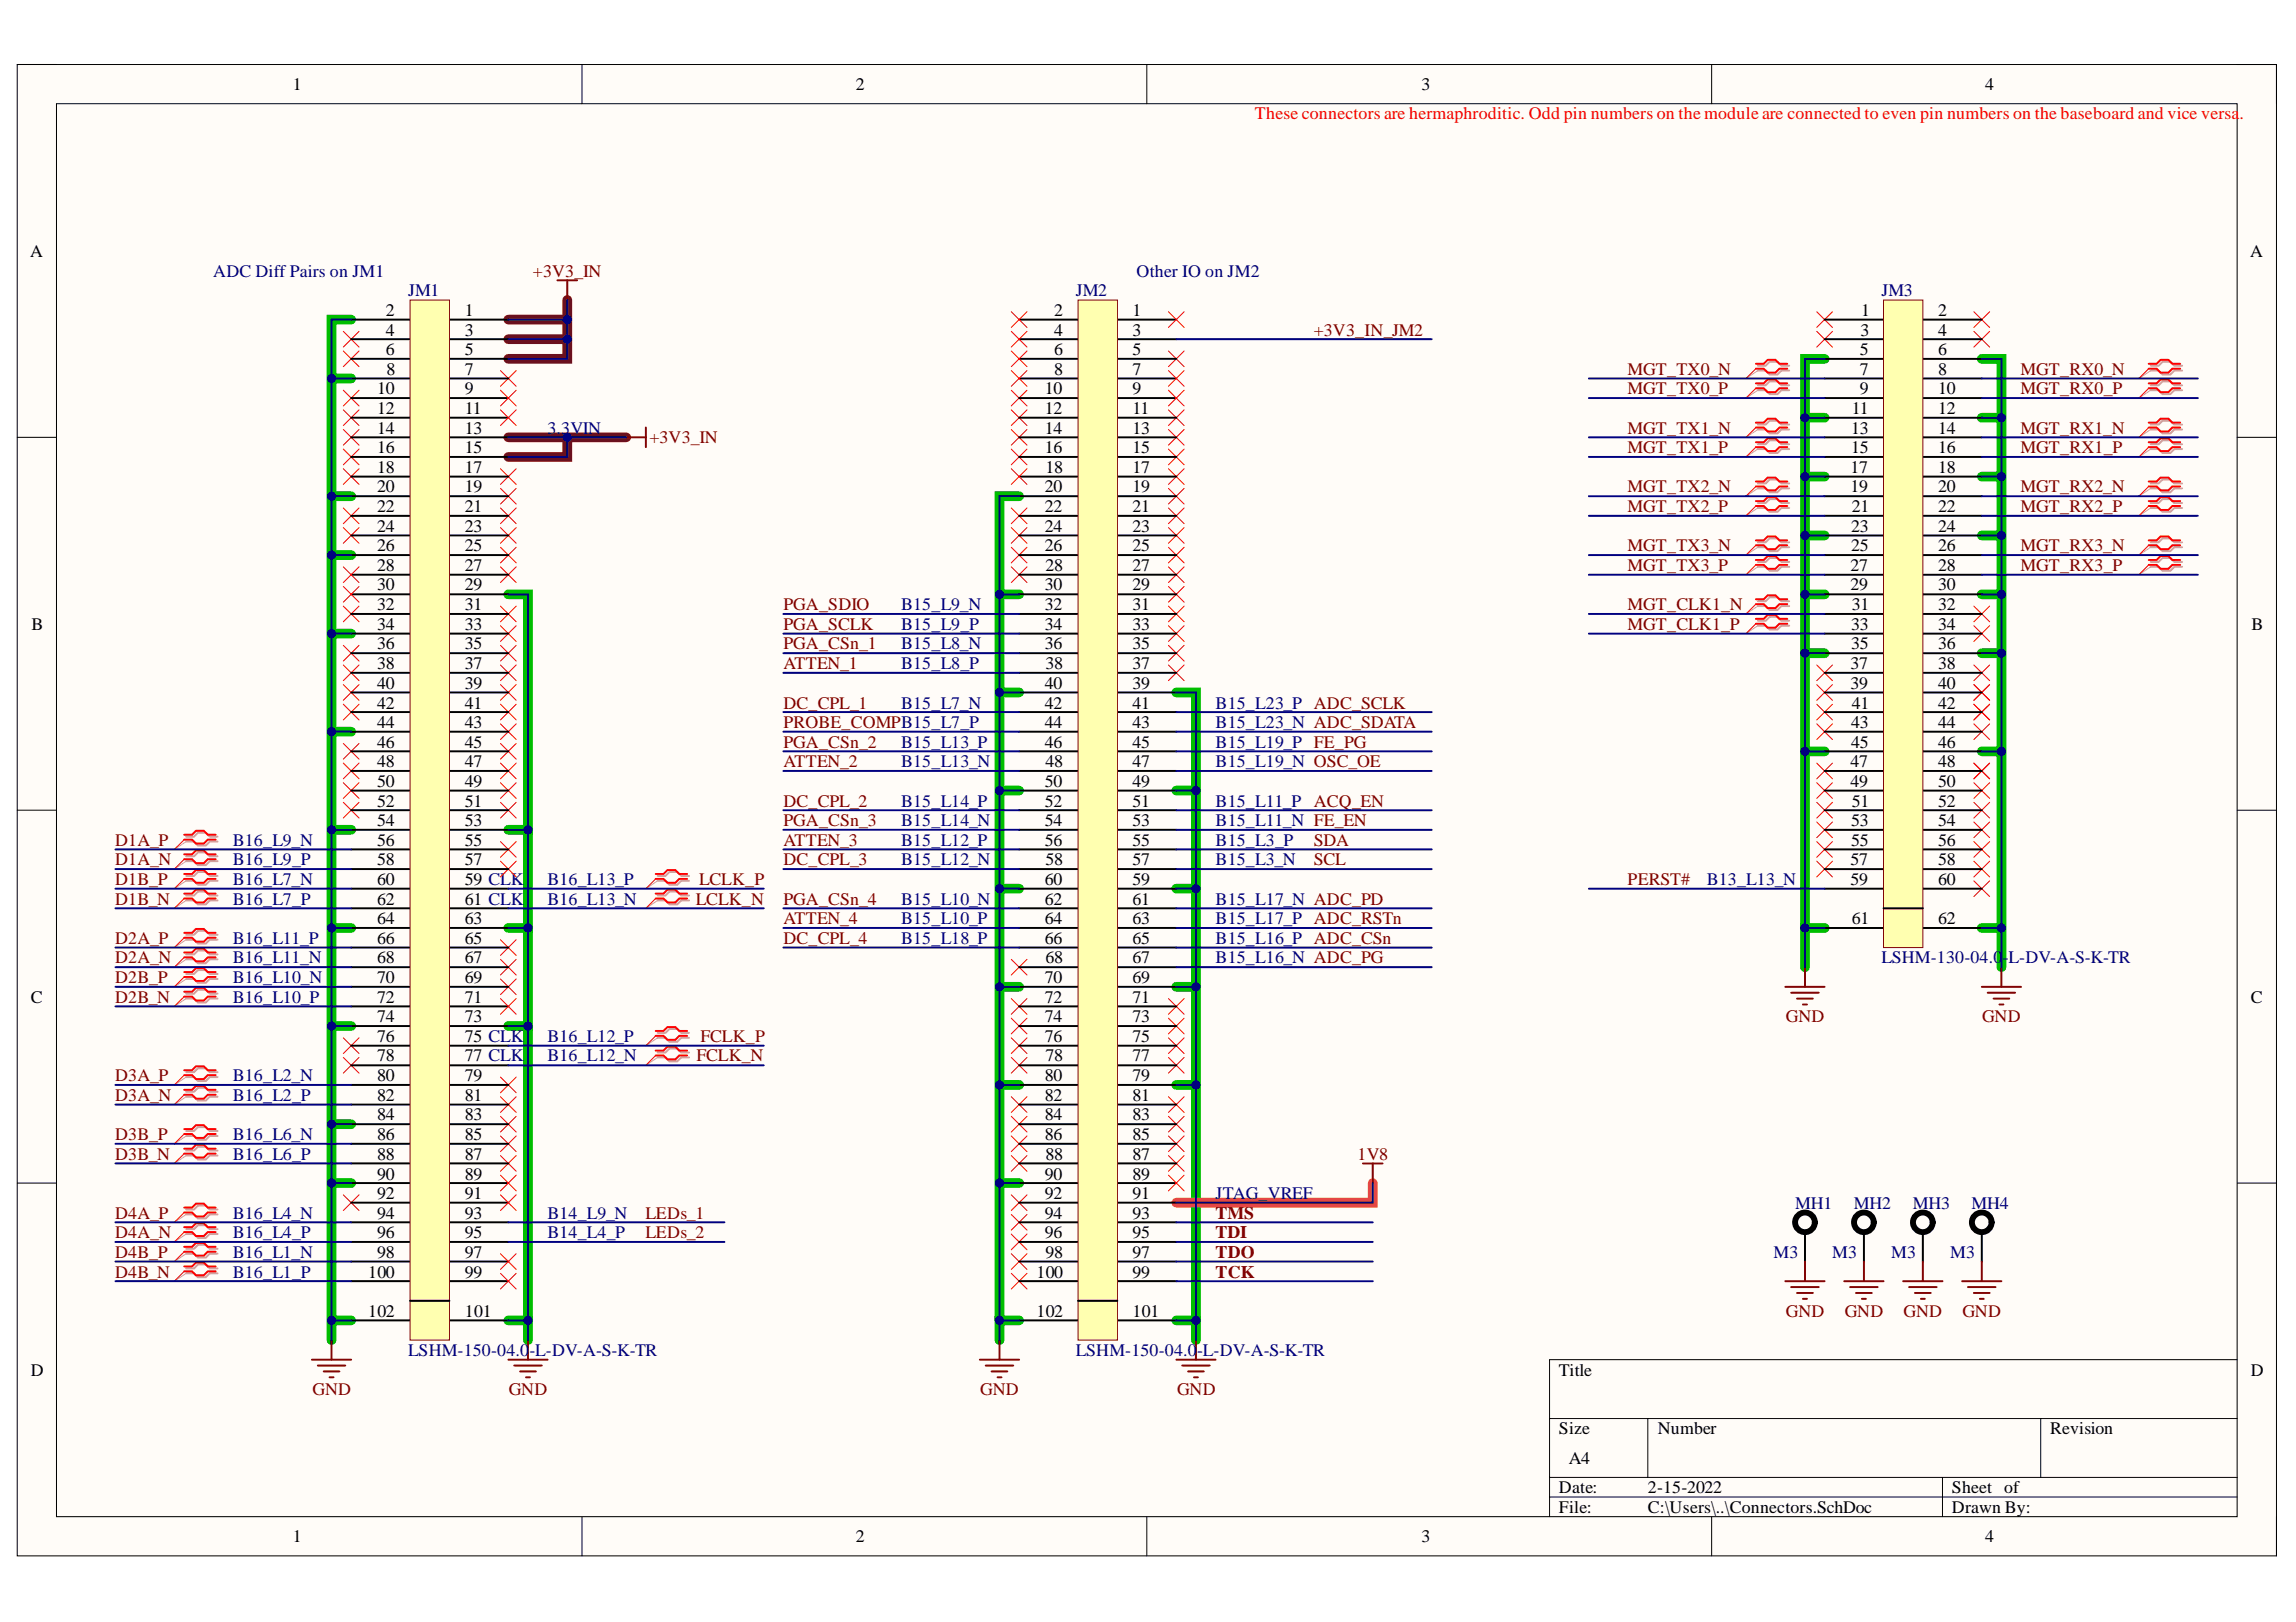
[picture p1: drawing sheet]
<svg xmlns="http://www.w3.org/2000/svg" width="297mm" height="210mm" viewBox="0 0 297 210" stroke-linecap="round" stroke-linejoin="round" font-family="sans-serif">
<defs><g id="words">
<g font-size="2.3">
<text x="37.9" y="11.7">1</text>
<text x="110.7" y="11.7">2</text>
<text x="183.9" y="11.7">3</text>
<text x="256.8" y="11.7">4</text>
<text x="3.9" y="33.3">A</text>
<text x="291.1" y="33.3">A</text>
<text x="49.9" y="40.9">2</text>
<text x="60.2" y="40.9">1</text>
<text x="136.4" y="40.9">2</text>
<text x="146.5" y="40.9">1</text>
<text x="240.8" y="40.9">1</text>
<text x="250.8" y="40.9">2</text>
<text x="49.9" y="43.4">4</text>
<text x="49.9" y="46">6</text>
<text x="60.2" y="43.4">3</text>
<text x="60.2" y="46">5</text>
<text x="136.4" y="43.4">4</text>
<text x="136.4" y="46">6</text>
<text x="146.5" y="43.4">3</text>
<text x="146.5" y="46">5</text>
<text x="240.6" y="46">5</text>
<text x="240.7" y="43.4">3</text>
<text x="250.8" y="43.4">4</text>
<text x="250.8" y="46">6</text>
<text x="48.8" y="51">10</text>
<text x="48.8" y="53.6">12</text>
<text x="50" y="48.5">8</text>
<text x="60.2" y="48.5">7</text>
<text x="60.2" y="51">9</text>
<text x="60.2" y="53.6">11</text>
<text x="135.2" y="51">10</text>
<text x="135.2" y="53.6">12</text>
<text x="136.4" y="48.5">8</text>
<text x="146.5" y="48.5">7</text>
<text x="146.5" y="51">9</text>
<text x="146.5" y="53.6">11</text>
<text x="239.6" y="53.6">11</text>
<text x="240.6" y="48.5">7</text>
<text x="240.6" y="51">9</text>
<text x="250.8" y="48.5">8</text>
<text x="250.8" y="51">10</text>
<text x="250.8" y="53.6">12</text>
<text x="48.8" y="56.1">14</text>
<text x="48.8" y="58.7">16</text>
<text x="60.2" y="56.1">13</text>
<text x="60.2" y="58.7">15</text>
<text x="135.2" y="56.1">14</text>
<text x="135.2" y="58.7">16</text>
<text x="146.5" y="56.1">13</text>
<text x="146.5" y="58.7">15</text>
<text x="239.5" y="56.1">13</text>
<text x="239.5" y="58.7">15</text>
<text x="250.8" y="56.1">14</text>
<text x="250.8" y="58.7">16</text>
<text x="48.8" y="61.2">18</text>
<text x="48.8" y="63.7">20</text>
<text x="60.2" y="61.2">17</text>
<text x="60.2" y="63.7">19</text>
<text x="135.2" y="63.7">20</text>
<text x="135.3" y="61.2">18</text>
<text x="146.5" y="61.2">17</text>
<text x="146.5" y="63.7">19</text>
<text x="239.4" y="61.2">17</text>
<text x="239.4" y="63.7">19</text>
<text x="250.8" y="61.2">18</text>
<text x="250.8" y="63.7">20</text>
<text x="48.8" y="66.3">22</text>
<text x="48.8" y="68.8">24</text>
<text x="48.8" y="71.3">26</text>
<text x="60.2" y="66.3">21</text>
<text x="60.2" y="68.8">23</text>
<text x="60.2" y="71.3">25</text>
<text x="135.2" y="66.3">22</text>
<text x="135.2" y="68.8">24</text>
<text x="135.2" y="71.3">26</text>
<text x="146.5" y="66.3">21</text>
<text x="146.5" y="68.8">23</text>
<text x="146.5" y="71.3">25</text>
<text x="239.5" y="68.8">23</text>
<text x="239.5" y="71.3">25</text>
<text x="239.6" y="66.3">21</text>
<text x="250.8" y="66.3">22</text>
<text x="250.8" y="68.8">24</text>
<text x="250.8" y="71.3">26</text>
<text x="48.8" y="73.9">28</text>
<text x="48.8" y="76.4">30</text>
<text x="60.2" y="73.9">27</text>
<text x="60.2" y="76.4">29</text>
<text x="135.2" y="76.4">30</text>
<text x="135.3" y="73.9">28</text>
<text x="146.5" y="73.9">27</text>
<text x="146.5" y="76.4">29</text>
<text x="239.4" y="73.9">27</text>
<text x="239.4" y="76.4">29</text>
<text x="250.8" y="73.9">28</text>
<text x="250.8" y="76.4">30</text>
<text x="4.1" y="81.5">B</text>
<text x="48.8" y="78.9">32</text>
<text x="48.8" y="81.5">34</text>
<text x="60.2" y="78.9">31</text>
<text x="60.2" y="81.5">33</text>
<text x="135.2" y="78.9">32</text>
<text x="135.2" y="81.5">34</text>
<text x="146.5" y="78.9">31</text>
<text x="146.5" y="81.5">33</text>
<text x="239.5" y="81.5">33</text>
<text x="239.6" y="78.9">31</text>
<text x="250.8" y="78.9">32</text>
<text x="250.8" y="81.5">34</text>
<text x="291.3" y="81.5">B</text>
<text x="48.8" y="84">36</text>
<text x="48.8" y="86.6">38</text>
<text x="48.8" y="89.2">40</text>
<text x="60.2" y="84">35</text>
<text x="60.2" y="86.6">37</text>
<text x="60.2" y="89.2">39</text>
<text x="135.2" y="84">36</text>
<text x="135.2" y="89.2">40</text>
<text x="135.3" y="86.6">38</text>
<text x="146.5" y="84">35</text>
<text x="146.5" y="86.6">37</text>
<text x="146.5" y="89.2">39</text>
<text x="239.4" y="86.6">37</text>
<text x="239.4" y="89.2">39</text>
<text x="239.5" y="84">35</text>
<text x="250.8" y="84">36</text>
<text x="250.8" y="86.6">38</text>
<text x="250.8" y="89.2">40</text>
<text x="48.8" y="91.7">42</text>
<text x="48.8" y="94.2">44</text>
<text x="60.2" y="91.7">41</text>
<text x="60.2" y="94.2">43</text>
<text x="135.2" y="91.7">42</text>
<text x="135.2" y="94.2">44</text>
<text x="146.5" y="91.7">41</text>
<text x="146.5" y="94.2">43</text>
<text x="239.5" y="94.2">43</text>
<text x="239.6" y="91.7">41</text>
<text x="250.8" y="91.7">42</text>
<text x="250.8" y="94.2">44</text>
<text x="48.8" y="96.8">46</text>
<text x="48.8" y="99.3">48</text>
<text x="48.8" y="101.9">50</text>
<text x="60.2" y="96.8">45</text>
<text x="60.2" y="99.3">47</text>
<text x="60.2" y="101.9">49</text>
<text x="135.2" y="96.8">46</text>
<text x="135.2" y="101.9">50</text>
<text x="135.3" y="99.3">48</text>
<text x="146.5" y="96.8">45</text>
<text x="146.5" y="99.3">47</text>
<text x="146.5" y="101.9">49</text>
<text x="239.4" y="99.3">47</text>
<text x="239.4" y="101.9">49</text>
<text x="239.5" y="96.8">45</text>
<text x="250.8" y="96.8">46</text>
<text x="250.8" y="99.3">48</text>
<text x="250.8" y="101.9">50</text>
<text x="48.8" y="104.4">52</text>
<text x="48.8" y="106.9">54</text>
<text x="60.2" y="104.4">51</text>
<text x="60.2" y="106.9">53</text>
<text x="135.2" y="104.4">52</text>
<text x="135.2" y="106.9">54</text>
<text x="146.5" y="104.4">51</text>
<text x="146.5" y="106.9">53</text>
<text x="239.5" y="106.9">53</text>
<text x="239.6" y="104.4">51</text>
<text x="250.8" y="104.4">52</text>
<text x="250.8" y="106.9">54</text>
<text x="48.8" y="109.5">56</text>
<text x="48.8" y="112">58</text>
<text x="60.2" y="109.5">55</text>
<text x="60.2" y="112">57</text>
<text x="135.2" y="109.5">56</text>
<text x="135.3" y="112">58</text>
<text x="146.5" y="109.5">55</text>
<text x="146.5" y="112">57</text>
<text x="239.4" y="112">57</text>
<text x="239.5" y="109.5">55</text>
<text x="250.8" y="109.5">56</text>
<text x="250.8" y="112">58</text>
<text x="48.8" y="114.5">60</text>
<text x="48.8" y="117.1">62</text>
<text x="48.8" y="119.6">64</text>
<text x="60.2" y="114.5">59 CLK</text>
<text x="60.2" y="117.1">61 CLK</text>
<text x="60.2" y="119.6">63</text>
<text x="135.2" y="114.5">60</text>
<text x="135.2" y="117.1">62</text>
<text x="135.2" y="119.6">64</text>
<text x="146.5" y="114.5">59</text>
<text x="146.5" y="117.1">61</text>
<text x="146.5" y="119.6">63</text>
<text x="239.4" y="114.5">59</text>
<text x="239.6" y="119.6">61</text>
<text x="250.8" y="114.5">60</text>
<text x="250.8" y="119.6">62</text>
<text x="48.8" y="122.1">66</text>
<text x="48.8" y="124.7">68</text>
<text x="60.2" y="122.1">65</text>
<text x="60.2" y="124.7">67</text>
<text x="135.2" y="122.1">66</text>
<text x="135.3" y="124.7">68</text>
<text x="146.5" y="122.1">65</text>
<text x="146.5" y="124.7">67</text>
<text x="4" y="129.7">C</text>
<text x="48.8" y="127.2">70</text>
<text x="48.8" y="129.7">72</text>
<text x="60.2" y="127.2">69</text>
<text x="60.2" y="129.7">71</text>
<text x="135.2" y="127.2">70</text>
<text x="135.2" y="129.7">72</text>
<text x="146.5" y="127.2">69</text>
<text x="146.5" y="129.7">71</text>
<text x="291.2" y="129.7">C</text>
<text x="48.8" y="132.3">74</text>
<text x="48.8" y="134.8">76</text>
<text x="48.8" y="137.4">78</text>
<text x="60.2" y="132.3">73</text>
<text x="60.2" y="134.8">75 CLK</text>
<text x="60.2" y="137.4">77 CLK</text>
<text x="135.2" y="132.3">74</text>
<text x="135.2" y="134.8">76</text>
<text x="135.3" y="137.4">78</text>
<text x="146.5" y="132.3">73</text>
<text x="146.5" y="134.8">75</text>
<text x="146.5" y="137.4">77</text>
<text x="48.8" y="139.9">80</text>
<text x="48.8" y="142.4">82</text>
<text x="60.2" y="139.9">79</text>
<text x="60.2" y="142.4">81</text>
<text x="135.2" y="139.9">80</text>
<text x="135.2" y="142.4">82</text>
<text x="146.5" y="139.9">79</text>
<text x="146.5" y="142.4">81</text>
<text x="48.8" y="145">84</text>
<text x="48.8" y="147.5">86</text>
<text x="60.2" y="145">83</text>
<text x="60.2" y="147.5">85</text>
<text x="135.2" y="145">84</text>
<text x="135.2" y="147.5">86</text>
<text x="146.5" y="145">83</text>
<text x="146.5" y="147.5">85</text>
<text x="48.8" y="150.1">88</text>
<text x="48.8" y="152.7">90</text>
<text x="48.8" y="155.2">92</text>
<text x="60.2" y="150.1">87</text>
<text x="60.2" y="152.7">89</text>
<text x="60.2" y="155.2">91</text>
<text x="135.2" y="152.7">90</text>
<text x="135.2" y="155.2">92</text>
<text x="135.3" y="150.1">88</text>
<text x="146.5" y="150.1">87</text>
<text x="146.5" y="152.7">89</text>
<text x="146.5" y="155.2">91</text>
<text x="48.8" y="157.7">94</text>
<text x="48.8" y="160.3">96</text>
<text x="60.2" y="157.7">93</text>
<text x="60.2" y="160.3">95</text>
<text x="135.2" y="157.7">94</text>
<text x="135.2" y="160.3">96</text>
<text x="146.5" y="157.7">93</text>
<text x="146.5" y="160.3">95</text>
<text x="47.6" y="165.3">100</text>
<text x="48.8" y="162.8">98</text>
<text x="60.2" y="162.8">97</text>
<text x="60.2" y="165.3">99</text>
<text x="134.1" y="165.3">100</text>
<text x="135.3" y="162.8">98</text>
<text x="146.5" y="162.8">97</text>
<text x="146.5" y="165.3">99</text>
<text x="47.6" y="170.4">102</text>
<text x="60.2" y="170.4">101</text>
<text x="134.1" y="170.4">102</text>
<text x="146.5" y="170.4">101</text>
<text x="4" y="178">D</text>
<text x="201.7" y="178">Title</text>
<text x="291.2" y="178">D</text>
<text x="201.7" y="185.6">Size</text>
<text x="214.5" y="185.6">Number</text>
<text x="265.2" y="185.6">Revision</text>
<text x="203" y="189.4">A4</text>
<text x="201.7" y="193.2">Date:</text>
<text x="201.7" y="195.8">File:</text>
<text x="213.2" y="193.2">2-15-2022</text>
<text x="213.2" y="195.8">C:\Users\..\Connectors.SchDoc</text>
<text x="252.5" y="193.2">Sheet of</text>
<text x="252.5" y="195.8">Drawn By:</text>
<text x="37.9" y="199.6">1</text>
<text x="110.7" y="199.6">2</text>
<text x="183.9" y="199.6">3</text>
<text x="256.8" y="199.6">4</text>
</g>
<text font-size="2.3" fill="#f00" x="162.3" y="15.5">These connectors are hermaphroditic. Odd pin numbers on the module are connected to even pin numbers on the baseboard and vice versa.</text>
<g font-size="2.3" fill="#000080">
<text x="27.6" y="35.8">ADC Diff Pairs on JM1</text>
<text x="147" y="35.8">Other IO on JM2</text>
<text x="52.8" y="38.4">JM1</text>
<text x="139.2" y="38.4">JM2</text>
<text x="243.4" y="38.4">JM3</text>
<text x="70.8" y="56.1">3.3VIN</text>
<text x="116.6" y="78.9">B15_L9_N</text>
<text x="116.6" y="81.5">B15_L9_P</text>
<text x="116.6" y="84">B15_L8_N</text>
<text x="116.6" y="86.6">B15_L8_P</text>
<text x="116.6" y="91.7">B15_L7_N</text>
<text x="157.3" y="91.7">B15_L23_P ADC_SCLK</text>
<text x="157.3" y="94.2">B15_L23_N ADC_SDATA</text>
<text x="116.6" y="96.8">B15_L13_P</text>
<text x="116.6" y="99.3">B15_L13_N</text>
<text x="157.3" y="96.8">B15_L19_P FE_PG</text>
<text x="157.3" y="99.3">B15_L19_N OSC_OE</text>
<text x="116.6" y="104.4">B15_L14_P</text>
<text x="116.6" y="106.9">B15_L14_N</text>
<text x="157.3" y="104.4">B15_L11_P ACQ_EN</text>
<text x="157.3" y="106.9">B15_L11_N FE_EN</text>
<text x="30.1" y="109.5">B16_L9_N</text>
<text x="30.1" y="112">B16_L9_P</text>
<text x="116.6" y="109.5">B15_L12_P</text>
<text x="116.6" y="112">B15_L12_N</text>
<text x="157.3" y="109.5">B15_L3_P</text>
<text x="157.3" y="112">B15_L3_N</text>
<text x="30.1" y="114.5">B16_L7_N</text>
<text x="30.1" y="117.1">B16_L7_P</text>
<text x="70.8" y="114.5">B16_L13_P</text>
<text x="70.8" y="117.1">B16_L13_N</text>
<text x="116.6" y="117.1">B15_L10_N</text>
<text x="116.6" y="119.6">B15_L10_P</text>
<text x="157.3" y="117.1">B15_L17_N ADC_PD</text>
<text x="157.3" y="119.6">B15_L17_P ADC_RSTn</text>
<text x="220.8" y="114.5">B13_L13_N</text>
<text x="30.1" y="122.1">B16_L11_P</text>
<text x="30.1" y="124.7">B16_L11_N</text>
<text x="116.6" y="122.1">B15_L18_P</text>
<text x="157.3" y="122.1">B15_L16_P ADC_CSn</text>
<text x="157.3" y="124.7">B15_L16_N ADC_PG</text>
<text x="243.4" y="124.7">LSHM-130-04.0</text>
<text x="259.1" y="124.7">-L-DV-A-S-K-TR</text>
<text x="30.1" y="127.2">B16_L10_N</text>
<text x="30.1" y="129.7">B16_L10_P</text>
<text x="70.8" y="134.8">B16_L12_P</text>
<text x="70.8" y="137.4">B16_L12_N</text>
<text x="30.1" y="139.9">B16_L2_N</text>
<text x="30.1" y="142.4">B16_L2_P</text>
<text x="30.1" y="147.5">B16_L6_N</text>
<text x="30.1" y="150.1">B16_L6_P</text>
<text x="157.3" y="155.2">JTAG_VREF</text>
<text x="30.1" y="157.7">B16_L4_N</text>
<text x="30.1" y="160.3">B16_L4_P</text>
<text x="70.8" y="157.7">B14_L9_N</text>
<text x="70.8" y="160.3">B14_L4_P</text>
<text x="232.2" y="156.5">MH1</text>
<text x="239.8" y="156.5">MH2</text>
<text x="247.5" y="156.5">MH3</text>
<text x="255.1" y="156.5">MH4</text>
<text x="30.1" y="162.8">B16_L1_N</text>
<text x="30.1" y="165.3">B16_L1_P</text>
<text x="229.4" y="162.8">M3</text>
<text x="237" y="162.8">M3</text>
<text x="244.7" y="162.8">M3</text>
<text x="252.3" y="162.8">M3</text>
<text x="52.8" y="175.5">LSHM-150-04.0</text>
<text x="68.5" y="175.5">-L-DV-A-S-K-TR</text>
<text x="139.2" y="175.5">LSHM-150-04.0</text>
<text x="154.9" y="175.5">-L-DV-A-S-K-TR</text>
</g>
<g font-size="2.3" fill="#800000">
<text x="68.9" y="35.8">+3V3_IN</text>
<text x="170" y="43.4">+3V3_IN_JM2</text>
<text x="210.6" y="48.5">MGT_TX0_N</text>
<text x="210.6" y="51">MGT_TX0_P</text>
<text x="261.4" y="48.5">MGT_RX0_N</text>
<text x="261.4" y="51">MGT_RX0_P</text>
<text x="84" y="57.4">+3V3_IN</text>
<text x="210.6" y="56.1">MGT_TX1_N</text>
<text x="210.6" y="58.7">MGT_TX1_P</text>
<text x="261.4" y="56.1">MGT_RX1_N</text>
<text x="261.4" y="58.7">MGT_RX1_P</text>
<text x="210.6" y="63.7">MGT_TX2_N</text>
<text x="261.4" y="63.7">MGT_RX2_N</text>
<text x="210.6" y="71.3">MGT_TX3_N</text>
<text x="210.6" y="66.3">MGT_TX2_P</text>
<text x="261.4" y="66.3">MGT_RX2_P</text>
<text x="261.4" y="71.3">MGT_RX3_N</text>
<text x="210.6" y="73.9">MGT_TX3_P</text>
<text x="261.4" y="73.9">MGT_RX3_P</text>
<text x="101.4" y="78.9">PGA_SDIO</text>
<text x="101.4" y="81.5">PGA_SCLK</text>
<text x="210.6" y="78.9">MGT_CLK1_N</text>
<text x="210.6" y="81.5">MGT_CLK1_P</text>
<text x="101.4" y="84">PGA_CSn_1</text>
<text x="101.4" y="86.6">ATTEN_1</text>
<text x="101.4" y="91.7">DC_CPL_1</text>
<text x="101.4" y="94.2">PROBE_COMPB15_L7_P</text>
<text x="101.4" y="96.8">PGA_CSn_2</text>
<text x="101.4" y="99.3">ATTEN_2</text>
<text x="101.4" y="104.4">DC_CPL_2</text>
<text x="101.4" y="106.9">PGA_CSn_3</text>
<text x="14.9" y="109.5">D1A_P</text>
<text x="14.9" y="112">D1A_N</text>
<text x="101.4" y="109.5">ATTEN_3</text>
<text x="101.4" y="112">DC_CPL_3</text>
<text x="170" y="109.5">SDA</text>
<text x="170" y="112">SCL</text>
<text x="14.9" y="114.5">D1B_P</text>
<text x="14.9" y="117.1">D1B_N</text>
<text x="90" y="117.1">LCLK_N</text>
<text x="90.4" y="114.5">LCLK_P</text>
<text x="101.4" y="117.1">PGA_CSn_4</text>
<text x="101.4" y="119.6">ATTEN_4</text>
<text x="210.6" y="114.5">PERST#</text>
<text x="14.9" y="122.1">D2A_P</text>
<text x="14.9" y="124.7">D2A_N</text>
<text x="101.4" y="122.1">DC_CPL_4</text>
<text x="14.9" y="127.2">D2B_P</text>
<text x="14.9" y="129.7">D2B_N</text>
<text x="90.1" y="137.4">FCLK_N</text>
<text x="90.6" y="134.8">FCLK_P</text>
<text x="231" y="132.3">GND</text>
<text x="256.4" y="132.3">GND</text>
<text x="14.9" y="139.9">D3A_P</text>
<text x="14.9" y="142.4">D3A_N</text>
<text x="14.9" y="147.5">D3B_P</text>
<text x="14.9" y="150.1">D3B_N</text>
<text x="175.6" y="150.1">1V8</text>
<text x="14.9" y="157.7">D4A_P</text>
<text x="14.9" y="160.3">D4A_N</text>
<text x="83.5" y="157.7">LEDs_1</text>
<text x="83.5" y="160.3">LEDs_2</text>
<text x="157.3" y="160.3">TDI</text>
<text x="157.3" y="157.7">TMS</text>
<text x="14.9" y="162.8">D4B_P</text>
<text x="14.9" y="165.3">D4B_N</text>
<text x="157.3" y="165.3">TCK</text>
<text x="157.3" y="162.8">TDO</text>
<text x="231" y="170.4">GND</text>
<text x="238.7" y="170.4">GND</text>
<text x="246.3" y="170.4">GND</text>
<text x="253.9" y="170.4">GND</text>
<text x="40.4" y="180.6">GND</text>
<text x="65.8" y="180.6">GND</text>
<text x="126.8" y="180.6">GND</text>
<text x="152.3" y="180.6">GND</text>
</g>
</g></defs>
<path d="M2.2 8.3h292.3v193h-292.3z" fill-rule="evenodd" fill="#fffcf8"/>
<path d="M2.2 8.3h292.3v193h-292.3z" fill="none" stroke="#000" stroke-width=".13"/>
<path d="M7.3 13.4h282.1v182.9h-282.1z" fill-rule="evenodd" fill="#fffcf8"/>
<g fill="none" stroke="#000" stroke-width=".13">
<path d="M2.2 8.3h5.1M7.3 13.4h282.1v182.9h-282.1zM75.3 8.3v5.1M148.4 8.3v5.1M221.4 8.3v5.1M289.4 8.3h5.1v5.1M2.2 56.6h5.1M289.4 56.6h5.1M2.2 104.8h5.1M289.4 104.9h5.1M2.2 153.1h5.1M289.4 153.1h5.1"/>
<path d="M289.4 176h-88.9v20.3M75.3 196.3v5M148.4 196.3v5M200.5 183.6h88.9M200.5 191.2h88.9M200.5 193.7h88.9M213.2 183.6v7.6M221.4 196.3v5M251.3 191.2v5.1M264 183.6v7.6M294.5 196.3v5"/>
</g>
<g fill="none" stroke="#00be00" stroke-width="1.3">
<path d="M42.9 49h2.5M45.4 41.4h-2.5v129.5M233.5 54.1h2.6M236.1 46.4h-2.6v73.7M256.4 46.4h2.5v73.7M256.4 54.1h2.5M42.9 64.2h2.5M42.9 71.8h2.5M65.8 76.9h2.5v30.5h-2.5M129.3 76.9h2.5M131.8 64.2h-2.5v106.7M233.5 76.9h2.6"/>
<path d="M233.5 61.7h2.6M233.5 69.3h2.6M256.4 76.9h2.5M256.4 61.7h2.5M256.4 69.3h2.5M42.9 82h2.5M42.9 94.7h2.5M129.3 89.6h2.5M152.2 89.6h2.5v81.3M233.5 84.5h2.6M233.5 97.2h2.6M256.4 84.5h2.5"/>
<path d="M256.4 97.2h2.5M42.9 107.4h2.5M68.3 107.4v12.7h-2.5M129.3 102.3h2.5M129.3 115h2.5M152.2 102.3h2.5M152.2 115h2.5M42.9 120.1h2.5M42.9 132.8h2.5M68.3 120.1v12.7h-2.5M68.3 132.8v38.1M129.3 127.7h2.5"/>
<path d="M152.2 127.7h2.5M236.1 120.1h-2.6v5.1M256.4 120.1h2.5v5.1M42.9 145.5h2.5M42.9 153.1h2.5M129.3 153.1h2.5M129.3 140.4h2.5M152.2 140.4h2.5M45.4 170.9h-2.5v2.5M65.8 170.9h2.5v2.5M131.8 170.9h-2.5v2.5M152.2 170.9h2.5v2.5"/>
</g>
<path d="M73.4 38.8v7.6h-7.6M65.8 56.6h15.2M65.8 43.9h7.6M65.8 41.4h7.6M73.4 56.6v2.5h-7.6" fill="none" stroke="#781915" stroke-width="1.3"/>
<path d="M177.6 153.1v2.5h-25.4" fill="none" stroke="#fd8300" stroke-width="1.3"/>
<g fill="none" stroke="#800000" stroke-width=".25">
<path d="M72.1 36.3h2.6M73.4 36.3v2.5M231 127.7h5.1M231.7 128.5h3.6M232.5 129.2h2M233.3 130h.5M233.5 125.2v2.5M256.4 127.7h5.1M257.2 128.5h3.5M257.9 129.2h2M258.7 130h.5M258.9 125.2v2.5"/>
<path d="M40.4 176h5M41.1 176.7h3.6M41.9 177.5h2M42.6 178.2h.5M42.9 173.4v2.6M65.8 176h5.1M66.5 176.7h3.6M67.3 177.5h2M68 178.2h.6M68.3 173.4v2.6M126.8 176h5M127.5 176.7h3.6"/>
<path d="M128.3 177.5h2M129.1 178.2h.5M129.3 173.4v2.6M152.2 176h5.1M152.9 176.7h3.6M153.7 177.5h2M154.5 178.2h.5M154.7 173.4v2.6"/>
</g>
<g fill="none" stroke="#f00" stroke-width=".13">
<path d="M44.4 42.9l2.1 2M44.4 45.4l2.1 2.1M44.4 50.5l2.1 2M44.4 53l2.1 2.1M44.4 58.1l2.1 2.1M44.4 55.6l2.1 2M46.5 42.9l-2.1 2M46.5 45.4l-2.1 2.1M46.5 50.5l-2.1 2M46.5 53l-2.1 2.1M46.5 58.1l-2.1 2.1M46.5 55.6l-2.1 2"/>
<path d="M64.7 48l2.1 2M66.8 48l-2.1 2M130.8 50.5l2.1 2M130.8 55.6l2.1 2M130.8 58.1l2.1 2.1M130.8 53l2.1 2.1M132.9 50.5l-2.1 2M132.9 55.6l-2.1 2M132.9 58.1l-2.1 2.1M132.9 53l-2.1 2.1M151.2 45.4l2 2.1M151.2 53l2 2.1"/>
<path d="M151.2 55.6l2 2M151.2 58.1l2 2.1M153.2 45.4l-2 2.1M153.2 53l-2 2.1M153.2 55.6l-2 2M153.2 58.1l-2 2.1M227.2 47.7l-1.3 1.3M235 40.3l2.1 2.1M235 42.9l2.1 2M237.1 40.3l-2.1 2.1M237.1 42.9l-2.1 2M255.4 40.3l2 2.1"/>
<path d="M255.4 42.9l2 2M257.4 40.3l-2 2.1M257.4 42.9l-2 2M44.4 60.7l2.1 2M44.4 65.7l2.1 2.1M44.4 68.3l2.1 2M44.4 78.4l2.1 2.1M46.5 60.7l-2.1 2M46.5 65.7l-2.1 2.1M46.5 68.3l-2.1 2M46.5 78.4l-2.1 2.1M64.7 73.4l2.1 2"/>
<path d="M64.7 60.7l2.1 2M64.7 63.2l2.1 2M64.7 65.7l2.1 2.1M64.7 68.3l2.1 2M64.7 70.8l2.1 2M64.7 78.4l2.1 2.1M66.8 60.7l-2.1 2M66.8 63.2l-2.1 2M66.8 65.7l-2.1 2.1M66.8 68.3l-2.1 2M66.8 70.8l-2.1 2M66.8 73.4l-2.1 2"/>
<path d="M66.8 78.4l-2.1 2.1M130.8 65.7l2.1 2.1M130.8 68.3l2.1 2M130.8 70.8l2.1 2M130.8 73.4l2.1 2M132.9 65.7l-2.1 2.1M132.9 68.3l-2.1 2M132.9 70.8l-2.1 2M132.9 73.4l-2.1 2M151.2 63.2l2 2M151.2 75.9l2 2M151.2 60.7l2 2"/>
<path d="M151.2 65.7l2 2.1M151.2 68.3l2 2M151.2 70.8l2 2M151.2 73.4l2 2M151.2 78.4l2 2.1M153.2 63.2l-2 2M153.2 75.9l-2 2M153.2 60.7l-2 2M153.2 65.7l-2 2.1M153.2 68.3l-2 2M153.2 70.8l-2 2M153.2 73.4l-2 2"/>
<path d="M153.2 78.4l-2 2.1M255.4 78.4l2 2.1M257.4 78.4l-2 2.1M44.4 83.5l2.1 2M44.4 86.1l2.1 2M44.4 88.6l2.1 2M44.4 91.1l2.1 2.1M44.4 96.2l2.1 2M44.4 98.8l2.1 2M46.5 86.1l-2.1 2M46.5 91.1l-2.1 2.1M46.5 83.5l-2.1 2"/>
<path d="M46.5 88.6l-2.1 2M46.5 96.2l-2.1 2M46.5 98.8l-2.1 2M64.7 88.6l2.1 2M64.7 81l2.1 2M64.7 83.5l2.1 2M64.7 86.1l2.1 2M64.7 91.1l2.1 2.1M64.7 93.7l2.1 2M64.7 96.2l2.1 2M64.7 98.8l2.1 2M66.8 88.6l-2.1 2"/>
<path d="M66.8 81l-2.1 2M66.8 83.5l-2.1 2M66.8 86.1l-2.1 2M66.8 91.1l-2.1 2.1M66.8 93.7l-2.1 2M66.8 96.2l-2.1 2M66.8 98.8l-2.1 2M151.2 81l2 2M151.2 83.5l2 2M151.2 86.1l2 2M153.2 81l-2 2M153.2 83.5l-2 2"/>
<path d="M153.2 86.1l-2 2M235 86.1l2.1 2M235 88.6l2.1 2M235 91.1l2.1 2.1M235 93.7l2.1 2M235 98.8l2.1 2M237.1 86.1l-2.1 2M237.1 88.6l-2.1 2M237.1 91.1l-2.1 2.1M237.1 93.7l-2.1 2M237.1 98.8l-2.1 2M255.4 86.1l2 2"/>
<path d="M255.4 88.6l2 2M255.4 91.1l2 2.1M255.4 93.7l2 2M255.4 98.8l2 2M255.4 81l2 2M257.4 88.6l-2 2M257.4 86.1l-2 2M257.4 91.1l-2 2.1M257.4 93.7l-2 2M257.4 98.8l-2 2M257.4 81l-2 2M44.4 101.3l2.1 2"/>
<path d="M44.4 103.8l2.1 2.1M46.5 101.3l-2.1 2M46.5 103.8l-2.1 2.1M64.7 111.4l2.1 2.1M64.7 101.3l2.1 2M64.7 103.8l2.1 2.1M64.7 108.9l2.1 2M66.8 101.3l-2.1 2M66.8 103.8l-2.1 2.1M66.8 108.9l-2.1 2M66.8 111.4l-2.1 2.1M235 108.9l2.1 2"/>
<path d="M235 101.3l2.1 2M235 103.8l2.1 2.1M235 106.4l2.1 2M237.1 108.9l-2.1 2M237.1 101.3l-2.1 2M237.1 103.8l-2.1 2.1M237.1 106.4l-2.1 2M255.4 108.9l2 2M255.4 111.4l2 2.1M255.4 114l2 2M255.4 101.3l2 2M255.4 106.4l2 2"/>
<path d="M255.4 103.8l2 2.1M257.4 108.9l-2 2M257.4 111.4l-2 2.1M257.4 114l-2 2M257.4 101.3l-2 2M257.4 106.4l-2 2M257.4 103.8l-2 2.1M44.4 134.3l2.1 2M44.4 136.8l2.1 2.1M46.5 134.3l-2.1 2M46.5 136.8l-2.1 2.1M64.7 139.4l2.1 2"/>
<path d="M64.7 124.1l2.1 2.1M64.7 121.6l2.1 2M64.7 126.7l2.1 2M66.8 139.4l-2.1 2M66.8 121.6l-2.1 2M66.8 124.1l-2.1 2.1M66.8 126.7l-2.1 2M130.8 124.1l2.1 2.1M130.8 129.2l2.1 2.1M130.8 131.8l2.1 2M130.8 134.3l2.1 2M130.8 136.8l2.1 2.1"/>
<path d="M132.9 124.1l-2.1 2.1M132.9 129.2l-2.1 2.1M132.9 131.8l-2.1 2M132.9 134.3l-2.1 2M132.9 136.8l-2.1 2.1M151.2 129.2l2 2.1M151.2 131.8l2 2M151.2 134.3l2 2M151.2 136.8l2 2.1M153.2 136.8l-2 2.1M153.2 129.2l-2 2.1M153.2 131.8l-2 2"/>
<path d="M153.2 134.3l-2 2M44.4 154.6l2.1 2.1M46.5 154.6l-2.1 2.1M64.7 141.9l2.1 2.1M64.7 144.5l2.1 2M64.7 147l2.1 2M64.7 149.5l2.1 2.1M66.8 141.9l-2.1 2.1M66.8 144.5l-2.1 2M66.8 147l-2.1 2M66.8 149.5l-2.1 2.1M130.8 141.9l2.1 2.1"/>
<path d="M130.8 144.5l2.1 2M130.8 147l2.1 2M130.8 149.5l2.1 2.1M130.8 154.6l2.1 2.1M130.8 157.2l2.1 2M130.8 159.7l2.1 2M132.9 141.9l-2.1 2.1M132.9 144.5l-2.1 2M132.9 147l-2.1 2M132.9 149.5l-2.1 2.1M132.9 154.6l-2.1 2.1M132.9 157.2l-2.1 2"/>
<path d="M132.9 159.7l-2.1 2M151.2 141.9l2 2.1M151.2 144.5l2 2M151.2 147l2 2M151.2 149.5l2 2.1M153.2 141.9l-2 2.1M153.2 144.5l-2 2M153.2 147l-2 2M153.2 149.5l-2 2.1M130.8 162.2l2.1 2.1M130.8 164.8l2.1 2M132.9 162.2l-2.1 2.1"/>
<path d="M132.9 164.8l-2.1 2"/>
</g>
<path d="M227.4 47.3h1l.5-.5h1.1l.5 .5h1M227.4 48h1l.5 .5h1.1l.5-.5h1" fill="none" stroke="#d0a19e" stroke-width=".25"/>
<path d="M227.4 48l-1.5 1" fill="none" stroke="#d0a19e" stroke-width=".13"/>
<path d="M227.2 47.1h1l.5-.5h1l.5 .5h1M227.2 47.7h1l.5 .5h1l.5-.5h1" fill="none" stroke="#f00" stroke-width=".25"/>
<g fill="none" stroke="#000" stroke-width=".25">
<path d="M45.4 41.4h7.7M45.4 43.9h7.7M45.4 46.4h7.7M45.4 49h7.7M45.4 51.5h7.7M45.4 54.1h7.7M45.4 56.6h7.7M45.4 59.1h7.7M58.1 41.4h7.7M58.1 43.9h7.7M58.1 46.4h7.7M58.1 49h7.7"/>
<path d="M58.1 51.5h7.7M58.1 54.1h7.7M58.1 56.6h7.7M58.1 59.1h7.7M45.4 61.7h7.7M45.4 64.2h7.7M45.4 66.8h7.7M45.4 69.3h7.7M45.4 71.8h7.7M45.4 74.4h7.7M45.4 76.9h7.7M45.4 79.5h7.7"/>
<path d="M58.1 61.7h7.7M58.1 64.2h7.7M58.1 66.8h7.7M58.1 69.3h7.7M58.1 71.8h7.7M58.1 74.4h7.7M58.1 76.9h7.7M58.1 79.5h7.7M45.4 82h7.7M45.4 84.5h7.7M45.4 87.1h7.7M45.4 89.6h7.7"/>
<path d="M45.4 92.1h7.7M45.4 94.7h7.7M45.4 97.2h7.7M45.4 99.8h7.7M58.1 82h7.7M58.1 84.5h7.7M58.1 87.1h7.7M58.1 89.6h7.7M58.1 92.1h7.7M58.1 94.7h7.7M58.1 97.2h7.7M58.1 99.8h7.7"/>
<path d="M45.4 102.3h7.7M45.4 104.8h7.7M45.4 107.4h7.7M45.4 109.9h7.7M45.4 112.5h7.7M45.4 115h7.7M45.4 117.5h7.7M58.1 102.3h7.7M58.1 104.8h7.7M58.1 107.4h7.7M58.1 109.9h7.7M58.1 112.5h7.7"/>
<path d="M58.1 115h7.7M58.1 117.5h7.7M45.4 120.1h7.7M45.4 122.6h7.7M45.4 125.2h7.7M45.4 127.7h7.7M45.4 130.2h7.7M45.4 132.8h7.7M45.4 135.3h7.7M45.4 137.9h7.7M58.1 120.1h7.7M58.1 122.6h7.7"/>
<path d="M58.1 125.2h7.7M58.1 127.7h7.7M58.1 130.2h7.7M58.1 132.8h7.7M58.1 135.3h7.7M58.1 137.9h7.7M45.4 140.4h7.7M45.4 142.9h7.7M45.4 145.5h7.7M45.4 148h7.7M45.4 150.6h7.7M45.4 153.1h7.7"/>
<path d="M45.4 155.6h7.7M45.4 158.2h7.7M58.1 140.4h7.7M58.1 142.9h7.7M58.1 145.5h7.7M58.1 148h7.7M58.1 150.6h7.7M58.1 153.1h7.7M58.1 155.6h7.7M58.1 158.2h7.7M45.4 160.7h7.7M45.4 163.3h7.7"/>
<path d="M45.4 165.8h7.7M45.4 170.9h7.7M58.1 160.7h7.7M58.1 163.3h7.7M58.1 165.8h7.7M58.1 170.9h7.7"/>
</g>
<path d="M53.1 38.8h5v134.6h-5z" fill-rule="evenodd" fill="#ffffb0"/>
<path d="M53.1 38.8h5v134.6h-5z" fill="none" stroke="#800000" stroke-width=".13"/>
<g fill="none" stroke="#000" stroke-width=".25">
<path d="M131.8 41.4h7.7M131.8 43.9h7.7M131.8 46.4h7.7M131.8 49h7.7M131.8 51.5h7.7M131.8 54.1h7.7M131.8 56.6h7.7M131.8 59.1h7.7M144.6 41.4h7.6M144.6 43.9h7.6M144.6 46.4h7.6M144.6 49h7.6"/>
<path d="M144.6 51.5h7.6M144.6 54.1h7.6M144.6 56.6h7.6M144.6 59.1h7.6M131.8 61.7h7.7M131.8 64.2h7.7M131.8 66.8h7.7M131.8 69.3h7.7M131.8 71.8h7.7M131.8 74.4h7.7M131.8 76.9h7.7M131.8 79.5h7.7"/>
<path d="M144.6 61.7h7.6M144.6 64.2h7.6M144.6 66.8h7.6M144.6 69.3h7.6M144.6 71.8h7.6M144.6 74.4h7.6M144.6 76.9h7.6M144.6 79.5h7.6M131.8 82h7.7M131.8 84.5h7.7M131.8 87.1h7.7M131.8 89.6h7.7"/>
<path d="M131.8 92.1h7.7M131.8 94.7h7.7M131.8 97.2h7.7M131.8 99.8h7.7M144.6 82h7.6M144.6 84.5h7.6M144.6 87.1h7.6M144.6 89.6h7.6M144.6 92.1h7.6M144.6 94.7h7.6M144.6 97.2h7.6M144.6 99.8h7.6"/>
<path d="M131.8 102.3h7.7M131.8 104.8h7.7M131.8 107.4h7.7M131.8 109.9h7.7M131.8 112.5h7.7M131.8 115h7.7M131.8 117.5h7.7M144.6 102.3h7.6M144.6 104.8h7.6M144.6 107.4h7.6M144.6 109.9h7.6M144.6 112.5h7.6"/>
<path d="M144.6 115h7.6M144.6 117.5h7.6M131.8 120.1h7.7M131.8 122.6h7.7M131.8 125.2h7.7M131.8 127.7h7.7M131.8 130.2h7.7M131.8 132.8h7.7M131.8 135.3h7.7M131.8 137.9h7.7M144.6 120.1h7.6M144.6 122.6h7.6"/>
<path d="M144.6 125.2h7.6M144.6 127.7h7.6M144.6 130.2h7.6M144.6 132.8h7.6M144.6 135.3h7.6M144.6 137.9h7.6M131.8 140.4h7.7M131.8 142.9h7.7M131.8 145.5h7.7M131.8 148h7.7M131.8 150.6h7.7M131.8 153.1h7.7"/>
<path d="M131.8 155.6h7.7M131.8 158.2h7.7M144.6 140.4h7.6M144.6 142.9h7.6M144.6 145.5h7.6M144.6 148h7.6M144.6 150.6h7.6M144.6 153.1h7.6M144.6 155.6h7.6M144.6 158.2h7.6M53.1 168.3h5M131.8 160.7h7.7"/>
<path d="M131.8 163.3h7.7M131.8 165.8h7.7M131.8 170.9h7.7M144.6 160.7h7.6M144.6 163.3h7.6M144.6 165.8h7.6M144.6 170.9h7.6"/>
</g>
<path d="M139.5 38.8h5.1v134.6h-5.1z" fill-rule="evenodd" fill="#ffffb0"/>
<path d="M139.5 38.8h5.1v134.6h-5.1z" fill="none" stroke="#800000" stroke-width=".13"/>
<g fill="none" stroke="#000" stroke-width=".25">
<path d="M236.1 41.4h7.6M236.1 43.9h7.6M236.1 46.4h7.6M236.1 49h7.6M236.1 51.5h7.6M236.1 54.1h7.6M236.1 56.6h7.6M236.1 59.1h7.6M248.8 41.4h7.6M248.8 43.9h7.6M248.8 46.4h7.6M248.8 49h7.6"/>
<path d="M248.8 51.5h7.6M248.8 54.1h7.6M248.8 56.6h7.6M248.8 59.1h7.6M236.1 61.7h7.6M236.1 64.2h7.6M236.1 66.8h7.6M236.1 69.3h7.6M236.1 71.8h7.6M236.1 74.4h7.6M236.1 76.9h7.6M236.1 79.5h7.6"/>
<path d="M248.8 61.7h7.6M248.8 64.2h7.6M248.8 66.8h7.6M248.8 69.3h7.6M248.8 71.8h7.6M248.8 74.4h7.6M248.8 76.9h7.6M248.8 79.5h7.6M236.1 82h7.6M236.1 84.5h7.6M236.1 87.1h7.6M236.1 89.6h7.6"/>
<path d="M236.1 92.2h7.6M236.1 94.7h7.6M236.1 97.2h7.6M236.1 99.8h7.6M248.8 82h7.6M248.8 84.5h7.6M248.8 87.1h7.6M248.8 89.6h7.6M248.8 92.2h7.6M248.8 94.7h7.6M248.8 97.2h7.6M248.8 99.8h7.6"/>
<path d="M236.1 102.3h7.6M236.1 104.9h7.6M236.1 107.4h7.6M236.1 109.9h7.6M236.1 112.5h7.6M236.1 115h7.6M248.8 102.3h7.6M248.8 104.9h7.6M248.8 107.4h7.6M248.8 109.9h7.6M248.8 112.5h7.6M248.8 115h7.6"/>
<path d="M236.1 120.1h7.6M248.8 120.1h7.6M233.5 159.5v3.8M241.1 159.5v3.8M248.8 159.5v3.8M256.4 159.5v3.8M139.5 168.3h5.1"/>
</g>
<g fill="none" stroke="#f00" stroke-width=".13">
<path d="M64.7 50.5l2.1 2M64.7 53l2.1 2.1M66.8 50.5l-2.1 2M66.8 53l-2.1 2.1M255.4 88.6l2 2M255.4 91.1l2 2.1M255.4 98.8l2 2M257.4 88.6l-2 2M257.4 91.1l-2 2.1M257.4 98.8l-2 2M235 111.4l2.1 2.1M237.1 111.4l-2.1 2.1"/>
<path d="M64.7 129.2l2.1 2.1M66.8 129.2l-2.1 2.1M64.7 154.6l2.1 2.1M66.8 154.6l-2.1 2.1M151.2 152.1l2 2M153.2 152.1l-2 2"/>
</g>
<g fill="none" stroke="#000" stroke-width=".76">
<circle cx="233.5" cy="158.2" r="1.27"/>
<circle cx="241.1" cy="158.2" r="1.27"/>
<circle cx="248.8" cy="158.2" r="1.27"/>
<circle cx="256.4" cy="158.2" r="1.27"/>
</g>
<g fill="none" stroke="#800000" stroke-width=".25">
<path d="M231 165.8h5.1M231.7 166.6h3.6M232.5 167.3h2M233.3 168.1h.5M233.5 163.3v2.5M238.6 165.8h5.1M239.4 166.6h3.5M240.1 167.3h2.1M240.9 168.1h.5M241.1 163.3v2.5M246.2 165.8h5.1M247 166.6h3.5"/>
<path d="M247.7 167.3h2.1M248.5 168.1h.5M248.8 163.3v2.5M253.8 165.8h5.1M254.6 166.6h3.6M255.4 167.3h2M256.1 168.1h.5M256.4 163.3v2.5"/>
</g>
<path d="M243.7 38.8h5.1v83.8h-5.1z" fill-rule="evenodd" fill="#ffffb0"/>
<path d="M243.7 38.8h5.1v83.8h-5.1z" fill="none" stroke="#800000" stroke-width=".13"/>
<path d="M243.7 117.5h5.1" fill="none" stroke="#000" stroke-width=".25"/>
<g fill="none" stroke="#f00" stroke-width=".13">
<path d="M227.2 50.2l-1.3 1.3M227.2 55.3l-1.3 1.3M227.2 57.9l-1.3 1.2M278 47.7l-1.3 1.3M278 50.2l-1.3 1.3M278 55.3l-1.3 1.3M278 57.9l-1.3 1.2M44.4 73.4l2.1 2M44.4 75.9l2.1 2M46.5 73.4l-2.1 2M46.5 75.9l-2.1 2M130.8 60.7l2.1 2"/>
<path d="M132.9 60.7l-2.1 2M227.2 62.9l-1.3 1.3M227.2 65.5l-1.3 1.3M227.2 70.6l-1.3 1.2M227.2 73.1l-1.3 1.3M227.2 78.2l-1.3 1.3M278 62.9l-1.3 1.3M278 65.5l-1.3 1.3M278 70.6l-1.3 1.2M278 73.1l-1.3 1.3M227.2 80.7l-1.3 1.3M23.8 108.7l-1.2 1.2"/>
<path d="M23.8 111.2l-1.2 1.3M23.8 113.7l-1.2 1.3M23.8 116.3l-1.2 1.2M84.8 113.7l-1.2 1.3M84.8 116.3l-1.2 1.2M23.8 121.4l-1.2 1.2M23.8 123.9l-1.2 1.3M23.8 126.4l-1.2 1.3M23.8 129l-1.2 1.2M23.8 139.1l-1.2 1.3M84.8 134l-1.2 1.3M84.8 136.6l-1.2 1.3"/>
<path d="M23.8 141.7l-1.2 1.2M23.8 146.7l-1.2 1.3M23.8 149.3l-1.2 1.3M23.8 156.9l-1.2 1.3M23.8 159.4l-1.2 1.3M64.7 152.1l2.1 2M66.8 152.1l-2.1 2M23.8 162l-1.2 1.3M23.8 164.5l-1.2 1.3M64.7 162.2l2.1 2.1M64.7 164.8l2.1 2M66.8 162.2l-2.1 2.1"/>
<path d="M66.8 164.8l-2.1 2"/>
</g>
<path d="M81 56.6h2.6M83.6 55.3v2.6M176.3 150.6h2.6M177.6 150.6v2.5" fill="none" stroke="#800000" stroke-width=".25"/>
<g fill="none" stroke="#d0a19e" stroke-width=".25">
<path d="M227.4 49.9h1l.5-.5h1.1l.5 .5h1M227.4 50.5h1l.5 .5h1.1l.5-.5h1M227.4 54.9h1l.5-.5h1.1l.5 .5h1M227.4 55.6h1l.5 .5h1.1l.5-.5h1M227.4 57.5h1l.5-.5h1.1l.5 .5h1M227.4 58.1h1l.5 .5h1.1l.5-.5h1M278.2 47.3h1.1l.5-.5h1l.5 .5h1M278.2 48h1.1l.5 .5h1l.5-.5h1M278.2 49.9h1.1l.5-.5h1l.5 .5h1M278.2 50.5h1.1l.5 .5h1l.5-.5h1M278.2 54.9h1.1l.5-.5h1l.5 .5h1M278.2 55.6h1.1l.5 .5h1l.5-.5h1"/>
<path d="M278.2 57.5h1.1l.5-.5h1l.5 .5h1M278.2 58.1h1.1l.5 .5h1l.5-.5h1M227.4 62.6h1l.5-.5h1.1l.5 .5h1M227.4 63.2h1l.5 .5h1.1l.5-.5h1M227.4 65.1h1l.5-.5h1.1l.5 .5h1M227.4 65.7h1l.5 .5h1.1l.5-.5h1M227.4 70.2h1l.5-.5h1.1l.5 .5h1M227.4 70.8h1l.5 .5h1.1l.5-.5h1M227.4 72.7h1l.5-.5h1.1l.5 .5h1M227.4 73.4h1l.5 .5h1.1l.5-.5h1M227.4 77.8h1l.5-.5h1.1l.5 .5h1M227.4 78.4h1l.5 .5h1.1l.5-.5h1"/>
<path d="M278.2 62.6h1.1l.5-.5h1l.5 .5h1M278.2 63.2h1.1l.5 .5h1l.5-.5h1M278.2 65.1h1.1l.5-.5h1l.5 .5h1M278.2 65.7h1.1l.5 .5h1l.5-.5h1M278.2 70.2h1.1l.5-.5h1l.5 .5h1M278.2 70.8h1.1l.5 .5h1l.5-.5h1M278.2 72.7h1.1l.5-.5h1l.5 .5h1M278.2 73.4h1.1l.5 .5h1l.5-.5h1M227.4 80.3h1l.5-.5h1.1l.5 .5h1M227.4 81h1l.5 .5h1.1l.5-.5h1M24.1 108.3h1l.5-.5h1l.5 .5h1.1M24.1 108.9h1l.5 .5h1l.5-.5h1.1"/>
<path d="M24.1 110.8h1l.5-.5h1l.5 .5h1.1M24.1 111.4h1l.5 .6h1l.5-.6h1.1M24.1 113.4h1l.5-.6h1l.5 .6h1.1M24.1 114h1l.5 .5h1l.5-.5h1.1M24.1 115.9h1l.5-.5h1l.5 .5h1.1M24.1 116.5h1l.5 .5h1l.5-.5h1.1M85.1 113.4h1l.5-.6h1l.5 .6h1M85.1 114h1l.5 .5h1l.5-.5h1M85.1 115.9h1l.5-.5h1l.5 .5h1M85.1 116.5h1l.5 .5h1l.5-.5h1M24.1 121h1l.5-.5h1l.5 .5h1.1M24.1 121.6h1l.5 .5h1l.5-.5h1.1"/>
<path d="M24.1 123.5h1l.5-.5h1l.5 .5h1.1M24.1 124.1h1l.5 .6h1l.5-.6h1.1M24.1 126h1l.5-.5h1l.5 .5h1.1M24.1 126.7h1l.5 .5h1l.5-.5h1.1M24.1 128.6h1l.5-.5h1l.5 .5h1.1M24.1 129.2h1l.5 .5h1l.5-.5h1.1M24.1 138.8h1l.5-.6h1l.5 .6h1.1M24.1 139.4h1l.5 .5h1l.5-.5h1.1M85.1 133.7h1l.5-.5h1l.5 .5h1M85.1 134.3h1l.5 .5h1l.5-.5h1M85.1 136.2h1l.5-.5h1l.5 .5h1M85.1 136.8h1l.5 .6h1l.5-.6h1"/>
<path d="M24.1 141.3h1l.5-.5h1l.5 .5h1.1M24.1 141.9h1l.5 .5h1l.5-.5h1.1M24.1 146.4h1l.5-.5h1l.5 .5h1.1M24.1 147h1l.5 .5h1l.5-.5h1.1M24.1 148.9h1l.5-.5h1l.5 .5h1.1M24.1 149.5h1l.5 .6h1l.5-.6h1.1M24.1 156.5h1l.5-.5h1l.5 .5h1.1M24.1 157.2h1l.5 .5h1l.5-.5h1.1M24.1 159.1h1l.5-.5h1l.5 .5h1.1M24.1 159.7h1l.5 .5h1l.5-.5h1.1M24.1 161.6h1l.5-.5h1l.5 .5h1.1M24.1 162.2h1l.5 .5h1l.5-.5h1.1"/>
<path d="M24.1 164.1h1l.5-.5h1l.5 .5h1.1M24.1 164.8h1l.5 .5h1l.5-.5h1.1"/>
</g>
<g fill="none" stroke="#d0a19e" stroke-width=".13">
<path d="M227.4 50.5l-1.5 1M227.4 55.6l-1.5 1M227.4 58.1l-1.5 1M278.2 48l-1.5 1M278.2 50.5l-1.5 1M278.2 55.6l-1.5 1M278.2 58.1l-1.5 1M227.4 63.2l-1.5 1M227.4 65.7l-1.5 1.1M227.4 70.8l-1.5 1M227.4 73.4l-1.5 1M227.4 78.4l-1.5 1.1"/>
<path d="M278.2 63.2l-1.5 1M278.2 65.7l-1.5 1.1M278.2 70.8l-1.5 1M278.2 73.4l-1.5 1M227.4 81l-1.5 1M24.1 108.9l-1.5 1M24.1 111.4l-1.5 1.1M24.1 114l-1.5 1M24.1 116.5l-1.5 1M85.1 114l-1.5 1M85.1 116.5l-1.5 1M24.1 121.6l-1.5 1"/>
<path d="M24.1 124.1l-1.5 1.1M24.1 126.7l-1.5 1M24.1 129.2l-1.5 1M24.1 139.4l-1.5 1M85.1 134.3l-1.5 1M85.1 136.8l-1.5 1.1M24.1 141.9l-1.5 1M24.1 147l-1.5 1M24.1 149.5l-1.5 1.1M24.1 157.2l-1.5 1M24.1 159.7l-1.5 1M24.1 162.2l-1.5 1.1"/>
<path d="M24.1 164.8l-1.5 1"/>
</g>
<g fill="none" stroke="#f00" stroke-width=".25">
<path d="M227.2 49.6h1l.5-.5h1l.5 .5h1M227.2 50.2h1l.5 .6h1l.5-.6h1M227.2 54.7h1l.5-.5h1l.5 .5h1M227.2 55.3h1l.5 .5h1l.5-.5h1M227.2 57.2h1l.5-.5h1l.5 .5h1M227.2 57.9h1l.5 .5h1l.5-.5h1M278 47.1h1l.5-.5h1l.5 .5h1.1M278 47.7h1l.5 .5h1l.5-.5h1.1M278 49.6h1l.5-.5h1l.5 .5h1.1M278 50.2h1l.5 .6h1l.5-.6h1.1M278 54.7h1l.5-.5h1l.5 .5h1.1M278 55.3h1l.5 .5h1l.5-.5h1.1"/>
<path d="M278 57.2h1l.5-.5h1l.5 .5h1.1M278 57.9h1l.5 .5h1l.5-.5h1.1M227.2 62.3h1l.5-.5h1l.5 .5h1M227.2 62.9h1l.5 .6h1l.5-.6h1M227.2 64.8h1l.5-.5h1l.5 .5h1M227.2 65.5h1l.5 .5h1l.5-.5h1M227.2 69.9h1l.5-.5h1l.5 .5h1M227.2 70.6h1l.5 .5h1l.5-.5h1M227.2 72.5h1l.5-.5h1l.5 .5h1M227.2 73.1h1l.5 .5h1l.5-.5h1M227.2 77.5h1l.5-.5h1l.5 .5h1M227.2 78.2h1l.5 .5h1l.5-.5h1"/>
<path d="M278 62.3h1l.5-.5h1l.5 .5h1.1M278 62.9h1l.5 .6h1l.5-.6h1.1M278 64.8h1l.5-.5h1l.5 .5h1.1M278 65.5h1l.5 .5h1l.5-.5h1.1M278 69.9h1l.5-.5h1l.5 .5h1.1M278 70.6h1l.5 .5h1l.5-.5h1.1M278 72.5h1l.5-.5h1l.5 .5h1.1M278 73.1h1l.5 .5h1l.5-.5h1.1M227.2 80.1h1l.5-.5h1l.5 .5h1M227.2 80.7h1l.5 .5h1l.5-.5h1M23.8 108h1l.6-.5h1l.5 .5h1M23.8 108.7h1l.6 .5h1l.5-.5h1"/>
<path d="M23.8 110.6h1l.6-.5h1l.5 .5h1M23.8 111.2h1l.6 .5h1l.5-.5h1M23.8 113.1h1l.6-.5h1l.5 .5h1M23.8 113.7h1l.6 .5h1l.5-.5h1M23.8 115.6h1l.6-.5h1l.5 .5h1M23.8 116.3h1l.6 .5h1l.5-.5h1M84.8 113.1h1l.5-.5h1.1l.5 .5h1M84.8 113.7h1l.5 .5h1.1l.5-.5h1M84.8 115.6h1l.5-.5h1.1l.5 .5h1M84.8 116.3h1l.5 .5h1.1l.5-.5h1M23.8 120.7h1l.6-.5h1l.5 .5h1M23.8 121.4h1l.6 .5h1l.5-.5h1"/>
<path d="M23.8 123.3h1l.6-.6h1l.5 .6h1M23.8 123.9h1l.6 .5h1l.5-.5h1M23.8 125.8h1l.6-.5h1l.5 .5h1M23.8 126.4h1l.6 .5h1l.5-.5h1M23.8 128.3h1l.6-.5h1l.5 .5h1M23.8 129h1l.6 .5h1l.5-.5h1M23.8 138.5h1l.6-.5h1l.5 .5h1M23.8 139.1h1l.6 .5h1l.5-.5h1M84.8 133.4h1l.5-.5h1.1l.5 .5h1M84.8 134h1l.5 .6h1.1l.5-.6h1M84.8 136h1l.5-.6h1.1l.5 .6h1M84.8 136.6h1l.5 .5h1.1l.5-.5h1"/>
<path d="M23.8 141h1l.6-.5h1l.5 .5h1M23.8 141.7h1l.6 .5h1l.5-.5h1M23.8 146.1h1l.6-.5h1l.5 .5h1M23.8 146.7h1l.6 .6h1l.5-.6h1M23.8 148.7h1l.6-.6h1l.5 .6h1M23.8 149.3h1l.6 .5h1l.5-.5h1M23.8 156.3h1l.6-.5h1l.5 .5h1M23.8 156.9h1l.6 .5h1l.5-.5h1M23.8 158.8h1l.6-.5h1l.5 .5h1M23.8 159.4h1l.6 .6h1l.5-.6h1M23.8 161.4h1l.6-.6h1l.5 .6h1M23.8 162h1l.6 .5h1l.5-.5h1"/>
<path d="M23.8 163.9h1l.6-.5h1l.5 .5h1M23.8 164.5h1l.6 .5h1l.5-.5h1"/>
</g>
<path d="M45.4 170.9h-2.5v2.5" fill="none" stroke="#000080" stroke-width=".25"/>
<circle cx="42.9" cy="170.9" r=".51" fill="#000080"/>
<circle cx="42.9" cy="170.9" r=".51" fill="none" stroke="#000080" stroke-width=".13"/>
<path d="M65.8 170.9h2.5v2.5" fill="none" stroke="#000080" stroke-width=".25"/>
<circle cx="68.3" cy="170.9" r=".51" fill="#000080"/>
<circle cx="68.3" cy="170.9" r=".51" fill="none" stroke="#000080" stroke-width=".13"/>
<path d="M131.8 170.9h-2.5v2.5" fill="none" stroke="#000080" stroke-width=".25"/>
<circle cx="129.3" cy="170.9" r=".51" fill="#000080"/>
<circle cx="129.3" cy="170.9" r=".51" fill="none" stroke="#000080" stroke-width=".13"/>
<path d="M152.2 170.9h2.5v2.5" fill="none" stroke="#000080" stroke-width=".25"/>
<circle cx="154.7" cy="170.9" r=".51" fill="#000080"/>
<circle cx="154.7" cy="170.9" r=".51" fill="none" stroke="#000080" stroke-width=".13"/>
<path d="M256.4 120.1h2.5v5.1" fill="none" stroke="#000080" stroke-width=".25"/>
<circle cx="258.9" cy="120.1" r=".51" fill="#000080"/>
<circle cx="258.9" cy="120.1" r=".51" fill="none" stroke="#000080" stroke-width=".13"/>
<path d="M236.1 120.1h-2.6v5.1" fill="none" stroke="#000080" stroke-width=".25"/>
<circle cx="233.5" cy="120.1" r=".51" fill="#000080"/>
<circle cx="233.5" cy="120.1" r=".51" fill="none" stroke="#000080" stroke-width=".13"/>
<path d="M42.9 49h2.5" fill="none" stroke="#000080" stroke-width=".25"/>
<circle cx="42.9" cy="49" r=".51" fill="#000080"/>
<circle cx="42.9" cy="49" r=".51" fill="none" stroke="#000080" stroke-width=".13"/>
<path d="M42.9 64.2h2.5" fill="none" stroke="#000080" stroke-width=".25"/>
<circle cx="42.9" cy="64.2" r=".51" fill="#000080"/>
<circle cx="42.9" cy="64.2" r=".51" fill="none" stroke="#000080" stroke-width=".13"/>
<path d="M42.9 71.8h2.5" fill="none" stroke="#000080" stroke-width=".25"/>
<circle cx="42.9" cy="71.8" r=".51" fill="#000080"/>
<circle cx="42.9" cy="71.8" r=".51" fill="none" stroke="#000080" stroke-width=".13"/>
<path d="M42.9 82h2.5" fill="none" stroke="#000080" stroke-width=".25"/>
<circle cx="42.9" cy="82" r=".51" fill="#000080"/>
<circle cx="42.9" cy="82" r=".51" fill="none" stroke="#000080" stroke-width=".13"/>
<path d="M42.9 94.7h2.5" fill="none" stroke="#000080" stroke-width=".25"/>
<circle cx="42.9" cy="94.7" r=".51" fill="#000080"/>
<circle cx="42.9" cy="94.7" r=".51" fill="none" stroke="#000080" stroke-width=".13"/>
<path d="M42.9 107.4h2.5" fill="none" stroke="#000080" stroke-width=".25"/>
<circle cx="42.9" cy="107.4" r=".51" fill="#000080"/>
<circle cx="42.9" cy="107.4" r=".51" fill="none" stroke="#000080" stroke-width=".13"/>
<path d="M42.9 120.1h2.5" fill="none" stroke="#000080" stroke-width=".25"/>
<circle cx="42.9" cy="120.1" r=".51" fill="#000080"/>
<circle cx="42.9" cy="120.1" r=".51" fill="none" stroke="#000080" stroke-width=".13"/>
<path d="M42.9 132.8h2.5" fill="none" stroke="#000080" stroke-width=".25"/>
<circle cx="42.9" cy="132.8" r=".51" fill="#000080"/>
<circle cx="42.9" cy="132.8" r=".51" fill="none" stroke="#000080" stroke-width=".13"/>
<path d="M42.9 145.5h2.5" fill="none" stroke="#000080" stroke-width=".25"/>
<circle cx="42.9" cy="145.5" r=".51" fill="#000080"/>
<circle cx="42.9" cy="145.5" r=".51" fill="none" stroke="#000080" stroke-width=".13"/>
<path d="M42.9 153.1h2.5" fill="none" stroke="#000080" stroke-width=".25"/>
<circle cx="42.9" cy="153.1" r=".51" fill="#000080"/>
<circle cx="42.9" cy="153.1" r=".51" fill="none" stroke="#000080" stroke-width=".13"/>
<path d="M65.8 76.9h2.5v30.5h-2.5" fill="none" stroke="#000080" stroke-width=".25"/>
<circle cx="68.3" cy="107.4" r=".51" fill="#000080"/>
<circle cx="68.3" cy="107.4" r=".51" fill="none" stroke="#000080" stroke-width=".13"/>
<path d="M68.3 107.4v12.7h-2.5" fill="none" stroke="#000080" stroke-width=".25"/>
<circle cx="68.3" cy="107.4" r=".51" fill="#000080"/>
<circle cx="68.3" cy="107.4" r=".51" fill="none" stroke="#000080" stroke-width=".13"/>
<circle cx="68.3" cy="120.1" r=".51" fill="#000080"/>
<circle cx="68.3" cy="120.1" r=".51" fill="none" stroke="#000080" stroke-width=".13"/>
<path d="M68.3 120.1v12.7h-2.5" fill="none" stroke="#000080" stroke-width=".25"/>
<circle cx="68.3" cy="120.1" r=".51" fill="#000080"/>
<circle cx="68.3" cy="120.1" r=".51" fill="none" stroke="#000080" stroke-width=".13"/>
<circle cx="68.3" cy="132.8" r=".51" fill="#000080"/>
<circle cx="68.3" cy="132.8" r=".51" fill="none" stroke="#000080" stroke-width=".13"/>
<path d="M68.3 132.8v38.1" fill="none" stroke="#000080" stroke-width=".25"/>
<circle cx="68.3" cy="132.8" r=".51" fill="#000080"/>
<circle cx="68.3" cy="132.8" r=".51" fill="none" stroke="#000080" stroke-width=".13"/>
<circle cx="68.3" cy="170.9" r=".51" fill="#000080"/>
<circle cx="68.3" cy="170.9" r=".51" fill="none" stroke="#000080" stroke-width=".13"/>
<path d="M65.8 43.9h7.6" fill="none" stroke="#000080" stroke-width=".25"/>
<circle cx="73.4" cy="43.9" r=".51" fill="#000080"/>
<circle cx="73.4" cy="43.9" r=".51" fill="none" stroke="#000080" stroke-width=".13"/>
<path d="M65.8 41.4h7.6" fill="none" stroke="#000080" stroke-width=".25"/>
<circle cx="73.4" cy="41.4" r=".51" fill="#000080"/>
<circle cx="73.4" cy="41.4" r=".51" fill="none" stroke="#000080" stroke-width=".13"/>
<path d="M73.4 56.6v2.5h-7.6" fill="none" stroke="#000080" stroke-width=".25"/>
<circle cx="73.4" cy="56.6" r=".51" fill="#000080"/>
<circle cx="73.4" cy="56.6" r=".51" fill="none" stroke="#000080" stroke-width=".13"/>
<g fill="none" stroke="#000080" stroke-width=".25">
<path d="M129.3 76.9h2.5M14.9 117.5h30.5M14.9 115h30.5M14.9 112.5h30.5M14.9 109.9h30.5M65.8 117.5h33M65.8 115h33M14.9 125.2h30.5M14.9 122.6h30.5M14.9 130.2h30.5M14.9 127.7h30.5M65.8 137.9h33"/>
<path d="M65.8 135.3h33M14.9 142.9h30.5M14.9 140.4h30.5M14.9 150.6h30.5M14.9 148h30.5M14.9 158.2h30.5M65.8 158.2h27.9M152.2 158.2h25.4M14.9 160.7h30.5M14.9 165.8h30.5M14.9 163.3h30.5M65.8 160.7h27.9"/>
<path d="M152.2 160.7h25.4M152.2 165.8h25.4M152.2 163.3h25.4"/>
</g>
<circle cx="129.3" cy="76.9" r=".51" fill="#000080"/>
<circle cx="129.3" cy="76.9" r=".51" fill="none" stroke="#000080" stroke-width=".13"/>
<path d="M129.3 89.6h2.5" fill="none" stroke="#000080" stroke-width=".25"/>
<circle cx="129.3" cy="89.6" r=".51" fill="#000080"/>
<circle cx="129.3" cy="89.6" r=".51" fill="none" stroke="#000080" stroke-width=".13"/>
<path d="M129.3 102.3h2.5" fill="none" stroke="#000080" stroke-width=".25"/>
<circle cx="129.3" cy="102.3" r=".51" fill="#000080"/>
<circle cx="129.3" cy="102.3" r=".51" fill="none" stroke="#000080" stroke-width=".13"/>
<path d="M129.3 115h2.5" fill="none" stroke="#000080" stroke-width=".25"/>
<circle cx="129.3" cy="115" r=".51" fill="#000080"/>
<circle cx="129.3" cy="115" r=".51" fill="none" stroke="#000080" stroke-width=".13"/>
<path d="M129.3 127.7h2.5" fill="none" stroke="#000080" stroke-width=".25"/>
<circle cx="129.3" cy="127.7" r=".51" fill="#000080"/>
<circle cx="129.3" cy="127.7" r=".51" fill="none" stroke="#000080" stroke-width=".13"/>
<path d="M129.3 140.4h2.5" fill="none" stroke="#000080" stroke-width=".25"/>
<circle cx="129.3" cy="140.4" r=".51" fill="#000080"/>
<circle cx="129.3" cy="140.4" r=".51" fill="none" stroke="#000080" stroke-width=".13"/>
<path d="M129.3 153.1h2.5" fill="none" stroke="#000080" stroke-width=".25"/>
<circle cx="129.3" cy="153.1" r=".51" fill="#000080"/>
<circle cx="129.3" cy="153.1" r=".51" fill="none" stroke="#000080" stroke-width=".13"/>
<path d="M152.2 102.3h2.5" fill="none" stroke="#000080" stroke-width=".25"/>
<circle cx="154.7" cy="102.3" r=".51" fill="#000080"/>
<circle cx="154.7" cy="102.3" r=".51" fill="none" stroke="#000080" stroke-width=".13"/>
<path d="M152.2 115h2.5" fill="none" stroke="#000080" stroke-width=".25"/>
<circle cx="154.7" cy="115" r=".51" fill="#000080"/>
<circle cx="154.7" cy="115" r=".51" fill="none" stroke="#000080" stroke-width=".13"/>
<path d="M152.2 127.7h2.5" fill="none" stroke="#000080" stroke-width=".25"/>
<circle cx="154.7" cy="127.7" r=".51" fill="#000080"/>
<circle cx="154.7" cy="127.7" r=".51" fill="none" stroke="#000080" stroke-width=".13"/>
<path d="M152.2 140.4h2.5" fill="none" stroke="#000080" stroke-width=".25"/>
<circle cx="154.7" cy="140.4" r=".51" fill="#000080"/>
<circle cx="154.7" cy="140.4" r=".51" fill="none" stroke="#000080" stroke-width=".13"/>
<path d="M233.5 54.1h2.6" fill="none" stroke="#000080" stroke-width=".25"/>
<circle cx="233.5" cy="54.1" r=".51" fill="#000080"/>
<circle cx="233.5" cy="54.1" r=".51" fill="none" stroke="#000080" stroke-width=".13"/>
<path d="M233.5 61.7h2.6" fill="none" stroke="#000080" stroke-width=".25"/>
<circle cx="233.5" cy="61.7" r=".51" fill="#000080"/>
<circle cx="233.5" cy="61.7" r=".51" fill="none" stroke="#000080" stroke-width=".13"/>
<path d="M233.5 69.3h2.6" fill="none" stroke="#000080" stroke-width=".25"/>
<circle cx="233.5" cy="69.3" r=".51" fill="#000080"/>
<circle cx="233.5" cy="69.3" r=".51" fill="none" stroke="#000080" stroke-width=".13"/>
<path d="M233.5 76.9h2.6" fill="none" stroke="#000080" stroke-width=".25"/>
<circle cx="233.5" cy="76.9" r=".51" fill="#000080"/>
<circle cx="233.5" cy="76.9" r=".51" fill="none" stroke="#000080" stroke-width=".13"/>
<path d="M233.5 84.5h2.6" fill="none" stroke="#000080" stroke-width=".25"/>
<circle cx="233.5" cy="84.5" r=".51" fill="#000080"/>
<circle cx="233.5" cy="84.5" r=".51" fill="none" stroke="#000080" stroke-width=".13"/>
<path d="M233.5 97.2h2.6" fill="none" stroke="#000080" stroke-width=".25"/>
<circle cx="233.5" cy="97.2" r=".51" fill="#000080"/>
<circle cx="233.5" cy="97.2" r=".51" fill="none" stroke="#000080" stroke-width=".13"/>
<path d="M256.4 54.1h2.5" fill="none" stroke="#000080" stroke-width=".25"/>
<circle cx="258.9" cy="54.1" r=".51" fill="#000080"/>
<circle cx="258.9" cy="54.1" r=".51" fill="none" stroke="#000080" stroke-width=".13"/>
<path d="M256.4 61.7h2.5" fill="none" stroke="#000080" stroke-width=".25"/>
<circle cx="258.9" cy="61.7" r=".51" fill="#000080"/>
<circle cx="258.9" cy="61.7" r=".51" fill="none" stroke="#000080" stroke-width=".13"/>
<path d="M256.4 69.3h2.5" fill="none" stroke="#000080" stroke-width=".25"/>
<circle cx="258.9" cy="69.3" r=".51" fill="#000080"/>
<circle cx="258.9" cy="69.3" r=".51" fill="none" stroke="#000080" stroke-width=".13"/>
<path d="M256.4 76.9h2.5" fill="none" stroke="#000080" stroke-width=".25"/>
<circle cx="258.9" cy="76.9" r=".51" fill="#000080"/>
<circle cx="258.9" cy="76.9" r=".51" fill="none" stroke="#000080" stroke-width=".13"/>
<path d="M256.4 84.5h2.5" fill="none" stroke="#000080" stroke-width=".25"/>
<circle cx="258.9" cy="84.5" r=".51" fill="#000080"/>
<circle cx="258.9" cy="84.5" r=".51" fill="none" stroke="#000080" stroke-width=".13"/>
<path d="M256.4 97.2h2.5" fill="none" stroke="#000080" stroke-width=".25"/>
<circle cx="258.9" cy="97.2" r=".51" fill="#000080"/>
<circle cx="258.9" cy="97.2" r=".51" fill="none" stroke="#000080" stroke-width=".13"/>
<g fill="none" stroke="#000080" stroke-width=".25">
<path d="M45.4 41.4h-2.5v129.5M101.3 79.5h30.5M101.3 82h30.5M152.2 92.2h33M152.2 94.7h33M152.2 97.2h33M152.2 99.8h33M152.2 104.9h33M152.2 107.4h33M152.2 109.9h33M152.2 112.5h33M152.2 117.5h33"/>
<path d="M152.2 120.1h33M152.2 125.2h33M152.2 122.6h33"/>
</g>
<circle cx="42.9" cy="49" r=".51" fill="#000080"/>
<circle cx="42.9" cy="49" r=".51" fill="none" stroke="#000080" stroke-width=".13"/>
<circle cx="42.9" cy="64.2" r=".51" fill="#000080"/>
<circle cx="42.9" cy="64.2" r=".51" fill="none" stroke="#000080" stroke-width=".13"/>
<circle cx="42.9" cy="71.8" r=".51" fill="#000080"/>
<circle cx="42.9" cy="71.8" r=".51" fill="none" stroke="#000080" stroke-width=".13"/>
<circle cx="42.9" cy="82" r=".51" fill="#000080"/>
<circle cx="42.9" cy="82" r=".51" fill="none" stroke="#000080" stroke-width=".13"/>
<circle cx="42.9" cy="94.7" r=".51" fill="#000080"/>
<circle cx="42.9" cy="94.7" r=".51" fill="none" stroke="#000080" stroke-width=".13"/>
<circle cx="42.9" cy="107.4" r=".51" fill="#000080"/>
<circle cx="42.9" cy="107.4" r=".51" fill="none" stroke="#000080" stroke-width=".13"/>
<circle cx="42.9" cy="120.1" r=".51" fill="#000080"/>
<circle cx="42.9" cy="120.1" r=".51" fill="none" stroke="#000080" stroke-width=".13"/>
<circle cx="42.9" cy="132.8" r=".51" fill="#000080"/>
<circle cx="42.9" cy="132.8" r=".51" fill="none" stroke="#000080" stroke-width=".13"/>
<circle cx="42.9" cy="145.5" r=".51" fill="#000080"/>
<circle cx="42.9" cy="145.5" r=".51" fill="none" stroke="#000080" stroke-width=".13"/>
<circle cx="42.9" cy="153.1" r=".51" fill="#000080"/>
<circle cx="42.9" cy="153.1" r=".51" fill="none" stroke="#000080" stroke-width=".13"/>
<circle cx="42.9" cy="170.9" r=".51" fill="#000080"/>
<circle cx="42.9" cy="170.9" r=".51" fill="none" stroke="#000080" stroke-width=".13"/>
<path d="M65.8 56.6h15.2" fill="none" stroke="#000080" stroke-width=".25"/>
<circle cx="73.4" cy="56.6" r=".51" fill="#000080"/>
<circle cx="73.4" cy="56.6" r=".51" fill="none" stroke="#000080" stroke-width=".13"/>
<path d="M131.8 64.2h-2.5v106.7" fill="none" stroke="#000080" stroke-width=".25"/>
<circle cx="129.3" cy="76.9" r=".51" fill="#000080"/>
<circle cx="129.3" cy="76.9" r=".51" fill="none" stroke="#000080" stroke-width=".13"/>
<circle cx="129.3" cy="89.6" r=".51" fill="#000080"/>
<circle cx="129.3" cy="89.6" r=".51" fill="none" stroke="#000080" stroke-width=".13"/>
<circle cx="129.3" cy="102.3" r=".51" fill="#000080"/>
<circle cx="129.3" cy="102.3" r=".51" fill="none" stroke="#000080" stroke-width=".13"/>
<circle cx="129.3" cy="115" r=".51" fill="#000080"/>
<circle cx="129.3" cy="115" r=".51" fill="none" stroke="#000080" stroke-width=".13"/>
<circle cx="129.3" cy="127.7" r=".51" fill="#000080"/>
<circle cx="129.3" cy="127.7" r=".51" fill="none" stroke="#000080" stroke-width=".13"/>
<circle cx="129.3" cy="140.4" r=".51" fill="#000080"/>
<circle cx="129.3" cy="140.4" r=".51" fill="none" stroke="#000080" stroke-width=".13"/>
<circle cx="129.3" cy="153.1" r=".51" fill="#000080"/>
<circle cx="129.3" cy="153.1" r=".51" fill="none" stroke="#000080" stroke-width=".13"/>
<circle cx="129.3" cy="170.9" r=".51" fill="#000080"/>
<circle cx="129.3" cy="170.9" r=".51" fill="none" stroke="#000080" stroke-width=".13"/>
<path d="M152.2 89.6h2.5v81.3" fill="none" stroke="#000080" stroke-width=".25"/>
<circle cx="154.7" cy="102.3" r=".51" fill="#000080"/>
<circle cx="154.7" cy="102.3" r=".51" fill="none" stroke="#000080" stroke-width=".13"/>
<circle cx="154.7" cy="115" r=".51" fill="#000080"/>
<circle cx="154.7" cy="115" r=".51" fill="none" stroke="#000080" stroke-width=".13"/>
<circle cx="154.7" cy="127.7" r=".51" fill="#000080"/>
<circle cx="154.7" cy="127.7" r=".51" fill="none" stroke="#000080" stroke-width=".13"/>
<circle cx="154.7" cy="140.4" r=".51" fill="#000080"/>
<circle cx="154.7" cy="140.4" r=".51" fill="none" stroke="#000080" stroke-width=".13"/>
<circle cx="154.7" cy="170.9" r=".51" fill="#000080"/>
<circle cx="154.7" cy="170.9" r=".51" fill="none" stroke="#000080" stroke-width=".13"/>
<path d="M73.4 38.8v7.6h-7.6M152.2 43.9h33" fill="none" stroke="#000080" stroke-width=".25"/>
<circle cx="73.4" cy="43.9" r=".51" fill="#000080"/>
<circle cx="73.4" cy="43.9" r=".51" fill="none" stroke="#000080" stroke-width=".13"/>
<circle cx="73.4" cy="41.4" r=".51" fill="#000080"/>
<circle cx="73.4" cy="41.4" r=".51" fill="none" stroke="#000080" stroke-width=".13"/>
<path d="M236.1 46.4h-2.6v73.7" fill="none" stroke="#000080" stroke-width=".25"/>
<circle cx="233.5" cy="54.1" r=".51" fill="#000080"/>
<circle cx="233.5" cy="54.1" r=".51" fill="none" stroke="#000080" stroke-width=".13"/>
<circle cx="233.5" cy="61.7" r=".51" fill="#000080"/>
<circle cx="233.5" cy="61.7" r=".51" fill="none" stroke="#000080" stroke-width=".13"/>
<circle cx="233.5" cy="69.3" r=".51" fill="#000080"/>
<circle cx="233.5" cy="69.3" r=".51" fill="none" stroke="#000080" stroke-width=".13"/>
<circle cx="233.5" cy="76.9" r=".51" fill="#000080"/>
<circle cx="233.5" cy="76.9" r=".51" fill="none" stroke="#000080" stroke-width=".13"/>
<circle cx="233.5" cy="84.5" r=".51" fill="#000080"/>
<circle cx="233.5" cy="84.5" r=".51" fill="none" stroke="#000080" stroke-width=".13"/>
<circle cx="233.5" cy="97.2" r=".51" fill="#000080"/>
<circle cx="233.5" cy="97.2" r=".51" fill="none" stroke="#000080" stroke-width=".13"/>
<circle cx="233.5" cy="120.1" r=".51" fill="#000080"/>
<circle cx="233.5" cy="120.1" r=".51" fill="none" stroke="#000080" stroke-width=".13"/>
<path d="M256.4 46.4h2.5v73.7" fill="none" stroke="#000080" stroke-width=".25"/>
<circle cx="258.9" cy="54.1" r=".51" fill="#000080"/>
<circle cx="258.9" cy="54.1" r=".51" fill="none" stroke="#000080" stroke-width=".13"/>
<circle cx="258.9" cy="61.7" r=".51" fill="#000080"/>
<circle cx="258.9" cy="61.7" r=".51" fill="none" stroke="#000080" stroke-width=".13"/>
<circle cx="258.9" cy="69.3" r=".51" fill="#000080"/>
<circle cx="258.9" cy="69.3" r=".51" fill="none" stroke="#000080" stroke-width=".13"/>
<circle cx="258.9" cy="76.9" r=".51" fill="#000080"/>
<circle cx="258.9" cy="76.9" r=".51" fill="none" stroke="#000080" stroke-width=".13"/>
<circle cx="258.9" cy="84.5" r=".51" fill="#000080"/>
<circle cx="258.9" cy="84.5" r=".51" fill="none" stroke="#000080" stroke-width=".13"/>
<circle cx="258.9" cy="97.2" r=".51" fill="#000080"/>
<circle cx="258.9" cy="97.2" r=".51" fill="none" stroke="#000080" stroke-width=".13"/>
<circle cx="258.9" cy="120.1" r=".51" fill="#000080"/>
<circle cx="258.9" cy="120.1" r=".51" fill="none" stroke="#000080" stroke-width=".13"/>
<g fill="none" stroke="#000080" stroke-width=".25">
<path d="M205.6 49h30.5M205.6 51.5h30.5M205.6 56.6h30.5M205.6 59.1h30.5M256.4 49h27.9M256.4 51.5h27.9M256.4 56.6h27.9M256.4 59.1h27.9M205.6 64.2h30.5M205.6 66.8h30.5M205.6 71.8h30.5M205.6 74.4h30.5"/>
<path d="M205.6 79.5h30.5M256.4 64.2h27.9M256.4 66.8h27.9M256.4 71.8h27.9M256.4 74.4h27.9M101.3 84.5h30.5M101.3 87.1h30.5M101.3 92.1h30.5M101.3 94.7h30.5M101.3 97.2h30.5M101.3 99.8h30.5M205.6 82h30.5"/>
<path d="M101.3 104.8h30.5M101.3 107.4h30.5M101.3 109.9h30.5M101.3 112.5h30.5M101.3 117.5h30.5M205.6 115h30.5M101.3 120.1h30.5M101.3 122.6h30.5M177.6 153.1v2.5h-25.4"/>
</g>
<g fill="none" stroke="#f00" stroke-width=".13">
<path d="M130.8 48l2.1 2M130.8 45.4l2.1 2.1M130.8 42.9l2.1 2M130.8 40.3l2.1 2.1M132.9 48l-2.1 2M132.9 45.4l-2.1 2.1M132.9 42.9l-2.1 2M132.9 40.3l-2.1 2.1M151.2 48l2 2M151.2 50.5l2 2M151.2 40.3l2 2.1M153.2 48l-2 2"/>
<path d="M153.2 50.5l-2 2M153.2 40.3l-2 2.1"/>
</g>
<use href="#words"/>
</svg>
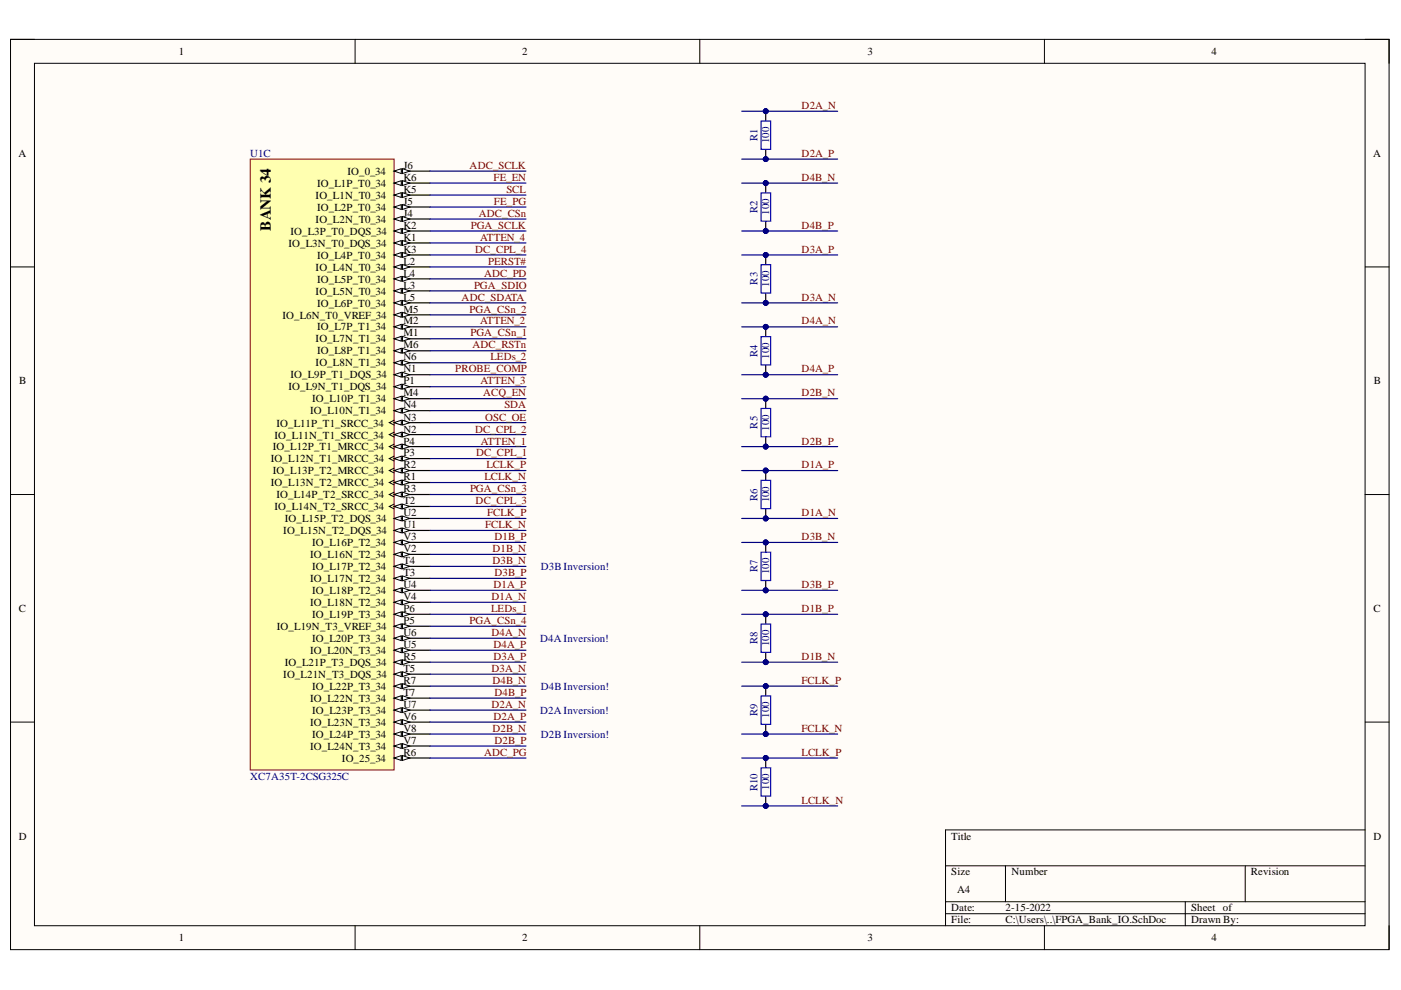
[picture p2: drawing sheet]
<svg xmlns="http://www.w3.org/2000/svg" width="297mm" height="210mm" viewBox="0 0 297 210" stroke-linecap="round" stroke-linejoin="round" font-family="sans-serif">
<defs><g id="words">
<text font-size="3.2" x="57.4" y="48.9" transform="rotate(-90 57.4 48.9)">BANK 34</text>
<g font-size="2.3">
<text x="37.9" y="11.7">1</text>
<text x="110.7" y="11.7">2</text>
<text x="183.9" y="11.7">3</text>
<text x="256.8" y="11.7">4</text>
<text x="3.9" y="33.3">A</text>
<text x="85.5" y="35.8">J6</text>
<text x="291.1" y="33.3">A</text>
<text x="67.3" y="39.6">IO_L1P_T0_34</text>
<text x="73.7" y="37.1">IO_0_34</text>
<text x="85.5" y="38.4">K6</text>
<text x="85.5" y="40.9">K5</text>
<text x="66.9" y="42.2">IO_L1N_T0_34</text>
<text x="66.9" y="47.2">IO_L2N_T0_34</text>
<text x="67.3" y="44.7">IO_L2P_T0_34</text>
<text x="85.5" y="43.4">J5</text>
<text x="85.5" y="46">J4</text>
<text x="61.2" y="52.3">IO_L3N_T0_DQS_34</text>
<text x="61.6" y="49.8">IO_L3P_T0_DQS_34</text>
<text x="85.5" y="48.5">K2</text>
<text x="85.5" y="51">K1</text>
<text x="85.5" y="53.6">K3</text>
<text x="66.9" y="57.4">IO_L4N_T0_34</text>
<text x="67.3" y="54.9">IO_L4P_T0_34</text>
<text x="67.3" y="59.9">IO_L5P_T0_34</text>
<text x="85.5" y="56.1">L2</text>
<text x="85.5" y="58.7">L4</text>
<text x="66.9" y="62.5">IO_L5N_T0_34</text>
<text x="67.3" y="65">IO_L6P_T0_34</text>
<text x="85.5" y="61.2">L3</text>
<text x="85.5" y="63.7">L5</text>
<text x="59.9" y="67.5">IO_L6N_T0_VREF_34</text>
<text x="67.3" y="70.1">IO_L7P_T1_34</text>
<text x="85.5" y="66.3">M5</text>
<text x="85.5" y="68.8">M2</text>
<text x="85.5" y="71.3">M1</text>
<text x="66.9" y="72.6">IO_L7N_T1_34</text>
<text x="66.9" y="77.7">IO_L8N_T1_34</text>
<text x="67.3" y="75.1">IO_L8P_T1_34</text>
<text x="85.5" y="73.9">M6</text>
<text x="85.5" y="76.4">N6</text>
<text x="4.1" y="81.5">B</text>
<text x="61.2" y="82.7">IO_L9N_T1_DQS_34</text>
<text x="61.6" y="80.2">IO_L9P_T1_DQS_34</text>
<text x="85.5" y="78.9">N1</text>
<text x="85.5" y="81.5">P1</text>
<text x="291.3" y="81.5">B</text>
<text x="65.7" y="87.8">IO_L10N_T1_34</text>
<text x="66.2" y="85.3">IO_L10P_T1_34</text>
<text x="85.5" y="84">M4</text>
<text x="85.5" y="86.6">N4</text>
<text x="85.5" y="89.2">N3</text>
<text x="57.9" y="95.5">IO_L12P_T1_MRCC_34</text>
<text x="58.2" y="93">IO_L11N_T1_SRCC_34</text>
<text x="58.6" y="90.4">IO_L11P_T1_SRCC_34</text>
<text x="85.5" y="91.7">N2</text>
<text x="85.5" y="94.2">P4</text>
<text x="57.4" y="98">IO_L12N_T1_MRCC_34</text>
<text x="57.9" y="100.6">IO_L13P_T2_MRCC_34</text>
<text x="85.5" y="96.8">P3</text>
<text x="85.5" y="99.3">R2</text>
<text x="85.5" y="101.9">R1</text>
<text x="57.4" y="103.1">IO_L13N_T2_MRCC_34</text>
<text x="58.6" y="105.7">IO_L14P_T2_SRCC_34</text>
<text x="85.5" y="104.4">R3</text>
<text x="85.5" y="106.9">T2</text>
<text x="58.2" y="108.2">IO_L14N_T2_SRCC_34</text>
<text x="60.1" y="113.3">IO_L15N_T2_DQS_34</text>
<text x="60.4" y="110.7">IO_L15P_T2_DQS_34</text>
<text x="85.5" y="109.5">U2</text>
<text x="85.5" y="112">U1</text>
<text x="65.7" y="118.3">IO_L16N_T2_34</text>
<text x="66.2" y="115.8">IO_L16P_T2_34</text>
<text x="85.5" y="114.5">V3</text>
<text x="85.5" y="117.1">V2</text>
<text x="85.5" y="119.6">T4</text>
<text x="65.7" y="123.4">IO_L17N_T2_34</text>
<text x="66.2" y="120.9">IO_L17P_T2_34</text>
<text x="66.2" y="125.9">IO_L18P_T2_34</text>
<text x="85.5" y="122.1">T3</text>
<text x="85.5" y="124.7">U4</text>
<text x="4" y="129.7">C</text>
<text x="65.7" y="128.5">IO_L18N_T2_34</text>
<text x="66.2" y="131">IO_L19P_T3_34</text>
<text x="85.5" y="127.2">V4</text>
<text x="85.5" y="129.7">P6</text>
<text x="291.2" y="129.7">C</text>
<text x="58.7" y="133.6">IO_L19N_T3_VREF_34</text>
<text x="66.2" y="136.1">IO_L20P_T3_34</text>
<text x="85.5" y="132.3">P5</text>
<text x="85.5" y="134.8">U6</text>
<text x="85.5" y="137.4">U5</text>
<text x="60.1" y="143.7">IO_L21N_T3_DQS_34</text>
<text x="60.4" y="141.2">IO_L21P_T3_DQS_34</text>
<text x="65.7" y="138.6">IO_L20N_T3_34</text>
<text x="85.5" y="139.9">R5</text>
<text x="85.5" y="142.4">T5</text>
<text x="65.7" y="148.9">IO_L22N_T3_34</text>
<text x="66.2" y="146.2">IO_L22P_T3_34</text>
<text x="85.5" y="145">R7</text>
<text x="85.5" y="147.5">T7</text>
<text x="65.7" y="153.9">IO_L23N_T3_34</text>
<text x="66.2" y="151.4">IO_L23P_T3_34</text>
<text x="85.5" y="150.1">U7</text>
<text x="85.5" y="152.7">V6</text>
<text x="85.5" y="155.2">V8</text>
<text x="65.7" y="159">IO_L24N_T3_34</text>
<text x="66.2" y="156.5">IO_L24P_T3_34</text>
<text x="72.5" y="161.5">IO_25_34</text>
<text x="85.5" y="157.7">V7</text>
<text x="85.5" y="160.3">R6</text>
<text x="4" y="178">D</text>
<text x="201.7" y="178">Title</text>
<text x="291.2" y="178">D</text>
<text x="201.7" y="185.6">Size</text>
<text x="214.5" y="185.6">Number</text>
<text x="265.2" y="185.6">Revision</text>
<text x="203" y="189.4">A4</text>
<text x="201.7" y="193.2">Date:</text>
<text x="201.7" y="195.8">File:</text>
<text x="213.2" y="193.2">2-15-2022</text>
<text x="213.2" y="195.8">C:\Users\..\FPGA_Bank_IO.SchDoc</text>
<text x="252.5" y="193.2">Sheet of</text>
<text x="252.5" y="195.8">Drawn By:</text>
<text x="37.9" y="199.6">1</text>
<text x="110.7" y="199.6">2</text>
<text x="183.9" y="199.6">3</text>
<text x="256.8" y="199.6">4</text>
</g>
<g font-size="2.3" fill="#800000">
<text x="170" y="23.1">D2A_N</text>
<text x="99.6" y="35.8">ADC_SCLK</text>
<text x="170" y="33.3">D2A_P</text>
<text x="104.6" y="38.4">FE_EN</text>
<text x="107.4" y="40.9">SCL</text>
<text x="170" y="38.4">D4B_N</text>
<text x="101.5" y="46">ADC_CSn</text>
<text x="104.7" y="43.4">FE_PG</text>
<text x="99.8" y="48.5">PGA_SCLK</text>
<text x="100.8" y="53.6">DC_CPL_4</text>
<text x="101.8" y="51">ATTEN_4</text>
<text x="170" y="48.5">D4B_P</text>
<text x="170" y="53.6">D3A_P</text>
<text x="102.6" y="58.7">ADC_PD</text>
<text x="103.5" y="56.1">PERST#</text>
<text x="97.9" y="63.7">ADC_SDATA</text>
<text x="100.5" y="61.2">PGA_SDIO</text>
<text x="170" y="63.7">D3A_N</text>
<text x="99.6" y="66.3">PGA_CSn_2</text>
<text x="99.7" y="71.3">PGA_CSn_1</text>
<text x="101.8" y="68.8">ATTEN_2</text>
<text x="170" y="68.8">D4A_N</text>
<text x="100.2" y="73.9">ADC_RSTn</text>
<text x="104" y="76.4">LEDs_2</text>
<text x="96.5" y="78.9">PROBE_COMP</text>
<text x="101.9" y="81.5">ATTEN_3</text>
<text x="170" y="78.9">D4A_P</text>
<text x="102.5" y="84">ACQ_EN</text>
<text x="102.9" y="89.2">OSC_OE</text>
<text x="106.9" y="86.6">SDA</text>
<text x="170" y="84">D2B_N</text>
<text x="100.8" y="91.7">DC_CPL_2</text>
<text x="101.9" y="94.2">ATTEN_1</text>
<text x="170" y="94.2">D2B_P</text>
<text x="100.9" y="96.8">DC_CPL_1</text>
<text x="102.7" y="101.9">LCLK_N</text>
<text x="103.1" y="99.3">LCLK_P</text>
<text x="170" y="99.3">D1A_P</text>
<text x="99.7" y="104.4">PGA_CSn_3</text>
<text x="100.8" y="106.9">DC_CPL_3</text>
<text x="102.9" y="112">FCLK_N</text>
<text x="103.3" y="109.5">FCLK_P</text>
<text x="170" y="109.5">D1A_N</text>
<text x="104.4" y="119.6">D3B_N</text>
<text x="104.4" y="117.1">D1B_N</text>
<text x="104.8" y="114.5">D1B_P</text>
<text x="170" y="114.5">D3B_N</text>
<text x="104.6" y="124.7">D1A_P</text>
<text x="104.8" y="122.1">D3B_P</text>
<text x="170" y="124.7">D3B_P</text>
<text x="104.1" y="129.7">LEDs_1</text>
<text x="104.2" y="127.2">D1A_N</text>
<text x="170" y="129.7">D1B_P</text>
<text x="99.6" y="132.3">PGA_CSn_4</text>
<text x="104.2" y="134.8">D4A_N</text>
<text x="104.6" y="137.4">D4A_P</text>
<text x="104.2" y="142.4">D3A_N</text>
<text x="104.6" y="139.9">D3A_P</text>
<text x="170" y="139.9">D1B_N</text>
<text x="104.4" y="145">D4B_N</text>
<text x="104.8" y="147.5">D4B_P</text>
<text x="170" y="145">FCLK_P</text>
<text x="104.2" y="150.1">D2A_N</text>
<text x="104.4" y="155.2">D2B_N</text>
<text x="104.6" y="152.7">D2A_P</text>
<text x="170" y="155.2">FCLK_N</text>
<text x="102.6" y="160.3">ADC_PG</text>
<text x="104.8" y="157.7">D2B_P</text>
<text x="170" y="160.3">LCLK_P</text>
<text x="170" y="170.4">LCLK_N</text>
</g>
<g font-size="2.3" fill="#000080">
<text x="160.6" y="29.8" transform="rotate(-90 160.6 29.8)">R1</text>
<text x="53" y="33.3">U1C</text>
<text x="163.1" y="30.3" transform="rotate(-90 163.1 30.3)">100</text>
<text x="160.6" y="45.2" transform="rotate(-90 160.6 45.2)">R2</text>
<text x="163.1" y="45.6" transform="rotate(-90 163.1 45.6)">100</text>
<text x="160.6" y="60.3" transform="rotate(-90 160.6 60.3)">R3</text>
<text x="163.1" y="60.8" transform="rotate(-90 163.1 60.8)">100</text>
<text x="160.6" y="75.6" transform="rotate(-90 160.6 75.6)">R4</text>
<text x="163.1" y="76.1" transform="rotate(-90 163.1 76.1)">100</text>
<text x="160.6" y="90.9" transform="rotate(-90 160.6 90.9)">R5</text>
<text x="163.1" y="91.3" transform="rotate(-90 163.1 91.3)">100</text>
<text x="160.6" y="106.2" transform="rotate(-90 160.6 106.2)">R6</text>
<text x="163.1" y="106.5" transform="rotate(-90 163.1 106.5)">100</text>
<text x="114.6" y="120.9">D3B Inversion!</text>
<text x="160.6" y="121.4" transform="rotate(-90 160.6 121.4)">R7</text>
<text x="163.1" y="121.8" transform="rotate(-90 163.1 121.8)">100</text>
<text x="114.5" y="136.1">D4AInversion!</text>
<text x="160.6" y="136.6" transform="rotate(-90 160.6 136.6)">R8</text>
<text x="163.1" y="137" transform="rotate(-90 163.1 137)">100</text>
<text x="114.6" y="146.2">D4B Inversion!</text>
<text x="114.5" y="151.4">D2AInversion!</text>
<text x="160.6" y="151.8" transform="rotate(-90 160.6 151.8)">R9</text>
<text x="163.1" y="152.2" transform="rotate(-90 163.1 152.2)">100</text>
<text x="114.6" y="156.5">D2B Inversion!</text>
<text x="53" y="165.3">XC7A35T-2CSG325C</text>
<text x="160.6" y="167.7" transform="rotate(-90 160.6 167.7)">R10</text>
<text x="163.1" y="167.4" transform="rotate(-90 163.1 167.4)">100</text>
</g>
</g></defs>
<path d="M2.2 8.3h292.3v193h-292.3z" fill-rule="evenodd" fill="#fffcf8"/>
<path d="M2.2 8.3h292.3v193h-292.3z" fill="none" stroke="#000" stroke-width=".21"/>
<path d="M7.3 13.4h282.1v182.9h-282.1z" fill-rule="evenodd" fill="#fffcf8"/>
<g fill="none" stroke="#000" stroke-width=".21">
<path d="M2.2 8.3h5.1M7.3 13.4h282.1v182.9h-282.1zM75.3 8.3v5.1M148.4 8.3v5.1M221.4 8.3v5.1M289.4 8.3h5.1v5.1M2.2 56.6h5.1M289.4 56.6h5.1M2.2 104.8h5.1M289.4 104.9h5.1M2.2 153.1h5.1M289.4 153.1h5.1"/>
<path d="M289.4 176h-88.9v20.3M75.3 196.3v5M148.4 196.3v5M200.5 183.6h88.9M200.5 191.2h88.9M200.5 193.7h88.9M213.2 183.6v7.6M221.4 196.3v5M251.3 191.2v5.1M264 183.6v7.6M294.5 196.3v5"/>
</g>
<path d="M53.1 33.7h30.5v129.6h-30.5z" fill-rule="evenodd" fill="#ffffb0"/>
<path d="M53.1 33.7h30.5v129.6h-30.5z" fill="none" stroke="#800000" stroke-width=".21"/>
<path d="M83.6 36.3h7.6" fill="none" stroke="#000" stroke-width=".25"/>
<path d="M83.6 36.3l1.5-.5v1z" fill="#f8fcff"/>
<path d="M83.6 36.3l1.5-.5v1z" fill="none" stroke="#000" stroke-width=".21"/>
<path d="M85.3 35.8l1.6 .5-1.6 .5z" fill="#f8fcff"/>
<path d="M85.3 35.8l1.6 .5-1.6 .5z" fill="none" stroke="#000" stroke-width=".21"/>
<path d="M83.6 38.8h7.6" fill="none" stroke="#000" stroke-width=".25"/>
<path d="M83.6 38.8l1.5-.5v1z" fill="#f8fcff"/>
<path d="M83.6 38.8l1.5-.5v1z" fill="none" stroke="#000" stroke-width=".21"/>
<path d="M85.3 38.3l1.6 .5-1.6 .5z" fill="#f8fcff"/>
<path d="M85.3 38.3l1.6 .5-1.6 .5z" fill="none" stroke="#000" stroke-width=".21"/>
<path d="M83.6 41.4h7.6" fill="none" stroke="#000" stroke-width=".25"/>
<path d="M83.6 41.4l1.5-.5v1z" fill="#f8fcff"/>
<path d="M83.6 41.4l1.5-.5v1z" fill="none" stroke="#000" stroke-width=".21"/>
<path d="M85.3 40.9l1.6 .5-1.6 .5z" fill="#f8fcff"/>
<path d="M85.3 40.9l1.6 .5-1.6 .5z" fill="none" stroke="#000" stroke-width=".21"/>
<path d="M83.6 43.9h7.6" fill="none" stroke="#000" stroke-width=".25"/>
<path d="M83.6 43.9l1.5-.5v1z" fill="#f8fcff"/>
<path d="M83.6 43.9l1.5-.5v1z" fill="none" stroke="#000" stroke-width=".21"/>
<path d="M85.3 43.4l1.6 .5-1.6 .5z" fill="#f8fcff"/>
<path d="M85.3 43.4l1.6 .5-1.6 .5z" fill="none" stroke="#000" stroke-width=".21"/>
<path d="M83.6 46.4h7.6" fill="none" stroke="#000" stroke-width=".25"/>
<path d="M83.6 46.4l1.5-.5v1z" fill="#f8fcff"/>
<path d="M83.6 46.4l1.5-.5v1z" fill="none" stroke="#000" stroke-width=".21"/>
<path d="M85.3 45.9l1.6 .5-1.6 .5z" fill="#f8fcff"/>
<path d="M85.3 45.9l1.6 .5-1.6 .5z" fill="none" stroke="#000" stroke-width=".21"/>
<path d="M83.6 49h7.6" fill="none" stroke="#000" stroke-width=".25"/>
<path d="M83.6 49l1.5-.5v1z" fill="#f8fcff"/>
<path d="M83.6 49l1.5-.5v1z" fill="none" stroke="#000" stroke-width=".21"/>
<path d="M85.3 48.5l1.6 .5-1.6 .5z" fill="#f8fcff"/>
<path d="M85.3 48.5l1.6 .5-1.6 .5z" fill="none" stroke="#000" stroke-width=".21"/>
<path d="M83.6 51.5h7.6" fill="none" stroke="#000" stroke-width=".25"/>
<path d="M83.6 51.5l1.5-.5v1z" fill="#f8fcff"/>
<path d="M83.6 51.5l1.5-.5v1z" fill="none" stroke="#000" stroke-width=".21"/>
<path d="M85.3 51l1.6 .5-1.6 .5z" fill="#f8fcff"/>
<path d="M85.3 51l1.6 .5-1.6 .5z" fill="none" stroke="#000" stroke-width=".21"/>
<path d="M83.6 54.1h7.6" fill="none" stroke="#000" stroke-width=".25"/>
<path d="M83.6 54.1l1.5-.6v1.1z" fill="#f8fcff"/>
<path d="M83.6 54.1l1.5-.6v1.1z" fill="none" stroke="#000" stroke-width=".21"/>
<path d="M85.3 53.5l1.6 .6-1.6 .5z" fill="#f8fcff"/>
<path d="M85.3 53.5l1.6 .6-1.6 .5z" fill="none" stroke="#000" stroke-width=".21"/>
<path d="M83.6 56.6h7.6" fill="none" stroke="#000" stroke-width=".25"/>
<path d="M83.6 56.6l1.5-.5v1z" fill="#f8fcff"/>
<path d="M83.6 56.6l1.5-.5v1z" fill="none" stroke="#000" stroke-width=".21"/>
<path d="M85.3 56.1l1.6 .5-1.6 .5z" fill="#f8fcff"/>
<path d="M85.3 56.1l1.6 .5-1.6 .5z" fill="none" stroke="#000" stroke-width=".21"/>
<path d="M83.6 59.1h7.6" fill="none" stroke="#000" stroke-width=".25"/>
<path d="M83.6 59.1l1.5-.5v1z" fill="#f8fcff"/>
<path d="M83.6 59.1l1.5-.5v1z" fill="none" stroke="#000" stroke-width=".21"/>
<path d="M85.3 58.6l1.6 .5-1.6 .5z" fill="#f8fcff"/>
<path d="M85.3 58.6l1.6 .5-1.6 .5z" fill="none" stroke="#000" stroke-width=".21"/>
<path d="M83.6 61.7h7.6" fill="none" stroke="#000" stroke-width=".25"/>
<path d="M83.6 61.7l1.5-.5v1z" fill="#f8fcff"/>
<path d="M83.6 61.7l1.5-.5v1z" fill="none" stroke="#000" stroke-width=".21"/>
<path d="M85.3 61.2l1.6 .5-1.6 .5z" fill="#f8fcff"/>
<path d="M85.3 61.2l1.6 .5-1.6 .5z" fill="none" stroke="#000" stroke-width=".21"/>
<path d="M83.6 64.2h7.6" fill="none" stroke="#000" stroke-width=".25"/>
<path d="M83.6 64.2l1.5-.5v1z" fill="#f8fcff"/>
<path d="M83.6 64.2l1.5-.5v1z" fill="none" stroke="#000" stroke-width=".21"/>
<path d="M85.3 63.7l1.6 .5-1.6 .5z" fill="#f8fcff"/>
<path d="M85.3 63.7l1.6 .5-1.6 .5z" fill="none" stroke="#000" stroke-width=".21"/>
<path d="M83.6 66.8h7.6" fill="none" stroke="#000" stroke-width=".25"/>
<path d="M83.6 66.8l1.5-.6v1.1z" fill="#f8fcff"/>
<path d="M83.6 66.8l1.5-.6v1.1z" fill="none" stroke="#000" stroke-width=".21"/>
<path d="M85.3 66.2l1.6 .6-1.6 .5z" fill="#f8fcff"/>
<path d="M85.3 66.2l1.6 .6-1.6 .5z" fill="none" stroke="#000" stroke-width=".21"/>
<path d="M83.6 69.3h7.6" fill="none" stroke="#000" stroke-width=".25"/>
<path d="M83.6 69.3l1.5-.5v1z" fill="#f8fcff"/>
<path d="M83.6 69.3l1.5-.5v1z" fill="none" stroke="#000" stroke-width=".21"/>
<path d="M85.3 68.8l1.6 .5-1.6 .5z" fill="#f8fcff"/>
<path d="M85.3 68.8l1.6 .5-1.6 .5z" fill="none" stroke="#000" stroke-width=".21"/>
<path d="M83.6 71.8h7.6" fill="none" stroke="#000" stroke-width=".25"/>
<path d="M83.6 71.8l1.5-.5v1z" fill="#f8fcff"/>
<path d="M83.6 71.8l1.5-.5v1z" fill="none" stroke="#000" stroke-width=".21"/>
<path d="M85.3 71.3l1.6 .5-1.6 .5z" fill="#f8fcff"/>
<path d="M85.3 71.3l1.6 .5-1.6 .5z" fill="none" stroke="#000" stroke-width=".21"/>
<path d="M83.6 74.4h7.6" fill="none" stroke="#000" stroke-width=".25"/>
<path d="M83.6 74.4l1.5-.5v1z" fill="#f8fcff"/>
<path d="M83.6 74.4l1.5-.5v1z" fill="none" stroke="#000" stroke-width=".21"/>
<path d="M85.3 73.9l1.6 .5-1.6 .5z" fill="#f8fcff"/>
<path d="M85.3 73.9l1.6 .5-1.6 .5z" fill="none" stroke="#000" stroke-width=".21"/>
<path d="M83.6 76.9h7.6" fill="none" stroke="#000" stroke-width=".25"/>
<path d="M83.6 76.9l1.5-.5v1z" fill="#f8fcff"/>
<path d="M83.6 76.9l1.5-.5v1z" fill="none" stroke="#000" stroke-width=".21"/>
<path d="M85.3 76.4l1.6 .5-1.6 .5z" fill="#f8fcff"/>
<path d="M85.3 76.4l1.6 .5-1.6 .5z" fill="none" stroke="#000" stroke-width=".21"/>
<path d="M83.6 79.5h7.6" fill="none" stroke="#000" stroke-width=".25"/>
<path d="M83.6 79.5l1.5-.6v1.1z" fill="#f8fcff"/>
<path d="M83.6 79.5l1.5-.6v1.1z" fill="none" stroke="#000" stroke-width=".21"/>
<path d="M85.3 78.9l1.6 .6-1.6 .5z" fill="#f8fcff"/>
<path d="M85.3 78.9l1.6 .6-1.6 .5z" fill="none" stroke="#000" stroke-width=".21"/>
<path d="M83.6 82h7.6" fill="none" stroke="#000" stroke-width=".25"/>
<path d="M83.6 82l1.5-.5v1z" fill="#f8fcff"/>
<path d="M83.6 82l1.5-.5v1z" fill="none" stroke="#000" stroke-width=".21"/>
<path d="M85.3 81.5l1.6 .5-1.6 .5z" fill="#f8fcff"/>
<path d="M85.3 81.5l1.6 .5-1.6 .5z" fill="none" stroke="#000" stroke-width=".21"/>
<path d="M83.6 84.5h7.6" fill="none" stroke="#000" stroke-width=".25"/>
<path d="M83.6 84.5l1.5-.5v1z" fill="#f8fcff"/>
<path d="M83.6 84.5l1.5-.5v1z" fill="none" stroke="#000" stroke-width=".21"/>
<path d="M85.3 84l1.6 .5-1.6 .5z" fill="#f8fcff"/>
<path d="M85.3 84l1.6 .5-1.6 .5z" fill="none" stroke="#000" stroke-width=".21"/>
<path d="M83.6 87.1h7.6" fill="none" stroke="#000" stroke-width=".25"/>
<path d="M83.6 87.1l1.5-.5v1z" fill="#f8fcff"/>
<path d="M83.6 87.1l1.5-.5v1z" fill="none" stroke="#000" stroke-width=".21"/>
<path d="M85.3 86.6l1.6 .5-1.6 .5z" fill="#f8fcff"/>
<path d="M85.3 86.6l1.6 .5-1.6 .5z" fill="none" stroke="#000" stroke-width=".21"/>
<path d="M83.6 89.6h7.6" fill="none" stroke="#000" stroke-width=".25"/>
<path d="M83.6 89.6l1.5-.5v1z" fill="#f8fcff"/>
<path d="M83.6 89.6l1.5-.5v1z" fill="none" stroke="#000" stroke-width=".21"/>
<path d="M85.3 89.1l1.6 .5-1.6 .5z" fill="#f8fcff"/>
<path d="M83.6 89.1l-1.1 .5 1.1 .5M85.3 89.1l1.6 .5-1.6 .5z" fill="none" stroke="#000" stroke-width=".21"/>
<path d="M83.6 92.1h7.6" fill="none" stroke="#000" stroke-width=".25"/>
<path d="M83.6 92.1l1.5-.5v1.1z" fill="#f8fcff"/>
<path d="M83.6 92.1l1.5-.5v1.1z" fill="none" stroke="#000" stroke-width=".21"/>
<path d="M85.3 91.6l1.6 .5-1.6 .6z" fill="#f8fcff"/>
<path d="M83.6 91.6l-1.1 .5 1.1 .6M85.3 91.6l1.6 .5-1.6 .6z" fill="none" stroke="#000" stroke-width=".21"/>
<path d="M83.6 94.7h7.6" fill="none" stroke="#000" stroke-width=".25"/>
<path d="M83.6 94.7l1.5-.5v1z" fill="#f8fcff"/>
<path d="M83.6 94.7l1.5-.5v1z" fill="none" stroke="#000" stroke-width=".21"/>
<path d="M85.3 94.2l1.6 .5-1.6 .5z" fill="#f8fcff"/>
<path d="M83.6 94.2l-1.1 .5 1.1 .5M85.3 94.2l1.6 .5-1.6 .5z" fill="none" stroke="#000" stroke-width=".21"/>
<path d="M83.6 97.2h7.6" fill="none" stroke="#000" stroke-width=".25"/>
<path d="M83.6 97.2l1.5-.5v1z" fill="#f8fcff"/>
<path d="M83.6 97.2l1.5-.5v1z" fill="none" stroke="#000" stroke-width=".21"/>
<path d="M85.3 96.7l1.6 .5-1.6 .5z" fill="#f8fcff"/>
<path d="M83.6 96.7l-1.1 .5 1.1 .5M85.3 96.7l1.6 .5-1.6 .5z" fill="none" stroke="#000" stroke-width=".21"/>
<path d="M83.6 99.8h7.6" fill="none" stroke="#000" stroke-width=".25"/>
<path d="M83.6 99.8l1.5-.5v1z" fill="#f8fcff"/>
<path d="M83.6 99.8l1.5-.5v1z" fill="none" stroke="#000" stroke-width=".21"/>
<path d="M85.3 99.3l1.6 .5-1.6 .5z" fill="#f8fcff"/>
<path d="M83.6 99.3l-1.1 .5 1.1 .5M85.3 99.3l1.6 .5-1.6 .5z" fill="none" stroke="#000" stroke-width=".21"/>
<path d="M83.6 102.3h7.6" fill="none" stroke="#000" stroke-width=".25"/>
<path d="M83.6 102.3l1.5-.5v1z" fill="#f8fcff"/>
<path d="M83.6 102.3l1.5-.5v1z" fill="none" stroke="#000" stroke-width=".21"/>
<path d="M85.3 101.8l1.6 .5-1.6 .5z" fill="#f8fcff"/>
<path d="M83.6 101.8l-1.1 .5 1.1 .5M85.3 101.8l1.6 .5-1.6 .5z" fill="none" stroke="#000" stroke-width=".21"/>
<path d="M83.6 104.8h7.6" fill="none" stroke="#000" stroke-width=".25"/>
<path d="M83.6 104.8l1.5-.5v1.1z" fill="#f8fcff"/>
<path d="M83.6 104.8l1.5-.5v1.1z" fill="none" stroke="#000" stroke-width=".21"/>
<path d="M85.3 104.3l1.6 .5-1.6 .6z" fill="#f8fcff"/>
<path d="M83.6 104.3l-1.1 .5 1.1 .6M85.3 104.3l1.6 .5-1.6 .6z" fill="none" stroke="#000" stroke-width=".21"/>
<path d="M83.6 107.4h7.6" fill="none" stroke="#000" stroke-width=".25"/>
<path d="M83.6 107.4l1.5-.5v1z" fill="#f8fcff"/>
<path d="M83.6 107.4l1.5-.5v1z" fill="none" stroke="#000" stroke-width=".21"/>
<path d="M85.3 106.9l1.6 .5-1.6 .5z" fill="#f8fcff"/>
<path d="M83.6 106.9l-1.1 .5 1.1 .5M85.3 106.9l1.6 .5-1.6 .5z" fill="none" stroke="#000" stroke-width=".21"/>
<path d="M83.6 109.9h7.6" fill="none" stroke="#000" stroke-width=".25"/>
<path d="M83.6 109.9l1.5-.5v1z" fill="#f8fcff"/>
<path d="M83.6 109.9l1.5-.5v1z" fill="none" stroke="#000" stroke-width=".21"/>
<path d="M85.3 109.4l1.6 .5-1.6 .5z" fill="#f8fcff"/>
<path d="M85.3 109.4l1.6 .5-1.6 .5z" fill="none" stroke="#000" stroke-width=".21"/>
<path d="M83.6 112.5h7.6" fill="none" stroke="#000" stroke-width=".25"/>
<path d="M83.6 112.5l1.5-.5v1z" fill="#f8fcff"/>
<path d="M83.6 112.5l1.5-.5v1z" fill="none" stroke="#000" stroke-width=".21"/>
<path d="M85.3 112l1.6 .5-1.6 .5z" fill="#f8fcff"/>
<path d="M85.3 112l1.6 .5-1.6 .5z" fill="none" stroke="#000" stroke-width=".21"/>
<path d="M83.6 115h7.6" fill="none" stroke="#000" stroke-width=".25"/>
<path d="M83.6 115l1.5-.5v1z" fill="#f8fcff"/>
<path d="M83.6 115l1.5-.5v1z" fill="none" stroke="#000" stroke-width=".21"/>
<path d="M85.3 114.5l1.6 .5-1.6 .5z" fill="#f8fcff"/>
<path d="M85.3 114.5l1.6 .5-1.6 .5z" fill="none" stroke="#000" stroke-width=".21"/>
<path d="M83.6 117.5h7.6" fill="none" stroke="#000" stroke-width=".25"/>
<path d="M83.6 117.5l1.5-.5v1.1z" fill="#f8fcff"/>
<path d="M83.6 117.5l1.5-.5v1.1z" fill="none" stroke="#000" stroke-width=".21"/>
<path d="M85.3 117l1.6 .5-1.6 .6z" fill="#f8fcff"/>
<path d="M85.3 117l1.6 .5-1.6 .6z" fill="none" stroke="#000" stroke-width=".21"/>
<path d="M83.6 120.1h7.6" fill="none" stroke="#000" stroke-width=".25"/>
<path d="M83.6 120.1l1.5-.5v1z" fill="#f8fcff"/>
<path d="M83.6 120.1l1.5-.5v1z" fill="none" stroke="#000" stroke-width=".21"/>
<path d="M85.3 119.6l1.6 .5-1.6 .5z" fill="#f8fcff"/>
<path d="M85.3 119.6l1.6 .5-1.6 .5z" fill="none" stroke="#000" stroke-width=".21"/>
<path d="M83.6 122.6h7.6" fill="none" stroke="#000" stroke-width=".25"/>
<path d="M83.6 122.6l1.5-.5v1z" fill="#f8fcff"/>
<path d="M83.6 122.6l1.5-.5v1z" fill="none" stroke="#000" stroke-width=".21"/>
<path d="M85.3 122.1l1.6 .5-1.6 .5z" fill="#f8fcff"/>
<path d="M85.3 122.1l1.6 .5-1.6 .5z" fill="none" stroke="#000" stroke-width=".21"/>
<path d="M83.6 125.2h7.6" fill="none" stroke="#000" stroke-width=".25"/>
<path d="M83.6 125.2l1.5-.5v1z" fill="#f8fcff"/>
<path d="M83.6 125.2l1.5-.5v1z" fill="none" stroke="#000" stroke-width=".21"/>
<path d="M85.3 124.7l1.6 .5-1.6 .5z" fill="#f8fcff"/>
<path d="M85.3 124.7l1.6 .5-1.6 .5z" fill="none" stroke="#000" stroke-width=".21"/>
<path d="M83.6 127.7h7.6" fill="none" stroke="#000" stroke-width=".25"/>
<path d="M83.6 127.7l1.5-.5v1z" fill="#f8fcff"/>
<path d="M83.6 127.7l1.5-.5v1z" fill="none" stroke="#000" stroke-width=".21"/>
<path d="M85.3 127.2l1.6 .5-1.6 .5z" fill="#f8fcff"/>
<path d="M85.3 127.2l1.6 .5-1.6 .5z" fill="none" stroke="#000" stroke-width=".21"/>
<path d="M83.6 130.2h7.6" fill="none" stroke="#000" stroke-width=".25"/>
<path d="M83.6 130.2l1.5-.5v1.1z" fill="#f8fcff"/>
<path d="M83.6 130.2l1.5-.5v1.1z" fill="none" stroke="#000" stroke-width=".21"/>
<path d="M85.3 129.7l1.6 .5-1.6 .6z" fill="#f8fcff"/>
<path d="M85.3 129.7l1.6 .5-1.6 .6z" fill="none" stroke="#000" stroke-width=".21"/>
<path d="M83.6 132.8h7.6" fill="none" stroke="#000" stroke-width=".25"/>
<path d="M83.6 132.8l1.5-.5v1z" fill="#f8fcff"/>
<path d="M83.6 132.8l1.5-.5v1z" fill="none" stroke="#000" stroke-width=".21"/>
<path d="M85.3 132.3l1.6 .5-1.6 .5z" fill="#f8fcff"/>
<path d="M85.3 132.3l1.6 .5-1.6 .5z" fill="none" stroke="#000" stroke-width=".21"/>
<path d="M83.6 135.3h7.6" fill="none" stroke="#000" stroke-width=".25"/>
<path d="M83.6 135.3l1.5-.5v1z" fill="#f8fcff"/>
<path d="M83.6 135.3l1.5-.5v1z" fill="none" stroke="#000" stroke-width=".21"/>
<path d="M85.3 134.8l1.6 .5-1.6 .5z" fill="#f8fcff"/>
<path d="M85.3 134.8l1.6 .5-1.6 .5z" fill="none" stroke="#000" stroke-width=".21"/>
<path d="M83.6 137.9h7.6" fill="none" stroke="#000" stroke-width=".25"/>
<path d="M83.6 137.9l1.5-.5v1z" fill="#f8fcff"/>
<path d="M83.6 137.9l1.5-.5v1z" fill="none" stroke="#000" stroke-width=".21"/>
<path d="M85.3 137.4l1.6 .5-1.6 .5z" fill="#f8fcff"/>
<path d="M85.3 137.4l1.6 .5-1.6 .5z" fill="none" stroke="#000" stroke-width=".21"/>
<path d="M83.6 140.4h7.6" fill="none" stroke="#000" stroke-width=".25"/>
<path d="M83.6 140.4l1.5-.5v1z" fill="#f8fcff"/>
<path d="M83.6 140.4l1.5-.5v1z" fill="none" stroke="#000" stroke-width=".21"/>
<path d="M85.3 139.9l1.6 .5-1.6 .5z" fill="#f8fcff"/>
<path d="M85.3 139.9l1.6 .5-1.6 .5z" fill="none" stroke="#000" stroke-width=".21"/>
<path d="M83.6 142.9h7.6" fill="none" stroke="#000" stroke-width=".25"/>
<path d="M83.6 142.9l1.5-.5v1z" fill="#f8fcff"/>
<path d="M83.6 142.9l1.5-.5v1z" fill="none" stroke="#000" stroke-width=".21"/>
<path d="M85.3 142.4l1.6 .5-1.6 .5z" fill="#f8fcff"/>
<path d="M85.3 142.4l1.6 .5-1.6 .5z" fill="none" stroke="#000" stroke-width=".21"/>
<path d="M83.6 145.5h7.6" fill="none" stroke="#000" stroke-width=".25"/>
<path d="M83.6 145.5l1.5-.5v1z" fill="#f8fcff"/>
<path d="M83.6 145.5l1.5-.5v1z" fill="none" stroke="#000" stroke-width=".21"/>
<path d="M85.3 145l1.6 .5-1.6 .5z" fill="#f8fcff"/>
<path d="M85.3 145l1.6 .5-1.6 .5z" fill="none" stroke="#000" stroke-width=".21"/>
<path d="M83.6 148h7.6" fill="none" stroke="#000" stroke-width=".25"/>
<path d="M83.6 148l1.5-.5v1z" fill="#f8fcff"/>
<path d="M83.6 148l1.5-.5v1z" fill="none" stroke="#000" stroke-width=".21"/>
<path d="M85.3 147.5l1.6 .5-1.6 .5z" fill="#f8fcff"/>
<path d="M85.3 147.5l1.6 .5-1.6 .5z" fill="none" stroke="#000" stroke-width=".21"/>
<path d="M83.6 150.6h7.6" fill="none" stroke="#000" stroke-width=".25"/>
<path d="M83.6 150.6l1.5-.5v1z" fill="#f8fcff"/>
<path d="M83.6 150.6l1.5-.5v1z" fill="none" stroke="#000" stroke-width=".21"/>
<path d="M85.3 150.1l1.6 .5-1.6 .5z" fill="#f8fcff"/>
<path d="M85.3 150.1l1.6 .5-1.6 .5z" fill="none" stroke="#000" stroke-width=".21"/>
<path d="M83.6 153.1h7.6" fill="none" stroke="#000" stroke-width=".25"/>
<path d="M83.6 153.1l1.5-.5v1z" fill="#f8fcff"/>
<path d="M83.6 153.1l1.5-.5v1z" fill="none" stroke="#000" stroke-width=".21"/>
<path d="M85.3 152.6l1.6 .5-1.6 .5z" fill="#f8fcff"/>
<path d="M85.3 152.6l1.6 .5-1.6 .5z" fill="none" stroke="#000" stroke-width=".21"/>
<path d="M83.6 155.6h7.6" fill="none" stroke="#000" stroke-width=".25"/>
<path d="M83.6 155.6l1.5-.5v1z" fill="#f8fcff"/>
<path d="M83.6 155.6l1.5-.5v1z" fill="none" stroke="#000" stroke-width=".21"/>
<path d="M85.3 155.1l1.6 .5-1.6 .5z" fill="#f8fcff"/>
<path d="M85.3 155.1l1.6 .5-1.6 .5z" fill="none" stroke="#000" stroke-width=".21"/>
<path d="M83.6 158.2h7.6" fill="none" stroke="#000" stroke-width=".25"/>
<path d="M83.6 158.2l1.5-.5v1z" fill="#f8fcff"/>
<path d="M83.6 158.2l1.5-.5v1z" fill="none" stroke="#000" stroke-width=".21"/>
<path d="M85.3 157.7l1.6 .5-1.6 .5z" fill="#f8fcff"/>
<path d="M85.3 157.7l1.6 .5-1.6 .5z" fill="none" stroke="#000" stroke-width=".21"/>
<path d="M83.6 160.7h7.6" fill="none" stroke="#000" stroke-width=".25"/>
<path d="M83.6 160.7l1.5-.5v1z" fill="#f8fcff"/>
<path d="M83.6 160.7l1.5-.5v1z" fill="none" stroke="#000" stroke-width=".21"/>
<path d="M85.3 160.2l1.6 .5-1.6 .5z" fill="#f8fcff"/>
<path d="M85.3 160.2l1.6 .5-1.6 .5z" fill="none" stroke="#000" stroke-width=".21"/>
<circle cx="162.3" cy="23.6" r=".51" fill="#000080"/>
<circle cx="162.3" cy="23.6" r=".51" fill="none" stroke="#000080" stroke-width=".21"/>
<circle cx="162.3" cy="33.7" r=".51" fill="#000080"/>
<circle cx="162.3" cy="33.7" r=".51" fill="none" stroke="#000080" stroke-width=".21"/>
<path d="M162.3 23.6v2" fill="none" stroke="#000" stroke-width=".25"/>
<circle cx="162.3" cy="23.6" r=".51" fill="#000080"/>
<circle cx="162.3" cy="23.6" r=".51" fill="none" stroke="#000080" stroke-width=".21"/>
<path d="M162.3 31.7v2" fill="none" stroke="#000" stroke-width=".25"/>
<circle cx="162.3" cy="33.7" r=".51" fill="#000080"/>
<circle cx="162.3" cy="33.7" r=".51" fill="none" stroke="#000080" stroke-width=".21"/>
<path d="M161.4 25.7h2v6h-2z" fill="none" stroke="#00f" stroke-width=".25"/>
<circle cx="162.3" cy="38.8" r=".51" fill="#000080"/>
<circle cx="162.3" cy="38.8" r=".51" fill="none" stroke="#000080" stroke-width=".21"/>
<circle cx="162.3" cy="49" r=".51" fill="#000080"/>
<circle cx="162.3" cy="49" r=".51" fill="none" stroke="#000080" stroke-width=".21"/>
<path d="M162.3 38.8v2" fill="none" stroke="#000" stroke-width=".25"/>
<circle cx="162.3" cy="38.8" r=".51" fill="#000080"/>
<circle cx="162.3" cy="38.8" r=".51" fill="none" stroke="#000080" stroke-width=".21"/>
<path d="M162.3 47v2" fill="none" stroke="#000" stroke-width=".25"/>
<circle cx="162.3" cy="49" r=".51" fill="#000080"/>
<circle cx="162.3" cy="49" r=".51" fill="none" stroke="#000080" stroke-width=".21"/>
<path d="M161.4 40.9h2v6h-2z" fill="none" stroke="#00f" stroke-width=".25"/>
<circle cx="162.3" cy="54.1" r=".51" fill="#000080"/>
<circle cx="162.3" cy="54.1" r=".51" fill="none" stroke="#000080" stroke-width=".21"/>
<circle cx="162.3" cy="64.2" r=".51" fill="#000080"/>
<circle cx="162.3" cy="64.2" r=".51" fill="none" stroke="#000080" stroke-width=".21"/>
<path d="M162.3 54.1v2" fill="none" stroke="#000" stroke-width=".25"/>
<circle cx="162.3" cy="54.1" r=".51" fill="#000080"/>
<circle cx="162.3" cy="54.1" r=".51" fill="none" stroke="#000080" stroke-width=".21"/>
<path d="M162.3 62.2v2" fill="none" stroke="#000" stroke-width=".25"/>
<circle cx="162.3" cy="64.2" r=".51" fill="#000080"/>
<circle cx="162.3" cy="64.2" r=".51" fill="none" stroke="#000080" stroke-width=".21"/>
<path d="M161.4 56.1h2v6h-2z" fill="none" stroke="#00f" stroke-width=".25"/>
<circle cx="162.3" cy="69.3" r=".51" fill="#000080"/>
<circle cx="162.3" cy="69.3" r=".51" fill="none" stroke="#000080" stroke-width=".21"/>
<circle cx="162.3" cy="79.5" r=".51" fill="#000080"/>
<circle cx="162.3" cy="79.5" r=".51" fill="none" stroke="#000080" stroke-width=".21"/>
<path d="M162.3 69.3v2" fill="none" stroke="#000" stroke-width=".25"/>
<circle cx="162.3" cy="69.3" r=".51" fill="#000080"/>
<circle cx="162.3" cy="69.3" r=".51" fill="none" stroke="#000080" stroke-width=".21"/>
<path d="M162.3 77.4v2.1" fill="none" stroke="#000" stroke-width=".25"/>
<circle cx="162.3" cy="79.5" r=".51" fill="#000080"/>
<circle cx="162.3" cy="79.5" r=".51" fill="none" stroke="#000080" stroke-width=".21"/>
<path d="M161.4 71.4h2v6h-2z" fill="none" stroke="#00f" stroke-width=".25"/>
<circle cx="162.3" cy="84.5" r=".51" fill="#000080"/>
<circle cx="162.3" cy="84.5" r=".51" fill="none" stroke="#000080" stroke-width=".21"/>
<circle cx="162.3" cy="94.7" r=".51" fill="#000080"/>
<circle cx="162.3" cy="94.7" r=".51" fill="none" stroke="#000080" stroke-width=".21"/>
<path d="M162.3 84.5v2" fill="none" stroke="#000" stroke-width=".25"/>
<circle cx="162.3" cy="84.5" r=".51" fill="#000080"/>
<circle cx="162.3" cy="84.5" r=".51" fill="none" stroke="#000080" stroke-width=".21"/>
<path d="M162.3 92.7v2" fill="none" stroke="#000" stroke-width=".25"/>
<circle cx="162.3" cy="94.7" r=".51" fill="#000080"/>
<circle cx="162.3" cy="94.7" r=".51" fill="none" stroke="#000080" stroke-width=".21"/>
<path d="M161.4 86.6h2v6h-2z" fill="none" stroke="#00f" stroke-width=".25"/>
<circle cx="162.3" cy="99.8" r=".51" fill="#000080"/>
<circle cx="162.3" cy="99.8" r=".51" fill="none" stroke="#000080" stroke-width=".21"/>
<circle cx="162.3" cy="109.9" r=".51" fill="#000080"/>
<circle cx="162.3" cy="109.9" r=".51" fill="none" stroke="#000080" stroke-width=".21"/>
<path d="M162.3 99.8v2" fill="none" stroke="#000" stroke-width=".25"/>
<circle cx="162.3" cy="99.8" r=".51" fill="#000080"/>
<circle cx="162.3" cy="99.8" r=".51" fill="none" stroke="#000080" stroke-width=".21"/>
<path d="M162.3 107.9v2" fill="none" stroke="#000" stroke-width=".25"/>
<circle cx="162.3" cy="109.9" r=".51" fill="#000080"/>
<circle cx="162.3" cy="109.9" r=".51" fill="none" stroke="#000080" stroke-width=".21"/>
<path d="M161.4 101.8h2v6h-2z" fill="none" stroke="#00f" stroke-width=".25"/>
<circle cx="162.3" cy="115" r=".51" fill="#000080"/>
<circle cx="162.3" cy="115" r=".51" fill="none" stroke="#000080" stroke-width=".21"/>
<circle cx="162.3" cy="125.2" r=".51" fill="#000080"/>
<circle cx="162.3" cy="125.2" r=".51" fill="none" stroke="#000080" stroke-width=".21"/>
<path d="M162.3 115v2" fill="none" stroke="#000" stroke-width=".25"/>
<circle cx="162.3" cy="115" r=".51" fill="#000080"/>
<circle cx="162.3" cy="115" r=".51" fill="none" stroke="#000080" stroke-width=".21"/>
<path d="M162.3 123.2v2" fill="none" stroke="#000" stroke-width=".25"/>
<circle cx="162.3" cy="125.2" r=".51" fill="#000080"/>
<circle cx="162.3" cy="125.2" r=".51" fill="none" stroke="#000080" stroke-width=".21"/>
<path d="M161.4 117.1h2v6h-2z" fill="none" stroke="#00f" stroke-width=".25"/>
<circle cx="162.3" cy="130.2" r=".51" fill="#000080"/>
<circle cx="162.3" cy="130.2" r=".51" fill="none" stroke="#000080" stroke-width=".21"/>
<circle cx="162.3" cy="140.4" r=".51" fill="#000080"/>
<circle cx="162.3" cy="140.4" r=".51" fill="none" stroke="#000080" stroke-width=".21"/>
<path d="M162.3 130.2v2" fill="none" stroke="#000" stroke-width=".25"/>
<circle cx="162.3" cy="130.2" r=".51" fill="#000080"/>
<circle cx="162.3" cy="130.2" r=".51" fill="none" stroke="#000080" stroke-width=".21"/>
<path d="M162.3 138.4v2" fill="none" stroke="#000" stroke-width=".25"/>
<circle cx="162.3" cy="140.4" r=".51" fill="#000080"/>
<circle cx="162.3" cy="140.4" r=".51" fill="none" stroke="#000080" stroke-width=".21"/>
<path d="M161.4 132.3h2v6h-2z" fill="none" stroke="#00f" stroke-width=".25"/>
<circle cx="162.3" cy="145.5" r=".51" fill="#000080"/>
<circle cx="162.3" cy="145.5" r=".51" fill="none" stroke="#000080" stroke-width=".21"/>
<circle cx="162.3" cy="155.6" r=".51" fill="#000080"/>
<circle cx="162.3" cy="155.6" r=".51" fill="none" stroke="#000080" stroke-width=".21"/>
<path d="M162.3 145.5v2" fill="none" stroke="#000" stroke-width=".25"/>
<circle cx="162.3" cy="145.5" r=".51" fill="#000080"/>
<circle cx="162.3" cy="145.5" r=".51" fill="none" stroke="#000080" stroke-width=".21"/>
<path d="M162.3 153.6v2" fill="none" stroke="#000" stroke-width=".25"/>
<circle cx="162.3" cy="155.6" r=".51" fill="#000080"/>
<circle cx="162.3" cy="155.6" r=".51" fill="none" stroke="#000080" stroke-width=".21"/>
<path d="M161.4 147.6h2v6h-2z" fill="none" stroke="#00f" stroke-width=".25"/>
<circle cx="162.3" cy="160.7" r=".51" fill="#000080"/>
<circle cx="162.3" cy="160.7" r=".51" fill="none" stroke="#000080" stroke-width=".21"/>
<circle cx="162.3" cy="170.9" r=".51" fill="#000080"/>
<circle cx="162.3" cy="170.9" r=".51" fill="none" stroke="#000080" stroke-width=".21"/>
<path d="M162.3 160.7v2" fill="none" stroke="#000" stroke-width=".25"/>
<circle cx="162.3" cy="160.7" r=".51" fill="#000080"/>
<circle cx="162.3" cy="160.7" r=".51" fill="none" stroke="#000080" stroke-width=".21"/>
<path d="M162.3 168.9v2" fill="none" stroke="#000" stroke-width=".25"/>
<circle cx="162.3" cy="170.9" r=".51" fill="#000080"/>
<circle cx="162.3" cy="170.9" r=".51" fill="none" stroke="#000080" stroke-width=".21"/>
<path d="M161.4 162.8h2v6h-2z" fill="none" stroke="#00f" stroke-width=".25"/>
<path d="M157.3 23.6h20.3" fill="none" stroke="#000080" stroke-width=".25"/>
<circle cx="162.3" cy="23.6" r=".51" fill="#000080"/>
<circle cx="162.3" cy="23.6" r=".51" fill="none" stroke="#000080" stroke-width=".21"/>
<path d="M157.3 33.7h20.3" fill="none" stroke="#000080" stroke-width=".25"/>
<circle cx="162.3" cy="33.7" r=".51" fill="#000080"/>
<circle cx="162.3" cy="33.7" r=".51" fill="none" stroke="#000080" stroke-width=".21"/>
<path d="M157.3 38.8h20.3" fill="none" stroke="#000080" stroke-width=".25"/>
<circle cx="162.3" cy="38.8" r=".51" fill="#000080"/>
<circle cx="162.3" cy="38.8" r=".51" fill="none" stroke="#000080" stroke-width=".21"/>
<path d="M157.3 49h20.3" fill="none" stroke="#000080" stroke-width=".25"/>
<circle cx="162.3" cy="49" r=".51" fill="#000080"/>
<circle cx="162.3" cy="49" r=".51" fill="none" stroke="#000080" stroke-width=".21"/>
<path d="M157.3 54.1h20.3" fill="none" stroke="#000080" stroke-width=".25"/>
<circle cx="162.3" cy="54.1" r=".51" fill="#000080"/>
<circle cx="162.3" cy="54.1" r=".51" fill="none" stroke="#000080" stroke-width=".21"/>
<path d="M157.3 64.2h20.3" fill="none" stroke="#000080" stroke-width=".25"/>
<circle cx="162.3" cy="64.2" r=".51" fill="#000080"/>
<circle cx="162.3" cy="64.2" r=".51" fill="none" stroke="#000080" stroke-width=".21"/>
<path d="M157.3 69.3h20.3" fill="none" stroke="#000080" stroke-width=".25"/>
<circle cx="162.3" cy="69.3" r=".51" fill="#000080"/>
<circle cx="162.3" cy="69.3" r=".51" fill="none" stroke="#000080" stroke-width=".21"/>
<path d="M157.3 79.5h20.3" fill="none" stroke="#000080" stroke-width=".25"/>
<circle cx="162.3" cy="79.5" r=".51" fill="#000080"/>
<circle cx="162.3" cy="79.5" r=".51" fill="none" stroke="#000080" stroke-width=".21"/>
<path d="M157.3 84.5h20.3" fill="none" stroke="#000080" stroke-width=".25"/>
<circle cx="162.3" cy="84.5" r=".51" fill="#000080"/>
<circle cx="162.3" cy="84.5" r=".51" fill="none" stroke="#000080" stroke-width=".21"/>
<path d="M157.3 94.7h20.3" fill="none" stroke="#000080" stroke-width=".25"/>
<circle cx="162.3" cy="94.7" r=".51" fill="#000080"/>
<circle cx="162.3" cy="94.7" r=".51" fill="none" stroke="#000080" stroke-width=".21"/>
<path d="M157.3 99.8h20.3" fill="none" stroke="#000080" stroke-width=".25"/>
<circle cx="162.3" cy="99.8" r=".51" fill="#000080"/>
<circle cx="162.3" cy="99.8" r=".51" fill="none" stroke="#000080" stroke-width=".21"/>
<path d="M157.3 109.9h20.3" fill="none" stroke="#000080" stroke-width=".25"/>
<circle cx="162.3" cy="109.9" r=".51" fill="#000080"/>
<circle cx="162.3" cy="109.9" r=".51" fill="none" stroke="#000080" stroke-width=".21"/>
<path d="M157.3 115h20.3" fill="none" stroke="#000080" stroke-width=".25"/>
<circle cx="162.3" cy="115" r=".51" fill="#000080"/>
<circle cx="162.3" cy="115" r=".51" fill="none" stroke="#000080" stroke-width=".21"/>
<path d="M157.3 125.2h20.3" fill="none" stroke="#000080" stroke-width=".25"/>
<circle cx="162.3" cy="125.2" r=".51" fill="#000080"/>
<circle cx="162.3" cy="125.2" r=".51" fill="none" stroke="#000080" stroke-width=".21"/>
<path d="M157.3 130.2h20.3" fill="none" stroke="#000080" stroke-width=".25"/>
<circle cx="162.3" cy="130.2" r=".51" fill="#000080"/>
<circle cx="162.3" cy="130.2" r=".51" fill="none" stroke="#000080" stroke-width=".21"/>
<path d="M157.3 140.4h20.3" fill="none" stroke="#000080" stroke-width=".25"/>
<circle cx="162.3" cy="140.4" r=".51" fill="#000080"/>
<circle cx="162.3" cy="140.4" r=".51" fill="none" stroke="#000080" stroke-width=".21"/>
<path d="M157.3 145.5h20.3" fill="none" stroke="#000080" stroke-width=".25"/>
<circle cx="162.3" cy="145.5" r=".51" fill="#000080"/>
<circle cx="162.3" cy="145.5" r=".51" fill="none" stroke="#000080" stroke-width=".21"/>
<path d="M157.3 155.6h20.3" fill="none" stroke="#000080" stroke-width=".25"/>
<circle cx="162.3" cy="155.6" r=".51" fill="#000080"/>
<circle cx="162.3" cy="155.6" r=".51" fill="none" stroke="#000080" stroke-width=".21"/>
<path d="M157.3 160.7h20.3" fill="none" stroke="#000080" stroke-width=".25"/>
<circle cx="162.3" cy="160.7" r=".51" fill="#000080"/>
<circle cx="162.3" cy="160.7" r=".51" fill="none" stroke="#000080" stroke-width=".21"/>
<path d="M157.3 170.9h20.3" fill="none" stroke="#000080" stroke-width=".25"/>
<circle cx="162.3" cy="170.9" r=".51" fill="#000080"/>
<circle cx="162.3" cy="170.9" r=".51" fill="none" stroke="#000080" stroke-width=".21"/>
<g fill="none" stroke="#000080" stroke-width=".25">
<path d="M91.2 36.3h20.3M91.2 38.8h20.3M91.2 41.4h20.3M91.2 43.9h20.3M91.2 46.4h20.3M91.2 49h20.3M91.2 51.5h20.3M91.2 54.1h20.3M91.2 56.6h20.3M91.2 59.1h20.3M91.2 61.7h20.3M91.2 64.2h20.3"/>
<path d="M91.2 66.8h20.3M91.2 69.3h20.3M91.2 71.8h20.3M91.2 74.4h20.3M91.2 76.9h20.3M91.2 79.5h20.3M91.2 82h20.3M91.2 84.5h20.3M91.2 87.1h20.3M91.2 89.6h20.3M91.2 92.1h20.3M91.2 94.7h20.3"/>
<path d="M91.2 97.2h20.3M91.2 99.8h20.3M91.2 109.9h20.3M91.2 112.5h20.3M91.2 104.8h20.3M91.2 107.4h20.3M91.2 102.3h20.3M91.2 115h20.3M91.2 117.5h20.3M91.2 135.3h20.3M91.2 137.9h20.3M91.2 130.2h20.3"/>
<path d="M91.2 132.8h20.3M91.2 125.2h20.3M91.2 127.7h20.3M91.2 120.1h20.3M91.2 122.6h20.3M91.2 155.6h20.3M91.2 158.2h20.3M91.2 150.6h20.3M91.2 153.1h20.3M91.2 145.5h20.3M91.2 148h20.3M91.2 140.4h20.3"/>
<path d="M91.2 142.9h20.3M91.2 160.7h20.3"/>
</g>
<use href="#words"/>
</svg>
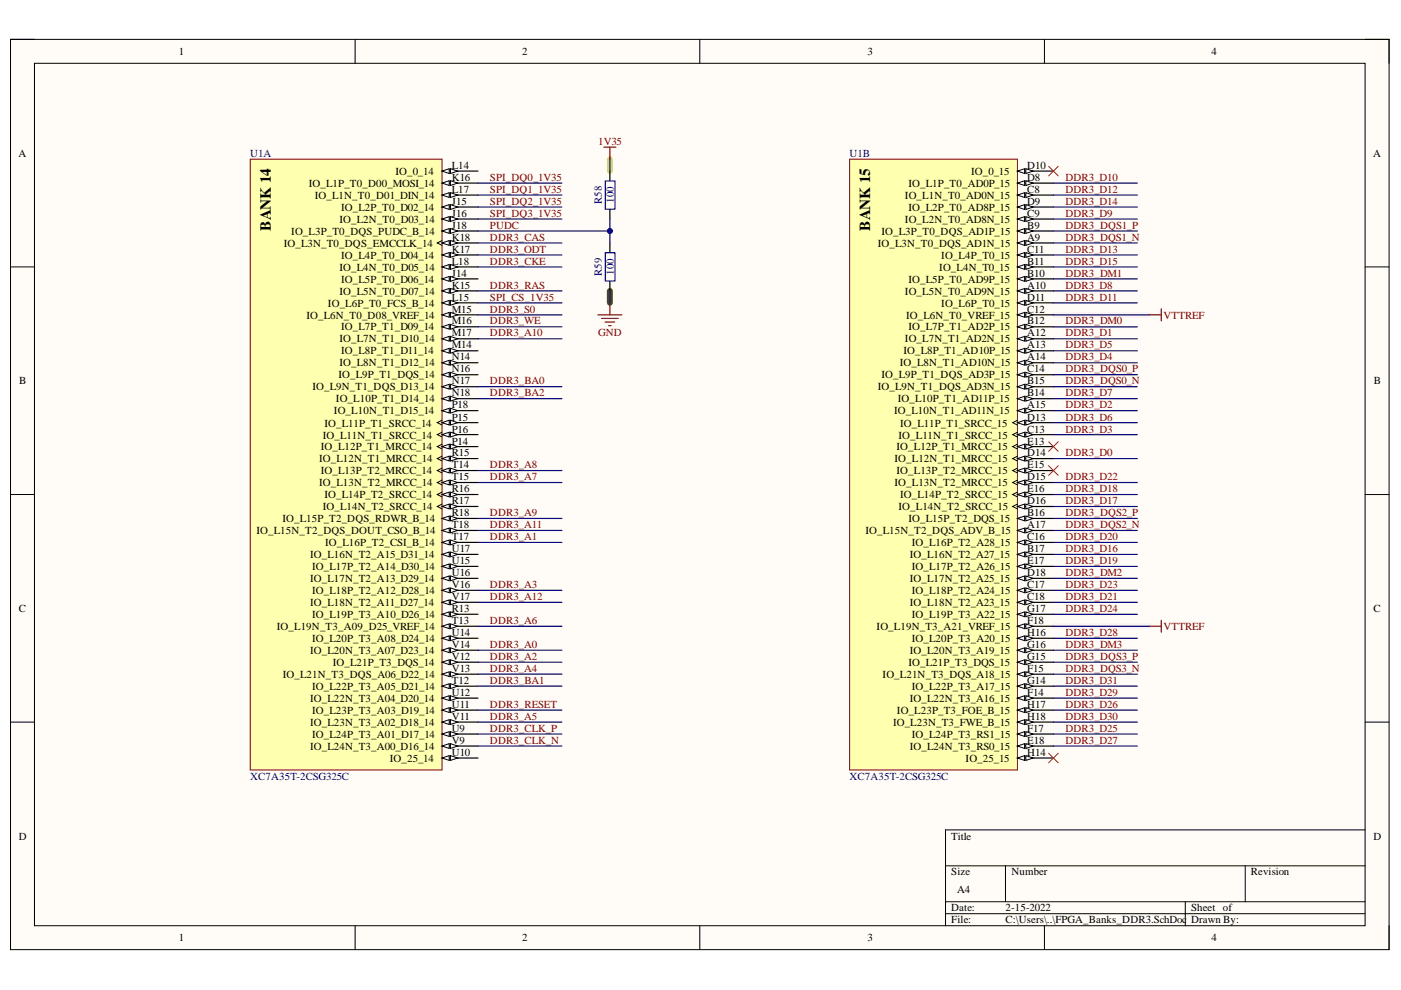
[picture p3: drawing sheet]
<svg xmlns="http://www.w3.org/2000/svg" width="297mm" height="210mm" viewBox="0 0 297 210" stroke-linecap="round" stroke-linejoin="round" font-family="sans-serif">
<defs><g id="words">
<g font-size="3.2">
<text x="57.4" y="48.9" transform="rotate(-90 57.4 48.9)">BANK 14</text>
<text x="184.5" y="48.9" transform="rotate(-90 184.5 48.9)">BANK 15</text>
</g>
<g font-size="2.3">
<text x="37.9" y="11.7">1</text>
<text x="110.7" y="11.7">2</text>
<text x="183.9" y="11.7">3</text>
<text x="256.8" y="11.7">4</text>
<text x="3.9" y="33.3">A</text>
<text x="95.8" y="35.8">L14</text>
<text x="217.8" y="35.8">D10</text>
<text x="291.1" y="33.3">A</text>
<text x="65.5" y="39.6">IO_L1P_T0_D00_MOSI_14</text>
<text x="83.8" y="37.1">IO_0_14</text>
<text x="95.8" y="38.4">K16</text>
<text x="95.8" y="40.9">L17</text>
<text x="192.6" y="39.6">IO_L1P_T0_AD0P_15</text>
<text x="205.9" y="37.1">IO_0_15</text>
<text x="217.8" y="38.4">D8</text>
<text x="217.8" y="40.9">C8</text>
<text x="66.7" y="42.2">IO_L1N_T0_D01_DIN_14</text>
<text x="72" y="47.2">IO_L2N_T0_D03_14</text>
<text x="72.3" y="44.7">IO_L2P_T0_D02_14</text>
<text x="95.8" y="43.4">J15</text>
<text x="95.8" y="46">J16</text>
<text x="191.9" y="42.2">IO_L1N_T0_AD0N_15</text>
<text x="191.9" y="47.2">IO_L2N_T0_AD8N_15</text>
<text x="192.6" y="44.7">IO_L2P_T0_AD8P_15</text>
<text x="217.8" y="43.4">D9</text>
<text x="217.8" y="46">C9</text>
<text x="60.2" y="52.3">IO_L3N_T0_DQS_EMCCLK_14</text>
<text x="61.8" y="49.8">IO_L3P_T0_DQS_PUDC_B_14</text>
<text x="95.8" y="48.5">J18</text>
<text x="95.8" y="51">K18</text>
<text x="95.8" y="53.6">K17</text>
<text x="186.1" y="52.3">IO_L3N_T0_DQS_AD1N_15</text>
<text x="186.9" y="49.8">IO_L3P_T0_DQS_AD1P_15</text>
<text x="217.8" y="48.5">B9</text>
<text x="217.8" y="51">A9</text>
<text x="217.8" y="53.6">C11</text>
<text x="72" y="57.4">IO_L4N_T0_D05_14</text>
<text x="72.3" y="54.9">IO_L4P_T0_D04_14</text>
<text x="72.3" y="59.9">IO_L5P_T0_D06_14</text>
<text x="95.8" y="56.1">L18</text>
<text x="95.8" y="58.7">J14</text>
<text x="192.6" y="59.9">IO_L5P_T0_AD9P_15</text>
<text x="199.1" y="57.4">IO_L4N_T0_15</text>
<text x="199.6" y="54.9">IO_L4P_T0_15</text>
<text x="217.8" y="56.1">B11</text>
<text x="217.8" y="58.7">B10</text>
<text x="69.5" y="65">IO_L6P_T0_FCS_B_14</text>
<text x="72" y="62.5">IO_L5N_T0_D07_14</text>
<text x="95.8" y="61.2">K15</text>
<text x="95.8" y="63.7">L15</text>
<text x="191.9" y="62.5">IO_L5N_T0_AD9N_15</text>
<text x="199.6" y="65">IO_L6P_T0_15</text>
<text x="217.8" y="61.2">A10</text>
<text x="217.8" y="63.7">D11</text>
<text x="65" y="67.5">IO_L6N_T0_D08_VREF_14</text>
<text x="72.3" y="70.1">IO_L7P_T1_D09_14</text>
<text x="95.8" y="66.3">M15</text>
<text x="95.8" y="68.8">M16</text>
<text x="95.8" y="71.3">M17</text>
<text x="192.1" y="67.5">IO_L6N_T0_VREF_15</text>
<text x="192.6" y="70.1">IO_L7P_T1_AD2P_15</text>
<text x="217.8" y="66.3">C12</text>
<text x="217.8" y="68.8">B12</text>
<text x="217.8" y="71.3">A12</text>
<text x="72" y="72.6">IO_L7N_T1_D10_14</text>
<text x="72" y="77.7">IO_L8N_T1_D12_14</text>
<text x="72.3" y="75.1">IO_L8P_T1_D11_14</text>
<text x="95.8" y="73.9">M14</text>
<text x="95.8" y="76.4">N14</text>
<text x="190.8" y="77.7">IO_L8N_T1_AD10N_15</text>
<text x="191.5" y="75.1">IO_L8P_T1_AD10P_15</text>
<text x="191.9" y="72.6">IO_L7N_T1_AD2N_15</text>
<text x="217.8" y="73.9">A13</text>
<text x="217.8" y="76.4">A14</text>
<text x="4.1" y="81.5">B</text>
<text x="66.2" y="82.7">IO_L9N_T1_DQS_D13_14</text>
<text x="71.7" y="80.2">IO_L9P_T1_DQS_14</text>
<text x="95.8" y="78.9">N16</text>
<text x="95.8" y="81.5">N17</text>
<text x="186.1" y="82.7">IO_L9N_T1_DQS_AD3N_15</text>
<text x="186.9" y="80.2">IO_L9P_T1_DQS_AD3P_15</text>
<text x="217.8" y="78.9">C14</text>
<text x="217.8" y="81.5">B15</text>
<text x="291.3" y="81.5">B</text>
<text x="70.8" y="87.8">IO_L10N_T1_D15_14</text>
<text x="71.2" y="85.3">IO_L10P_T1_D14_14</text>
<text x="95.8" y="84">N18</text>
<text x="95.8" y="86.6">P18</text>
<text x="95.8" y="89.2">P15</text>
<text x="189.6" y="87.8">IO_L10N_T1_AD11N_15</text>
<text x="190.3" y="85.3">IO_L10P_T1_AD11P_15</text>
<text x="217.8" y="84">B14</text>
<text x="217.8" y="86.6">A15</text>
<text x="217.8" y="89.2">D13</text>
<text x="68" y="95.5">IO_L12P_T1_MRCC_14</text>
<text x="68.4" y="93">IO_L11N_T1_SRCC_14</text>
<text x="68.8" y="90.4">IO_L11P_T1_SRCC_14</text>
<text x="95.8" y="91.7">P16</text>
<text x="95.8" y="94.2">P14</text>
<text x="190.1" y="95.5">IO_L12P_T1_MRCC_15</text>
<text x="190.5" y="93">IO_L11N_T1_SRCC_15</text>
<text x="190.9" y="90.4">IO_L11P_T1_SRCC_15</text>
<text x="217.8" y="91.7">C13</text>
<text x="217.8" y="94.2">E13</text>
<text x="67.7" y="98">IO_L12N_T1_MRCC_14</text>
<text x="68" y="100.6">IO_L13P_T2_MRCC_14</text>
<text x="95.8" y="96.8">R15</text>
<text x="95.8" y="99.3">T14</text>
<text x="95.8" y="101.9">T15</text>
<text x="189.7" y="98">IO_L12N_T1_MRCC_15</text>
<text x="190.1" y="100.6">IO_L13P_T2_MRCC_15</text>
<text x="217.8" y="96.8">D14</text>
<text x="217.8" y="99.3">E15</text>
<text x="217.8" y="101.9">D15</text>
<text x="67.7" y="103.1">IO_L13N_T2_MRCC_14</text>
<text x="68.8" y="105.7">IO_L14P_T2_SRCC_14</text>
<text x="95.8" y="104.4">R16</text>
<text x="95.8" y="106.9">R17</text>
<text x="189.7" y="103.1">IO_L13N_T2_MRCC_15</text>
<text x="190.9" y="105.7">IO_L14P_T2_SRCC_15</text>
<text x="217.8" y="104.4">E16</text>
<text x="217.8" y="106.9">D16</text>
<text x="54.4" y="113.3">IO_L15N_T2_DQS_DOUT_CSO_B_14</text>
<text x="59.9" y="110.7">IO_L15P_T2_DQS_RDWR_B_14</text>
<text x="68.4" y="108.2">IO_L14N_T2_SRCC_14</text>
<text x="95.8" y="109.5">R18</text>
<text x="95.8" y="112">T18</text>
<text x="183.5" y="113.3">IO_L15N_T2_DQS_ADV_B_15</text>
<text x="190.5" y="108.2">IO_L14N_T2_SRCC_15</text>
<text x="192.6" y="110.7">IO_L15P_T2_DQS_15</text>
<text x="217.8" y="109.5">B16</text>
<text x="217.8" y="112">A17</text>
<text x="65.7" y="118.3">IO_L16N_T2_A15_D31_14</text>
<text x="68.9" y="115.8">IO_L16P_T2_CSI_B_14</text>
<text x="95.8" y="114.5">T17</text>
<text x="95.8" y="117.1">U17</text>
<text x="95.8" y="119.6">U15</text>
<text x="192.9" y="118.3">IO_L16N_T2_A27_15</text>
<text x="193.3" y="115.8">IO_L16P_T2_A28_15</text>
<text x="217.8" y="114.5">C16</text>
<text x="217.8" y="117.1">B17</text>
<text x="217.8" y="119.6">E17</text>
<text x="65.7" y="123.4">IO_L17N_T2_A13_D29_14</text>
<text x="66.2" y="120.9">IO_L17P_T2_A14_D30_14</text>
<text x="66.2" y="125.9">IO_L18P_T2_A12_D28_14</text>
<text x="95.8" y="122.1">U16</text>
<text x="95.8" y="124.7">V16</text>
<text x="192.9" y="123.4">IO_L17N_T2_A25_15</text>
<text x="193.3" y="120.9">IO_L17P_T2_A26_15</text>
<text x="193.3" y="125.9">IO_L18P_T2_A24_15</text>
<text x="217.8" y="122.1">D18</text>
<text x="217.8" y="124.7">C17</text>
<text x="4" y="129.7">C</text>
<text x="65.7" y="128.5">IO_L18N_T2_A11_D27_14</text>
<text x="66.2" y="131">IO_L19P_T3_A10_D26_14</text>
<text x="95.8" y="127.2">V17</text>
<text x="95.8" y="129.7">R13</text>
<text x="192.9" y="128.5">IO_L18N_T2_A23_15</text>
<text x="193.3" y="131">IO_L19P_T3_A22_15</text>
<text x="217.8" y="127.2">C18</text>
<text x="217.8" y="129.7">G17</text>
<text x="291.2" y="129.7">C</text>
<text x="58.7" y="133.6">IO_L19N_T3_A09_D25_VREF_14</text>
<text x="66.2" y="136.1">IO_L20P_T3_A08_D24_14</text>
<text x="95.8" y="132.3">T13</text>
<text x="95.8" y="134.8">U14</text>
<text x="95.8" y="137.4">V14</text>
<text x="185.9" y="133.6">IO_L19N_T3_A21_VREF_15</text>
<text x="193.3" y="136.1">IO_L20P_T3_A20_15</text>
<text x="217.8" y="132.3">F18</text>
<text x="217.8" y="134.8">H16</text>
<text x="217.8" y="137.4">G16</text>
<text x="60" y="143.7">IO_L21N_T3_DQS_A06_D22_14</text>
<text x="65.7" y="138.6">IO_L20N_T3_A07_D23_14</text>
<text x="70.6" y="141.2">IO_L21P_T3_DQS_14</text>
<text x="95.8" y="139.9">V12</text>
<text x="95.8" y="142.4">V13</text>
<text x="187.1" y="143.7">IO_L21N_T3_DQS_A18_15</text>
<text x="192.6" y="141.2">IO_L21P_T3_DQS_15</text>
<text x="192.9" y="138.6">IO_L20N_T3_A19_15</text>
<text x="217.8" y="139.9">G15</text>
<text x="217.8" y="142.4">F15</text>
<text x="65.7" y="148.9">IO_L22N_T3_A04_D20_14</text>
<text x="66.2" y="146.2">IO_L22P_T3_A05_D21_14</text>
<text x="95.8" y="145">T12</text>
<text x="95.8" y="147.5">U12</text>
<text x="192.9" y="148.9">IO_L22N_T3_A16_15</text>
<text x="193.3" y="146.2">IO_L22P_T3_A17_15</text>
<text x="217.8" y="145">G14</text>
<text x="217.8" y="147.5">F14</text>
<text x="65.7" y="153.9">IO_L23N_T3_A02_D18_14</text>
<text x="66.2" y="151.4">IO_L23P_T3_A03_D19_14</text>
<text x="95.8" y="150.1">U11</text>
<text x="95.8" y="152.7">V11</text>
<text x="95.8" y="155.2">U9</text>
<text x="189.3" y="153.9">IO_L23N_T3_FWE_B_15</text>
<text x="190.2" y="151.4">IO_L23P_T3_FOE_B_15</text>
<text x="217.8" y="150.1">H17</text>
<text x="217.8" y="152.7">H18</text>
<text x="217.8" y="155.2">F17</text>
<text x="65.7" y="159">IO_L24N_T3_A00_D16_14</text>
<text x="66.2" y="156.5">IO_L24P_T3_A01_D17_14</text>
<text x="82.7" y="161.5">IO_25_14</text>
<text x="95.8" y="157.7">V9</text>
<text x="95.8" y="160.3">U10</text>
<text x="192.9" y="159">IO_L24N_T3_RS0_15</text>
<text x="193.3" y="156.5">IO_L24P_T3_RS1_15</text>
<text x="204.7" y="161.5">IO_25_15</text>
<text x="217.8" y="157.7">E18</text>
<text x="217.8" y="160.3">H14</text>
<text x="4" y="178">D</text>
<text x="201.7" y="178">Title</text>
<text x="291.2" y="178">D</text>
<text x="201.7" y="185.6">Size</text>
<text x="214.5" y="185.6">Number</text>
<text x="265.2" y="185.6">Revision</text>
<text x="203" y="189.4">A4</text>
<text x="201.7" y="193.2">Date:</text>
<text x="201.7" y="195.8">File:</text>
<text x="213.2" y="193.2">2-15-2022</text>
<text x="213.2" y="195.8">C:\Users\..\FPGA_Banks_DDR3.SchDoc</text>
<text x="252.5" y="193.2">Sheet of</text>
<text x="252.5" y="195.8">Drawn By:</text>
<text x="37.9" y="199.6">1</text>
<text x="110.7" y="199.6">2</text>
<text x="183.9" y="199.6">3</text>
<text x="256.8" y="199.6">4</text>
</g>
<g font-size="2.3" fill="#000080">
<text x="53" y="33.3">U1A</text>
<text x="180.1" y="33.3">U1B</text>
<text x="127.6" y="43.2" transform="rotate(-90 127.6 43.2)">R58</text>
<text x="130.1" y="43" transform="rotate(-90 130.1 43)">100</text>
<text x="127.6" y="58.5" transform="rotate(-90 127.6 58.5)">R59</text>
<text x="130.1" y="58.2" transform="rotate(-90 130.1 58.2)">100</text>
<text x="53" y="165.3">XC7A35T-2CSG325C</text>
<text x="180.1" y="165.3">XC7A35T-2CSG325C</text>
</g>
<g font-size="2.3" fill="#800000">
<text x="126.8" y="30.8">1V35</text>
<text x="103.9" y="38.4">SPI_DQ0_1V35</text>
<text x="103.9" y="40.9">SPI_DQ1_1V35</text>
<text x="225.9" y="38.4">DDR3_D10</text>
<text x="225.9" y="40.9">DDR3_D12</text>
<text x="103.9" y="43.4">SPI_DQ2_1V35</text>
<text x="103.9" y="46">SPI_DQ3_1V35</text>
<text x="225.9" y="43.4">DDR3_D14</text>
<text x="225.9" y="46">DDR3_D9</text>
<text x="103.9" y="53.6">DDR3_ODT</text>
<text x="103.9" y="51">DDR3_CAS</text>
<text x="103.9" y="48.5">PUDC</text>
<text x="225.9" y="48.5">DDR3_DQS1_P</text>
<text x="225.9" y="51">DDR3_DQS1_N</text>
<text x="225.9" y="53.6">DDR3_D13</text>
<text x="103.9" y="56.1">DDR3_CKE</text>
<text x="225.9" y="58.7">DDR3_DM1</text>
<text x="225.9" y="56.1">DDR3_D15</text>
<text x="103.9" y="63.7">SPI_CS_1V35</text>
<text x="103.9" y="61.2">DDR3_RAS</text>
<text x="225.9" y="61.2">DDR3_D8</text>
<text x="225.9" y="63.7">DDR3_D11</text>
<text x="103.9" y="66.3">DDR3_S0</text>
<text x="103.9" y="68.8">DDR3_WE</text>
<text x="103.9" y="71.3">DDR3_A10</text>
<text x="126.8" y="71.3">GND</text>
<text x="225.9" y="71.3">DDR3_D1</text>
<text x="225.9" y="68.8">DDR3_DM0</text>
<text x="246.7" y="67.5">VTTREF</text>
<text x="225.9" y="76.4">DDR3_D4</text>
<text x="225.9" y="73.9">DDR3_D5</text>
<text x="103.9" y="81.5">DDR3_BA0</text>
<text x="225.9" y="78.9">DDR3_DQS0_P</text>
<text x="225.9" y="81.5">DDR3_DQS0_N</text>
<text x="103.9" y="84">DDR3_BA2</text>
<text x="225.9" y="89.2">DDR3_D6</text>
<text x="225.9" y="84">DDR3_D7</text>
<text x="225.9" y="86.6">DDR3_D2</text>
<text x="225.9" y="91.7">DDR3_D3</text>
<text x="103.9" y="99.3">DDR3_A8</text>
<text x="103.9" y="101.9">DDR3_A7</text>
<text x="225.9" y="96.8">DDR3_D0</text>
<text x="225.9" y="101.9">DDR3_D22</text>
<text x="225.9" y="106.9">DDR3_D17</text>
<text x="225.9" y="104.4">DDR3_D18</text>
<text x="103.9" y="112">DDR3_A11</text>
<text x="103.9" y="109.5">DDR3_A9</text>
<text x="225.9" y="109.5">DDR3_DQS2_P</text>
<text x="225.9" y="112">DDR3_DQS2_N</text>
<text x="103.9" y="114.5">DDR3_A1</text>
<text x="225.9" y="114.5">DDR3_D20</text>
<text x="225.9" y="119.6">DDR3_D19</text>
<text x="225.9" y="117.1">DDR3_D16</text>
<text x="103.9" y="124.7">DDR3_A3</text>
<text x="225.9" y="124.7">DDR3_D23</text>
<text x="225.9" y="122.1">DDR3_DM2</text>
<text x="103.9" y="127.2">DDR3_A12</text>
<text x="225.9" y="129.7">DDR3_D24</text>
<text x="225.9" y="127.2">DDR3_D21</text>
<text x="103.9" y="132.3">DDR3_A6</text>
<text x="103.9" y="137.4">DDR3_A0</text>
<text x="225.9" y="134.8">DDR3_D28</text>
<text x="225.9" y="137.4">DDR3_DM3</text>
<text x="246.7" y="133.6">VTTREF</text>
<text x="103.9" y="139.9">DDR3_A2</text>
<text x="103.9" y="142.4">DDR3_A4</text>
<text x="225.9" y="139.9">DDR3_DQS3_P</text>
<text x="225.9" y="142.4">DDR3_DQS3_N</text>
<text x="103.9" y="145">DDR3_BA1</text>
<text x="225.9" y="145">DDR3_D31</text>
<text x="225.9" y="147.5">DDR3_D29</text>
<text x="103.9" y="150.1">DDR3_RESET</text>
<text x="103.9" y="155.2">DDR3_CLK_P</text>
<text x="103.9" y="152.7">DDR3_A5</text>
<text x="225.9" y="152.7">DDR3_D30</text>
<text x="225.9" y="150.1">DDR3_D26</text>
<text x="225.9" y="155.2">DDR3_D25</text>
<text x="103.9" y="157.7">DDR3_CLK_N</text>
<text x="225.9" y="157.7">DDR3_D27</text>
</g>
</g></defs>
<path d="M2.2 8.3h292.3v193h-292.3z" fill-rule="evenodd" fill="#fffcf8"/>
<path d="M2.2 8.3h292.3v193h-292.3z" fill="none" stroke="#000" stroke-width=".21"/>
<path d="M7.3 13.4h282.1v182.9h-282.1z" fill-rule="evenodd" fill="#fffcf8"/>
<g fill="none" stroke="#000" stroke-width=".21">
<path d="M2.2 8.3h5.1M7.3 13.4h282.1v182.9h-282.1zM75.3 8.3v5.1M148.4 8.3v5.1M221.4 8.3v5.1M289.4 8.3h5.1v5.1M2.2 56.6h5.1M289.4 56.6h5.1M2.2 104.8h5.1M289.4 104.9h5.1M2.2 153.1h5.1M289.4 153.1h5.1"/>
<path d="M289.4 176h-88.9v20.3M75.3 196.3v5M148.4 196.3v5M200.5 183.6h88.9M200.5 191.2h88.9M200.5 193.7h88.9M213.2 183.6v7.6M221.4 196.3v5M251.3 191.2v5.1M264 183.6v7.6M294.5 196.3v5"/>
</g>
<path d="M223.3 66.8h20.4M223.3 132.8h20.4" fill="none" stroke="#fff0ff" stroke-width="1.3"/>
<path d="M129.3 61.7v2.5" fill="none" stroke="#00be00" stroke-width="1.3"/>
<path d="M129.3 33.7v2.6" fill="none" stroke="#ff0" stroke-width="1.3"/>
<path d="M53.1 33.7h40.6v129.6h-40.6z" fill-rule="evenodd" fill="#ffffb0"/>
<path d="M53.1 33.7h40.6v129.6h-40.6z" fill="none" stroke="#800000" stroke-width=".21"/>
<path d="M93.7 36.3h7.6" fill="none" stroke="#000" stroke-width=".25"/>
<path d="M93.7 36.3l1.5-.5v1z" fill="#f8fcff"/>
<path d="M93.7 36.3l1.5-.5v1z" fill="none" stroke="#000" stroke-width=".21"/>
<path d="M95.5 35.8l1.5 .5-1.5 .5z" fill="#f8fcff"/>
<path d="M95.5 35.8l1.5 .5-1.5 .5z" fill="none" stroke="#000" stroke-width=".21"/>
<path d="M93.7 38.8h7.6" fill="none" stroke="#000" stroke-width=".25"/>
<path d="M93.7 38.8l1.5-.5v1z" fill="#f8fcff"/>
<path d="M93.7 38.8l1.5-.5v1z" fill="none" stroke="#000" stroke-width=".21"/>
<path d="M95.5 38.3l1.5 .5-1.5 .5z" fill="#f8fcff"/>
<path d="M95.5 38.3l1.5 .5-1.5 .5z" fill="none" stroke="#000" stroke-width=".21"/>
<path d="M93.7 41.4h7.6" fill="none" stroke="#000" stroke-width=".25"/>
<path d="M93.7 41.4l1.5-.5v1z" fill="#f8fcff"/>
<path d="M93.7 41.4l1.5-.5v1z" fill="none" stroke="#000" stroke-width=".21"/>
<path d="M95.5 40.9l1.5 .5-1.5 .5z" fill="#f8fcff"/>
<path d="M95.5 40.9l1.5 .5-1.5 .5z" fill="none" stroke="#000" stroke-width=".21"/>
<path d="M93.7 43.9h7.6" fill="none" stroke="#000" stroke-width=".25"/>
<path d="M93.7 43.9l1.5-.5v1z" fill="#f8fcff"/>
<path d="M93.7 43.9l1.5-.5v1z" fill="none" stroke="#000" stroke-width=".21"/>
<path d="M95.5 43.4l1.5 .5-1.5 .5z" fill="#f8fcff"/>
<path d="M95.5 43.4l1.5 .5-1.5 .5z" fill="none" stroke="#000" stroke-width=".21"/>
<path d="M93.7 46.4h7.6" fill="none" stroke="#000" stroke-width=".25"/>
<path d="M93.7 46.4l1.5-.5v1z" fill="#f8fcff"/>
<path d="M93.7 46.4l1.5-.5v1z" fill="none" stroke="#000" stroke-width=".21"/>
<path d="M95.5 45.9l1.5 .5-1.5 .5z" fill="#f8fcff"/>
<path d="M95.5 45.9l1.5 .5-1.5 .5z" fill="none" stroke="#000" stroke-width=".21"/>
<path d="M93.7 49h7.6" fill="none" stroke="#000" stroke-width=".25"/>
<path d="M93.7 49l1.5-.5v1z" fill="#f8fcff"/>
<path d="M93.7 49l1.5-.5v1z" fill="none" stroke="#000" stroke-width=".21"/>
<path d="M95.5 48.5l1.5 .5-1.5 .5z" fill="#f8fcff"/>
<path d="M95.5 48.5l1.5 .5-1.5 .5z" fill="none" stroke="#000" stroke-width=".21"/>
<path d="M93.7 51.5h7.6" fill="none" stroke="#000" stroke-width=".25"/>
<path d="M93.7 51.5l1.5-.5v1z" fill="#f8fcff"/>
<path d="M93.7 51.5l1.5-.5v1z" fill="none" stroke="#000" stroke-width=".21"/>
<path d="M95.5 51l1.5 .5-1.5 .5z" fill="#f8fcff"/>
<path d="M93.7 51l-1 .5 1 .5M95.5 51l1.5 .5-1.5 .5z" fill="none" stroke="#000" stroke-width=".21"/>
<path d="M93.7 54.1h7.6" fill="none" stroke="#000" stroke-width=".25"/>
<path d="M93.7 54.1l1.5-.6v1.1z" fill="#f8fcff"/>
<path d="M93.7 54.1l1.5-.6v1.1z" fill="none" stroke="#000" stroke-width=".21"/>
<path d="M95.5 53.5l1.5 .6-1.5 .5z" fill="#f8fcff"/>
<path d="M95.5 53.5l1.5 .6-1.5 .5z" fill="none" stroke="#000" stroke-width=".21"/>
<path d="M93.7 56.6h7.6" fill="none" stroke="#000" stroke-width=".25"/>
<path d="M93.7 56.6l1.5-.5v1z" fill="#f8fcff"/>
<path d="M93.7 56.6l1.5-.5v1z" fill="none" stroke="#000" stroke-width=".21"/>
<path d="M95.5 56.1l1.5 .5-1.5 .5z" fill="#f8fcff"/>
<path d="M95.5 56.1l1.5 .5-1.5 .5z" fill="none" stroke="#000" stroke-width=".21"/>
<path d="M93.7 59.1h7.6" fill="none" stroke="#000" stroke-width=".25"/>
<path d="M93.7 59.1l1.5-.5v1z" fill="#f8fcff"/>
<path d="M93.7 59.1l1.5-.5v1z" fill="none" stroke="#000" stroke-width=".21"/>
<path d="M95.5 58.6l1.5 .5-1.5 .5z" fill="#f8fcff"/>
<path d="M95.5 58.6l1.5 .5-1.5 .5z" fill="none" stroke="#000" stroke-width=".21"/>
<path d="M93.7 61.7h7.6" fill="none" stroke="#000" stroke-width=".25"/>
<path d="M93.7 61.7l1.5-.5v1z" fill="#f8fcff"/>
<path d="M93.7 61.7l1.5-.5v1z" fill="none" stroke="#000" stroke-width=".21"/>
<path d="M95.5 61.2l1.5 .5-1.5 .5z" fill="#f8fcff"/>
<path d="M95.5 61.2l1.5 .5-1.5 .5z" fill="none" stroke="#000" stroke-width=".21"/>
<path d="M93.7 64.2h7.6" fill="none" stroke="#000" stroke-width=".25"/>
<path d="M93.7 64.2l1.5-.5v1z" fill="#f8fcff"/>
<path d="M93.7 64.2l1.5-.5v1z" fill="none" stroke="#000" stroke-width=".21"/>
<path d="M95.5 63.7l1.5 .5-1.5 .5z" fill="#f8fcff"/>
<path d="M95.5 63.7l1.5 .5-1.5 .5z" fill="none" stroke="#000" stroke-width=".21"/>
<path d="M93.7 66.8h7.6" fill="none" stroke="#000" stroke-width=".25"/>
<path d="M93.7 66.8l1.5-.6v1.1z" fill="#f8fcff"/>
<path d="M93.7 66.8l1.5-.6v1.1z" fill="none" stroke="#000" stroke-width=".21"/>
<path d="M95.5 66.2l1.5 .6-1.5 .5z" fill="#f8fcff"/>
<path d="M95.5 66.2l1.5 .6-1.5 .5z" fill="none" stroke="#000" stroke-width=".21"/>
<path d="M93.7 69.3h7.6" fill="none" stroke="#000" stroke-width=".25"/>
<path d="M93.7 69.3l1.5-.5v1z" fill="#f8fcff"/>
<path d="M93.7 69.3l1.5-.5v1z" fill="none" stroke="#000" stroke-width=".21"/>
<path d="M95.5 68.8l1.5 .5-1.5 .5z" fill="#f8fcff"/>
<path d="M95.5 68.8l1.5 .5-1.5 .5z" fill="none" stroke="#000" stroke-width=".21"/>
<path d="M93.7 71.8h7.6" fill="none" stroke="#000" stroke-width=".25"/>
<path d="M93.7 71.8l1.5-.5v1z" fill="#f8fcff"/>
<path d="M93.7 71.8l1.5-.5v1z" fill="none" stroke="#000" stroke-width=".21"/>
<path d="M95.5 71.3l1.5 .5-1.5 .5z" fill="#f8fcff"/>
<path d="M95.5 71.3l1.5 .5-1.5 .5z" fill="none" stroke="#000" stroke-width=".21"/>
<path d="M93.7 74.4h7.6" fill="none" stroke="#000" stroke-width=".25"/>
<path d="M93.7 74.4l1.5-.5v1z" fill="#f8fcff"/>
<path d="M93.7 74.4l1.5-.5v1z" fill="none" stroke="#000" stroke-width=".21"/>
<path d="M95.5 73.9l1.5 .5-1.5 .5z" fill="#f8fcff"/>
<path d="M95.5 73.9l1.5 .5-1.5 .5z" fill="none" stroke="#000" stroke-width=".21"/>
<path d="M93.7 76.9h7.6" fill="none" stroke="#000" stroke-width=".25"/>
<path d="M93.7 76.9l1.5-.5v1z" fill="#f8fcff"/>
<path d="M93.7 76.9l1.5-.5v1z" fill="none" stroke="#000" stroke-width=".21"/>
<path d="M95.5 76.4l1.5 .5-1.5 .5z" fill="#f8fcff"/>
<path d="M95.5 76.4l1.5 .5-1.5 .5z" fill="none" stroke="#000" stroke-width=".21"/>
<path d="M93.7 79.5h7.6" fill="none" stroke="#000" stroke-width=".25"/>
<path d="M93.7 79.5l1.5-.6v1.1z" fill="#f8fcff"/>
<path d="M93.7 79.5l1.5-.6v1.1z" fill="none" stroke="#000" stroke-width=".21"/>
<path d="M95.5 78.9l1.5 .6-1.5 .5z" fill="#f8fcff"/>
<path d="M95.5 78.9l1.5 .6-1.5 .5z" fill="none" stroke="#000" stroke-width=".21"/>
<path d="M93.7 82h7.6" fill="none" stroke="#000" stroke-width=".25"/>
<path d="M93.7 82l1.5-.5v1z" fill="#f8fcff"/>
<path d="M93.7 82l1.5-.5v1z" fill="none" stroke="#000" stroke-width=".21"/>
<path d="M95.5 81.5l1.5 .5-1.5 .5z" fill="#f8fcff"/>
<path d="M95.5 81.5l1.5 .5-1.5 .5z" fill="none" stroke="#000" stroke-width=".21"/>
<path d="M93.7 84.5h7.6" fill="none" stroke="#000" stroke-width=".25"/>
<path d="M93.7 84.5l1.5-.5v1z" fill="#f8fcff"/>
<path d="M93.7 84.5l1.5-.5v1z" fill="none" stroke="#000" stroke-width=".21"/>
<path d="M95.5 84l1.5 .5-1.5 .5z" fill="#f8fcff"/>
<path d="M95.5 84l1.5 .5-1.5 .5z" fill="none" stroke="#000" stroke-width=".21"/>
<path d="M93.7 87.1h7.6" fill="none" stroke="#000" stroke-width=".25"/>
<path d="M93.7 87.1l1.5-.5v1z" fill="#f8fcff"/>
<path d="M93.7 87.1l1.5-.5v1z" fill="none" stroke="#000" stroke-width=".21"/>
<path d="M95.5 86.6l1.5 .5-1.5 .5z" fill="#f8fcff"/>
<path d="M95.5 86.6l1.5 .5-1.5 .5z" fill="none" stroke="#000" stroke-width=".21"/>
<path d="M93.7 89.6h7.6" fill="none" stroke="#000" stroke-width=".25"/>
<path d="M93.7 89.6l1.5-.5v1z" fill="#f8fcff"/>
<path d="M93.7 89.6l1.5-.5v1z" fill="none" stroke="#000" stroke-width=".21"/>
<path d="M95.5 89.1l1.5 .5-1.5 .5z" fill="#f8fcff"/>
<path d="M93.7 89.1l-1 .5 1 .5M95.5 89.1l1.5 .5-1.5 .5z" fill="none" stroke="#000" stroke-width=".21"/>
<path d="M93.7 92.1h7.6" fill="none" stroke="#000" stroke-width=".25"/>
<path d="M93.7 92.1l1.5-.5v1.1z" fill="#f8fcff"/>
<path d="M93.7 92.1l1.5-.5v1.1z" fill="none" stroke="#000" stroke-width=".21"/>
<path d="M95.5 91.6l1.5 .5-1.5 .6z" fill="#f8fcff"/>
<path d="M93.7 91.6l-1 .5 1 .6M95.5 91.6l1.5 .5-1.5 .6z" fill="none" stroke="#000" stroke-width=".21"/>
<path d="M93.7 94.7h7.6" fill="none" stroke="#000" stroke-width=".25"/>
<path d="M93.7 94.7l1.5-.5v1z" fill="#f8fcff"/>
<path d="M93.7 94.7l1.5-.5v1z" fill="none" stroke="#000" stroke-width=".21"/>
<path d="M95.5 94.2l1.5 .5-1.5 .5z" fill="#f8fcff"/>
<path d="M93.7 94.2l-1 .5 1 .5M95.5 94.2l1.5 .5-1.5 .5z" fill="none" stroke="#000" stroke-width=".21"/>
<path d="M93.7 97.2h7.6" fill="none" stroke="#000" stroke-width=".25"/>
<path d="M93.7 97.2l1.5-.5v1z" fill="#f8fcff"/>
<path d="M93.7 97.2l1.5-.5v1z" fill="none" stroke="#000" stroke-width=".21"/>
<path d="M95.5 96.7l1.5 .5-1.5 .5z" fill="#f8fcff"/>
<path d="M93.7 96.7l-1 .5 1 .5M95.5 96.7l1.5 .5-1.5 .5z" fill="none" stroke="#000" stroke-width=".21"/>
<path d="M93.7 99.8h7.6" fill="none" stroke="#000" stroke-width=".25"/>
<path d="M93.7 99.8l1.5-.5v1z" fill="#f8fcff"/>
<path d="M93.7 99.8l1.5-.5v1z" fill="none" stroke="#000" stroke-width=".21"/>
<path d="M95.5 99.3l1.5 .5-1.5 .5z" fill="#f8fcff"/>
<path d="M93.7 99.3l-1 .5 1 .5M95.5 99.3l1.5 .5-1.5 .5z" fill="none" stroke="#000" stroke-width=".21"/>
<path d="M93.7 102.3h7.6" fill="none" stroke="#000" stroke-width=".25"/>
<path d="M93.7 102.3l1.5-.5v1z" fill="#f8fcff"/>
<path d="M93.7 102.3l1.5-.5v1z" fill="none" stroke="#000" stroke-width=".21"/>
<path d="M95.5 101.8l1.5 .5-1.5 .5z" fill="#f8fcff"/>
<path d="M93.7 101.8l-1 .5 1 .5M95.5 101.8l1.5 .5-1.5 .5z" fill="none" stroke="#000" stroke-width=".21"/>
<path d="M93.7 104.8h7.6" fill="none" stroke="#000" stroke-width=".25"/>
<path d="M93.7 104.8l1.5-.5v1.1z" fill="#f8fcff"/>
<path d="M93.7 104.8l1.5-.5v1.1z" fill="none" stroke="#000" stroke-width=".21"/>
<path d="M95.5 104.3l1.5 .5-1.5 .6z" fill="#f8fcff"/>
<path d="M93.7 104.3l-1 .5 1 .6M95.5 104.3l1.5 .5-1.5 .6z" fill="none" stroke="#000" stroke-width=".21"/>
<path d="M93.7 107.4h7.6" fill="none" stroke="#000" stroke-width=".25"/>
<path d="M93.7 107.4l1.5-.5v1z" fill="#f8fcff"/>
<path d="M93.7 107.4l1.5-.5v1z" fill="none" stroke="#000" stroke-width=".21"/>
<path d="M95.5 106.9l1.5 .5-1.5 .5z" fill="#f8fcff"/>
<path d="M93.7 106.9l-1 .5 1 .5M95.5 106.9l1.5 .5-1.5 .5z" fill="none" stroke="#000" stroke-width=".21"/>
<path d="M93.7 109.9h7.6" fill="none" stroke="#000" stroke-width=".25"/>
<path d="M93.7 109.9l1.5-.5v1z" fill="#f8fcff"/>
<path d="M93.7 109.9l1.5-.5v1z" fill="none" stroke="#000" stroke-width=".21"/>
<path d="M95.5 109.4l1.5 .5-1.5 .5z" fill="#f8fcff"/>
<path d="M95.5 109.4l1.5 .5-1.5 .5z" fill="none" stroke="#000" stroke-width=".21"/>
<path d="M93.7 112.5h7.6" fill="none" stroke="#000" stroke-width=".25"/>
<path d="M93.7 112.5l1.5-.5v1z" fill="#f8fcff"/>
<path d="M93.7 112.5l1.5-.5v1z" fill="none" stroke="#000" stroke-width=".21"/>
<path d="M95.5 112l1.5 .5-1.5 .5z" fill="#f8fcff"/>
<path d="M95.5 112l1.5 .5-1.5 .5z" fill="none" stroke="#000" stroke-width=".21"/>
<path d="M93.7 115h7.6" fill="none" stroke="#000" stroke-width=".25"/>
<path d="M93.7 115l1.5-.5v1z" fill="#f8fcff"/>
<path d="M93.7 115l1.5-.5v1z" fill="none" stroke="#000" stroke-width=".21"/>
<path d="M95.5 114.5l1.5 .5-1.5 .5z" fill="#f8fcff"/>
<path d="M95.5 114.5l1.5 .5-1.5 .5z" fill="none" stroke="#000" stroke-width=".21"/>
<path d="M93.7 117.5h7.6" fill="none" stroke="#000" stroke-width=".25"/>
<path d="M93.7 117.5l1.5-.5v1.1z" fill="#f8fcff"/>
<path d="M93.7 117.5l1.5-.5v1.1z" fill="none" stroke="#000" stroke-width=".21"/>
<path d="M95.5 117l1.5 .5-1.5 .6z" fill="#f8fcff"/>
<path d="M95.5 117l1.5 .5-1.5 .6z" fill="none" stroke="#000" stroke-width=".21"/>
<path d="M93.7 120.1h7.6" fill="none" stroke="#000" stroke-width=".25"/>
<path d="M93.7 120.1l1.5-.5v1z" fill="#f8fcff"/>
<path d="M93.7 120.1l1.5-.5v1z" fill="none" stroke="#000" stroke-width=".21"/>
<path d="M95.5 119.6l1.5 .5-1.5 .5z" fill="#f8fcff"/>
<path d="M95.5 119.6l1.5 .5-1.5 .5z" fill="none" stroke="#000" stroke-width=".21"/>
<path d="M93.7 122.6h7.6" fill="none" stroke="#000" stroke-width=".25"/>
<path d="M93.7 122.6l1.5-.5v1z" fill="#f8fcff"/>
<path d="M93.7 122.6l1.5-.5v1z" fill="none" stroke="#000" stroke-width=".21"/>
<path d="M95.5 122.1l1.5 .5-1.5 .5z" fill="#f8fcff"/>
<path d="M95.5 122.1l1.5 .5-1.5 .5z" fill="none" stroke="#000" stroke-width=".21"/>
<path d="M93.7 125.2h7.6" fill="none" stroke="#000" stroke-width=".25"/>
<path d="M93.7 125.2l1.5-.5v1z" fill="#f8fcff"/>
<path d="M93.7 125.2l1.5-.5v1z" fill="none" stroke="#000" stroke-width=".21"/>
<path d="M95.5 124.7l1.5 .5-1.5 .5z" fill="#f8fcff"/>
<path d="M95.5 124.7l1.5 .5-1.5 .5z" fill="none" stroke="#000" stroke-width=".21"/>
<path d="M93.7 127.7h7.6" fill="none" stroke="#000" stroke-width=".25"/>
<path d="M93.7 127.7l1.5-.5v1z" fill="#f8fcff"/>
<path d="M93.7 127.7l1.5-.5v1z" fill="none" stroke="#000" stroke-width=".21"/>
<path d="M95.5 127.2l1.5 .5-1.5 .5z" fill="#f8fcff"/>
<path d="M95.5 127.2l1.5 .5-1.5 .5z" fill="none" stroke="#000" stroke-width=".21"/>
<path d="M93.7 130.2h7.6" fill="none" stroke="#000" stroke-width=".25"/>
<path d="M93.7 130.2l1.5-.5v1.1z" fill="#f8fcff"/>
<path d="M93.7 130.2l1.5-.5v1.1z" fill="none" stroke="#000" stroke-width=".21"/>
<path d="M95.5 129.7l1.5 .5-1.5 .6z" fill="#f8fcff"/>
<path d="M95.5 129.7l1.5 .5-1.5 .6z" fill="none" stroke="#000" stroke-width=".21"/>
<path d="M93.7 132.8h7.6" fill="none" stroke="#000" stroke-width=".25"/>
<path d="M93.7 132.8l1.5-.5v1z" fill="#f8fcff"/>
<path d="M93.7 132.8l1.5-.5v1z" fill="none" stroke="#000" stroke-width=".21"/>
<path d="M95.5 132.3l1.5 .5-1.5 .5z" fill="#f8fcff"/>
<path d="M95.5 132.3l1.5 .5-1.5 .5z" fill="none" stroke="#000" stroke-width=".21"/>
<path d="M93.7 135.3h7.6" fill="none" stroke="#000" stroke-width=".25"/>
<path d="M93.7 135.3l1.5-.5v1z" fill="#f8fcff"/>
<path d="M93.7 135.3l1.5-.5v1z" fill="none" stroke="#000" stroke-width=".21"/>
<path d="M95.5 134.8l1.5 .5-1.5 .5z" fill="#f8fcff"/>
<path d="M95.5 134.8l1.5 .5-1.5 .5z" fill="none" stroke="#000" stroke-width=".21"/>
<path d="M93.7 137.9h7.6" fill="none" stroke="#000" stroke-width=".25"/>
<path d="M93.7 137.9l1.5-.5v1z" fill="#f8fcff"/>
<path d="M93.7 137.9l1.5-.5v1z" fill="none" stroke="#000" stroke-width=".21"/>
<path d="M95.5 137.4l1.5 .5-1.5 .5z" fill="#f8fcff"/>
<path d="M95.5 137.4l1.5 .5-1.5 .5z" fill="none" stroke="#000" stroke-width=".21"/>
<path d="M93.7 140.4h7.6" fill="none" stroke="#000" stroke-width=".25"/>
<path d="M93.7 140.4l1.5-.5v1z" fill="#f8fcff"/>
<path d="M93.7 140.4l1.5-.5v1z" fill="none" stroke="#000" stroke-width=".21"/>
<path d="M95.5 139.9l1.5 .5-1.5 .5z" fill="#f8fcff"/>
<path d="M95.5 139.9l1.5 .5-1.5 .5z" fill="none" stroke="#000" stroke-width=".21"/>
<path d="M93.7 142.9h7.6" fill="none" stroke="#000" stroke-width=".25"/>
<path d="M93.7 142.9l1.5-.5v1z" fill="#f8fcff"/>
<path d="M93.7 142.9l1.5-.5v1z" fill="none" stroke="#000" stroke-width=".21"/>
<path d="M95.5 142.4l1.5 .5-1.5 .5z" fill="#f8fcff"/>
<path d="M95.5 142.4l1.5 .5-1.5 .5z" fill="none" stroke="#000" stroke-width=".21"/>
<path d="M93.7 145.5h7.6" fill="none" stroke="#000" stroke-width=".25"/>
<path d="M93.7 145.5l1.5-.5v1z" fill="#f8fcff"/>
<path d="M93.7 145.5l1.5-.5v1z" fill="none" stroke="#000" stroke-width=".21"/>
<path d="M95.5 145l1.5 .5-1.5 .5z" fill="#f8fcff"/>
<path d="M95.5 145l1.5 .5-1.5 .5z" fill="none" stroke="#000" stroke-width=".21"/>
<path d="M93.7 148h7.6" fill="none" stroke="#000" stroke-width=".25"/>
<path d="M93.7 148l1.5-.5v1z" fill="#f8fcff"/>
<path d="M93.7 148l1.5-.5v1z" fill="none" stroke="#000" stroke-width=".21"/>
<path d="M95.5 147.5l1.5 .5-1.5 .5z" fill="#f8fcff"/>
<path d="M95.5 147.5l1.5 .5-1.5 .5z" fill="none" stroke="#000" stroke-width=".21"/>
<path d="M93.7 150.6h7.6" fill="none" stroke="#000" stroke-width=".25"/>
<path d="M93.7 150.6l1.5-.5v1z" fill="#f8fcff"/>
<path d="M93.7 150.6l1.5-.5v1z" fill="none" stroke="#000" stroke-width=".21"/>
<path d="M95.5 150.1l1.5 .5-1.5 .5z" fill="#f8fcff"/>
<path d="M95.5 150.1l1.5 .5-1.5 .5z" fill="none" stroke="#000" stroke-width=".21"/>
<path d="M93.7 153.1h7.6" fill="none" stroke="#000" stroke-width=".25"/>
<path d="M93.7 153.1l1.5-.5v1z" fill="#f8fcff"/>
<path d="M93.7 153.1l1.5-.5v1z" fill="none" stroke="#000" stroke-width=".21"/>
<path d="M95.5 152.6l1.5 .5-1.5 .5z" fill="#f8fcff"/>
<path d="M95.5 152.6l1.5 .5-1.5 .5z" fill="none" stroke="#000" stroke-width=".21"/>
<path d="M93.7 155.6h7.6" fill="none" stroke="#000" stroke-width=".25"/>
<path d="M93.7 155.6l1.5-.5v1z" fill="#f8fcff"/>
<path d="M93.7 155.6l1.5-.5v1z" fill="none" stroke="#000" stroke-width=".21"/>
<path d="M95.5 155.1l1.5 .5-1.5 .5z" fill="#f8fcff"/>
<path d="M95.5 155.1l1.5 .5-1.5 .5z" fill="none" stroke="#000" stroke-width=".21"/>
<path d="M93.7 158.2h7.6" fill="none" stroke="#000" stroke-width=".25"/>
<path d="M93.7 158.2l1.5-.5v1z" fill="#f8fcff"/>
<path d="M93.7 158.2l1.5-.5v1z" fill="none" stroke="#000" stroke-width=".21"/>
<path d="M95.5 157.7l1.5 .5-1.5 .5z" fill="#f8fcff"/>
<path d="M95.5 157.7l1.5 .5-1.5 .5z" fill="none" stroke="#000" stroke-width=".21"/>
<path d="M93.7 160.7h7.6" fill="none" stroke="#000" stroke-width=".25"/>
<path d="M93.7 160.7l1.5-.5v1z" fill="#f8fcff"/>
<path d="M93.7 160.7l1.5-.5v1z" fill="none" stroke="#000" stroke-width=".21"/>
<path d="M95.5 160.2l1.5 .5-1.5 .5z" fill="#f8fcff"/>
<path d="M95.5 160.2l1.5 .5-1.5 .5z" fill="none" stroke="#000" stroke-width=".21"/>
<path d="M180.1 33.7h35.6v129.6h-35.6z" fill-rule="evenodd" fill="#ffffb0"/>
<path d="M180.1 33.7h35.6v129.6h-35.6z" fill="none" stroke="#800000" stroke-width=".21"/>
<path d="M215.7 36.3h7.6" fill="none" stroke="#000" stroke-width=".25"/>
<path d="M215.7 36.3l1.5-.5v1z" fill="#f8fcff"/>
<path d="M215.7 36.3l1.5-.5v1z" fill="none" stroke="#000" stroke-width=".21"/>
<path d="M217.5 35.8l1.5 .5-1.5 .5z" fill="#f8fcff"/>
<path d="M217.5 35.8l1.5 .5-1.5 .5z" fill="none" stroke="#000" stroke-width=".21"/>
<path d="M215.7 38.8h7.6" fill="none" stroke="#000" stroke-width=".25"/>
<path d="M215.7 38.8l1.5-.5v1z" fill="#f8fcff"/>
<path d="M215.7 38.8l1.5-.5v1z" fill="none" stroke="#000" stroke-width=".21"/>
<path d="M217.5 38.3l1.5 .5-1.5 .5z" fill="#f8fcff"/>
<path d="M217.5 38.3l1.5 .5-1.5 .5z" fill="none" stroke="#000" stroke-width=".21"/>
<path d="M215.7 41.4h7.6" fill="none" stroke="#000" stroke-width=".25"/>
<path d="M215.7 41.4l1.5-.5v1z" fill="#f8fcff"/>
<path d="M215.7 41.4l1.5-.5v1z" fill="none" stroke="#000" stroke-width=".21"/>
<path d="M217.5 40.9l1.5 .5-1.5 .5z" fill="#f8fcff"/>
<path d="M217.5 40.9l1.5 .5-1.5 .5z" fill="none" stroke="#000" stroke-width=".21"/>
<path d="M215.7 43.9h7.6" fill="none" stroke="#000" stroke-width=".25"/>
<path d="M215.7 43.9l1.5-.5v1z" fill="#f8fcff"/>
<path d="M215.7 43.9l1.5-.5v1z" fill="none" stroke="#000" stroke-width=".21"/>
<path d="M217.5 43.4l1.5 .5-1.5 .5z" fill="#f8fcff"/>
<path d="M217.5 43.4l1.5 .5-1.5 .5z" fill="none" stroke="#000" stroke-width=".21"/>
<path d="M215.7 46.4h7.6" fill="none" stroke="#000" stroke-width=".25"/>
<path d="M215.7 46.4l1.5-.5v1z" fill="#f8fcff"/>
<path d="M215.7 46.4l1.5-.5v1z" fill="none" stroke="#000" stroke-width=".21"/>
<path d="M217.5 45.9l1.5 .5-1.5 .5z" fill="#f8fcff"/>
<path d="M217.5 45.9l1.5 .5-1.5 .5z" fill="none" stroke="#000" stroke-width=".21"/>
<path d="M215.7 49h7.6" fill="none" stroke="#000" stroke-width=".25"/>
<path d="M215.7 49l1.5-.5v1z" fill="#f8fcff"/>
<path d="M215.7 49l1.5-.5v1z" fill="none" stroke="#000" stroke-width=".21"/>
<path d="M217.5 48.5l1.5 .5-1.5 .5z" fill="#f8fcff"/>
<path d="M217.5 48.5l1.5 .5-1.5 .5z" fill="none" stroke="#000" stroke-width=".21"/>
<path d="M215.7 51.5h7.6" fill="none" stroke="#000" stroke-width=".25"/>
<path d="M215.7 51.5l1.5-.5v1z" fill="#f8fcff"/>
<path d="M215.7 51.5l1.5-.5v1z" fill="none" stroke="#000" stroke-width=".21"/>
<path d="M217.5 51l1.5 .5-1.5 .5z" fill="#f8fcff"/>
<path d="M217.5 51l1.5 .5-1.5 .5z" fill="none" stroke="#000" stroke-width=".21"/>
<path d="M215.7 54.1h7.6" fill="none" stroke="#000" stroke-width=".25"/>
<path d="M215.7 54.1l1.5-.5v1z" fill="#f8fcff"/>
<path d="M215.7 54.1l1.5-.5v1z" fill="none" stroke="#000" stroke-width=".21"/>
<path d="M217.5 53.6l1.5 .5-1.5 .5z" fill="#f8fcff"/>
<path d="M217.5 53.6l1.5 .5-1.5 .5z" fill="none" stroke="#000" stroke-width=".21"/>
<path d="M215.7 56.6h7.6" fill="none" stroke="#000" stroke-width=".25"/>
<path d="M215.7 56.6l1.5-.5v1z" fill="#f8fcff"/>
<path d="M215.7 56.6l1.5-.5v1z" fill="none" stroke="#000" stroke-width=".21"/>
<path d="M217.5 56.1l1.5 .5-1.5 .5z" fill="#f8fcff"/>
<path d="M217.5 56.1l1.5 .5-1.5 .5z" fill="none" stroke="#000" stroke-width=".21"/>
<path d="M215.7 59.1h7.6" fill="none" stroke="#000" stroke-width=".25"/>
<path d="M215.7 59.1l1.5-.5v1z" fill="#f8fcff"/>
<path d="M215.7 59.1l1.5-.5v1z" fill="none" stroke="#000" stroke-width=".21"/>
<path d="M217.5 58.6l1.5 .5-1.5 .5z" fill="#f8fcff"/>
<path d="M217.5 58.6l1.5 .5-1.5 .5z" fill="none" stroke="#000" stroke-width=".21"/>
<path d="M215.7 61.7h7.6" fill="none" stroke="#000" stroke-width=".25"/>
<path d="M215.7 61.7l1.5-.5v1z" fill="#f8fcff"/>
<path d="M215.7 61.7l1.5-.5v1z" fill="none" stroke="#000" stroke-width=".21"/>
<path d="M217.5 61.2l1.5 .5-1.5 .5z" fill="#f8fcff"/>
<path d="M217.5 61.2l1.5 .5-1.5 .5z" fill="none" stroke="#000" stroke-width=".21"/>
<path d="M215.7 64.2h7.6" fill="none" stroke="#000" stroke-width=".25"/>
<path d="M215.7 64.2l1.5-.5v1z" fill="#f8fcff"/>
<path d="M215.7 64.2l1.5-.5v1z" fill="none" stroke="#000" stroke-width=".21"/>
<path d="M217.5 63.7l1.5 .5-1.5 .5z" fill="#f8fcff"/>
<path d="M217.5 63.7l1.5 .5-1.5 .5z" fill="none" stroke="#000" stroke-width=".21"/>
<path d="M215.7 66.8h7.6" fill="none" stroke="#000" stroke-width=".25"/>
<path d="M215.7 66.8l1.5-.6v1.1z" fill="#f8fcff"/>
<path d="M215.7 66.8l1.5-.6v1.1z" fill="none" stroke="#000" stroke-width=".21"/>
<path d="M217.5 66.2l1.5 .6-1.5 .5z" fill="#f8fcff"/>
<path d="M217.5 66.2l1.5 .6-1.5 .5z" fill="none" stroke="#000" stroke-width=".21"/>
<path d="M215.7 69.3h7.6" fill="none" stroke="#000" stroke-width=".25"/>
<path d="M215.7 69.3l1.5-.5v1z" fill="#f8fcff"/>
<path d="M215.7 69.3l1.5-.5v1z" fill="none" stroke="#000" stroke-width=".21"/>
<path d="M217.5 68.8l1.5 .5-1.5 .5z" fill="#f8fcff"/>
<path d="M217.5 68.8l1.5 .5-1.5 .5z" fill="none" stroke="#000" stroke-width=".21"/>
<path d="M215.7 71.8h7.6" fill="none" stroke="#000" stroke-width=".25"/>
<path d="M215.7 71.8l1.5-.5v1z" fill="#f8fcff"/>
<path d="M215.7 71.8l1.5-.5v1z" fill="none" stroke="#000" stroke-width=".21"/>
<path d="M217.5 71.3l1.5 .5-1.5 .5z" fill="#f8fcff"/>
<path d="M217.5 71.3l1.5 .5-1.5 .5z" fill="none" stroke="#000" stroke-width=".21"/>
<path d="M215.7 74.4h7.6" fill="none" stroke="#000" stroke-width=".25"/>
<path d="M215.7 74.4l1.5-.5v1z" fill="#f8fcff"/>
<path d="M215.7 74.4l1.5-.5v1z" fill="none" stroke="#000" stroke-width=".21"/>
<path d="M217.5 73.9l1.5 .5-1.5 .5z" fill="#f8fcff"/>
<path d="M217.5 73.9l1.5 .5-1.5 .5z" fill="none" stroke="#000" stroke-width=".21"/>
<path d="M215.7 76.9h7.6" fill="none" stroke="#000" stroke-width=".25"/>
<path d="M215.7 76.9l1.5-.5v1z" fill="#f8fcff"/>
<path d="M215.7 76.9l1.5-.5v1z" fill="none" stroke="#000" stroke-width=".21"/>
<path d="M217.5 76.4l1.5 .5-1.5 .5z" fill="#f8fcff"/>
<path d="M217.5 76.4l1.5 .5-1.5 .5z" fill="none" stroke="#000" stroke-width=".21"/>
<path d="M215.7 79.5h7.6" fill="none" stroke="#000" stroke-width=".25"/>
<path d="M215.7 79.5l1.5-.6v1.1z" fill="#f8fcff"/>
<path d="M215.7 79.5l1.5-.6v1.1z" fill="none" stroke="#000" stroke-width=".21"/>
<path d="M217.5 78.9l1.5 .6-1.5 .5z" fill="#f8fcff"/>
<path d="M217.5 78.9l1.5 .6-1.5 .5z" fill="none" stroke="#000" stroke-width=".21"/>
<path d="M215.7 82h7.6" fill="none" stroke="#000" stroke-width=".25"/>
<path d="M215.7 82l1.5-.5v1z" fill="#f8fcff"/>
<path d="M215.7 82l1.5-.5v1z" fill="none" stroke="#000" stroke-width=".21"/>
<path d="M217.5 81.5l1.5 .5-1.5 .5z" fill="#f8fcff"/>
<path d="M217.5 81.5l1.5 .5-1.5 .5z" fill="none" stroke="#000" stroke-width=".21"/>
<path d="M215.7 84.5h7.6" fill="none" stroke="#000" stroke-width=".25"/>
<path d="M215.7 84.5l1.5-.5v1z" fill="#f8fcff"/>
<path d="M215.7 84.5l1.5-.5v1z" fill="none" stroke="#000" stroke-width=".21"/>
<path d="M217.5 84l1.5 .5-1.5 .5z" fill="#f8fcff"/>
<path d="M217.5 84l1.5 .5-1.5 .5z" fill="none" stroke="#000" stroke-width=".21"/>
<path d="M215.7 87.1h7.6" fill="none" stroke="#000" stroke-width=".25"/>
<path d="M215.7 87.1l1.5-.5v1z" fill="#f8fcff"/>
<path d="M215.7 87.1l1.5-.5v1z" fill="none" stroke="#000" stroke-width=".21"/>
<path d="M217.5 86.6l1.5 .5-1.5 .5z" fill="#f8fcff"/>
<path d="M217.5 86.6l1.5 .5-1.5 .5z" fill="none" stroke="#000" stroke-width=".21"/>
<path d="M215.7 89.6h7.6" fill="none" stroke="#000" stroke-width=".25"/>
<path d="M215.7 89.6l1.5-.5v1z" fill="#f8fcff"/>
<path d="M215.7 89.6l1.5-.5v1z" fill="none" stroke="#000" stroke-width=".21"/>
<path d="M217.5 89.1l1.5 .5-1.5 .5z" fill="#f8fcff"/>
<path d="M215.7 89.1l-1 .5 1 .5M217.5 89.1l1.5 .5-1.5 .5z" fill="none" stroke="#000" stroke-width=".21"/>
<path d="M215.7 92.2h7.6" fill="none" stroke="#000" stroke-width=".25"/>
<path d="M215.7 92.2l1.5-.6v1.1z" fill="#f8fcff"/>
<path d="M215.7 92.2l1.5-.6v1.1z" fill="none" stroke="#000" stroke-width=".21"/>
<path d="M217.5 91.6l1.5 .6-1.5 .5z" fill="#f8fcff"/>
<path d="M215.7 91.6l-1 .6 1 .5M217.5 91.6l1.5 .6-1.5 .5z" fill="none" stroke="#000" stroke-width=".21"/>
<path d="M215.7 94.7h7.6" fill="none" stroke="#000" stroke-width=".25"/>
<path d="M215.7 94.7l1.5-.5v1z" fill="#f8fcff"/>
<path d="M215.7 94.7l1.5-.5v1z" fill="none" stroke="#000" stroke-width=".21"/>
<path d="M217.5 94.2l1.5 .5-1.5 .5z" fill="#f8fcff"/>
<path d="M215.7 94.2l-1 .5 1 .5M217.5 94.2l1.5 .5-1.5 .5z" fill="none" stroke="#000" stroke-width=".21"/>
<path d="M215.7 97.2h7.6" fill="none" stroke="#000" stroke-width=".25"/>
<path d="M215.7 97.2l1.5-.5v1z" fill="#f8fcff"/>
<path d="M215.7 97.2l1.5-.5v1z" fill="none" stroke="#000" stroke-width=".21"/>
<path d="M217.5 96.7l1.5 .5-1.5 .5z" fill="#f8fcff"/>
<path d="M215.7 96.7l-1 .5 1 .5M217.5 96.7l1.5 .5-1.5 .5z" fill="none" stroke="#000" stroke-width=".21"/>
<path d="M215.7 99.8h7.6" fill="none" stroke="#000" stroke-width=".25"/>
<path d="M215.7 99.8l1.5-.5v1z" fill="#f8fcff"/>
<path d="M215.7 99.8l1.5-.5v1z" fill="none" stroke="#000" stroke-width=".21"/>
<path d="M217.5 99.3l1.5 .5-1.5 .5z" fill="#f8fcff"/>
<path d="M215.7 99.3l-1 .5 1 .5M217.5 99.3l1.5 .5-1.5 .5z" fill="none" stroke="#000" stroke-width=".21"/>
<path d="M215.7 102.3h7.6" fill="none" stroke="#000" stroke-width=".25"/>
<path d="M215.7 102.3l1.5-.5v1z" fill="#f8fcff"/>
<path d="M215.7 102.3l1.5-.5v1z" fill="none" stroke="#000" stroke-width=".21"/>
<path d="M217.5 101.8l1.5 .5-1.5 .5z" fill="#f8fcff"/>
<path d="M215.7 101.8l-1 .5 1 .5M217.5 101.8l1.5 .5-1.5 .5z" fill="none" stroke="#000" stroke-width=".21"/>
<path d="M215.7 104.9h7.6" fill="none" stroke="#000" stroke-width=".25"/>
<path d="M215.7 104.9l1.5-.6v1.1z" fill="#f8fcff"/>
<path d="M215.7 104.9l1.5-.6v1.1z" fill="none" stroke="#000" stroke-width=".21"/>
<path d="M217.5 104.3l1.5 .6-1.5 .5z" fill="#f8fcff"/>
<path d="M215.7 104.3l-1 .6 1 .5M217.5 104.3l1.5 .6-1.5 .5z" fill="none" stroke="#000" stroke-width=".21"/>
<path d="M215.7 107.4h7.6" fill="none" stroke="#000" stroke-width=".25"/>
<path d="M215.7 107.4l1.5-.5v1z" fill="#f8fcff"/>
<path d="M215.7 107.4l1.5-.5v1z" fill="none" stroke="#000" stroke-width=".21"/>
<path d="M217.5 106.9l1.5 .5-1.5 .5z" fill="#f8fcff"/>
<path d="M215.7 106.9l-1 .5 1 .5M217.5 106.9l1.5 .5-1.5 .5z" fill="none" stroke="#000" stroke-width=".21"/>
<path d="M215.7 109.9h7.6" fill="none" stroke="#000" stroke-width=".25"/>
<path d="M215.7 109.9l1.5-.5v1z" fill="#f8fcff"/>
<path d="M215.7 109.9l1.5-.5v1z" fill="none" stroke="#000" stroke-width=".21"/>
<path d="M217.5 109.4l1.5 .5-1.5 .5z" fill="#f8fcff"/>
<path d="M217.5 109.4l1.5 .5-1.5 .5z" fill="none" stroke="#000" stroke-width=".21"/>
<path d="M215.7 112.5h7.6" fill="none" stroke="#000" stroke-width=".25"/>
<path d="M215.7 112.5l1.5-.5v1z" fill="#f8fcff"/>
<path d="M215.7 112.5l1.5-.5v1z" fill="none" stroke="#000" stroke-width=".21"/>
<path d="M217.5 112l1.5 .5-1.5 .5z" fill="#f8fcff"/>
<path d="M217.5 112l1.5 .5-1.5 .5z" fill="none" stroke="#000" stroke-width=".21"/>
<path d="M215.7 115h7.6" fill="none" stroke="#000" stroke-width=".25"/>
<path d="M215.7 115l1.5-.5v1z" fill="#f8fcff"/>
<path d="M215.7 115l1.5-.5v1z" fill="none" stroke="#000" stroke-width=".21"/>
<path d="M217.5 114.5l1.5 .5-1.5 .5z" fill="#f8fcff"/>
<path d="M217.5 114.5l1.5 .5-1.5 .5z" fill="none" stroke="#000" stroke-width=".21"/>
<path d="M215.7 117.5h7.6" fill="none" stroke="#000" stroke-width=".25"/>
<path d="M215.7 117.5l1.5-.5v1.1z" fill="#f8fcff"/>
<path d="M215.7 117.5l1.5-.5v1.1z" fill="none" stroke="#000" stroke-width=".21"/>
<path d="M217.5 117l1.5 .5-1.5 .6z" fill="#f8fcff"/>
<path d="M217.5 117l1.5 .5-1.5 .6z" fill="none" stroke="#000" stroke-width=".21"/>
<path d="M215.7 120.1h7.6" fill="none" stroke="#000" stroke-width=".25"/>
<path d="M215.7 120.1l1.5-.5v1z" fill="#f8fcff"/>
<path d="M215.7 120.1l1.5-.5v1z" fill="none" stroke="#000" stroke-width=".21"/>
<path d="M217.5 119.6l1.5 .5-1.5 .5z" fill="#f8fcff"/>
<path d="M217.5 119.6l1.5 .5-1.5 .5z" fill="none" stroke="#000" stroke-width=".21"/>
<path d="M215.7 122.6h7.6" fill="none" stroke="#000" stroke-width=".25"/>
<path d="M215.7 122.6l1.5-.5v1z" fill="#f8fcff"/>
<path d="M215.7 122.6l1.5-.5v1z" fill="none" stroke="#000" stroke-width=".21"/>
<path d="M217.5 122.1l1.5 .5-1.5 .5z" fill="#f8fcff"/>
<path d="M217.5 122.1l1.5 .5-1.5 .5z" fill="none" stroke="#000" stroke-width=".21"/>
<path d="M215.7 125.2h7.6" fill="none" stroke="#000" stroke-width=".25"/>
<path d="M215.7 125.2l1.5-.5v1z" fill="#f8fcff"/>
<path d="M215.7 125.2l1.5-.5v1z" fill="none" stroke="#000" stroke-width=".21"/>
<path d="M217.5 124.7l1.5 .5-1.5 .5z" fill="#f8fcff"/>
<path d="M217.5 124.7l1.5 .5-1.5 .5z" fill="none" stroke="#000" stroke-width=".21"/>
<path d="M215.7 127.7h7.6" fill="none" stroke="#000" stroke-width=".25"/>
<path d="M215.7 127.7l1.5-.5v1z" fill="#f8fcff"/>
<path d="M215.7 127.7l1.5-.5v1z" fill="none" stroke="#000" stroke-width=".21"/>
<path d="M217.5 127.2l1.5 .5-1.5 .5z" fill="#f8fcff"/>
<path d="M217.5 127.2l1.5 .5-1.5 .5z" fill="none" stroke="#000" stroke-width=".21"/>
<path d="M215.7 130.2h7.6" fill="none" stroke="#000" stroke-width=".25"/>
<path d="M215.7 130.2l1.5-.5v1.1z" fill="#f8fcff"/>
<path d="M215.7 130.2l1.5-.5v1.1z" fill="none" stroke="#000" stroke-width=".21"/>
<path d="M217.5 129.7l1.5 .5-1.5 .6z" fill="#f8fcff"/>
<path d="M217.5 129.7l1.5 .5-1.5 .6z" fill="none" stroke="#000" stroke-width=".21"/>
<path d="M215.7 132.8h7.6" fill="none" stroke="#000" stroke-width=".25"/>
<path d="M215.7 132.8l1.5-.5v1z" fill="#f8fcff"/>
<path d="M215.7 132.8l1.5-.5v1z" fill="none" stroke="#000" stroke-width=".21"/>
<path d="M217.5 132.3l1.5 .5-1.5 .5z" fill="#f8fcff"/>
<path d="M217.5 132.3l1.5 .5-1.5 .5z" fill="none" stroke="#000" stroke-width=".21"/>
<path d="M215.7 135.3h7.6" fill="none" stroke="#000" stroke-width=".25"/>
<path d="M215.7 135.3l1.5-.5v1z" fill="#f8fcff"/>
<path d="M215.7 135.3l1.5-.5v1z" fill="none" stroke="#000" stroke-width=".21"/>
<path d="M217.5 134.8l1.5 .5-1.5 .5z" fill="#f8fcff"/>
<path d="M217.5 134.8l1.5 .5-1.5 .5z" fill="none" stroke="#000" stroke-width=".21"/>
<path d="M215.7 137.9h7.6" fill="none" stroke="#000" stroke-width=".25"/>
<path d="M215.7 137.9l1.5-.5v1z" fill="#f8fcff"/>
<path d="M215.7 137.9l1.5-.5v1z" fill="none" stroke="#000" stroke-width=".21"/>
<path d="M217.5 137.4l1.5 .5-1.5 .5z" fill="#f8fcff"/>
<path d="M217.5 137.4l1.5 .5-1.5 .5z" fill="none" stroke="#000" stroke-width=".21"/>
<path d="M215.7 140.4h7.6" fill="none" stroke="#000" stroke-width=".25"/>
<path d="M215.7 140.4l1.5-.5v1z" fill="#f8fcff"/>
<path d="M215.7 140.4l1.5-.5v1z" fill="none" stroke="#000" stroke-width=".21"/>
<path d="M217.5 139.9l1.5 .5-1.5 .5z" fill="#f8fcff"/>
<path d="M217.5 139.9l1.5 .5-1.5 .5z" fill="none" stroke="#000" stroke-width=".21"/>
<path d="M215.7 142.9h7.6" fill="none" stroke="#000" stroke-width=".25"/>
<path d="M215.7 142.9l1.5-.5v1.1z" fill="#f8fcff"/>
<path d="M215.7 142.9l1.5-.5v1.1z" fill="none" stroke="#000" stroke-width=".21"/>
<path d="M217.5 142.4l1.5 .5-1.5 .6z" fill="#f8fcff"/>
<path d="M217.5 142.4l1.5 .5-1.5 .6z" fill="none" stroke="#000" stroke-width=".21"/>
<path d="M215.7 145.5h7.6" fill="none" stroke="#000" stroke-width=".25"/>
<path d="M215.7 145.5l1.5-.5v1z" fill="#f8fcff"/>
<path d="M215.7 145.5l1.5-.5v1z" fill="none" stroke="#000" stroke-width=".21"/>
<path d="M217.5 145l1.5 .5-1.5 .5z" fill="#f8fcff"/>
<path d="M217.5 145l1.5 .5-1.5 .5z" fill="none" stroke="#000" stroke-width=".21"/>
<path d="M215.7 148h7.6" fill="none" stroke="#000" stroke-width=".25"/>
<path d="M215.7 148l1.5-.5v1z" fill="#f8fcff"/>
<path d="M215.7 148l1.5-.5v1z" fill="none" stroke="#000" stroke-width=".21"/>
<path d="M217.5 147.5l1.5 .5-1.5 .5z" fill="#f8fcff"/>
<path d="M217.5 147.5l1.5 .5-1.5 .5z" fill="none" stroke="#000" stroke-width=".21"/>
<path d="M215.7 150.6h7.6" fill="none" stroke="#000" stroke-width=".25"/>
<path d="M215.7 150.6l1.5-.5v1z" fill="#f8fcff"/>
<path d="M215.7 150.6l1.5-.5v1z" fill="none" stroke="#000" stroke-width=".21"/>
<path d="M217.5 150.1l1.5 .5-1.5 .5z" fill="#f8fcff"/>
<path d="M217.5 150.1l1.5 .5-1.5 .5z" fill="none" stroke="#000" stroke-width=".21"/>
<path d="M215.7 153.1h7.6" fill="none" stroke="#000" stroke-width=".25"/>
<path d="M215.7 153.1l1.5-.5v1z" fill="#f8fcff"/>
<path d="M215.7 153.1l1.5-.5v1z" fill="none" stroke="#000" stroke-width=".21"/>
<path d="M217.5 152.6l1.5 .5-1.5 .5z" fill="#f8fcff"/>
<path d="M217.5 152.6l1.5 .5-1.5 .5z" fill="none" stroke="#000" stroke-width=".21"/>
<path d="M215.7 155.6h7.6" fill="none" stroke="#000" stroke-width=".25"/>
<path d="M215.7 155.6l1.5-.5v1z" fill="#f8fcff"/>
<path d="M215.7 155.6l1.5-.5v1z" fill="none" stroke="#000" stroke-width=".21"/>
<path d="M217.5 155.1l1.5 .5-1.5 .5z" fill="#f8fcff"/>
<path d="M217.5 155.1l1.5 .5-1.5 .5z" fill="none" stroke="#000" stroke-width=".21"/>
<path d="M215.7 158.2h7.6" fill="none" stroke="#000" stroke-width=".25"/>
<path d="M215.7 158.2l1.5-.5v1z" fill="#f8fcff"/>
<path d="M215.7 158.2l1.5-.5v1z" fill="none" stroke="#000" stroke-width=".21"/>
<path d="M217.5 157.7l1.5 .5-1.5 .5z" fill="#f8fcff"/>
<path d="M217.5 157.7l1.5 .5-1.5 .5z" fill="none" stroke="#000" stroke-width=".21"/>
<path d="M215.7 160.7h7.6" fill="none" stroke="#000" stroke-width=".25"/>
<path d="M215.7 160.7l1.5-.5v1z" fill="#f8fcff"/>
<path d="M215.7 160.7l1.5-.5v1z" fill="none" stroke="#000" stroke-width=".21"/>
<path d="M217.5 160.2l1.5 .5-1.5 .5z" fill="#f8fcff"/>
<path d="M217.5 160.2l1.5 .5-1.5 .5z" fill="none" stroke="#000" stroke-width=".21"/>
<path d="M222.3 35.3l2.1 2M224.4 35.3l-2.1 2M222.3 93.7l2.1 2M222.3 98.8l2.1 2M224.4 93.7l-2.1 2M224.4 98.8l-2.1 2M222.3 159.7l2.1 2M224.4 159.7l-2.1 2" fill="none" stroke="#f00" stroke-width=".21"/>
<path d="M128 31.2h2.6M129.3 31.2v2.5M126.8 66.8h5M127.5 67.5h3.6M128.3 68.3h2M129.1 69h.5M129.3 64.2v2.6M243.7 66.8h2.5M246.2 65.5v2.5M243.7 132.8h2.5M246.2 131.5v2.5" fill="none" stroke="#800000" stroke-width=".25"/>
<g fill="none" stroke="#000080" stroke-width=".25">
<path d="M101.3 38.8h17.8M129.3 33.7v2.6M223.3 38.8h17.8M101.3 41.4h17.8M101.3 43.9h17.8M101.3 46.4h17.8M101.3 54.1h17.8M101.3 51.5h17.8M101.3 56.6h17.8M129.3 46.4v5.1M223.3 41.4h17.8M223.3 43.9h17.8"/>
<path d="M223.3 46.4h17.8M223.3 54.1h17.8M223.3 51.5h17.8M223.3 56.6h17.8M223.3 59.1h17.8M223.3 49h17.8M101.3 64.2h17.8M101.3 66.8h17.8M101.3 61.7h17.8M101.3 69.3h17.8M101.3 71.8h17.8M129.3 61.7v2.5"/>
<path d="M223.3 64.2h17.8M223.3 66.8h20.4M223.3 61.7h17.8M223.3 69.3h17.8M223.3 71.8h17.8M223.3 74.4h17.8M223.3 76.9h17.8M223.3 79.5h17.8M101.3 99.8h17.8M101.3 82h17.8M101.3 84.5h17.8M223.3 82h17.8"/>
<path d="M223.3 84.5h17.8M223.3 87.1h17.8M223.3 89.6h17.8M223.3 92.2h17.8M223.3 97.2h17.8M101.3 102.3h17.8M101.3 115h17.8M101.3 109.9h17.8M101.3 112.5h17.8M223.3 102.3h17.8M223.3 104.9h17.8M223.3 107.4h17.8"/>
<path d="M223.3 115h17.8M223.3 117.5h17.8M223.3 109.9h17.8M223.3 112.5h17.8M101.3 137.9h17.8M101.3 125.2h17.8M101.3 132.8h17.8M101.3 127.7h17.8M223.3 120.1h17.8M223.3 122.6h17.8M223.3 130.2h17.8M223.3 135.3h17.8"/>
<path d="M223.3 137.9h17.8M223.3 125.2h17.8M223.3 132.8h20.4M223.3 127.7h17.8M101.3 145.5h17.8M101.3 153.1h17.8M101.3 155.6h17.8M101.3 140.4h17.8M101.3 142.9h17.8M101.3 158.2h17.8M101.3 150.6h17.8M223.3 145.5h17.8"/>
<path d="M223.3 148h17.8M223.3 150.6h17.8M223.3 153.1h17.8M223.3 155.6h17.8M223.3 140.4h17.8M223.3 142.9h17.8M223.3 158.2h17.8"/>
</g>
<path d="M129.3 36.3v2M129.3 44.4v2M129.3 51.5v2M129.3 59.7v2" fill="none" stroke="#000" stroke-width=".25"/>
<path d="M128.3 38.4h2.1v6h-2.1zM128.3 53.6h2.1v6h-2.1z" fill="none" stroke="#00f" stroke-width=".25"/>
<circle cx="129.3" cy="49" r=".51" fill="#000080"/>
<circle cx="129.3" cy="49" r=".51" fill="none" stroke="#000080" stroke-width=".21"/>
<path d="M101.3 49h28" fill="none" stroke="#000080" stroke-width=".25"/>
<circle cx="129.3" cy="49" r=".51" fill="#000080"/>
<circle cx="129.3" cy="49" r=".51" fill="none" stroke="#000080" stroke-width=".21"/>
<use href="#words"/>
</svg>
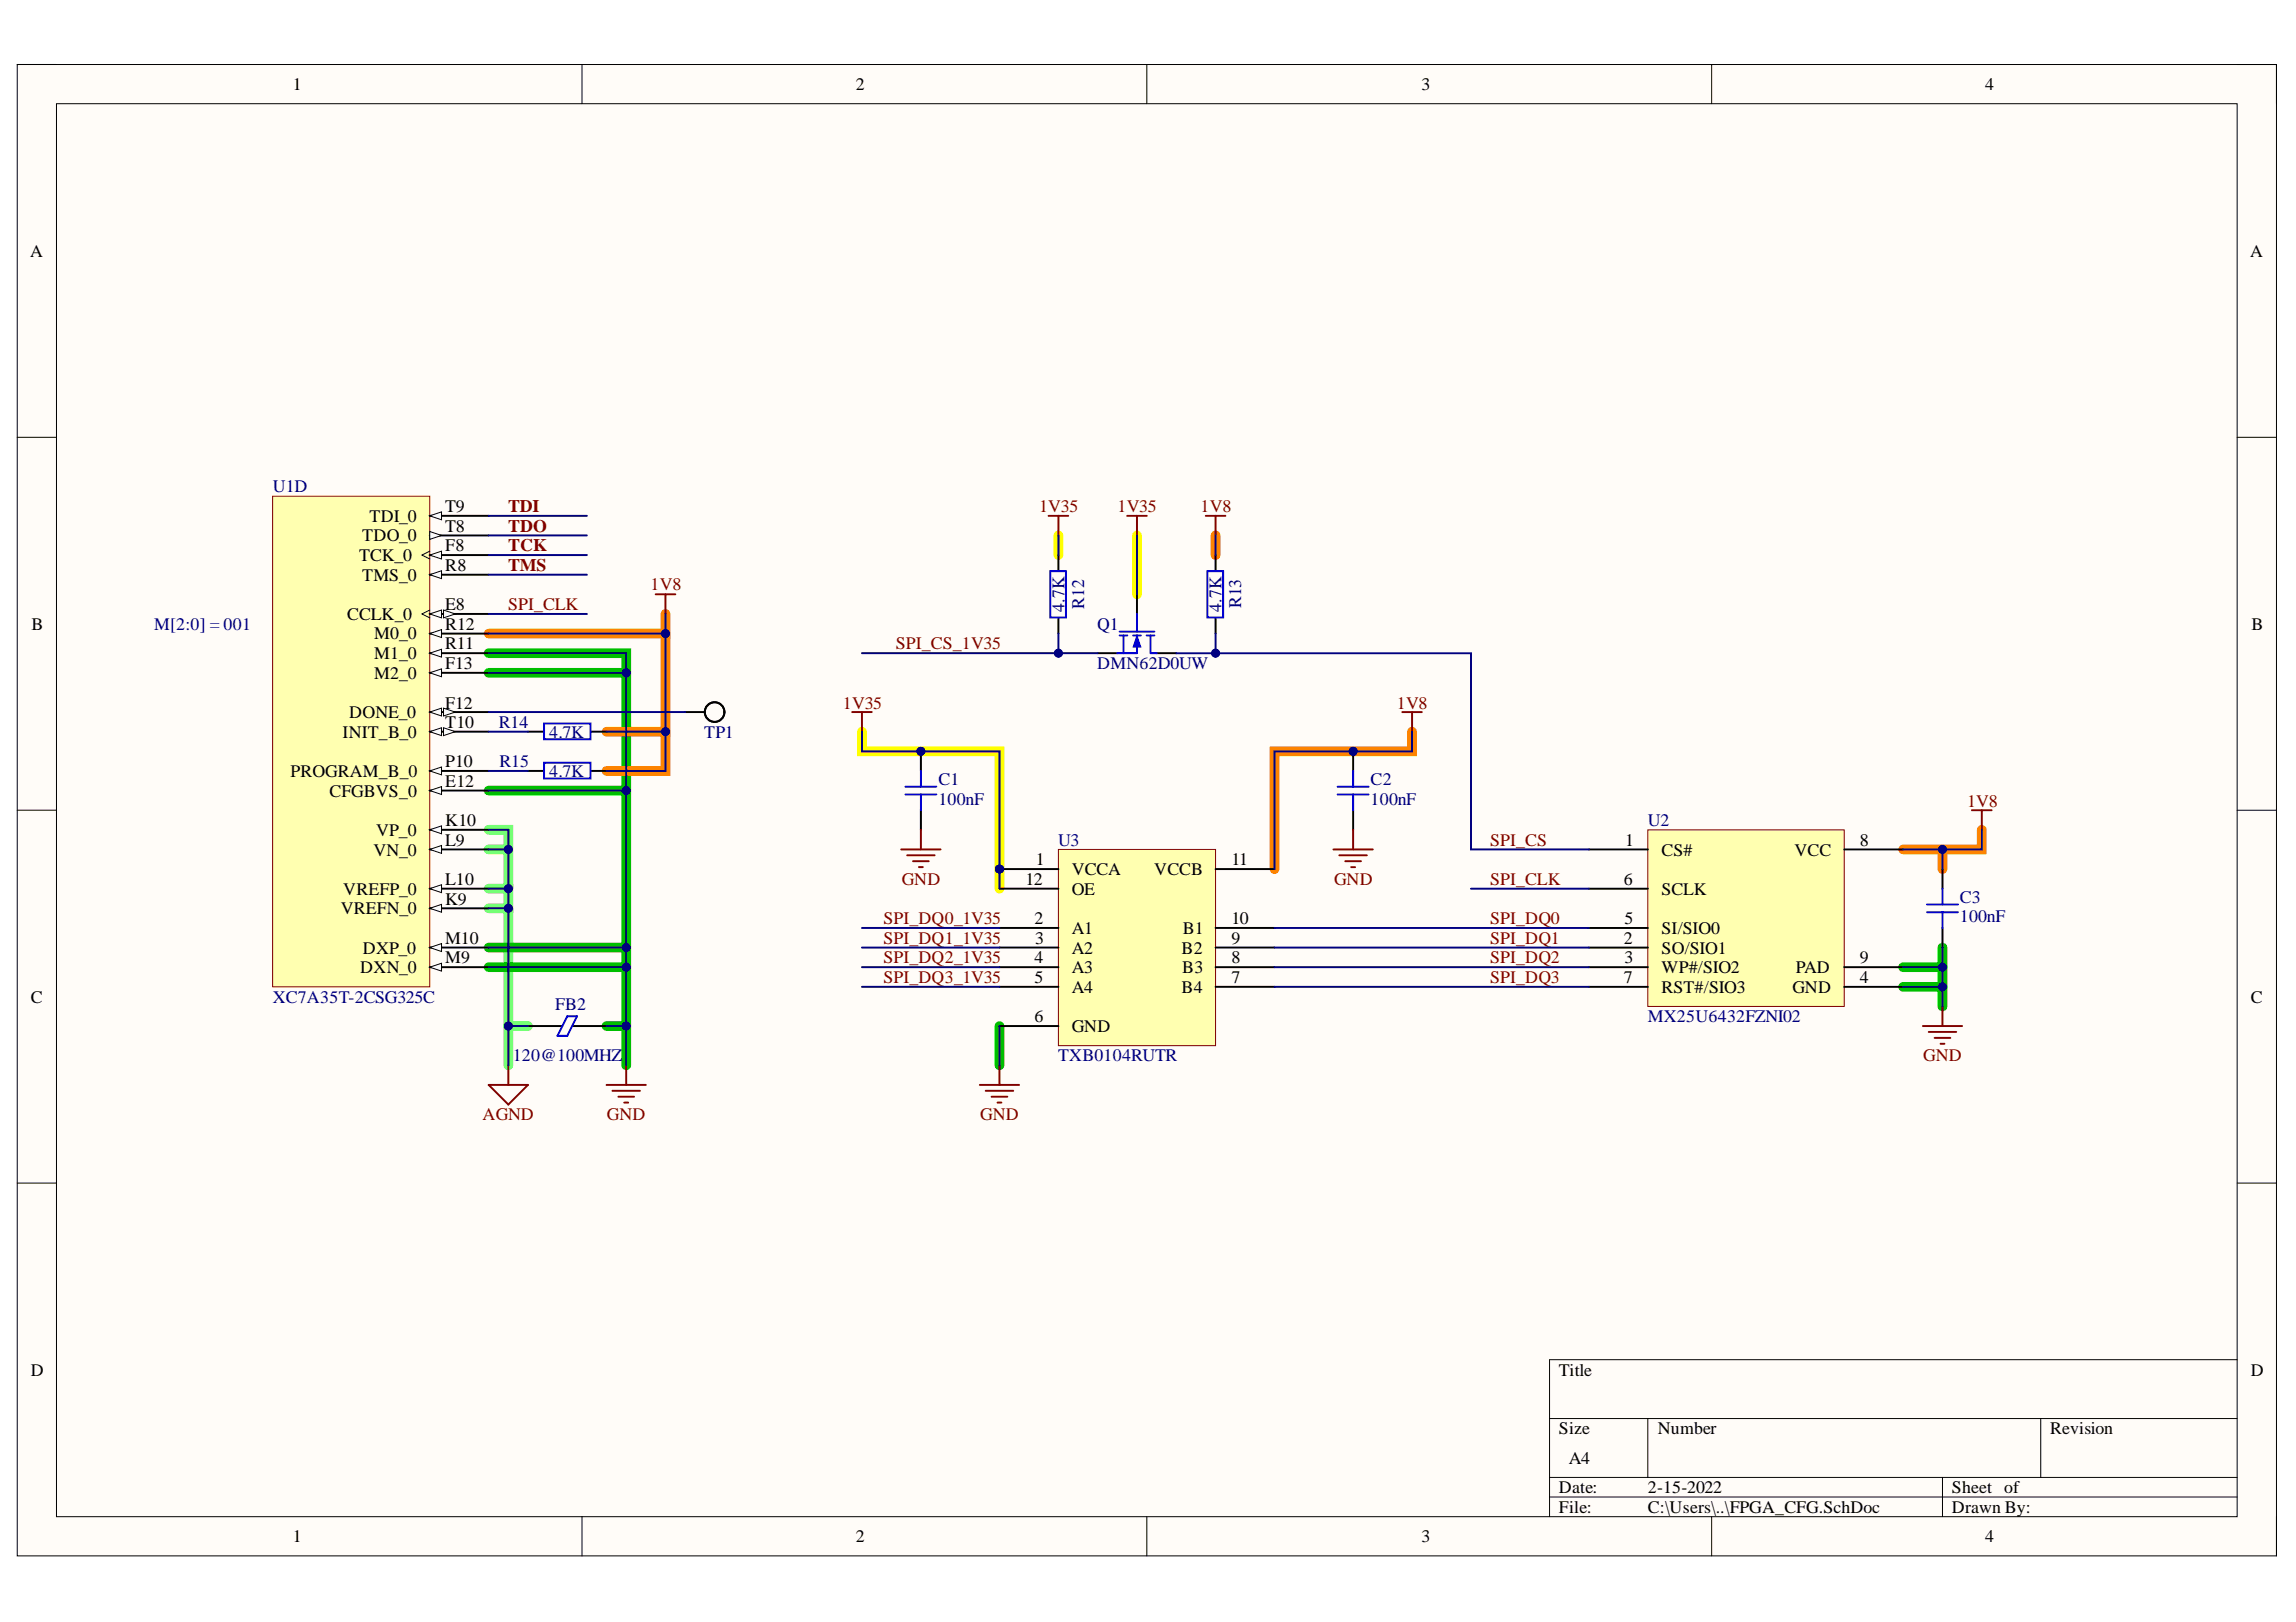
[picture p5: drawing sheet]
<svg xmlns="http://www.w3.org/2000/svg" width="297mm" height="210mm" viewBox="0 0 297 210" stroke-linecap="round" stroke-linejoin="round" font-family="sans-serif">
<defs><g id="words">
<g font-size="2.3">
<text x="37.9" y="11.7">1</text>
<text x="110.7" y="11.7">2</text>
<text x="183.9" y="11.7">3</text>
<text x="256.8" y="11.7">4</text>
<text x="3.9" y="33.3">A</text>
<text x="291.1" y="33.3">A</text>
<text x="46.9" y="70.1">TDO_0</text>
<text x="47.8" y="67.5">TDI_0</text>
<text x="57.6" y="71.3">F8</text>
<text x="57.6" y="66.3">T9</text>
<text x="57.6" y="68.8">T8</text>
<text x="46.4" y="72.6">TCK_0</text>
<text x="46.9" y="75.1">TMS_0</text>
<text x="57.6" y="73.9">R8</text>
<text x="4.1" y="81.5">B</text>
<text x="44.9" y="80.2">CCLK_0</text>
<text x="48.4" y="82.7">M0_0</text>
<text x="57.6" y="78.9">E8</text>
<text x="57.6" y="81.5">R12</text>
<text x="291.3" y="81.5">B</text>
<text x="48.4" y="85.3">M1_0</text>
<text x="48.4" y="87.8">M2_0</text>
<text x="57.6" y="84">R11</text>
<text x="57.6" y="86.6">F13</text>
<text x="44.3" y="95.5">INIT_B_0</text>
<text x="45.2" y="93">DONE_0</text>
<text x="57.6" y="91.7">F12</text>
<text x="57.6" y="94.2">T10</text>
<text x="37.6" y="100.6">PROGRAM_B_0</text>
<text x="57.6" y="101.9">E12</text>
<text x="57.6" y="99.3">P10</text>
<text x="42.6" y="103.1">CFGBVS_0</text>
<text x="57.6" y="106.9">K10</text>
<text x="48.3" y="110.7">VN_0</text>
<text x="48.6" y="108.2">VP_0</text>
<text x="57.6" y="109.5">L9</text>
<text x="134" y="112">1</text>
<text x="138.7" y="113.3">VCCA</text>
<text x="149.3" y="113.3">VCCB</text>
<text x="159.3" y="112">11</text>
<text x="210.2" y="109.5">1</text>
<text x="215" y="110.7">CS#</text>
<text x="232.1" y="110.7">VCC</text>
<text x="240.6" y="109.5">8</text>
<text x="44.1" y="118.3">VREFN_0</text>
<text x="44.4" y="115.8">VREFP_0</text>
<text x="57.6" y="114.5">L10</text>
<text x="57.6" y="117.1">K9</text>
<text x="132.7" y="114.5">12</text>
<text x="133.8" y="119.6">2</text>
<text x="138.7" y="115.8">OE</text>
<text x="159.3" y="119.6">10</text>
<text x="210.1" y="114.5">6</text>
<text x="210.1" y="119.6">5</text>
<text x="215" y="115.8">SCLK</text>
<text x="46.6" y="125.9">DXN_0</text>
<text x="47" y="123.4">DXP_0</text>
<text x="57.6" y="122.1">M10</text>
<text x="57.6" y="124.7">M9</text>
<text x="133.8" y="124.7">4</text>
<text x="133.9" y="122.1">3</text>
<text x="138.7" y="120.9">A1</text>
<text x="138.7" y="123.4">A2</text>
<text x="138.7" y="125.9">A3</text>
<text x="152.9" y="123.4">B2</text>
<text x="153" y="125.9">B3</text>
<text x="153" y="120.9">B1</text>
<text x="159.3" y="124.7">8</text>
<text x="159.3" y="122.1">9</text>
<text x="210.1" y="122.1">2</text>
<text x="210.1" y="124.7">3</text>
<text x="215" y="123.4">SO/SIO1</text>
<text x="215" y="125.9">WP#/SIO2</text>
<text x="215" y="120.9">SI/SIO0</text>
<text x="232.3" y="125.9">PAD</text>
<text x="240.6" y="124.7">9</text>
<text x="4" y="129.7">C</text>
<text x="133.8" y="127.2">5</text>
<text x="138.7" y="128.5">A4</text>
<text x="152.9" y="128.5">B4</text>
<text x="159.3" y="127.2">7</text>
<text x="210.1" y="127.2">7</text>
<text x="215" y="128.5">RST#/SIO3</text>
<text x="231.9" y="128.5">GND</text>
<text x="240.6" y="127.2">4</text>
<text x="291.2" y="129.7">C</text>
<text x="133.8" y="132.3">6</text>
<text x="138.7" y="133.6">GND</text>
<text x="4" y="178">D</text>
<text x="201.7" y="178">Title</text>
<text x="291.2" y="178">D</text>
<text x="201.7" y="185.6">Size</text>
<text x="214.5" y="185.6">Number</text>
<text x="265.2" y="185.6">Revision</text>
<text x="203" y="189.4">A4</text>
<text x="201.7" y="193.2">Date:</text>
<text x="201.7" y="195.8">File:</text>
<text x="213.2" y="193.2">2-15-2022</text>
<text x="213.2" y="195.8">C:\Users\..\FPGA_CFG.SchDoc</text>
<text x="252.5" y="193.2">Sheet of</text>
<text x="252.5" y="195.8">Drawn By:</text>
<text x="37.9" y="199.6">1</text>
<text x="110.7" y="199.6">2</text>
<text x="183.9" y="199.6">3</text>
<text x="256.8" y="199.6">4</text>
</g>
<g font-size="2.3" fill="#000080">
<text x="35.3" y="63.7">U1D</text>
<text x="20" y="81.5">M[2:0] = 001</text>
<text x="137.7" y="79.2" transform="rotate(-90 137.7 79.2)">4.7K</text>
<text x="140.3" y="78.8" transform="rotate(-90 140.3 78.8)">R12</text>
<text x="142" y="81.5">Q1</text>
<text x="158" y="79.2" transform="rotate(-90 158 79.2)">4.7K</text>
<text x="160.6" y="78.7" transform="rotate(-90 160.6 78.7)">R13</text>
<text x="142" y="86.6">DMN62D0UW</text>
<text x="64.5" y="94.2">R14</text>
<text x="71.1" y="95.5">4.7K</text>
<text x="91.1" y="95.5">TP1</text>
<text x="64.6" y="99.3">R15</text>
<text x="71.1" y="100.6">4.7K</text>
<text x="121.4" y="101.6">C1</text>
<text x="177.3" y="101.6">C2</text>
<text x="121.4" y="104.1">100nF</text>
<text x="177.3" y="104.1">100nF</text>
<text x="213.2" y="106.9">U2</text>
<text x="136.9" y="109.5">U3</text>
<text x="253.5" y="116.8">C3</text>
<text x="253.5" y="119.4">100nF</text>
<text x="35.3" y="129.7">XC7A35T-2CSG325C</text>
<text x="71.8" y="130.8">FB2</text>
<text x="66.3" y="137.4">120@100MHZ</text>
<text x="136.9" y="137.4">TXB0104RUTR</text>
<text x="213.2" y="132.3">MX25U6432FZNI02</text>
</g>
<g font-size="2.3" fill="#800000">
<text x="65.7" y="71.3">TCK</text>
<text x="65.7" y="68.8">TDO</text>
<text x="65.7" y="66.3">TDI</text>
<text x="134.4" y="66.3">1V35</text>
<text x="144.6" y="66.3">1V35</text>
<text x="155.3" y="66.3">1V8</text>
<text x="65.7" y="73.9">TMS</text>
<text x="84.2" y="76.4">1V8</text>
<text x="65.7" y="78.9">SPI_CLK</text>
<text x="115.9" y="84">SPI_CS_1V35</text>
<text x="109" y="91.7">1V35</text>
<text x="180.7" y="91.7">1V8</text>
<text x="254.5" y="104.4">1V8</text>
<text x="192.8" y="109.5">SPI_CS</text>
<text x="114.3" y="119.6">SPI_DQ0_1V35</text>
<text x="116.7" y="114.5">GND</text>
<text x="172.6" y="114.5">GND</text>
<text x="192.8" y="119.6">SPI_DQ0</text>
<text x="192.8" y="114.5">SPI_CLK</text>
<text x="114.3" y="122.1">SPI_DQ1_1V35</text>
<text x="114.3" y="124.7">SPI_DQ2_1V35</text>
<text x="192.8" y="122.1">SPI_DQ1</text>
<text x="192.8" y="124.7">SPI_DQ2</text>
<text x="114.3" y="127.2">SPI_DQ3_1V35</text>
<text x="192.8" y="127.2">SPI_DQ3</text>
<text x="248.8" y="137.4">GND</text>
<text x="62.4" y="145">AGND</text>
<text x="78.5" y="145">GND</text>
<text x="126.8" y="145">GND</text>
</g>
</g></defs>
<path d="M2.2 8.3h292.3v193h-292.3z" fill-rule="evenodd" fill="#fffcf8"/>
<path d="M2.2 8.3h292.3v193h-292.3z" fill="none" stroke="#000" stroke-width=".13"/>
<path d="M7.3 13.4h282.1v182.9h-282.1z" fill-rule="evenodd" fill="#fffcf8"/>
<g fill="none" stroke="#000" stroke-width=".13">
<path d="M2.2 8.3h5.1M7.3 13.4h282.1v182.9h-282.1zM75.3 8.3v5.1M148.4 8.3v5.1M221.4 8.3v5.1M289.4 8.3h5.1v5.1M2.2 56.6h5.1M289.4 56.6h5.1M2.2 104.8h5.1M289.4 104.9h5.1M2.2 153.1h5.1M289.4 153.1h5.1"/>
<path d="M289.4 176h-88.9v20.3M75.3 196.3v5M148.4 196.3v5M200.5 183.6h88.9M200.5 191.2h88.9M200.5 193.7h88.9M213.2 183.6v7.6M221.4 196.3v5M251.3 191.2v5.1M264 183.6v7.6M294.5 196.3v5"/>
</g>
<path d="M63.2 115h2.6v2.5h-2.6M63.2 107.4h2.6v7.6M63.2 109.9h2.6M65.8 117.5v20.4M65.8 132.8h2.5" fill="none" stroke="#6eff6e" stroke-width="1.3"/>
<path d="M63.2 84.5h17.8v53.4M63.2 87.1h17.8M63.2 102.3h17.8M63.2 122.6h17.8M63.2 125.2h17.8M78.5 132.8h2.5M129.3 132.8v5.1M246.2 125.2h5.1M246.2 127.7h5.1M251.3 122.6v7.6" fill="none" stroke="#00be00" stroke-width="1.3"/>
<path d="M86.1 79.5v2.5h-22.9M157.3 69.3v2.5M86.1 94.7v5.1h-7.6M86.1 82v12.7h-7.6M182.7 94.7v2.5h-17.8v15.3M251.3 109.9v2.6M256.4 107.4v2.5h-10.2" fill="none" stroke="#fd8300" stroke-width="1.3"/>
<path d="M136.9 69.3v2.5M147.1 69.3v7.6M111.5 94.7v2.5h17.8v17.8" fill="none" stroke="#ff0" stroke-width="1.3"/>
<path d="M35.3 64.2h20.3v63.5h-20.3z" fill-rule="evenodd" fill="#ffffb0"/>
<path d="M35.3 64.2h20.3v63.5h-20.3z" fill="none" stroke="#800000" stroke-width=".13"/>
<path d="M55.6 92.1h7.6" fill="none" stroke="#000" stroke-width=".25"/>
<path d="M55.6 92.1l1.5-.5v1.1z" fill="#f8fcff"/>
<path d="M55.6 92.1l1.5-.5v1.1z" fill="none" stroke="#000" stroke-width=".13"/>
<path d="M57.4 91.6l1.5 .5-1.5 .6z" fill="#f8fcff"/>
<path d="M57.4 91.6l1.5 .5-1.5 .6z" fill="none" stroke="#000" stroke-width=".13"/>
<path d="M55.6 122.6h7.6" fill="none" stroke="#000" stroke-width=".25"/>
<path d="M55.6 122.6l1.5-.5v1z" fill="#f8fcff"/>
<path d="M55.6 122.6l1.5-.5v1z" fill="none" stroke="#000" stroke-width=".13"/>
<path d="M55.6 115h7.6" fill="none" stroke="#000" stroke-width=".25"/>
<path d="M55.6 115l1.5-.5v1z" fill="#f8fcff"/>
<path d="M55.6 115l1.5-.5v1z" fill="none" stroke="#000" stroke-width=".13"/>
<path d="M55.6 109.9h7.6" fill="none" stroke="#000" stroke-width=".25"/>
<path d="M55.6 109.9l1.5-.5v1z" fill="#f8fcff"/>
<path d="M55.6 109.9l1.5-.5v1z" fill="none" stroke="#000" stroke-width=".13"/>
<path d="M55.6 71.8h7.6" fill="none" stroke="#000" stroke-width=".25"/>
<path d="M55.6 71.8l1.5-.5v1z" fill="#f8fcff"/>
<path d="M55.6 71.8l1.5-.5v1zM55.6 71.3l-1 .5 1 .5" fill="none" stroke="#000" stroke-width=".13"/>
<path d="M55.6 125.2h7.6" fill="none" stroke="#000" stroke-width=".25"/>
<path d="M55.6 125.2l1.5-.5v1z" fill="#f8fcff"/>
<path d="M55.6 125.2l1.5-.5v1z" fill="none" stroke="#000" stroke-width=".13"/>
<path d="M55.6 117.5h7.6" fill="none" stroke="#000" stroke-width=".25"/>
<path d="M55.6 117.5l1.5-.5v1.1z" fill="#f8fcff"/>
<path d="M55.6 117.5l1.5-.5v1.1z" fill="none" stroke="#000" stroke-width=".13"/>
<path d="M55.6 107.4h7.6" fill="none" stroke="#000" stroke-width=".25"/>
<path d="M55.6 107.4l1.5-.5v1z" fill="#f8fcff"/>
<path d="M55.6 107.4l1.5-.5v1z" fill="none" stroke="#000" stroke-width=".13"/>
<path d="M55.6 79.5h7.6" fill="none" stroke="#000" stroke-width=".25"/>
<path d="M55.6 79.5l1.5-.6v1.1z" fill="#f8fcff"/>
<path d="M55.6 79.5l1.5-.6v1.1z" fill="none" stroke="#000" stroke-width=".13"/>
<path d="M57.4 78.9l1.5 .6-1.5 .5z" fill="#f8fcff"/>
<path d="M55.6 78.9l-1 .6 1 .5M57.4 78.9l1.5 .6-1.5 .5z" fill="none" stroke="#000" stroke-width=".13"/>
<path d="M55.6 82h7.6" fill="none" stroke="#000" stroke-width=".25"/>
<path d="M55.6 82l1.5-.5v1z" fill="#f8fcff"/>
<path d="M55.6 82l1.5-.5v1z" fill="none" stroke="#000" stroke-width=".13"/>
<path d="M55.6 84.5h7.6" fill="none" stroke="#000" stroke-width=".25"/>
<path d="M55.6 84.5l1.5-.5v1z" fill="#f8fcff"/>
<path d="M55.6 84.5l1.5-.5v1z" fill="none" stroke="#000" stroke-width=".13"/>
<path d="M55.6 94.7h7.6" fill="none" stroke="#000" stroke-width=".25"/>
<path d="M55.6 94.7l1.5-.5v1z" fill="#f8fcff"/>
<path d="M55.6 94.7l1.5-.5v1z" fill="none" stroke="#000" stroke-width=".13"/>
<path d="M57.4 94.2l1.5 .5-1.5 .5z" fill="#f8fcff"/>
<path d="M57.4 94.2l1.5 .5-1.5 .5z" fill="none" stroke="#000" stroke-width=".13"/>
<path d="M55.6 66.8h7.6" fill="none" stroke="#000" stroke-width=".25"/>
<path d="M55.6 66.8l1.5-.6v1.1z" fill="#f8fcff"/>
<path d="M55.6 66.8l1.5-.6v1.1z" fill="none" stroke="#000" stroke-width=".13"/>
<path d="M55.6 69.3h7.6" fill="none" stroke="#000" stroke-width=".25"/>
<path d="M55.6 68.8l1.5 .5-1.5 .5z" fill="#f8fcff"/>
<path d="M55.6 68.8l1.5 .5-1.5 .5z" fill="none" stroke="#000" stroke-width=".13"/>
<path d="M55.6 87.1h7.6" fill="none" stroke="#000" stroke-width=".25"/>
<path d="M55.6 87.1l1.5-.5v1z" fill="#f8fcff"/>
<path d="M55.6 87.1l1.5-.5v1z" fill="none" stroke="#000" stroke-width=".13"/>
<path d="M55.6 102.3h7.6" fill="none" stroke="#000" stroke-width=".25"/>
<path d="M55.6 102.3l1.5-.5v1z" fill="#f8fcff"/>
<path d="M55.6 102.3l1.5-.5v1z" fill="none" stroke="#000" stroke-width=".13"/>
<path d="M55.6 99.8h7.6" fill="none" stroke="#000" stroke-width=".25"/>
<path d="M55.6 99.8l1.5-.5v1z" fill="#f8fcff"/>
<path d="M55.6 99.8l1.5-.5v1z" fill="none" stroke="#000" stroke-width=".13"/>
<path d="M55.6 74.4h7.6" fill="none" stroke="#000" stroke-width=".25"/>
<path d="M55.6 74.4l1.5-.5v1z" fill="#f8fcff"/>
<path d="M55.6 74.4l1.5-.5v1z" fill="none" stroke="#000" stroke-width=".13"/>
<path d="M213.2 107.4h25.4v22.8h-25.4z" fill-rule="evenodd" fill="#ffffb0"/>
<path d="M213.2 107.4h25.4v22.8h-25.4z" fill="none" stroke="#800000" stroke-width=".13"/>
<path d="M205.6 109.9h7.6M205.6 115h7.6M238.6 109.9h7.6M205.6 122.6h7.6M205.6 125.2h7.6M205.6 127.7h7.6M205.6 120.1h7.6M238.6 125.2h7.6M238.6 127.7h7.6" fill="none" stroke="#000" stroke-width=".25"/>
<circle cx="129.3" cy="112.5" r=".51" fill="#000080"/>
<circle cx="129.3" cy="112.5" r=".51" fill="none" stroke="#000080" stroke-width=".13"/>
<path d="M136.9 109.9h20.4v25.4h-20.4z" fill-rule="evenodd" fill="#ffffb0"/>
<path d="M136.9 109.9h20.4v25.4h-20.4z" fill="none" stroke="#800000" stroke-width=".13"/>
<path d="M129.3 112.5h7.6" fill="none" stroke="#000" stroke-width=".25"/>
<circle cx="129.3" cy="112.5" r=".51" fill="#000080"/>
<circle cx="129.3" cy="112.5" r=".51" fill="none" stroke="#000080" stroke-width=".13"/>
<g fill="none" stroke="#000" stroke-width=".25">
<path d="M68.3 99.8h2M68.3 94.7h2M76.5 99.8h2M76.5 94.7h2M88.6 92.1h2.6M129.3 115h7.6M157.3 112.5h7.6M68.3 132.8h4.5M74 132.8h4.5M129.3 120.1h7.6M129.3 122.6h7.6M129.3 125.2h7.6"/>
<path d="M129.3 127.7h7.6M129.3 132.8h7.6M157.3 120.1h7.6M157.3 122.6h7.6M157.3 125.2h7.6M157.3 127.7h7.6"/>
<circle cx="92.5" cy="92.1" r="1.27"/>
</g>
<g fill="none" stroke="#800000" stroke-width=".25">
<path d="M84.8 76.9h2.6M86.1 76.9v2.6M65.8 137.9v2.5M81 137.9v2.5M129.3 137.9v2.5M63.2 140.4h5.1l-2.5 2.5zM78.5 140.4h5.1M79.2 141.2h3.6M80 141.9h2M80.8 142.7h.5M126.8 140.4h5M127.5 141.2h3.6"/>
<path d="M128.3 141.9h2M129.1 142.7h.5"/>
</g>
<path d="M70.4 98.7h6v2h-6zM70.4 93.6h6v2.1h-6zM73.4 131.5h1.3l-1.3 2.5h-1.3z" fill="none" stroke="#00f" stroke-width=".25"/>
<circle cx="119.1" cy="97.2" r=".51" fill="#000080"/>
<circle cx="119.1" cy="97.2" r=".51" fill="none" stroke="#000080" stroke-width=".13"/>
<path d="M119.1 97.2v2.6" fill="none" stroke="#000" stroke-width=".25"/>
<circle cx="119.1" cy="97.2" r=".51" fill="#000080"/>
<circle cx="119.1" cy="97.2" r=".51" fill="none" stroke="#000080" stroke-width=".13"/>
<path d="M119.1 104.8v2.6" fill="none" stroke="#000" stroke-width=".25"/>
<path d="M119.1 99.8v2M117.1 101.8h4M117.1 102.8h4M119.1 102.8v2" fill="none" stroke="#00f" stroke-width=".25"/>
<path d="M110.2 92.1h2.6M111.5 92.1v2.6M116.6 109.9h5.1M117.4 110.7h3.5M118.1 111.4h2.1M118.9 112.2h.5M119.1 107.4v2.5" fill="none" stroke="#800000" stroke-width=".25"/>
<circle cx="175.1" cy="97.2" r=".51" fill="#000080"/>
<circle cx="175.1" cy="97.2" r=".51" fill="none" stroke="#000080" stroke-width=".13"/>
<path d="M175.1 97.2v2.6" fill="none" stroke="#000" stroke-width=".25"/>
<circle cx="175.1" cy="97.2" r=".51" fill="#000080"/>
<circle cx="175.1" cy="97.2" r=".51" fill="none" stroke="#000080" stroke-width=".13"/>
<path d="M147.1 76.9v2.6M142 84.5h2.6M149.6 84.5h2.6M175.1 104.9v2.5M251.3 112.5v2.5M251.3 120.1v2.5" fill="none" stroke="#000" stroke-width=".25"/>
<g fill="none" stroke="#00f" stroke-width=".25">
<path d="M147.1 79.5v2.2M144.8 81.7h4.5M144.8 82.2h1M145.3 82.2v2.3M146.6 82.2h1M147.1 82.2v2.3h-2.5M148.3 82.2h1M148.8 82.2v2.3M175.1 99.8v2M173 101.8h4.1M173 102.8h4.1M175.1 102.8v2.1"/>
<path d="M249.3 117h4M249.3 118.1h4M251.3 115v2M251.3 118.1v2"/>
</g>
<g fill="none" stroke="#800000" stroke-width=".25">
<path d="M181.4 92.2h2.6M182.7 92.2v2.5M172.5 109.9h5.1M173.3 110.7h3.5M174 111.4h2.1M174.8 112.2h.5M175.1 107.4v2.5M255.1 104.9h2.6M256.4 104.9v2.5M248.8 132.8h5M249.5 133.5h3.6M250.3 134.3h2"/>
<path d="M251 135.1h.6M251.3 130.2v2.6"/>
</g>
<path d="M147.1 82.2l.5 1.5h-1z" fill="#00f"/>
<path d="M147.1 82.2l.5 1.5h-1z" fill="none" stroke="#00f" stroke-width=".13"/>
<path d="M135.9 73.9h2v6h-2zM156.2 73.9h2v6h-2zM148.9 84.5h.7" fill="none" stroke="#00f" stroke-width=".25"/>
<path d="M136.9 71.8v2M136.9 80v2M157.3 71.8v2M157.3 80v2" fill="none" stroke="#000" stroke-width=".25"/>
<path d="M135.7 66.8h2.5M136.9 66.8v2.5M145.8 66.8h2.6M147.1 66.8v2.5M156 66.8h2.5M157.3 66.8v2.5" fill="none" stroke="#800000" stroke-width=".25"/>
<path d="M63.2 74.4h12.7M63.2 66.8h12.7M63.2 69.3h12.7M63.2 71.8h12.7M63.2 79.5h12.7M63.2 94.7h5.1M63.2 99.8h5.1M63.2 109.9h2.6M190.3 115h15.3" fill="none" stroke="#000080" stroke-width=".25"/>
<circle cx="65.8" cy="109.9" r=".51" fill="#000080"/>
<circle cx="65.8" cy="109.9" r=".51" fill="none" stroke="#000080" stroke-width=".13"/>
<path d="M63.2 115h2.6v2.5h-2.6" fill="none" stroke="#000080" stroke-width=".25"/>
<circle cx="65.8" cy="117.5" r=".51" fill="#000080"/>
<circle cx="65.8" cy="117.5" r=".51" fill="none" stroke="#000080" stroke-width=".13"/>
<circle cx="65.8" cy="115" r=".51" fill="#000080"/>
<circle cx="65.8" cy="115" r=".51" fill="none" stroke="#000080" stroke-width=".13"/>
<path d="M65.8 117.5v20.4" fill="none" stroke="#000080" stroke-width=".25"/>
<circle cx="65.8" cy="117.5" r=".51" fill="#000080"/>
<circle cx="65.8" cy="117.5" r=".51" fill="none" stroke="#000080" stroke-width=".13"/>
<circle cx="65.8" cy="132.8" r=".51" fill="#000080"/>
<circle cx="65.8" cy="132.8" r=".51" fill="none" stroke="#000080" stroke-width=".13"/>
<path d="M63.2 107.4h2.6v7.6" fill="none" stroke="#000080" stroke-width=".25"/>
<circle cx="65.8" cy="109.9" r=".51" fill="#000080"/>
<circle cx="65.8" cy="109.9" r=".51" fill="none" stroke="#000080" stroke-width=".13"/>
<circle cx="65.8" cy="115" r=".51" fill="#000080"/>
<circle cx="65.8" cy="115" r=".51" fill="none" stroke="#000080" stroke-width=".13"/>
<path d="M63.2 102.3h17.8" fill="none" stroke="#000080" stroke-width=".25"/>
<circle cx="81" cy="102.3" r=".51" fill="#000080"/>
<circle cx="81" cy="102.3" r=".51" fill="none" stroke="#000080" stroke-width=".13"/>
<path d="M63.2 92.1h25.4M63.2 87.1h17.8" fill="none" stroke="#000080" stroke-width=".25"/>
<circle cx="81" cy="87.1" r=".51" fill="#000080"/>
<circle cx="81" cy="87.1" r=".51" fill="none" stroke="#000080" stroke-width=".13"/>
<path d="M63.2 84.5h17.8v53.4" fill="none" stroke="#000080" stroke-width=".25"/>
<circle cx="81" cy="132.8" r=".51" fill="#000080"/>
<circle cx="81" cy="132.8" r=".51" fill="none" stroke="#000080" stroke-width=".13"/>
<circle cx="81" cy="125.2" r=".51" fill="#000080"/>
<circle cx="81" cy="125.2" r=".51" fill="none" stroke="#000080" stroke-width=".13"/>
<circle cx="81" cy="122.6" r=".51" fill="#000080"/>
<circle cx="81" cy="122.6" r=".51" fill="none" stroke="#000080" stroke-width=".13"/>
<circle cx="81" cy="102.3" r=".51" fill="#000080"/>
<circle cx="81" cy="102.3" r=".51" fill="none" stroke="#000080" stroke-width=".13"/>
<circle cx="81" cy="87.1" r=".51" fill="#000080"/>
<circle cx="81" cy="87.1" r=".51" fill="none" stroke="#000080" stroke-width=".13"/>
<path d="M86.1 79.5v2.5h-22.9" fill="none" stroke="#000080" stroke-width=".25"/>
<circle cx="86.1" cy="82" r=".51" fill="#000080"/>
<circle cx="86.1" cy="82" r=".51" fill="none" stroke="#000080" stroke-width=".13"/>
<path d="M86.1 94.7v5.1h-7.6" fill="none" stroke="#000080" stroke-width=".25"/>
<circle cx="86.1" cy="94.7" r=".51" fill="#000080"/>
<circle cx="86.1" cy="94.7" r=".51" fill="none" stroke="#000080" stroke-width=".13"/>
<path d="M86.1 82v12.7h-7.6" fill="none" stroke="#000080" stroke-width=".25"/>
<circle cx="86.1" cy="82" r=".51" fill="#000080"/>
<circle cx="86.1" cy="82" r=".51" fill="none" stroke="#000080" stroke-width=".13"/>
<circle cx="86.1" cy="94.7" r=".51" fill="#000080"/>
<circle cx="86.1" cy="94.7" r=".51" fill="none" stroke="#000080" stroke-width=".13"/>
<path d="M63.2 122.6h17.8" fill="none" stroke="#000080" stroke-width=".25"/>
<circle cx="81" cy="122.6" r=".51" fill="#000080"/>
<circle cx="81" cy="122.6" r=".51" fill="none" stroke="#000080" stroke-width=".13"/>
<path d="M63.2 125.2h17.8" fill="none" stroke="#000080" stroke-width=".25"/>
<circle cx="81" cy="125.2" r=".51" fill="#000080"/>
<circle cx="81" cy="125.2" r=".51" fill="none" stroke="#000080" stroke-width=".13"/>
<path d="M65.8 132.8h2.5" fill="none" stroke="#000080" stroke-width=".25"/>
<circle cx="65.8" cy="132.8" r=".51" fill="#000080"/>
<circle cx="65.8" cy="132.8" r=".51" fill="none" stroke="#000080" stroke-width=".13"/>
<path d="M78.5 132.8h2.5" fill="none" stroke="#000080" stroke-width=".25"/>
<circle cx="81" cy="132.8" r=".51" fill="#000080"/>
<circle cx="81" cy="132.8" r=".51" fill="none" stroke="#000080" stroke-width=".13"/>
<path d="M129.3 112.5v2.5M111.5 120.1h17.8M111.5 122.6h17.8M111.5 125.2h17.8M111.5 127.7h17.8M129.3 132.8v5.1" fill="none" stroke="#000080" stroke-width=".25"/>
<circle cx="129.3" cy="112.5" r=".51" fill="#000080"/>
<circle cx="129.3" cy="112.5" r=".51" fill="none" stroke="#000080" stroke-width=".13"/>
<path d="M111.5 94.7v2.5h17.8v15.3" fill="none" stroke="#000080" stroke-width=".25"/>
<circle cx="129.3" cy="112.5" r=".51" fill="#000080"/>
<circle cx="129.3" cy="112.5" r=".51" fill="none" stroke="#000080" stroke-width=".13"/>
<circle cx="119.1" cy="97.2" r=".51" fill="#000080"/>
<circle cx="119.1" cy="97.2" r=".51" fill="none" stroke="#000080" stroke-width=".13"/>
<path d="M182.7 94.7v2.5h-17.8v15.3" fill="none" stroke="#000080" stroke-width=".25"/>
<circle cx="175.1" cy="97.2" r=".51" fill="#000080"/>
<circle cx="175.1" cy="97.2" r=".51" fill="none" stroke="#000080" stroke-width=".13"/>
<path d="M256.4 107.4v2.5h-10.2" fill="none" stroke="#000080" stroke-width=".25"/>
<circle cx="251.3" cy="109.9" r=".51" fill="#000080"/>
<circle cx="251.3" cy="109.9" r=".51" fill="none" stroke="#000080" stroke-width=".13"/>
<path d="M251.3 109.9v2.6" fill="none" stroke="#000080" stroke-width=".25"/>
<circle cx="251.3" cy="109.9" r=".51" fill="#000080"/>
<circle cx="251.3" cy="109.9" r=".51" fill="none" stroke="#000080" stroke-width=".13"/>
<path d="M251.3 122.6v7.6" fill="none" stroke="#000080" stroke-width=".25"/>
<circle cx="251.3" cy="125.2" r=".51" fill="#000080"/>
<circle cx="251.3" cy="125.2" r=".51" fill="none" stroke="#000080" stroke-width=".13"/>
<circle cx="251.3" cy="127.7" r=".51" fill="#000080"/>
<circle cx="251.3" cy="127.7" r=".51" fill="none" stroke="#000080" stroke-width=".13"/>
<path d="M246.2 127.7h5.1" fill="none" stroke="#000080" stroke-width=".25"/>
<circle cx="251.3" cy="127.7" r=".51" fill="#000080"/>
<circle cx="251.3" cy="127.7" r=".51" fill="none" stroke="#000080" stroke-width=".13"/>
<path d="M246.2 125.2h5.1" fill="none" stroke="#000080" stroke-width=".25"/>
<circle cx="251.3" cy="125.2" r=".51" fill="#000080"/>
<circle cx="251.3" cy="125.2" r=".51" fill="none" stroke="#000080" stroke-width=".13"/>
<path d="M136.9 69.3v2.5M157.3 69.3v2.5M136.9 82v2.5M164.9 120.1h40.7M164.9 122.6h40.7M164.9 125.2h40.7M164.9 127.7h40.7" fill="none" stroke="#000080" stroke-width=".25"/>
<circle cx="136.9" cy="84.5" r=".51" fill="#000080"/>
<circle cx="136.9" cy="84.5" r=".51" fill="none" stroke="#000080" stroke-width=".13"/>
<path d="M147.1 69.3v7.6M157.3 82v2.5" fill="none" stroke="#000080" stroke-width=".25"/>
<circle cx="157.3" cy="84.5" r=".51" fill="#000080"/>
<circle cx="157.3" cy="84.5" r=".51" fill="none" stroke="#000080" stroke-width=".13"/>
<path d="M111.5 84.5h30.5" fill="none" stroke="#000080" stroke-width=".25"/>
<circle cx="136.9" cy="84.5" r=".51" fill="#000080"/>
<circle cx="136.9" cy="84.5" r=".51" fill="none" stroke="#000080" stroke-width=".13"/>
<path d="M152.2 84.5h38.1v25.4h15.3" fill="none" stroke="#000080" stroke-width=".25"/>
<circle cx="157.3" cy="84.5" r=".51" fill="#000080"/>
<circle cx="157.3" cy="84.5" r=".51" fill="none" stroke="#000080" stroke-width=".13"/>
<use href="#words"/>
</svg>
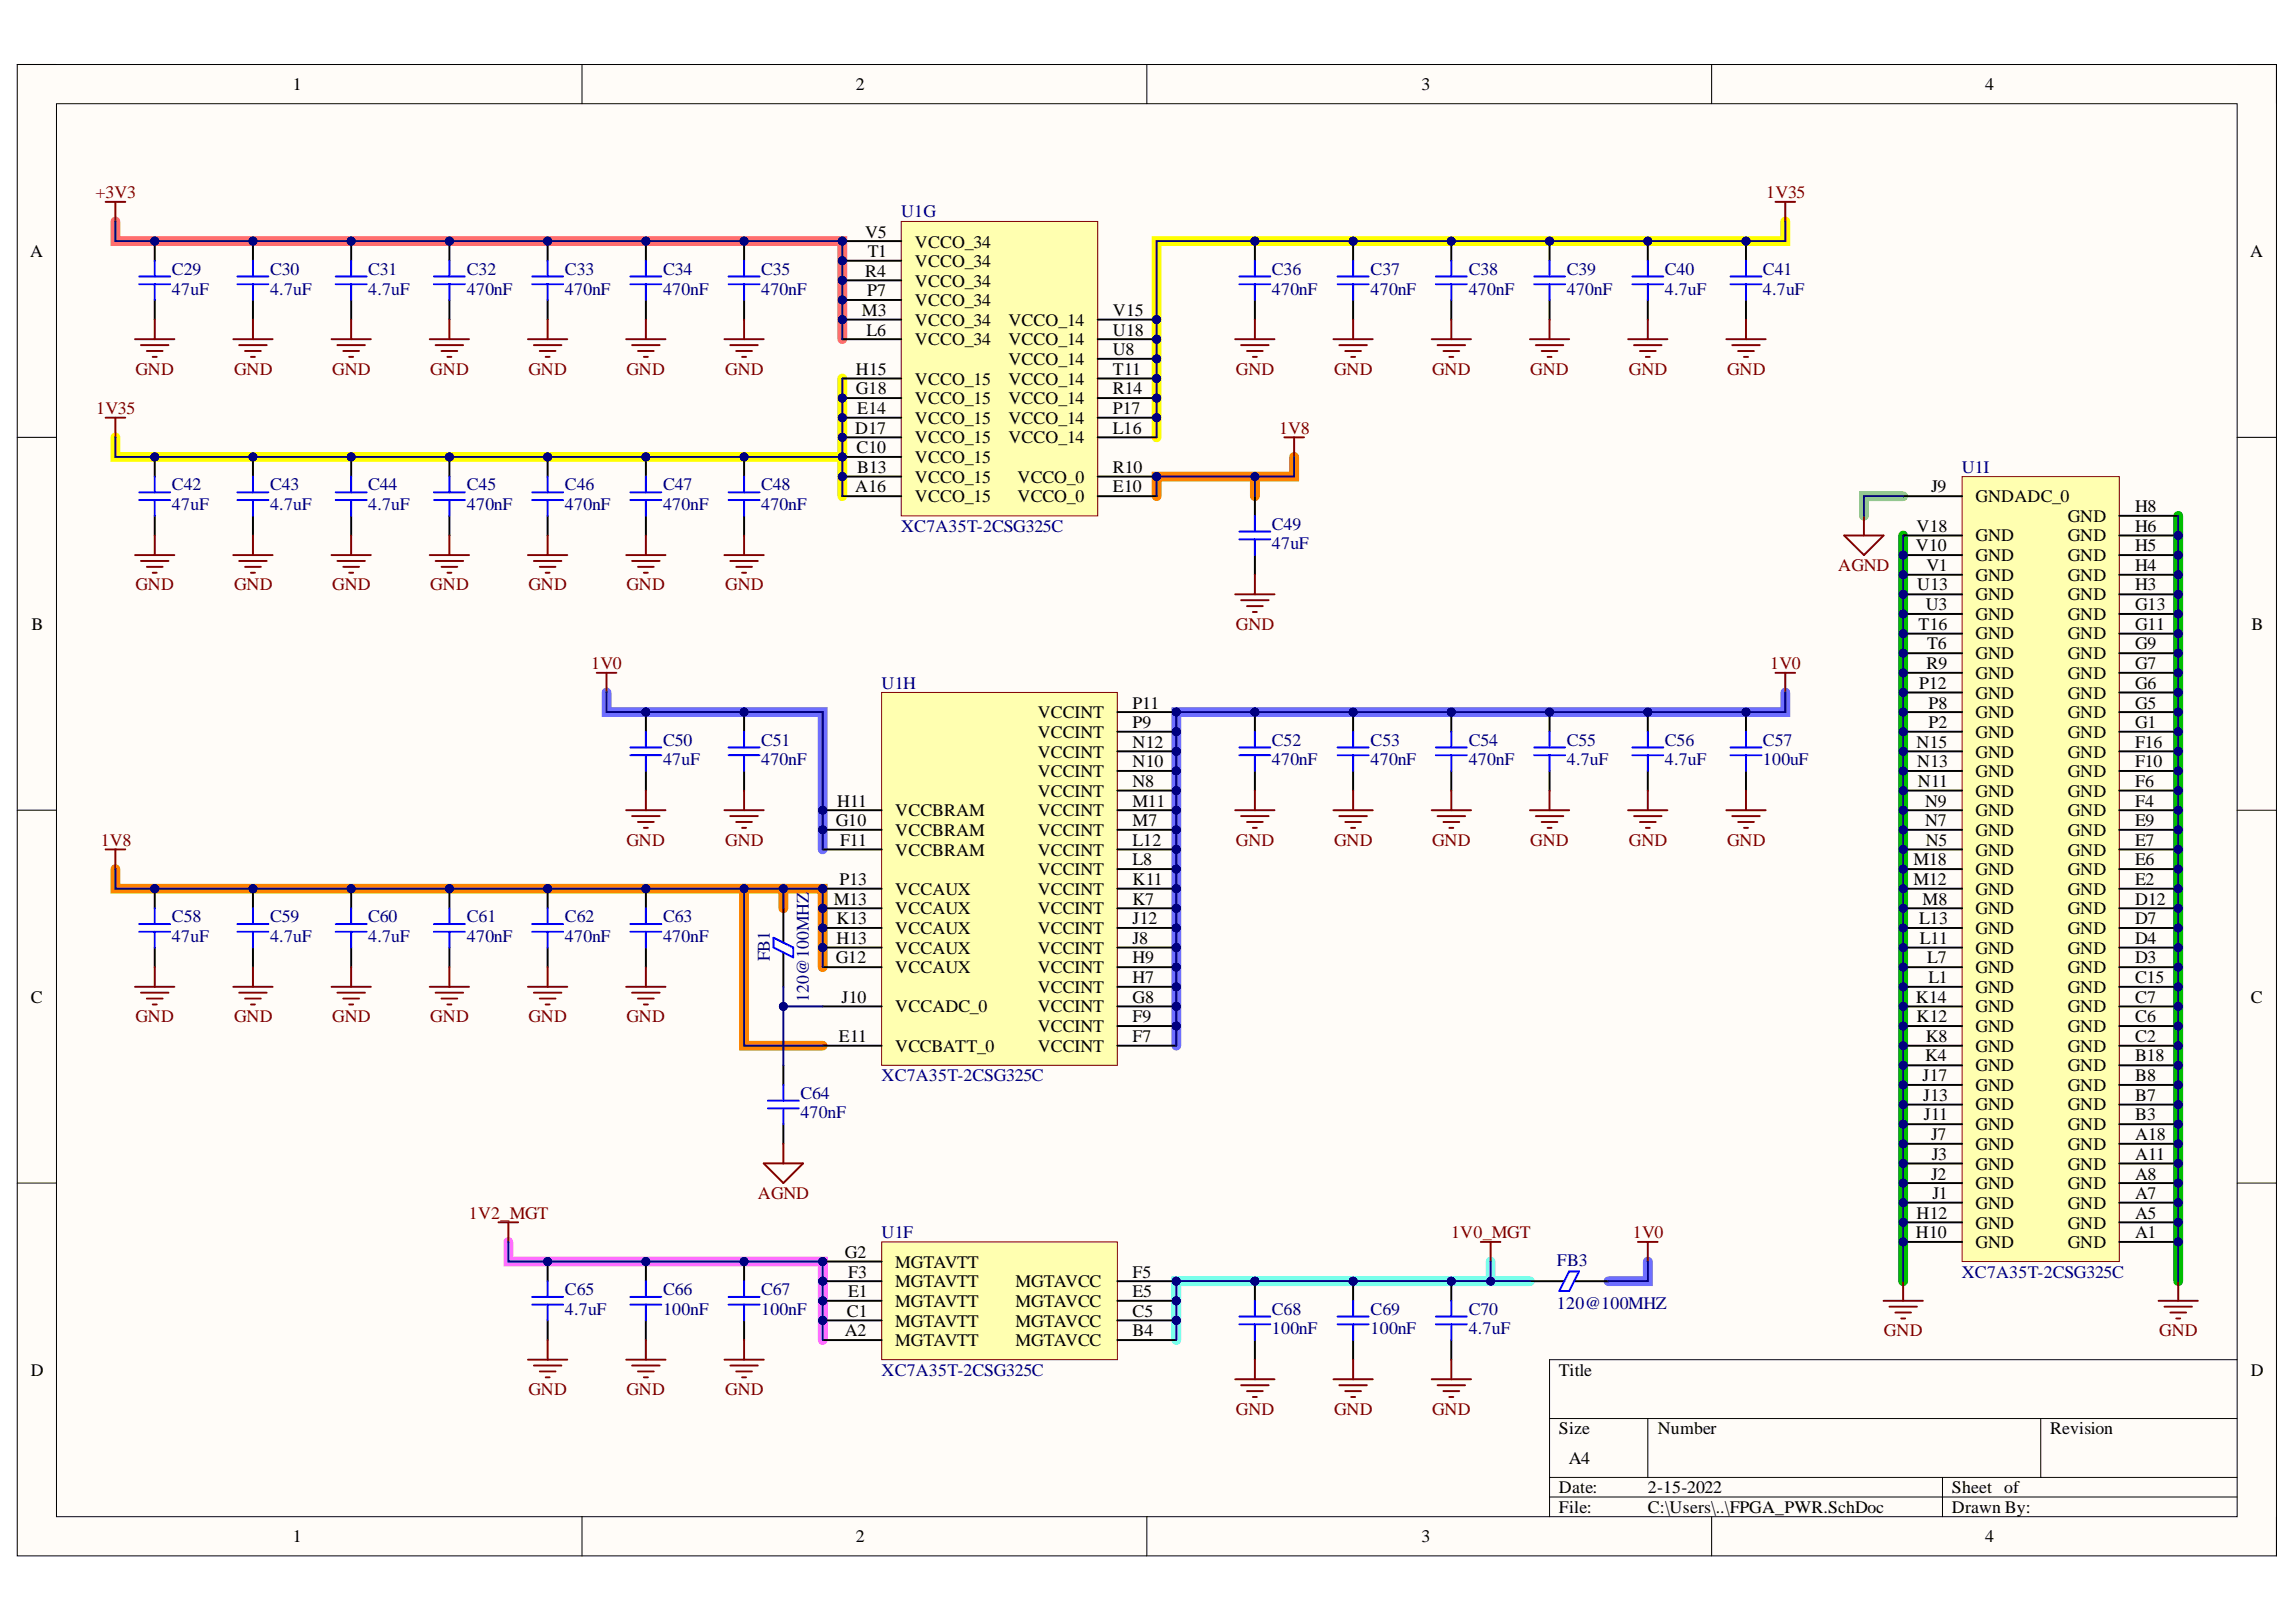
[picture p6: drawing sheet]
<svg xmlns="http://www.w3.org/2000/svg" width="297mm" height="210mm" viewBox="0 0 297 210" stroke-linecap="round" stroke-linejoin="round" font-family="sans-serif">
<defs><g id="words">
<g font-size="2.3">
<text x="37.9" y="11.7">1</text>
<text x="110.7" y="11.7">2</text>
<text x="183.9" y="11.7">3</text>
<text x="256.8" y="11.7">4</text>
<text x="3.9" y="33.3">A</text>
<text x="111.9" y="35.8">R4</text>
<text x="111.9" y="30.8">V5</text>
<text x="112.3" y="33.3">T1</text>
<text x="118.4" y="34.6">VCCO_34</text>
<text x="118.4" y="32">VCCO_34</text>
<text x="291.1" y="33.3">A</text>
<text x="111.5" y="40.9">M3</text>
<text x="112.2" y="38.4">P7</text>
<text x="118.4" y="39.6">VCCO_34</text>
<text x="118.4" y="37.1">VCCO_34</text>
<text x="144" y="40.9">V15</text>
<text x="112.1" y="43.4">L6</text>
<text x="118.4" y="44.7">VCCO_34</text>
<text x="118.4" y="42.2">VCCO_34</text>
<text x="130.5" y="47.2">VCCO_14</text>
<text x="130.5" y="44.7">VCCO_14</text>
<text x="130.5" y="42.2">VCCO_14</text>
<text x="144" y="46">U8</text>
<text x="144" y="43.4">U18</text>
<text x="110.7" y="51">G18</text>
<text x="110.7" y="48.5">H15</text>
<text x="110.9" y="53.6">E14</text>
<text x="118.4" y="52.3">VCCO_15</text>
<text x="118.4" y="49.8">VCCO_15</text>
<text x="130.5" y="52.3">VCCO_14</text>
<text x="130.5" y="49.8">VCCO_14</text>
<text x="144" y="53.6">P17</text>
<text x="144" y="51">R14</text>
<text x="144" y="48.5">T11</text>
<text x="110.7" y="56.1">D17</text>
<text x="110.8" y="58.7">C10</text>
<text x="118.4" y="59.9">VCCO_15</text>
<text x="118.4" y="57.4">VCCO_15</text>
<text x="118.4" y="54.9">VCCO_15</text>
<text x="130.5" y="57.4">VCCO_14</text>
<text x="130.5" y="54.9">VCCO_14</text>
<text x="144" y="56.1">L16</text>
<text x="110.7" y="63.7">A16</text>
<text x="110.9" y="61.2">B13</text>
<text x="118.4" y="65">VCCO_15</text>
<text x="118.4" y="62.5">VCCO_15</text>
<text x="131.6" y="65">VCCO_0</text>
<text x="131.6" y="62.5">VCCO_0</text>
<text x="144" y="63.7">E10</text>
<text x="144" y="61.2">R10</text>
<text x="249.8" y="63.7">J9</text>
<text x="255.6" y="65">GNDADC_0</text>
<text x="247.9" y="71.3">V10</text>
<text x="248" y="68.8">V18</text>
<text x="255.6" y="70.1">GND</text>
<text x="267.5" y="70.1">GND</text>
<text x="267.5" y="67.5">GND</text>
<text x="276.2" y="71.3">H5</text>
<text x="276.2" y="68.8">H6</text>
<text x="276.2" y="66.3">H8</text>
<text x="248" y="76.4">U13</text>
<text x="249.2" y="73.9">V1</text>
<text x="255.6" y="77.7">GND</text>
<text x="255.6" y="75.1">GND</text>
<text x="255.6" y="72.6">GND</text>
<text x="267.5" y="77.7">GND</text>
<text x="267.5" y="75.1">GND</text>
<text x="267.5" y="72.6">GND</text>
<text x="276.2" y="76.4">H3</text>
<text x="276.2" y="73.9">H4</text>
<text x="4.1" y="81.5">B</text>
<text x="248.2" y="81.5">T16</text>
<text x="249.1" y="78.9">U3</text>
<text x="255.6" y="82.7">GND</text>
<text x="255.6" y="80.2">GND</text>
<text x="267.5" y="82.7">GND</text>
<text x="267.5" y="80.2">GND</text>
<text x="276.2" y="81.5">G11</text>
<text x="276.2" y="78.9">G13</text>
<text x="291.3" y="81.5">B</text>
<text x="248.3" y="89.2">P12</text>
<text x="249.2" y="86.6">R9</text>
<text x="249.3" y="84">T6</text>
<text x="255.6" y="87.8">GND</text>
<text x="255.6" y="85.3">GND</text>
<text x="267.5" y="87.8">GND</text>
<text x="267.5" y="85.3">GND</text>
<text x="276.2" y="89.2">G6</text>
<text x="276.2" y="86.6">G7</text>
<text x="276.2" y="84">G9</text>
<text x="134.3" y="95.5">VCCINT</text>
<text x="134.3" y="93">VCCINT</text>
<text x="146.5" y="94.2">P9</text>
<text x="146.5" y="91.7">P11</text>
<text x="249.5" y="94.2">P2</text>
<text x="249.5" y="91.7">P8</text>
<text x="255.6" y="95.5">GND</text>
<text x="255.6" y="93">GND</text>
<text x="255.6" y="90.4">GND</text>
<text x="267.5" y="95.5">GND</text>
<text x="267.5" y="93">GND</text>
<text x="267.5" y="90.4">GND</text>
<text x="276.2" y="94.2">G1</text>
<text x="276.2" y="91.7">G5</text>
<text x="134.3" y="100.6">VCCINT</text>
<text x="134.3" y="98">VCCINT</text>
<text x="146.5" y="101.9">N8</text>
<text x="146.5" y="99.3">N10</text>
<text x="146.5" y="96.8">N12</text>
<text x="248" y="96.8">N15</text>
<text x="248" y="99.3">N13</text>
<text x="248.1" y="101.9">N11</text>
<text x="255.6" y="100.6">GND</text>
<text x="255.6" y="98">GND</text>
<text x="267.5" y="100.6">GND</text>
<text x="267.5" y="98">GND</text>
<text x="276.2" y="101.9">F6</text>
<text x="276.2" y="99.3">F10</text>
<text x="276.2" y="96.8">F16</text>
<text x="108.1" y="106.9">G10</text>
<text x="108.3" y="104.4">H11</text>
<text x="115.8" y="105.7">VCCBRAM</text>
<text x="134.3" y="105.7">VCCINT</text>
<text x="134.3" y="103.1">VCCINT</text>
<text x="146.5" y="106.9">M7</text>
<text x="146.5" y="104.4">M11</text>
<text x="249.1" y="106.9">N7</text>
<text x="249.1" y="104.4">N9</text>
<text x="255.6" y="105.7">GND</text>
<text x="255.6" y="103.1">GND</text>
<text x="267.5" y="105.7">GND</text>
<text x="267.5" y="103.1">GND</text>
<text x="276.2" y="106.9">E9</text>
<text x="276.2" y="104.4">F4</text>
<text x="108.7" y="109.5">F11</text>
<text x="115.8" y="110.7">VCCBRAM</text>
<text x="115.8" y="108.2">VCCBRAM</text>
<text x="134.3" y="113.3">VCCINT</text>
<text x="134.3" y="110.7">VCCINT</text>
<text x="134.3" y="108.2">VCCINT</text>
<text x="146.5" y="112">L8</text>
<text x="146.5" y="109.5">L12</text>
<text x="247.5" y="112">M18</text>
<text x="249.1" y="109.5">N5</text>
<text x="255.6" y="113.3">GND</text>
<text x="255.6" y="110.7">GND</text>
<text x="255.6" y="108.2">GND</text>
<text x="267.5" y="113.3">GND</text>
<text x="267.5" y="110.7">GND</text>
<text x="267.5" y="108.2">GND</text>
<text x="276.2" y="112">E6</text>
<text x="276.2" y="109.5">E7</text>
<text x="107.9" y="117.1">M13</text>
<text x="108.2" y="119.6">K13</text>
<text x="108.6" y="114.5">P13</text>
<text x="115.8" y="118.3">VCCAUX</text>
<text x="115.8" y="115.8">VCCAUX</text>
<text x="134.3" y="118.3">VCCINT</text>
<text x="134.3" y="115.8">VCCINT</text>
<text x="146.5" y="119.6">J12</text>
<text x="146.5" y="117.1">K7</text>
<text x="146.5" y="114.5">K11</text>
<text x="247.5" y="114.5">M12</text>
<text x="248.3" y="119.6">L13</text>
<text x="248.7" y="117.1">M8</text>
<text x="255.6" y="118.3">GND</text>
<text x="255.6" y="115.8">GND</text>
<text x="267.5" y="118.3">GND</text>
<text x="267.5" y="115.8">GND</text>
<text x="276.2" y="119.6">D7</text>
<text x="276.2" y="117.1">D12</text>
<text x="276.2" y="114.5">E2</text>
<text x="108.1" y="124.7">G12</text>
<text x="108.2" y="122.1">H13</text>
<text x="115.8" y="125.9">VCCAUX</text>
<text x="115.8" y="123.4">VCCAUX</text>
<text x="115.8" y="120.9">VCCAUX</text>
<text x="134.3" y="125.9">VCCINT</text>
<text x="134.3" y="123.4">VCCINT</text>
<text x="134.3" y="120.9">VCCINT</text>
<text x="146.5" y="124.7">H9</text>
<text x="146.5" y="122.1">J8</text>
<text x="248.4" y="122.1">L11</text>
<text x="249.3" y="124.7">L7</text>
<text x="255.6" y="125.9">GND</text>
<text x="255.6" y="123.4">GND</text>
<text x="255.6" y="120.9">GND</text>
<text x="267.5" y="125.9">GND</text>
<text x="267.5" y="123.4">GND</text>
<text x="267.5" y="120.9">GND</text>
<text x="276.2" y="124.7">D3</text>
<text x="276.2" y="122.1">D4</text>
<text x="4" y="129.7">C</text>
<text x="108.9" y="129.7">J10</text>
<text x="115.8" y="131">VCCADC_0</text>
<text x="134.3" y="131">VCCINT</text>
<text x="134.3" y="128.5">VCCINT</text>
<text x="146.5" y="129.7">G8</text>
<text x="146.5" y="127.2">H7</text>
<text x="247.9" y="129.7">K14</text>
<text x="249.5" y="127.2">L1</text>
<text x="255.6" y="131">GND</text>
<text x="255.6" y="128.5">GND</text>
<text x="267.5" y="131">GND</text>
<text x="267.5" y="128.5">GND</text>
<text x="276.2" y="129.7">C7</text>
<text x="276.2" y="127.2">C15</text>
<text x="291.2" y="129.7">C</text>
<text x="108.5" y="134.8">E11</text>
<text x="115.8" y="136.1">VCCBATT_0</text>
<text x="134.3" y="136.1">VCCINT</text>
<text x="134.3" y="133.6">VCCINT</text>
<text x="146.5" y="134.8">F7</text>
<text x="146.5" y="132.3">F9</text>
<text x="248" y="132.3">K12</text>
<text x="249.1" y="137.4">K4</text>
<text x="249.1" y="134.8">K8</text>
<text x="255.6" y="136.1">GND</text>
<text x="255.6" y="133.6">GND</text>
<text x="267.5" y="136.1">GND</text>
<text x="267.5" y="133.6">GND</text>
<text x="276.2" y="137.4">B18</text>
<text x="276.2" y="134.8">C2</text>
<text x="276.2" y="132.3">C6</text>
<text x="248.7" y="139.9">J17</text>
<text x="248.8" y="142.4">J13</text>
<text x="255.6" y="143.7">GND</text>
<text x="255.6" y="141.2">GND</text>
<text x="255.6" y="138.6">GND</text>
<text x="267.5" y="143.7">GND</text>
<text x="267.5" y="141.2">GND</text>
<text x="267.5" y="138.6">GND</text>
<text x="276.2" y="142.4">B7</text>
<text x="276.2" y="139.9">B8</text>
<text x="248.9" y="145">J11</text>
<text x="249.8" y="147.5">J7</text>
<text x="255.6" y="148.9">GND</text>
<text x="255.6" y="146.2">GND</text>
<text x="267.5" y="148.9">GND</text>
<text x="267.5" y="146.2">GND</text>
<text x="276.2" y="147.5">A18</text>
<text x="276.2" y="145">B3</text>
<text x="249.8" y="152.7">J2</text>
<text x="249.9" y="150.1">J3</text>
<text x="250" y="155.2">J1</text>
<text x="255.6" y="153.9">GND</text>
<text x="255.6" y="151.4">GND</text>
<text x="267.5" y="153.9">GND</text>
<text x="267.5" y="151.4">GND</text>
<text x="276.2" y="155.2">A7</text>
<text x="276.2" y="152.7">A8</text>
<text x="276.2" y="150.1">A11</text>
<text x="247.9" y="160.3">H10</text>
<text x="248" y="157.7">H12</text>
<text x="255.6" y="161.5">GND</text>
<text x="255.6" y="159">GND</text>
<text x="255.6" y="156.5">GND</text>
<text x="267.5" y="161.5">GND</text>
<text x="267.5" y="159">GND</text>
<text x="267.5" y="156.5">GND</text>
<text x="276.2" y="160.3">A1</text>
<text x="276.2" y="157.7">A5</text>
<text x="109.3" y="162.8">G2</text>
<text x="109.7" y="167.9">E1</text>
<text x="109.7" y="165.3">F3</text>
<text x="115.8" y="166.6">MGTAVTT</text>
<text x="115.8" y="164.1">MGTAVTT</text>
<text x="131.4" y="166.6">MGTAVCC</text>
<text x="146.5" y="167.9">E5</text>
<text x="146.5" y="165.3">F5</text>
<text x="109.3" y="172.9">A2</text>
<text x="109.6" y="170.4">C1</text>
<text x="115.8" y="171.7">MGTAVTT</text>
<text x="115.8" y="169.1">MGTAVTT</text>
<text x="131.4" y="171.7">MGTAVCC</text>
<text x="131.4" y="169.1">MGTAVCC</text>
<text x="146.5" y="172.9">B4</text>
<text x="146.5" y="170.4">C5</text>
<text x="4" y="178">D</text>
<text x="115.8" y="174.2">MGTAVTT</text>
<text x="131.4" y="174.2">MGTAVCC</text>
<text x="201.7" y="178">Title</text>
<text x="291.2" y="178">D</text>
<text x="201.7" y="185.6">Size</text>
<text x="214.5" y="185.6">Number</text>
<text x="265.2" y="185.6">Revision</text>
<text x="203" y="189.4">A4</text>
<text x="201.7" y="193.2">Date:</text>
<text x="201.7" y="195.8">File:</text>
<text x="213.2" y="193.2">2-15-2022</text>
<text x="213.2" y="195.8">C:\Users\..\FPGA_PWR.SchDoc</text>
<text x="252.5" y="193.2">Sheet of</text>
<text x="252.5" y="195.8">Drawn By:</text>
<text x="37.9" y="199.6">1</text>
<text x="110.7" y="199.6">2</text>
<text x="183.9" y="199.6">3</text>
<text x="256.8" y="199.6">4</text>
</g>
<g font-size="2.3" fill="#800000">
<text x="12.4" y="25.6">+3V3</text>
<text x="228.5" y="25.6">1V35</text>
<text x="12.4" y="53.6">1V35</text>
<text x="17.5" y="48.5">GND</text>
<text x="30.3" y="48.5">GND</text>
<text x="43" y="48.5">GND</text>
<text x="55.7" y="48.5">GND</text>
<text x="68.4" y="48.5">GND</text>
<text x="81" y="48.5">GND</text>
<text x="93.8" y="48.5">GND</text>
<text x="159.9" y="48.5">GND</text>
<text x="172.6" y="48.5">GND</text>
<text x="185.3" y="48.5">GND</text>
<text x="198" y="48.5">GND</text>
<text x="210.7" y="48.5">GND</text>
<text x="223.4" y="48.5">GND</text>
<text x="165.5" y="56.1">1V8</text>
<text x="17.5" y="76.4">GND</text>
<text x="30.3" y="76.4">GND</text>
<text x="43" y="76.4">GND</text>
<text x="55.7" y="76.4">GND</text>
<text x="68.4" y="76.4">GND</text>
<text x="81" y="76.4">GND</text>
<text x="93.8" y="76.4">GND</text>
<text x="237.8" y="73.9">AGND</text>
<text x="159.9" y="81.5">GND</text>
<text x="76.5" y="86.6">1V0</text>
<text x="229" y="86.6">1V0</text>
<text x="13" y="109.5">1V8</text>
<text x="81" y="109.5">GND</text>
<text x="93.8" y="109.5">GND</text>
<text x="159.9" y="109.5">GND</text>
<text x="172.6" y="109.5">GND</text>
<text x="185.3" y="109.5">GND</text>
<text x="198" y="109.5">GND</text>
<text x="210.7" y="109.5">GND</text>
<text x="223.4" y="109.5">GND</text>
<text x="17.5" y="132.3">GND</text>
<text x="30.3" y="132.3">GND</text>
<text x="43" y="132.3">GND</text>
<text x="55.7" y="132.3">GND</text>
<text x="68.4" y="132.3">GND</text>
<text x="81" y="132.3">GND</text>
<text x="98.1" y="155.2">AGND</text>
<text x="60.7" y="157.7">1V2_MGT</text>
<text x="187.7" y="160.3">1V0_MGT</text>
<text x="211.2" y="160.3">1V0</text>
<text x="243.7" y="172.9">GND</text>
<text x="279.3" y="172.9">GND</text>
<text x="68.4" y="180.6">GND</text>
<text x="81" y="180.6">GND</text>
<text x="93.8" y="180.6">GND</text>
<text x="159.9" y="183.1">GND</text>
<text x="172.6" y="183.1">GND</text>
<text x="185.3" y="183.1">GND</text>
</g>
<g font-size="2.3" fill="#000080">
<text x="116.6" y="28.1">U1G</text>
<text x="22.2" y="35.6">C29</text>
<text x="34.9" y="35.6">C30</text>
<text x="47.6" y="35.6">C31</text>
<text x="60.4" y="35.6">C32</text>
<text x="73.1" y="35.6">C33</text>
<text x="85.8" y="35.6">C34</text>
<text x="98.5" y="35.6">C35</text>
<text x="164.5" y="35.6">C36</text>
<text x="177.3" y="35.6">C37</text>
<text x="190" y="35.6">C38</text>
<text x="202.7" y="35.6">C39</text>
<text x="215.4" y="35.6">C40</text>
<text x="228.1" y="35.6">C41</text>
<text x="22.2" y="38.1">47uF</text>
<text x="34.9" y="38.1">4.7uF</text>
<text x="47.6" y="38.1">4.7uF</text>
<text x="60.4" y="38.1">470nF</text>
<text x="73.1" y="38.1">470nF</text>
<text x="85.8" y="38.1">470nF</text>
<text x="98.5" y="38.1">470nF</text>
<text x="164.5" y="38.1">470nF</text>
<text x="177.3" y="38.1">470nF</text>
<text x="190" y="38.1">470nF</text>
<text x="202.7" y="38.1">470nF</text>
<text x="215.4" y="38.1">4.7uF</text>
<text x="228.1" y="38.1">4.7uF</text>
<text x="22.2" y="63.5">C42</text>
<text x="34.9" y="63.5">C43</text>
<text x="47.6" y="63.5">C44</text>
<text x="60.4" y="63.5">C45</text>
<text x="73.1" y="63.5">C46</text>
<text x="85.8" y="63.5">C47</text>
<text x="98.5" y="63.5">C48</text>
<text x="253.8" y="61.2">U1I</text>
<text x="22.2" y="66">47uF</text>
<text x="34.9" y="66">4.7uF</text>
<text x="47.6" y="66">4.7uF</text>
<text x="60.4" y="66">470nF</text>
<text x="73.1" y="66">470nF</text>
<text x="85.8" y="66">470nF</text>
<text x="98.5" y="66">470nF</text>
<text x="116.6" y="68.8">XC7A35T-2CSG325C</text>
<text x="164.5" y="68.5">C49</text>
<text x="164.5" y="71.1">47uF</text>
<text x="114" y="89.2">U1H</text>
<text x="85.8" y="96.5">C50</text>
<text x="85.8" y="99.1">47uF</text>
<text x="98.5" y="96.5">C51</text>
<text x="98.5" y="99.1">470nF</text>
<text x="164.5" y="96.5">C52</text>
<text x="164.5" y="99.1">470nF</text>
<text x="177.3" y="96.5">C53</text>
<text x="177.3" y="99.1">470nF</text>
<text x="190" y="96.5">C54</text>
<text x="190" y="99.1">470nF</text>
<text x="202.7" y="96.5">C55</text>
<text x="202.7" y="99.1">4.7uF</text>
<text x="215.4" y="96.5">C56</text>
<text x="215.4" y="99.1">4.7uF</text>
<text x="228.1" y="96.5">C57</text>
<text x="228.1" y="99.1">100uF</text>
<text x="22.2" y="119.4">C58</text>
<text x="34.9" y="119.4">C59</text>
<text x="47.6" y="119.4">C60</text>
<text x="60.4" y="119.4">C61</text>
<text x="73.1" y="119.4">C62</text>
<text x="85.8" y="119.4">C63</text>
<text x="22.2" y="121.9">47uF</text>
<text x="34.9" y="121.9">4.7uF</text>
<text x="47.6" y="121.9">4.7uF</text>
<text x="60.4" y="121.9">470nF</text>
<text x="73.1" y="121.9">470nF</text>
<text x="85.8" y="121.9">470nF</text>
<text x="99.6" y="124.4" transform="rotate(-90 99.6 124.4)">FB1</text>
<text x="104.6" y="129.7" transform="rotate(-90 104.6 129.7)">120@100MHZ</text>
<text x="103.5" y="142.2">C64</text>
<text x="114" y="139.9">XC7A35T-2CSG325C</text>
<text x="103.5" y="144.7">470nF</text>
<text x="114" y="160.3">U1F</text>
<text x="73.1" y="167.6">C65</text>
<text x="85.8" y="167.6">C66</text>
<text x="98.5" y="167.6">C67</text>
<text x="201.4" y="163.8">FB3</text>
<text x="253.8" y="165.3">XC7A35T-2CSG325C</text>
<text x="73.1" y="170.2">4.7uF</text>
<text x="85.8" y="170.2">100nF</text>
<text x="98.5" y="170.2">100nF</text>
<text x="164.5" y="170.2">C68</text>
<text x="164.5" y="172.7">100nF</text>
<text x="177.3" y="170.2">C69</text>
<text x="177.3" y="172.7">100nF</text>
<text x="190" y="170.2">C70</text>
<text x="190" y="172.7">4.7uF</text>
<text x="201.4" y="169.4">120@100MHZ</text>
<text x="114" y="178">XC7A35T-2CSG325C</text>
</g>
</g></defs>
<path d="M2.2 8.3h292.3v193h-292.3z" fill-rule="evenodd" fill="#fffcf8"/>
<path d="M2.2 8.3h292.3v193h-292.3z" fill="none" stroke="#000" stroke-width=".13"/>
<path d="M7.3 13.4h282.1v182.9h-282.1z" fill-rule="evenodd" fill="#fffcf8"/>
<g fill="none" stroke="#000" stroke-width=".13">
<path d="M2.2 8.3h5.1M7.3 13.4h282.1v182.9h-282.1zM75.3 8.3v5.1M148.4 8.3v5.1M221.4 8.3v5.1M289.4 8.3h5.1v5.1M2.2 56.6h5.1M289.4 56.6h5.1M2.2 104.8h5.1M289.4 104.9h5.1M2.2 153.1h5.1M289.4 153.1h5.1"/>
<path d="M289.4 176h-88.9v20.3M75.3 196.3v5M148.4 196.3v5M200.5 183.6h88.9M200.5 191.2h88.9M200.5 193.7h88.9M213.2 183.6v7.6M221.4 196.3v5M251.3 191.2v5.1M264 183.6v7.6M294.5 196.3v5"/>
</g>
<path d="M14.9 28.7v2.5h94.1v12.7" fill="none" stroke="#ff6e6e" stroke-width="1.3"/>
<path d="M231 28.7v2.5h-81.4v25.4M14.9 56.6v2.5h94.1v5.1M109 49v10.1" fill="none" stroke="#ff0" stroke-width="1.3"/>
<path d="M78.5 89.6v2.5h27.9v17.8M231 89.6v2.6h-78.8v43.1M213.2 163.3v2.5h-5.1" fill="none" stroke="#6e6eff" stroke-width="1.3"/>
<path d="M65.8 160.7v2.6h40.6v10.1" fill="none" stroke="#ff6eff" stroke-width="1.3"/>
<path d="M192.8 163.3v2.5h-40.6v7.6M192.8 165.8h5.1" fill="none" stroke="#6effff" stroke-width="1.3"/>
<path d="M246.2 69.3v96.5M281.8 66.8v99" fill="none" stroke="#00be00" stroke-width="1.3"/>
<path d="M246.2 64.2h-5.1v2.6" fill="none" stroke="#6eff6e" stroke-width="1.3"/>
<path d="M167.4 59.1v2.6h-17.8v2.5M162.3 61.7v2.5M14.9 112.5v2.5h91.5v10.2M96.3 115v20.3h10.1M101.3 115v2.5" fill="none" stroke="#fd8300" stroke-width="1.3"/>
<circle cx="152.2" cy="170.9" r=".51" fill="#000080"/>
<circle cx="152.2" cy="170.9" r=".51" fill="none" stroke="#000080" stroke-width=".13"/>
<circle cx="152.2" cy="168.3" r=".51" fill="#000080"/>
<circle cx="152.2" cy="168.3" r=".51" fill="none" stroke="#000080" stroke-width=".13"/>
<circle cx="152.2" cy="165.8" r=".51" fill="#000080"/>
<circle cx="152.2" cy="165.8" r=".51" fill="none" stroke="#000080" stroke-width=".13"/>
<circle cx="106.4" cy="170.9" r=".51" fill="#000080"/>
<circle cx="106.4" cy="170.9" r=".51" fill="none" stroke="#000080" stroke-width=".13"/>
<circle cx="106.4" cy="168.3" r=".51" fill="#000080"/>
<circle cx="106.4" cy="168.3" r=".51" fill="none" stroke="#000080" stroke-width=".13"/>
<circle cx="106.4" cy="165.8" r=".51" fill="#000080"/>
<circle cx="106.4" cy="165.8" r=".51" fill="none" stroke="#000080" stroke-width=".13"/>
<circle cx="106.4" cy="163.3" r=".51" fill="#000080"/>
<circle cx="106.4" cy="163.3" r=".51" fill="none" stroke="#000080" stroke-width=".13"/>
<path d="M114.1 160.7h30.5v15.3h-30.5z" fill-rule="evenodd" fill="#ffffb0"/>
<path d="M114.1 160.7h30.5v15.3h-30.5z" fill="none" stroke="#800000" stroke-width=".13"/>
<path d="M144.6 170.9h7.6M144.6 173.4h7.6" fill="none" stroke="#000" stroke-width=".25"/>
<circle cx="152.2" cy="170.9" r=".51" fill="#000080"/>
<circle cx="152.2" cy="170.9" r=".51" fill="none" stroke="#000080" stroke-width=".13"/>
<path d="M144.6 168.3h7.6" fill="none" stroke="#000" stroke-width=".25"/>
<circle cx="152.2" cy="168.3" r=".51" fill="#000080"/>
<circle cx="152.2" cy="168.3" r=".51" fill="none" stroke="#000080" stroke-width=".13"/>
<path d="M144.6 165.8h7.6" fill="none" stroke="#000" stroke-width=".25"/>
<circle cx="152.2" cy="165.8" r=".51" fill="#000080"/>
<circle cx="152.2" cy="165.8" r=".51" fill="none" stroke="#000080" stroke-width=".13"/>
<path d="M106.4 170.9h7.7M106.4 173.4h7.7" fill="none" stroke="#000" stroke-width=".25"/>
<circle cx="106.4" cy="170.9" r=".51" fill="#000080"/>
<circle cx="106.4" cy="170.9" r=".51" fill="none" stroke="#000080" stroke-width=".13"/>
<path d="M106.4 168.3h7.7" fill="none" stroke="#000" stroke-width=".25"/>
<circle cx="106.4" cy="168.3" r=".51" fill="#000080"/>
<circle cx="106.4" cy="168.3" r=".51" fill="none" stroke="#000080" stroke-width=".13"/>
<path d="M106.4 165.8h7.7" fill="none" stroke="#000" stroke-width=".25"/>
<circle cx="106.4" cy="165.8" r=".51" fill="#000080"/>
<circle cx="106.4" cy="165.8" r=".51" fill="none" stroke="#000080" stroke-width=".13"/>
<path d="M106.4 163.3h7.7" fill="none" stroke="#000" stroke-width=".25"/>
<circle cx="106.4" cy="163.3" r=".51" fill="#000080"/>
<circle cx="106.4" cy="163.3" r=".51" fill="none" stroke="#000080" stroke-width=".13"/>
<circle cx="149.6" cy="61.7" r=".51" fill="#000080"/>
<circle cx="149.6" cy="61.7" r=".51" fill="none" stroke="#000080" stroke-width=".13"/>
<circle cx="149.6" cy="54.1" r=".51" fill="#000080"/>
<circle cx="149.6" cy="54.1" r=".51" fill="none" stroke="#000080" stroke-width=".13"/>
<circle cx="149.6" cy="51.5" r=".51" fill="#000080"/>
<circle cx="149.6" cy="51.5" r=".51" fill="none" stroke="#000080" stroke-width=".13"/>
<circle cx="149.6" cy="49" r=".51" fill="#000080"/>
<circle cx="149.6" cy="49" r=".51" fill="none" stroke="#000080" stroke-width=".13"/>
<circle cx="149.6" cy="46.4" r=".51" fill="#000080"/>
<circle cx="149.6" cy="46.4" r=".51" fill="none" stroke="#000080" stroke-width=".13"/>
<circle cx="149.6" cy="43.9" r=".51" fill="#000080"/>
<circle cx="149.6" cy="43.9" r=".51" fill="none" stroke="#000080" stroke-width=".13"/>
<circle cx="149.6" cy="41.4" r=".51" fill="#000080"/>
<circle cx="149.6" cy="41.4" r=".51" fill="none" stroke="#000080" stroke-width=".13"/>
<circle cx="109" cy="61.7" r=".51" fill="#000080"/>
<circle cx="109" cy="61.7" r=".51" fill="none" stroke="#000080" stroke-width=".13"/>
<circle cx="109" cy="59.1" r=".51" fill="#000080"/>
<circle cx="109" cy="59.1" r=".51" fill="none" stroke="#000080" stroke-width=".13"/>
<circle cx="109" cy="56.6" r=".51" fill="#000080"/>
<circle cx="109" cy="56.6" r=".51" fill="none" stroke="#000080" stroke-width=".13"/>
<circle cx="109" cy="54.1" r=".51" fill="#000080"/>
<circle cx="109" cy="54.1" r=".51" fill="none" stroke="#000080" stroke-width=".13"/>
<circle cx="109" cy="51.5" r=".51" fill="#000080"/>
<circle cx="109" cy="51.5" r=".51" fill="none" stroke="#000080" stroke-width=".13"/>
<circle cx="109" cy="41.4" r=".51" fill="#000080"/>
<circle cx="109" cy="41.4" r=".51" fill="none" stroke="#000080" stroke-width=".13"/>
<circle cx="109" cy="38.8" r=".51" fill="#000080"/>
<circle cx="109" cy="38.8" r=".51" fill="none" stroke="#000080" stroke-width=".13"/>
<circle cx="109" cy="36.3" r=".51" fill="#000080"/>
<circle cx="109" cy="36.3" r=".51" fill="none" stroke="#000080" stroke-width=".13"/>
<circle cx="109" cy="33.7" r=".51" fill="#000080"/>
<circle cx="109" cy="33.7" r=".51" fill="none" stroke="#000080" stroke-width=".13"/>
<circle cx="109" cy="31.2" r=".51" fill="#000080"/>
<circle cx="109" cy="31.2" r=".51" fill="none" stroke="#000080" stroke-width=".13"/>
<path d="M116.6 28.7h25.4v38.1h-25.4z" fill-rule="evenodd" fill="#ffffb0"/>
<path d="M116.6 28.7h25.4v38.1h-25.4z" fill="none" stroke="#800000" stroke-width=".13"/>
<path d="M142 64.2h7.6M142 61.7h7.6" fill="none" stroke="#000" stroke-width=".25"/>
<circle cx="149.6" cy="61.7" r=".51" fill="#000080"/>
<circle cx="149.6" cy="61.7" r=".51" fill="none" stroke="#000080" stroke-width=".13"/>
<path d="M142 56.6h7.6M142 54.1h7.6" fill="none" stroke="#000" stroke-width=".25"/>
<circle cx="149.6" cy="54.1" r=".51" fill="#000080"/>
<circle cx="149.6" cy="54.1" r=".51" fill="none" stroke="#000080" stroke-width=".13"/>
<path d="M142 51.5h7.6" fill="none" stroke="#000" stroke-width=".25"/>
<circle cx="149.6" cy="51.5" r=".51" fill="#000080"/>
<circle cx="149.6" cy="51.5" r=".51" fill="none" stroke="#000080" stroke-width=".13"/>
<path d="M142 49h7.6" fill="none" stroke="#000" stroke-width=".25"/>
<circle cx="149.6" cy="49" r=".51" fill="#000080"/>
<circle cx="149.6" cy="49" r=".51" fill="none" stroke="#000080" stroke-width=".13"/>
<path d="M142 46.4h7.6" fill="none" stroke="#000" stroke-width=".25"/>
<circle cx="149.6" cy="46.4" r=".51" fill="#000080"/>
<circle cx="149.6" cy="46.4" r=".51" fill="none" stroke="#000080" stroke-width=".13"/>
<path d="M142 43.9h7.6" fill="none" stroke="#000" stroke-width=".25"/>
<circle cx="149.6" cy="43.9" r=".51" fill="#000080"/>
<circle cx="149.6" cy="43.9" r=".51" fill="none" stroke="#000080" stroke-width=".13"/>
<path d="M142 41.4h7.6" fill="none" stroke="#000" stroke-width=".25"/>
<circle cx="149.6" cy="41.4" r=".51" fill="#000080"/>
<circle cx="149.6" cy="41.4" r=".51" fill="none" stroke="#000080" stroke-width=".13"/>
<path d="M109 64.2h7.6M109 61.7h7.6" fill="none" stroke="#000" stroke-width=".25"/>
<circle cx="109" cy="61.7" r=".51" fill="#000080"/>
<circle cx="109" cy="61.7" r=".51" fill="none" stroke="#000080" stroke-width=".13"/>
<path d="M109 59.1h7.6" fill="none" stroke="#000" stroke-width=".25"/>
<circle cx="109" cy="59.1" r=".51" fill="#000080"/>
<circle cx="109" cy="59.1" r=".51" fill="none" stroke="#000080" stroke-width=".13"/>
<path d="M109 56.6h7.6" fill="none" stroke="#000" stroke-width=".25"/>
<circle cx="109" cy="56.6" r=".51" fill="#000080"/>
<circle cx="109" cy="56.6" r=".51" fill="none" stroke="#000080" stroke-width=".13"/>
<path d="M109 54.1h7.6" fill="none" stroke="#000" stroke-width=".25"/>
<circle cx="109" cy="54.1" r=".51" fill="#000080"/>
<circle cx="109" cy="54.1" r=".51" fill="none" stroke="#000080" stroke-width=".13"/>
<path d="M109 51.5h7.6" fill="none" stroke="#000" stroke-width=".25"/>
<circle cx="109" cy="51.5" r=".51" fill="#000080"/>
<circle cx="109" cy="51.5" r=".51" fill="none" stroke="#000080" stroke-width=".13"/>
<path d="M109 49h7.6M109 43.9h7.6M109 41.4h7.6" fill="none" stroke="#000" stroke-width=".25"/>
<circle cx="109" cy="41.4" r=".51" fill="#000080"/>
<circle cx="109" cy="41.4" r=".51" fill="none" stroke="#000080" stroke-width=".13"/>
<path d="M109 38.8h7.6" fill="none" stroke="#000" stroke-width=".25"/>
<circle cx="109" cy="38.8" r=".51" fill="#000080"/>
<circle cx="109" cy="38.8" r=".51" fill="none" stroke="#000080" stroke-width=".13"/>
<path d="M109 36.3h7.6" fill="none" stroke="#000" stroke-width=".25"/>
<circle cx="109" cy="36.3" r=".51" fill="#000080"/>
<circle cx="109" cy="36.3" r=".51" fill="none" stroke="#000080" stroke-width=".13"/>
<path d="M109 33.7h7.6" fill="none" stroke="#000" stroke-width=".25"/>
<circle cx="109" cy="33.7" r=".51" fill="#000080"/>
<circle cx="109" cy="33.7" r=".51" fill="none" stroke="#000080" stroke-width=".13"/>
<path d="M109 31.2h7.6" fill="none" stroke="#000" stroke-width=".25"/>
<circle cx="109" cy="31.2" r=".51" fill="#000080"/>
<circle cx="109" cy="31.2" r=".51" fill="none" stroke="#000080" stroke-width=".13"/>
<circle cx="106.4" cy="122.6" r=".51" fill="#000080"/>
<circle cx="106.4" cy="122.6" r=".51" fill="none" stroke="#000080" stroke-width=".13"/>
<circle cx="106.4" cy="120.1" r=".51" fill="#000080"/>
<circle cx="106.4" cy="120.1" r=".51" fill="none" stroke="#000080" stroke-width=".13"/>
<circle cx="106.4" cy="117.5" r=".51" fill="#000080"/>
<circle cx="106.4" cy="117.5" r=".51" fill="none" stroke="#000080" stroke-width=".13"/>
<circle cx="106.4" cy="115" r=".51" fill="#000080"/>
<circle cx="106.4" cy="115" r=".51" fill="none" stroke="#000080" stroke-width=".13"/>
<circle cx="152.2" cy="132.8" r=".51" fill="#000080"/>
<circle cx="152.2" cy="132.8" r=".51" fill="none" stroke="#000080" stroke-width=".13"/>
<circle cx="152.2" cy="130.2" r=".51" fill="#000080"/>
<circle cx="152.2" cy="130.2" r=".51" fill="none" stroke="#000080" stroke-width=".13"/>
<circle cx="152.2" cy="127.7" r=".51" fill="#000080"/>
<circle cx="152.2" cy="127.7" r=".51" fill="none" stroke="#000080" stroke-width=".13"/>
<circle cx="152.2" cy="125.2" r=".51" fill="#000080"/>
<circle cx="152.2" cy="125.2" r=".51" fill="none" stroke="#000080" stroke-width=".13"/>
<circle cx="152.2" cy="122.6" r=".51" fill="#000080"/>
<circle cx="152.2" cy="122.6" r=".51" fill="none" stroke="#000080" stroke-width=".13"/>
<circle cx="152.2" cy="120.1" r=".51" fill="#000080"/>
<circle cx="152.2" cy="120.1" r=".51" fill="none" stroke="#000080" stroke-width=".13"/>
<circle cx="152.2" cy="117.5" r=".51" fill="#000080"/>
<circle cx="152.2" cy="117.5" r=".51" fill="none" stroke="#000080" stroke-width=".13"/>
<circle cx="152.2" cy="115" r=".51" fill="#000080"/>
<circle cx="152.2" cy="115" r=".51" fill="none" stroke="#000080" stroke-width=".13"/>
<circle cx="152.2" cy="112.5" r=".51" fill="#000080"/>
<circle cx="152.2" cy="112.5" r=".51" fill="none" stroke="#000080" stroke-width=".13"/>
<circle cx="152.2" cy="109.9" r=".51" fill="#000080"/>
<circle cx="152.2" cy="109.9" r=".51" fill="none" stroke="#000080" stroke-width=".13"/>
<circle cx="152.2" cy="107.4" r=".51" fill="#000080"/>
<circle cx="152.2" cy="107.4" r=".51" fill="none" stroke="#000080" stroke-width=".13"/>
<circle cx="152.2" cy="104.8" r=".51" fill="#000080"/>
<circle cx="152.2" cy="104.8" r=".51" fill="none" stroke="#000080" stroke-width=".13"/>
<circle cx="152.2" cy="102.3" r=".51" fill="#000080"/>
<circle cx="152.2" cy="102.3" r=".51" fill="none" stroke="#000080" stroke-width=".13"/>
<circle cx="152.2" cy="99.8" r=".51" fill="#000080"/>
<circle cx="152.2" cy="99.8" r=".51" fill="none" stroke="#000080" stroke-width=".13"/>
<circle cx="152.2" cy="97.2" r=".51" fill="#000080"/>
<circle cx="152.2" cy="97.2" r=".51" fill="none" stroke="#000080" stroke-width=".13"/>
<circle cx="152.2" cy="94.7" r=".51" fill="#000080"/>
<circle cx="152.2" cy="94.7" r=".51" fill="none" stroke="#000080" stroke-width=".13"/>
<circle cx="152.2" cy="92.1" r=".51" fill="#000080"/>
<circle cx="152.2" cy="92.1" r=".51" fill="none" stroke="#000080" stroke-width=".13"/>
<circle cx="106.4" cy="107.4" r=".51" fill="#000080"/>
<circle cx="106.4" cy="107.4" r=".51" fill="none" stroke="#000080" stroke-width=".13"/>
<circle cx="106.4" cy="104.8" r=".51" fill="#000080"/>
<circle cx="106.4" cy="104.8" r=".51" fill="none" stroke="#000080" stroke-width=".13"/>
<path d="M114.1 89.6h30.5v48.3h-30.5z" fill-rule="evenodd" fill="#ffffb0"/>
<path d="M114.1 89.6h30.5v48.3h-30.5z" fill="none" stroke="#800000" stroke-width=".13"/>
<path d="M106.4 125.2h7.7M106.4 122.6h7.7" fill="none" stroke="#000" stroke-width=".25"/>
<circle cx="106.4" cy="122.6" r=".51" fill="#000080"/>
<circle cx="106.4" cy="122.6" r=".51" fill="none" stroke="#000080" stroke-width=".13"/>
<path d="M106.4 120.1h7.7" fill="none" stroke="#000" stroke-width=".25"/>
<circle cx="106.4" cy="120.1" r=".51" fill="#000080"/>
<circle cx="106.4" cy="120.1" r=".51" fill="none" stroke="#000080" stroke-width=".13"/>
<path d="M106.4 117.5h7.7" fill="none" stroke="#000" stroke-width=".25"/>
<circle cx="106.4" cy="117.5" r=".51" fill="#000080"/>
<circle cx="106.4" cy="117.5" r=".51" fill="none" stroke="#000080" stroke-width=".13"/>
<path d="M106.4 115h7.7" fill="none" stroke="#000" stroke-width=".25"/>
<circle cx="106.4" cy="115" r=".51" fill="#000080"/>
<circle cx="106.4" cy="115" r=".51" fill="none" stroke="#000080" stroke-width=".13"/>
<path d="M144.6 135.3h7.6M144.6 132.8h7.6" fill="none" stroke="#000" stroke-width=".25"/>
<circle cx="152.2" cy="132.8" r=".51" fill="#000080"/>
<circle cx="152.2" cy="132.8" r=".51" fill="none" stroke="#000080" stroke-width=".13"/>
<path d="M144.6 130.2h7.6" fill="none" stroke="#000" stroke-width=".25"/>
<circle cx="152.2" cy="130.2" r=".51" fill="#000080"/>
<circle cx="152.2" cy="130.2" r=".51" fill="none" stroke="#000080" stroke-width=".13"/>
<path d="M144.6 127.7h7.6" fill="none" stroke="#000" stroke-width=".25"/>
<circle cx="152.2" cy="127.7" r=".51" fill="#000080"/>
<circle cx="152.2" cy="127.7" r=".51" fill="none" stroke="#000080" stroke-width=".13"/>
<path d="M144.6 125.2h7.6" fill="none" stroke="#000" stroke-width=".25"/>
<circle cx="152.2" cy="125.2" r=".51" fill="#000080"/>
<circle cx="152.2" cy="125.2" r=".51" fill="none" stroke="#000080" stroke-width=".13"/>
<path d="M144.6 122.6h7.6" fill="none" stroke="#000" stroke-width=".25"/>
<circle cx="152.2" cy="122.6" r=".51" fill="#000080"/>
<circle cx="152.2" cy="122.6" r=".51" fill="none" stroke="#000080" stroke-width=".13"/>
<path d="M144.6 120.1h7.6" fill="none" stroke="#000" stroke-width=".25"/>
<circle cx="152.2" cy="120.1" r=".51" fill="#000080"/>
<circle cx="152.2" cy="120.1" r=".51" fill="none" stroke="#000080" stroke-width=".13"/>
<path d="M144.6 117.5h7.6" fill="none" stroke="#000" stroke-width=".25"/>
<circle cx="152.2" cy="117.5" r=".51" fill="#000080"/>
<circle cx="152.2" cy="117.5" r=".51" fill="none" stroke="#000080" stroke-width=".13"/>
<path d="M144.6 115h7.6" fill="none" stroke="#000" stroke-width=".25"/>
<circle cx="152.2" cy="115" r=".51" fill="#000080"/>
<circle cx="152.2" cy="115" r=".51" fill="none" stroke="#000080" stroke-width=".13"/>
<path d="M144.6 112.5h7.6" fill="none" stroke="#000" stroke-width=".25"/>
<circle cx="152.2" cy="112.5" r=".51" fill="#000080"/>
<circle cx="152.2" cy="112.5" r=".51" fill="none" stroke="#000080" stroke-width=".13"/>
<path d="M144.6 109.9h7.6" fill="none" stroke="#000" stroke-width=".25"/>
<circle cx="152.2" cy="109.9" r=".51" fill="#000080"/>
<circle cx="152.2" cy="109.9" r=".51" fill="none" stroke="#000080" stroke-width=".13"/>
<path d="M144.6 107.4h7.6" fill="none" stroke="#000" stroke-width=".25"/>
<circle cx="152.2" cy="107.4" r=".51" fill="#000080"/>
<circle cx="152.2" cy="107.4" r=".51" fill="none" stroke="#000080" stroke-width=".13"/>
<path d="M144.6 104.8h7.6" fill="none" stroke="#000" stroke-width=".25"/>
<circle cx="152.2" cy="104.8" r=".51" fill="#000080"/>
<circle cx="152.2" cy="104.8" r=".51" fill="none" stroke="#000080" stroke-width=".13"/>
<path d="M144.6 102.3h7.6" fill="none" stroke="#000" stroke-width=".25"/>
<circle cx="152.2" cy="102.3" r=".51" fill="#000080"/>
<circle cx="152.2" cy="102.3" r=".51" fill="none" stroke="#000080" stroke-width=".13"/>
<path d="M144.6 99.8h7.6" fill="none" stroke="#000" stroke-width=".25"/>
<circle cx="152.2" cy="99.8" r=".51" fill="#000080"/>
<circle cx="152.2" cy="99.8" r=".51" fill="none" stroke="#000080" stroke-width=".13"/>
<path d="M144.6 97.2h7.6" fill="none" stroke="#000" stroke-width=".25"/>
<circle cx="152.2" cy="97.2" r=".51" fill="#000080"/>
<circle cx="152.2" cy="97.2" r=".51" fill="none" stroke="#000080" stroke-width=".13"/>
<path d="M144.6 94.7h7.6" fill="none" stroke="#000" stroke-width=".25"/>
<circle cx="152.2" cy="94.7" r=".51" fill="#000080"/>
<circle cx="152.2" cy="94.7" r=".51" fill="none" stroke="#000080" stroke-width=".13"/>
<path d="M144.6 92.1h7.6" fill="none" stroke="#000" stroke-width=".25"/>
<circle cx="152.2" cy="92.1" r=".51" fill="#000080"/>
<circle cx="152.2" cy="92.1" r=".51" fill="none" stroke="#000080" stroke-width=".13"/>
<path d="M106.4 109.9h7.7M106.4 107.4h7.7" fill="none" stroke="#000" stroke-width=".25"/>
<circle cx="106.4" cy="107.4" r=".51" fill="#000080"/>
<circle cx="106.4" cy="107.4" r=".51" fill="none" stroke="#000080" stroke-width=".13"/>
<path d="M106.4 104.8h7.7" fill="none" stroke="#000" stroke-width=".25"/>
<circle cx="106.4" cy="104.8" r=".51" fill="#000080"/>
<circle cx="106.4" cy="104.8" r=".51" fill="none" stroke="#000080" stroke-width=".13"/>
<path d="M101.3 117.5v4.5M101.3 123.3v4.4M106.4 130.2h7.7M106.4 135.3h7.7" fill="none" stroke="#000" stroke-width=".25"/>
<g fill="none" stroke="#800000" stroke-width=".25">
<path d="M13.7 26.1h2.5M14.9 26.1v2.6M229.7 26.1h2.5M231 26.1v2.6M13.7 54.1h2.5M14.9 54.1v2.5M166.2 56.6h2.5M167.4 56.6v2.5M77.2 87.1h2.5M78.5 87.1v2.5M229.7 87.1h2.5M231 87.1v2.5"/>
<path d="M13.7 109.9h2.5M14.9 109.9v2.6M64.5 158.2h2.5M65.8 158.2v2.5M191.6 160.7h2.5M192.8 160.7v2.6"/>
</g>
<path d="M100.1 121.4l2.5 1.2v1.3l-2.5-1.3z" fill="none" stroke="#00f" stroke-width=".25"/>
<circle cx="281.8" cy="160.7" r=".51" fill="#000080"/>
<circle cx="281.8" cy="160.7" r=".51" fill="none" stroke="#000080" stroke-width=".13"/>
<circle cx="281.8" cy="158.2" r=".51" fill="#000080"/>
<circle cx="281.8" cy="158.2" r=".51" fill="none" stroke="#000080" stroke-width=".13"/>
<circle cx="281.8" cy="155.6" r=".51" fill="#000080"/>
<circle cx="281.8" cy="155.6" r=".51" fill="none" stroke="#000080" stroke-width=".13"/>
<circle cx="281.8" cy="153.1" r=".51" fill="#000080"/>
<circle cx="281.8" cy="153.1" r=".51" fill="none" stroke="#000080" stroke-width=".13"/>
<circle cx="281.8" cy="150.6" r=".51" fill="#000080"/>
<circle cx="281.8" cy="150.6" r=".51" fill="none" stroke="#000080" stroke-width=".13"/>
<circle cx="281.8" cy="148" r=".51" fill="#000080"/>
<circle cx="281.8" cy="148" r=".51" fill="none" stroke="#000080" stroke-width=".13"/>
<circle cx="281.8" cy="145.5" r=".51" fill="#000080"/>
<circle cx="281.8" cy="145.5" r=".51" fill="none" stroke="#000080" stroke-width=".13"/>
<circle cx="281.8" cy="142.9" r=".51" fill="#000080"/>
<circle cx="281.8" cy="142.9" r=".51" fill="none" stroke="#000080" stroke-width=".13"/>
<circle cx="281.8" cy="140.4" r=".51" fill="#000080"/>
<circle cx="281.8" cy="140.4" r=".51" fill="none" stroke="#000080" stroke-width=".13"/>
<circle cx="281.8" cy="137.9" r=".51" fill="#000080"/>
<circle cx="281.8" cy="137.9" r=".51" fill="none" stroke="#000080" stroke-width=".13"/>
<circle cx="281.8" cy="135.3" r=".51" fill="#000080"/>
<circle cx="281.8" cy="135.3" r=".51" fill="none" stroke="#000080" stroke-width=".13"/>
<circle cx="281.8" cy="132.8" r=".51" fill="#000080"/>
<circle cx="281.8" cy="132.8" r=".51" fill="none" stroke="#000080" stroke-width=".13"/>
<circle cx="281.8" cy="130.2" r=".51" fill="#000080"/>
<circle cx="281.8" cy="130.2" r=".51" fill="none" stroke="#000080" stroke-width=".13"/>
<circle cx="281.8" cy="127.7" r=".51" fill="#000080"/>
<circle cx="281.8" cy="127.7" r=".51" fill="none" stroke="#000080" stroke-width=".13"/>
<circle cx="281.8" cy="125.2" r=".51" fill="#000080"/>
<circle cx="281.8" cy="125.2" r=".51" fill="none" stroke="#000080" stroke-width=".13"/>
<circle cx="281.8" cy="122.6" r=".51" fill="#000080"/>
<circle cx="281.8" cy="122.6" r=".51" fill="none" stroke="#000080" stroke-width=".13"/>
<circle cx="281.8" cy="120.1" r=".51" fill="#000080"/>
<circle cx="281.8" cy="120.1" r=".51" fill="none" stroke="#000080" stroke-width=".13"/>
<circle cx="281.8" cy="117.5" r=".51" fill="#000080"/>
<circle cx="281.8" cy="117.5" r=".51" fill="none" stroke="#000080" stroke-width=".13"/>
<circle cx="281.8" cy="115" r=".51" fill="#000080"/>
<circle cx="281.8" cy="115" r=".51" fill="none" stroke="#000080" stroke-width=".13"/>
<circle cx="281.8" cy="112.5" r=".51" fill="#000080"/>
<circle cx="281.8" cy="112.5" r=".51" fill="none" stroke="#000080" stroke-width=".13"/>
<circle cx="281.8" cy="109.9" r=".51" fill="#000080"/>
<circle cx="281.8" cy="109.9" r=".51" fill="none" stroke="#000080" stroke-width=".13"/>
<circle cx="281.8" cy="107.4" r=".51" fill="#000080"/>
<circle cx="281.8" cy="107.4" r=".51" fill="none" stroke="#000080" stroke-width=".13"/>
<circle cx="281.8" cy="104.9" r=".51" fill="#000080"/>
<circle cx="281.8" cy="104.9" r=".51" fill="none" stroke="#000080" stroke-width=".13"/>
<circle cx="281.8" cy="102.3" r=".51" fill="#000080"/>
<circle cx="281.8" cy="102.3" r=".51" fill="none" stroke="#000080" stroke-width=".13"/>
<circle cx="281.8" cy="99.8" r=".51" fill="#000080"/>
<circle cx="281.8" cy="99.8" r=".51" fill="none" stroke="#000080" stroke-width=".13"/>
<circle cx="281.8" cy="97.2" r=".51" fill="#000080"/>
<circle cx="281.8" cy="97.2" r=".51" fill="none" stroke="#000080" stroke-width=".13"/>
<circle cx="281.8" cy="94.7" r=".51" fill="#000080"/>
<circle cx="281.8" cy="94.7" r=".51" fill="none" stroke="#000080" stroke-width=".13"/>
<circle cx="281.8" cy="92.2" r=".51" fill="#000080"/>
<circle cx="281.8" cy="92.2" r=".51" fill="none" stroke="#000080" stroke-width=".13"/>
<circle cx="281.8" cy="89.6" r=".51" fill="#000080"/>
<circle cx="281.8" cy="89.6" r=".51" fill="none" stroke="#000080" stroke-width=".13"/>
<circle cx="281.8" cy="87.1" r=".51" fill="#000080"/>
<circle cx="281.8" cy="87.1" r=".51" fill="none" stroke="#000080" stroke-width=".13"/>
<circle cx="281.8" cy="84.5" r=".51" fill="#000080"/>
<circle cx="281.8" cy="84.5" r=".51" fill="none" stroke="#000080" stroke-width=".13"/>
<circle cx="281.8" cy="82" r=".51" fill="#000080"/>
<circle cx="281.8" cy="82" r=".51" fill="none" stroke="#000080" stroke-width=".13"/>
<circle cx="281.8" cy="79.5" r=".51" fill="#000080"/>
<circle cx="281.8" cy="79.5" r=".51" fill="none" stroke="#000080" stroke-width=".13"/>
<circle cx="281.8" cy="76.9" r=".51" fill="#000080"/>
<circle cx="281.8" cy="76.9" r=".51" fill="none" stroke="#000080" stroke-width=".13"/>
<circle cx="281.8" cy="74.4" r=".51" fill="#000080"/>
<circle cx="281.8" cy="74.4" r=".51" fill="none" stroke="#000080" stroke-width=".13"/>
<circle cx="281.8" cy="71.8" r=".51" fill="#000080"/>
<circle cx="281.8" cy="71.8" r=".51" fill="none" stroke="#000080" stroke-width=".13"/>
<circle cx="281.8" cy="69.3" r=".51" fill="#000080"/>
<circle cx="281.8" cy="69.3" r=".51" fill="none" stroke="#000080" stroke-width=".13"/>
<circle cx="246.2" cy="160.7" r=".51" fill="#000080"/>
<circle cx="246.2" cy="160.7" r=".51" fill="none" stroke="#000080" stroke-width=".13"/>
<circle cx="246.2" cy="158.2" r=".51" fill="#000080"/>
<circle cx="246.2" cy="158.2" r=".51" fill="none" stroke="#000080" stroke-width=".13"/>
<circle cx="246.2" cy="155.6" r=".51" fill="#000080"/>
<circle cx="246.2" cy="155.6" r=".51" fill="none" stroke="#000080" stroke-width=".13"/>
<circle cx="246.2" cy="153.1" r=".51" fill="#000080"/>
<circle cx="246.2" cy="153.1" r=".51" fill="none" stroke="#000080" stroke-width=".13"/>
<circle cx="246.2" cy="150.6" r=".51" fill="#000080"/>
<circle cx="246.2" cy="150.6" r=".51" fill="none" stroke="#000080" stroke-width=".13"/>
<circle cx="246.2" cy="148" r=".51" fill="#000080"/>
<circle cx="246.2" cy="148" r=".51" fill="none" stroke="#000080" stroke-width=".13"/>
<circle cx="246.2" cy="145.5" r=".51" fill="#000080"/>
<circle cx="246.2" cy="145.5" r=".51" fill="none" stroke="#000080" stroke-width=".13"/>
<circle cx="246.2" cy="142.9" r=".51" fill="#000080"/>
<circle cx="246.2" cy="142.9" r=".51" fill="none" stroke="#000080" stroke-width=".13"/>
<circle cx="246.2" cy="140.4" r=".51" fill="#000080"/>
<circle cx="246.2" cy="140.4" r=".51" fill="none" stroke="#000080" stroke-width=".13"/>
<circle cx="246.2" cy="137.9" r=".51" fill="#000080"/>
<circle cx="246.2" cy="137.9" r=".51" fill="none" stroke="#000080" stroke-width=".13"/>
<circle cx="246.2" cy="135.3" r=".51" fill="#000080"/>
<circle cx="246.2" cy="135.3" r=".51" fill="none" stroke="#000080" stroke-width=".13"/>
<circle cx="246.2" cy="132.8" r=".51" fill="#000080"/>
<circle cx="246.2" cy="132.8" r=".51" fill="none" stroke="#000080" stroke-width=".13"/>
<circle cx="246.2" cy="130.2" r=".51" fill="#000080"/>
<circle cx="246.2" cy="130.2" r=".51" fill="none" stroke="#000080" stroke-width=".13"/>
<circle cx="246.2" cy="127.7" r=".51" fill="#000080"/>
<circle cx="246.2" cy="127.7" r=".51" fill="none" stroke="#000080" stroke-width=".13"/>
<circle cx="246.2" cy="125.2" r=".51" fill="#000080"/>
<circle cx="246.2" cy="125.2" r=".51" fill="none" stroke="#000080" stroke-width=".13"/>
<circle cx="246.2" cy="122.6" r=".51" fill="#000080"/>
<circle cx="246.2" cy="122.6" r=".51" fill="none" stroke="#000080" stroke-width=".13"/>
<circle cx="246.2" cy="120.1" r=".51" fill="#000080"/>
<circle cx="246.2" cy="120.1" r=".51" fill="none" stroke="#000080" stroke-width=".13"/>
<circle cx="246.2" cy="117.5" r=".51" fill="#000080"/>
<circle cx="246.2" cy="117.5" r=".51" fill="none" stroke="#000080" stroke-width=".13"/>
<circle cx="246.2" cy="115" r=".51" fill="#000080"/>
<circle cx="246.2" cy="115" r=".51" fill="none" stroke="#000080" stroke-width=".13"/>
<circle cx="246.2" cy="112.5" r=".51" fill="#000080"/>
<circle cx="246.2" cy="112.5" r=".51" fill="none" stroke="#000080" stroke-width=".13"/>
<circle cx="246.2" cy="109.9" r=".51" fill="#000080"/>
<circle cx="246.2" cy="109.9" r=".51" fill="none" stroke="#000080" stroke-width=".13"/>
<circle cx="246.2" cy="107.4" r=".51" fill="#000080"/>
<circle cx="246.2" cy="107.4" r=".51" fill="none" stroke="#000080" stroke-width=".13"/>
<circle cx="246.2" cy="104.9" r=".51" fill="#000080"/>
<circle cx="246.2" cy="104.9" r=".51" fill="none" stroke="#000080" stroke-width=".13"/>
<circle cx="246.2" cy="102.3" r=".51" fill="#000080"/>
<circle cx="246.2" cy="102.3" r=".51" fill="none" stroke="#000080" stroke-width=".13"/>
<circle cx="246.2" cy="99.8" r=".51" fill="#000080"/>
<circle cx="246.2" cy="99.8" r=".51" fill="none" stroke="#000080" stroke-width=".13"/>
<circle cx="246.2" cy="97.2" r=".51" fill="#000080"/>
<circle cx="246.2" cy="97.2" r=".51" fill="none" stroke="#000080" stroke-width=".13"/>
<circle cx="246.2" cy="94.7" r=".51" fill="#000080"/>
<circle cx="246.2" cy="94.7" r=".51" fill="none" stroke="#000080" stroke-width=".13"/>
<circle cx="246.2" cy="92.2" r=".51" fill="#000080"/>
<circle cx="246.2" cy="92.2" r=".51" fill="none" stroke="#000080" stroke-width=".13"/>
<circle cx="246.2" cy="89.6" r=".51" fill="#000080"/>
<circle cx="246.2" cy="89.6" r=".51" fill="none" stroke="#000080" stroke-width=".13"/>
<circle cx="246.2" cy="87.1" r=".51" fill="#000080"/>
<circle cx="246.2" cy="87.1" r=".51" fill="none" stroke="#000080" stroke-width=".13"/>
<circle cx="246.2" cy="84.5" r=".51" fill="#000080"/>
<circle cx="246.2" cy="84.5" r=".51" fill="none" stroke="#000080" stroke-width=".13"/>
<circle cx="246.2" cy="82" r=".51" fill="#000080"/>
<circle cx="246.2" cy="82" r=".51" fill="none" stroke="#000080" stroke-width=".13"/>
<circle cx="246.2" cy="79.5" r=".51" fill="#000080"/>
<circle cx="246.2" cy="79.5" r=".51" fill="none" stroke="#000080" stroke-width=".13"/>
<circle cx="246.2" cy="76.9" r=".51" fill="#000080"/>
<circle cx="246.2" cy="76.9" r=".51" fill="none" stroke="#000080" stroke-width=".13"/>
<circle cx="246.2" cy="74.4" r=".51" fill="#000080"/>
<circle cx="246.2" cy="74.4" r=".51" fill="none" stroke="#000080" stroke-width=".13"/>
<circle cx="246.2" cy="71.8" r=".51" fill="#000080"/>
<circle cx="246.2" cy="71.8" r=".51" fill="none" stroke="#000080" stroke-width=".13"/>
<path d="M253.8 61.7h20.4v101.6h-20.4z" fill-rule="evenodd" fill="#ffffb0"/>
<path d="M253.8 61.7h20.4v101.6h-20.4z" fill="none" stroke="#800000" stroke-width=".13"/>
<path d="M274.2 160.7h7.6" fill="none" stroke="#000" stroke-width=".25"/>
<circle cx="281.8" cy="160.7" r=".51" fill="#000080"/>
<circle cx="281.8" cy="160.7" r=".51" fill="none" stroke="#000080" stroke-width=".13"/>
<path d="M274.2 158.2h7.6" fill="none" stroke="#000" stroke-width=".25"/>
<circle cx="281.8" cy="158.2" r=".51" fill="#000080"/>
<circle cx="281.8" cy="158.2" r=".51" fill="none" stroke="#000080" stroke-width=".13"/>
<path d="M274.2 155.6h7.6" fill="none" stroke="#000" stroke-width=".25"/>
<circle cx="281.8" cy="155.6" r=".51" fill="#000080"/>
<circle cx="281.8" cy="155.6" r=".51" fill="none" stroke="#000080" stroke-width=".13"/>
<path d="M274.2 153.1h7.6" fill="none" stroke="#000" stroke-width=".25"/>
<circle cx="281.8" cy="153.1" r=".51" fill="#000080"/>
<circle cx="281.8" cy="153.1" r=".51" fill="none" stroke="#000080" stroke-width=".13"/>
<path d="M274.2 150.6h7.6" fill="none" stroke="#000" stroke-width=".25"/>
<circle cx="281.8" cy="150.6" r=".51" fill="#000080"/>
<circle cx="281.8" cy="150.6" r=".51" fill="none" stroke="#000080" stroke-width=".13"/>
<path d="M274.2 148h7.6" fill="none" stroke="#000" stroke-width=".25"/>
<circle cx="281.8" cy="148" r=".51" fill="#000080"/>
<circle cx="281.8" cy="148" r=".51" fill="none" stroke="#000080" stroke-width=".13"/>
<path d="M274.2 145.5h7.6" fill="none" stroke="#000" stroke-width=".25"/>
<circle cx="281.8" cy="145.5" r=".51" fill="#000080"/>
<circle cx="281.8" cy="145.5" r=".51" fill="none" stroke="#000080" stroke-width=".13"/>
<path d="M274.2 142.9h7.6" fill="none" stroke="#000" stroke-width=".25"/>
<circle cx="281.8" cy="142.9" r=".51" fill="#000080"/>
<circle cx="281.8" cy="142.9" r=".51" fill="none" stroke="#000080" stroke-width=".13"/>
<path d="M274.2 140.4h7.6" fill="none" stroke="#000" stroke-width=".25"/>
<circle cx="281.8" cy="140.4" r=".51" fill="#000080"/>
<circle cx="281.8" cy="140.4" r=".51" fill="none" stroke="#000080" stroke-width=".13"/>
<path d="M274.2 137.9h7.6" fill="none" stroke="#000" stroke-width=".25"/>
<circle cx="281.8" cy="137.9" r=".51" fill="#000080"/>
<circle cx="281.8" cy="137.9" r=".51" fill="none" stroke="#000080" stroke-width=".13"/>
<path d="M274.2 135.3h7.6" fill="none" stroke="#000" stroke-width=".25"/>
<circle cx="281.8" cy="135.3" r=".51" fill="#000080"/>
<circle cx="281.8" cy="135.3" r=".51" fill="none" stroke="#000080" stroke-width=".13"/>
<path d="M274.2 132.8h7.6" fill="none" stroke="#000" stroke-width=".25"/>
<circle cx="281.8" cy="132.8" r=".51" fill="#000080"/>
<circle cx="281.8" cy="132.8" r=".51" fill="none" stroke="#000080" stroke-width=".13"/>
<path d="M274.2 130.2h7.6" fill="none" stroke="#000" stroke-width=".25"/>
<circle cx="281.8" cy="130.2" r=".51" fill="#000080"/>
<circle cx="281.8" cy="130.2" r=".51" fill="none" stroke="#000080" stroke-width=".13"/>
<path d="M274.2 127.7h7.6" fill="none" stroke="#000" stroke-width=".25"/>
<circle cx="281.8" cy="127.7" r=".51" fill="#000080"/>
<circle cx="281.8" cy="127.7" r=".51" fill="none" stroke="#000080" stroke-width=".13"/>
<path d="M274.2 125.2h7.6" fill="none" stroke="#000" stroke-width=".25"/>
<circle cx="281.8" cy="125.2" r=".51" fill="#000080"/>
<circle cx="281.8" cy="125.2" r=".51" fill="none" stroke="#000080" stroke-width=".13"/>
<path d="M274.2 122.6h7.6" fill="none" stroke="#000" stroke-width=".25"/>
<circle cx="281.8" cy="122.6" r=".51" fill="#000080"/>
<circle cx="281.8" cy="122.6" r=".51" fill="none" stroke="#000080" stroke-width=".13"/>
<path d="M274.2 120.1h7.6" fill="none" stroke="#000" stroke-width=".25"/>
<circle cx="281.8" cy="120.1" r=".51" fill="#000080"/>
<circle cx="281.8" cy="120.1" r=".51" fill="none" stroke="#000080" stroke-width=".13"/>
<path d="M274.2 117.5h7.6" fill="none" stroke="#000" stroke-width=".25"/>
<circle cx="281.8" cy="117.5" r=".51" fill="#000080"/>
<circle cx="281.8" cy="117.5" r=".51" fill="none" stroke="#000080" stroke-width=".13"/>
<path d="M274.2 115h7.6" fill="none" stroke="#000" stroke-width=".25"/>
<circle cx="281.8" cy="115" r=".51" fill="#000080"/>
<circle cx="281.8" cy="115" r=".51" fill="none" stroke="#000080" stroke-width=".13"/>
<path d="M274.2 112.5h7.6" fill="none" stroke="#000" stroke-width=".25"/>
<circle cx="281.8" cy="112.5" r=".51" fill="#000080"/>
<circle cx="281.8" cy="112.5" r=".51" fill="none" stroke="#000080" stroke-width=".13"/>
<path d="M274.2 109.9h7.6" fill="none" stroke="#000" stroke-width=".25"/>
<circle cx="281.8" cy="109.9" r=".51" fill="#000080"/>
<circle cx="281.8" cy="109.9" r=".51" fill="none" stroke="#000080" stroke-width=".13"/>
<path d="M274.2 107.4h7.6" fill="none" stroke="#000" stroke-width=".25"/>
<circle cx="281.8" cy="107.4" r=".51" fill="#000080"/>
<circle cx="281.8" cy="107.4" r=".51" fill="none" stroke="#000080" stroke-width=".13"/>
<path d="M274.2 104.9h7.6" fill="none" stroke="#000" stroke-width=".25"/>
<circle cx="281.8" cy="104.9" r=".51" fill="#000080"/>
<circle cx="281.8" cy="104.9" r=".51" fill="none" stroke="#000080" stroke-width=".13"/>
<path d="M274.2 102.3h7.6" fill="none" stroke="#000" stroke-width=".25"/>
<circle cx="281.8" cy="102.3" r=".51" fill="#000080"/>
<circle cx="281.8" cy="102.3" r=".51" fill="none" stroke="#000080" stroke-width=".13"/>
<path d="M274.2 99.8h7.6" fill="none" stroke="#000" stroke-width=".25"/>
<circle cx="281.8" cy="99.8" r=".51" fill="#000080"/>
<circle cx="281.8" cy="99.8" r=".51" fill="none" stroke="#000080" stroke-width=".13"/>
<path d="M274.2 97.2h7.6" fill="none" stroke="#000" stroke-width=".25"/>
<circle cx="281.8" cy="97.2" r=".51" fill="#000080"/>
<circle cx="281.8" cy="97.2" r=".51" fill="none" stroke="#000080" stroke-width=".13"/>
<path d="M274.2 94.7h7.6" fill="none" stroke="#000" stroke-width=".25"/>
<circle cx="281.8" cy="94.7" r=".51" fill="#000080"/>
<circle cx="281.8" cy="94.7" r=".51" fill="none" stroke="#000080" stroke-width=".13"/>
<path d="M274.2 92.2h7.6" fill="none" stroke="#000" stroke-width=".25"/>
<circle cx="281.8" cy="92.2" r=".51" fill="#000080"/>
<circle cx="281.8" cy="92.2" r=".51" fill="none" stroke="#000080" stroke-width=".13"/>
<path d="M274.2 89.6h7.6" fill="none" stroke="#000" stroke-width=".25"/>
<circle cx="281.8" cy="89.6" r=".51" fill="#000080"/>
<circle cx="281.8" cy="89.6" r=".51" fill="none" stroke="#000080" stroke-width=".13"/>
<path d="M274.2 87.1h7.6" fill="none" stroke="#000" stroke-width=".25"/>
<circle cx="281.8" cy="87.1" r=".51" fill="#000080"/>
<circle cx="281.8" cy="87.1" r=".51" fill="none" stroke="#000080" stroke-width=".13"/>
<path d="M274.2 84.5h7.6" fill="none" stroke="#000" stroke-width=".25"/>
<circle cx="281.8" cy="84.5" r=".51" fill="#000080"/>
<circle cx="281.8" cy="84.5" r=".51" fill="none" stroke="#000080" stroke-width=".13"/>
<path d="M274.2 82h7.6" fill="none" stroke="#000" stroke-width=".25"/>
<circle cx="281.8" cy="82" r=".51" fill="#000080"/>
<circle cx="281.8" cy="82" r=".51" fill="none" stroke="#000080" stroke-width=".13"/>
<path d="M274.2 79.5h7.6" fill="none" stroke="#000" stroke-width=".25"/>
<circle cx="281.8" cy="79.5" r=".51" fill="#000080"/>
<circle cx="281.8" cy="79.5" r=".51" fill="none" stroke="#000080" stroke-width=".13"/>
<path d="M274.2 76.9h7.6" fill="none" stroke="#000" stroke-width=".25"/>
<circle cx="281.8" cy="76.9" r=".51" fill="#000080"/>
<circle cx="281.8" cy="76.9" r=".51" fill="none" stroke="#000080" stroke-width=".13"/>
<path d="M274.2 74.4h7.6" fill="none" stroke="#000" stroke-width=".25"/>
<circle cx="281.8" cy="74.4" r=".51" fill="#000080"/>
<circle cx="281.8" cy="74.4" r=".51" fill="none" stroke="#000080" stroke-width=".13"/>
<path d="M274.2 71.8h7.6" fill="none" stroke="#000" stroke-width=".25"/>
<circle cx="281.8" cy="71.8" r=".51" fill="#000080"/>
<circle cx="281.8" cy="71.8" r=".51" fill="none" stroke="#000080" stroke-width=".13"/>
<path d="M274.2 69.3h7.6" fill="none" stroke="#000" stroke-width=".25"/>
<circle cx="281.8" cy="69.3" r=".51" fill="#000080"/>
<circle cx="281.8" cy="69.3" r=".51" fill="none" stroke="#000080" stroke-width=".13"/>
<path d="M274.2 66.8h7.6M246.2 160.7h7.6" fill="none" stroke="#000" stroke-width=".25"/>
<circle cx="246.2" cy="160.7" r=".51" fill="#000080"/>
<circle cx="246.2" cy="160.7" r=".51" fill="none" stroke="#000080" stroke-width=".13"/>
<path d="M246.2 158.2h7.6" fill="none" stroke="#000" stroke-width=".25"/>
<circle cx="246.2" cy="158.2" r=".51" fill="#000080"/>
<circle cx="246.2" cy="158.2" r=".51" fill="none" stroke="#000080" stroke-width=".13"/>
<path d="M246.2 155.6h7.6" fill="none" stroke="#000" stroke-width=".25"/>
<circle cx="246.2" cy="155.6" r=".51" fill="#000080"/>
<circle cx="246.2" cy="155.6" r=".51" fill="none" stroke="#000080" stroke-width=".13"/>
<path d="M246.2 153.1h7.6" fill="none" stroke="#000" stroke-width=".25"/>
<circle cx="246.2" cy="153.1" r=".51" fill="#000080"/>
<circle cx="246.2" cy="153.1" r=".51" fill="none" stroke="#000080" stroke-width=".13"/>
<path d="M246.2 150.6h7.6" fill="none" stroke="#000" stroke-width=".25"/>
<circle cx="246.2" cy="150.6" r=".51" fill="#000080"/>
<circle cx="246.2" cy="150.6" r=".51" fill="none" stroke="#000080" stroke-width=".13"/>
<path d="M246.2 148h7.6" fill="none" stroke="#000" stroke-width=".25"/>
<circle cx="246.2" cy="148" r=".51" fill="#000080"/>
<circle cx="246.2" cy="148" r=".51" fill="none" stroke="#000080" stroke-width=".13"/>
<path d="M246.2 145.5h7.6" fill="none" stroke="#000" stroke-width=".25"/>
<circle cx="246.2" cy="145.5" r=".51" fill="#000080"/>
<circle cx="246.2" cy="145.5" r=".51" fill="none" stroke="#000080" stroke-width=".13"/>
<path d="M246.2 142.9h7.6" fill="none" stroke="#000" stroke-width=".25"/>
<circle cx="246.2" cy="142.9" r=".51" fill="#000080"/>
<circle cx="246.2" cy="142.9" r=".51" fill="none" stroke="#000080" stroke-width=".13"/>
<path d="M246.2 140.4h7.6" fill="none" stroke="#000" stroke-width=".25"/>
<circle cx="246.2" cy="140.4" r=".51" fill="#000080"/>
<circle cx="246.2" cy="140.4" r=".51" fill="none" stroke="#000080" stroke-width=".13"/>
<path d="M246.2 137.9h7.6" fill="none" stroke="#000" stroke-width=".25"/>
<circle cx="246.2" cy="137.9" r=".51" fill="#000080"/>
<circle cx="246.2" cy="137.9" r=".51" fill="none" stroke="#000080" stroke-width=".13"/>
<path d="M246.2 135.3h7.6" fill="none" stroke="#000" stroke-width=".25"/>
<circle cx="246.2" cy="135.3" r=".51" fill="#000080"/>
<circle cx="246.2" cy="135.3" r=".51" fill="none" stroke="#000080" stroke-width=".13"/>
<path d="M246.2 132.8h7.6" fill="none" stroke="#000" stroke-width=".25"/>
<circle cx="246.2" cy="132.8" r=".51" fill="#000080"/>
<circle cx="246.2" cy="132.8" r=".51" fill="none" stroke="#000080" stroke-width=".13"/>
<path d="M246.2 130.2h7.6" fill="none" stroke="#000" stroke-width=".25"/>
<circle cx="246.2" cy="130.2" r=".51" fill="#000080"/>
<circle cx="246.2" cy="130.2" r=".51" fill="none" stroke="#000080" stroke-width=".13"/>
<path d="M246.2 127.7h7.6" fill="none" stroke="#000" stroke-width=".25"/>
<circle cx="246.2" cy="127.7" r=".51" fill="#000080"/>
<circle cx="246.2" cy="127.7" r=".51" fill="none" stroke="#000080" stroke-width=".13"/>
<path d="M246.2 125.2h7.6" fill="none" stroke="#000" stroke-width=".25"/>
<circle cx="246.2" cy="125.2" r=".51" fill="#000080"/>
<circle cx="246.2" cy="125.2" r=".51" fill="none" stroke="#000080" stroke-width=".13"/>
<path d="M246.2 122.6h7.6" fill="none" stroke="#000" stroke-width=".25"/>
<circle cx="246.2" cy="122.6" r=".51" fill="#000080"/>
<circle cx="246.2" cy="122.6" r=".51" fill="none" stroke="#000080" stroke-width=".13"/>
<path d="M246.2 120.1h7.6" fill="none" stroke="#000" stroke-width=".25"/>
<circle cx="246.2" cy="120.1" r=".51" fill="#000080"/>
<circle cx="246.2" cy="120.1" r=".51" fill="none" stroke="#000080" stroke-width=".13"/>
<path d="M246.2 117.5h7.6" fill="none" stroke="#000" stroke-width=".25"/>
<circle cx="246.2" cy="117.5" r=".51" fill="#000080"/>
<circle cx="246.2" cy="117.5" r=".51" fill="none" stroke="#000080" stroke-width=".13"/>
<path d="M246.2 115h7.6" fill="none" stroke="#000" stroke-width=".25"/>
<circle cx="246.2" cy="115" r=".51" fill="#000080"/>
<circle cx="246.2" cy="115" r=".51" fill="none" stroke="#000080" stroke-width=".13"/>
<path d="M246.2 112.5h7.6" fill="none" stroke="#000" stroke-width=".25"/>
<circle cx="246.2" cy="112.5" r=".51" fill="#000080"/>
<circle cx="246.2" cy="112.5" r=".51" fill="none" stroke="#000080" stroke-width=".13"/>
<path d="M246.2 109.9h7.6" fill="none" stroke="#000" stroke-width=".25"/>
<circle cx="246.2" cy="109.9" r=".51" fill="#000080"/>
<circle cx="246.2" cy="109.9" r=".51" fill="none" stroke="#000080" stroke-width=".13"/>
<path d="M246.2 107.4h7.6" fill="none" stroke="#000" stroke-width=".25"/>
<circle cx="246.2" cy="107.4" r=".51" fill="#000080"/>
<circle cx="246.2" cy="107.4" r=".51" fill="none" stroke="#000080" stroke-width=".13"/>
<path d="M246.2 104.9h7.6" fill="none" stroke="#000" stroke-width=".25"/>
<circle cx="246.2" cy="104.9" r=".51" fill="#000080"/>
<circle cx="246.2" cy="104.9" r=".51" fill="none" stroke="#000080" stroke-width=".13"/>
<path d="M246.2 102.3h7.6" fill="none" stroke="#000" stroke-width=".25"/>
<circle cx="246.2" cy="102.3" r=".51" fill="#000080"/>
<circle cx="246.2" cy="102.3" r=".51" fill="none" stroke="#000080" stroke-width=".13"/>
<path d="M246.2 99.8h7.6" fill="none" stroke="#000" stroke-width=".25"/>
<circle cx="246.2" cy="99.8" r=".51" fill="#000080"/>
<circle cx="246.2" cy="99.8" r=".51" fill="none" stroke="#000080" stroke-width=".13"/>
<path d="M246.2 97.2h7.6" fill="none" stroke="#000" stroke-width=".25"/>
<circle cx="246.2" cy="97.2" r=".51" fill="#000080"/>
<circle cx="246.2" cy="97.2" r=".51" fill="none" stroke="#000080" stroke-width=".13"/>
<path d="M246.2 94.7h7.6" fill="none" stroke="#000" stroke-width=".25"/>
<circle cx="246.2" cy="94.7" r=".51" fill="#000080"/>
<circle cx="246.2" cy="94.7" r=".51" fill="none" stroke="#000080" stroke-width=".13"/>
<path d="M246.2 92.2h7.6" fill="none" stroke="#000" stroke-width=".25"/>
<circle cx="246.2" cy="92.2" r=".51" fill="#000080"/>
<circle cx="246.2" cy="92.2" r=".51" fill="none" stroke="#000080" stroke-width=".13"/>
<path d="M246.2 89.6h7.6" fill="none" stroke="#000" stroke-width=".25"/>
<circle cx="246.2" cy="89.6" r=".51" fill="#000080"/>
<circle cx="246.2" cy="89.6" r=".51" fill="none" stroke="#000080" stroke-width=".13"/>
<path d="M246.2 87.1h7.6" fill="none" stroke="#000" stroke-width=".25"/>
<circle cx="246.2" cy="87.1" r=".51" fill="#000080"/>
<circle cx="246.2" cy="87.1" r=".51" fill="none" stroke="#000080" stroke-width=".13"/>
<path d="M246.2 84.5h7.6" fill="none" stroke="#000" stroke-width=".25"/>
<circle cx="246.2" cy="84.5" r=".51" fill="#000080"/>
<circle cx="246.2" cy="84.5" r=".51" fill="none" stroke="#000080" stroke-width=".13"/>
<path d="M246.2 82h7.6" fill="none" stroke="#000" stroke-width=".25"/>
<circle cx="246.2" cy="82" r=".51" fill="#000080"/>
<circle cx="246.2" cy="82" r=".51" fill="none" stroke="#000080" stroke-width=".13"/>
<path d="M246.2 79.5h7.6" fill="none" stroke="#000" stroke-width=".25"/>
<circle cx="246.2" cy="79.5" r=".51" fill="#000080"/>
<circle cx="246.2" cy="79.5" r=".51" fill="none" stroke="#000080" stroke-width=".13"/>
<path d="M246.2 76.9h7.6" fill="none" stroke="#000" stroke-width=".25"/>
<circle cx="246.2" cy="76.9" r=".51" fill="#000080"/>
<circle cx="246.2" cy="76.9" r=".51" fill="none" stroke="#000080" stroke-width=".13"/>
<path d="M246.2 74.4h7.6" fill="none" stroke="#000" stroke-width=".25"/>
<circle cx="246.2" cy="74.4" r=".51" fill="#000080"/>
<circle cx="246.2" cy="74.4" r=".51" fill="none" stroke="#000080" stroke-width=".13"/>
<path d="M246.2 71.8h7.6" fill="none" stroke="#000" stroke-width=".25"/>
<circle cx="246.2" cy="71.8" r=".51" fill="#000080"/>
<circle cx="246.2" cy="71.8" r=".51" fill="none" stroke="#000080" stroke-width=".13"/>
<path d="M246.2 69.3h7.6M246.2 64.2h7.6M101.3 137.9v2.5M101.3 145.5v2.5M197.9 165.8h4.5M203.7 165.8h4.4" fill="none" stroke="#000" stroke-width=".25"/>
<g fill="none" stroke="#800000" stroke-width=".25">
<path d="M238.6 69.3h5.1l-2.6 2.5zM241.1 66.8v2.5M98.8 150.6h5.1l-2.6 2.5zM101.3 148v2.6M211.9 160.7h2.5M213.2 160.7v2.6M243.7 168.3h5.1M244.4 169.1h3.6M245.2 169.9h2M246 170.6h.5M246.2 165.8v2.5M279.3 168.3h5"/>
<path d="M280 169.1h3.6M280.8 169.9h2M281.5 170.6h.6M281.8 165.8v2.5"/>
</g>
<path d="M99.3 143.4h4M99.3 142.4h4M101.3 140.4v2M101.3 143.4v2.1M203 164.5h1.3l-1.3 2.6h-1.3z" fill="none" stroke="#00f" stroke-width=".25"/>
<circle cx="162.3" cy="165.8" r=".51" fill="#000080"/>
<circle cx="162.3" cy="165.8" r=".51" fill="none" stroke="#000080" stroke-width=".13"/>
<path d="M162.3 165.8v2.5M162.3 173.4v2.6" fill="none" stroke="#000" stroke-width=".25"/>
<circle cx="162.3" cy="165.8" r=".51" fill="#000080"/>
<circle cx="162.3" cy="165.8" r=".51" fill="none" stroke="#000080" stroke-width=".13"/>
<path d="M160.3 171.4h4M160.3 170.4h4M162.3 168.3v2.1M162.3 171.4v2" fill="none" stroke="#00f" stroke-width=".25"/>
<path d="M159.8 178.5h5.1M160.6 179.3h3.5M162.3 176v2.5M161.3 180h2.1M162.1 180.8h.5" fill="none" stroke="#800000" stroke-width=".25"/>
<circle cx="175.1" cy="165.8" r=".51" fill="#000080"/>
<circle cx="175.1" cy="165.8" r=".51" fill="none" stroke="#000080" stroke-width=".13"/>
<path d="M175.1 165.8v2.5M175.1 173.4v2.6" fill="none" stroke="#000" stroke-width=".25"/>
<circle cx="175.1" cy="165.8" r=".51" fill="#000080"/>
<circle cx="175.1" cy="165.8" r=".51" fill="none" stroke="#000080" stroke-width=".13"/>
<path d="M173 171.4h4.1M173 170.4h4.1M175.1 168.3v2.1M175.1 171.4v2" fill="none" stroke="#00f" stroke-width=".25"/>
<path d="M172.5 178.5h5.1M173.3 179.3h3.5M175.1 176v2.5M174 180h2.1M174.8 180.8h.5" fill="none" stroke="#800000" stroke-width=".25"/>
<circle cx="96.3" cy="163.3" r=".51" fill="#000080"/>
<circle cx="96.3" cy="163.3" r=".51" fill="none" stroke="#000080" stroke-width=".13"/>
<path d="M96.3 163.3v2.5M96.3 170.9v2.5" fill="none" stroke="#000" stroke-width=".25"/>
<circle cx="96.3" cy="163.3" r=".51" fill="#000080"/>
<circle cx="96.3" cy="163.3" r=".51" fill="none" stroke="#000080" stroke-width=".13"/>
<path d="M94.3 168.8h4M94.3 167.8h4M96.3 165.8v2M96.3 168.8v2.1" fill="none" stroke="#00f" stroke-width=".25"/>
<path d="M93.7 176h5.1M94.5 176.7h3.5M95.2 177.5h2.1M96 178.2h.5M96.3 173.4v2.6" fill="none" stroke="#800000" stroke-width=".25"/>
<circle cx="83.6" cy="163.3" r=".51" fill="#000080"/>
<circle cx="83.6" cy="163.3" r=".51" fill="none" stroke="#000080" stroke-width=".13"/>
<path d="M83.6 170.9v2.5M83.6 163.3v2.5" fill="none" stroke="#000" stroke-width=".25"/>
<circle cx="83.6" cy="163.3" r=".51" fill="#000080"/>
<circle cx="83.6" cy="163.3" r=".51" fill="none" stroke="#000080" stroke-width=".13"/>
<path d="M81.6 168.8h4M81.6 167.8h4M83.6 165.8v2M83.6 168.8v2.1" fill="none" stroke="#00f" stroke-width=".25"/>
<path d="M81 176h5.1M81.8 176.7h3.5M82.5 177.5h2.1M83.3 178.2h.5M83.6 173.4v2.6" fill="none" stroke="#800000" stroke-width=".25"/>
<circle cx="187.8" cy="165.8" r=".51" fill="#000080"/>
<circle cx="187.8" cy="165.8" r=".51" fill="none" stroke="#000080" stroke-width=".13"/>
<path d="M187.8 165.8v2.5M187.8 173.4v2.6" fill="none" stroke="#000" stroke-width=".25"/>
<circle cx="187.8" cy="165.8" r=".51" fill="#000080"/>
<circle cx="187.8" cy="165.8" r=".51" fill="none" stroke="#000080" stroke-width=".13"/>
<path d="M185.8 171.4h4M185.8 170.4h4M187.8 168.3v2.1M187.8 171.4v2" fill="none" stroke="#00f" stroke-width=".25"/>
<path d="M185.2 178.5h5.1M186 179.3h3.5M187.8 176v2.5M186.7 180h2.1M187.5 180.8h.5" fill="none" stroke="#800000" stroke-width=".25"/>
<circle cx="70.8" cy="163.3" r=".51" fill="#000080"/>
<circle cx="70.8" cy="163.3" r=".51" fill="none" stroke="#000080" stroke-width=".13"/>
<path d="M70.8 163.3v2.5M70.9 170.9v2.5" fill="none" stroke="#000" stroke-width=".25"/>
<circle cx="70.8" cy="163.3" r=".51" fill="#000080"/>
<circle cx="70.8" cy="163.3" r=".51" fill="none" stroke="#000080" stroke-width=".13"/>
<path d="M68.8 168.8h4.1M68.8 167.8h4.1M70.8 165.8v2M70.8 168.8v2.1" fill="none" stroke="#00f" stroke-width=".25"/>
<path d="M68.3 176h5.1M69.1 176.7h3.5M69.8 177.5h2.1M70.6 178.2h.5M70.9 173.4v2.6" fill="none" stroke="#800000" stroke-width=".25"/>
<circle cx="83.6" cy="92.1" r=".51" fill="#000080"/>
<circle cx="83.6" cy="92.1" r=".51" fill="none" stroke="#000080" stroke-width=".13"/>
<path d="M83.6 92.1v2.6M83.6 99.8v2.5" fill="none" stroke="#000" stroke-width=".25"/>
<circle cx="83.6" cy="92.1" r=".51" fill="#000080"/>
<circle cx="83.6" cy="92.1" r=".51" fill="none" stroke="#000080" stroke-width=".13"/>
<path d="M81.6 97.7h4M81.6 96.7h4M83.6 94.7v2M83.6 97.7v2.1" fill="none" stroke="#00f" stroke-width=".25"/>
<circle cx="225.9" cy="92.2" r=".51" fill="#000080"/>
<circle cx="225.9" cy="92.2" r=".51" fill="none" stroke="#000080" stroke-width=".13"/>
<path d="M225.9 92.2v2.5M225.9 99.8v2.5" fill="none" stroke="#000" stroke-width=".25"/>
<circle cx="225.9" cy="92.2" r=".51" fill="#000080"/>
<circle cx="225.9" cy="92.2" r=".51" fill="none" stroke="#000080" stroke-width=".13"/>
<path d="M223.9 97.7h4M223.9 96.7h4M225.9 94.7v2M225.9 97.7v2.1" fill="none" stroke="#00f" stroke-width=".25"/>
<path d="M81 104.8h5.1M81.8 105.6h3.5M82.5 106.4h2.1M83.3 107.1h.5M83.6 102.3v2.5M223.3 104.9h5.1M224.1 105.6h3.6M224.9 106.4h2M225.6 107.1h.5M225.9 102.3v2.6" fill="none" stroke="#800000" stroke-width=".25"/>
<circle cx="162.3" cy="92.1" r=".51" fill="#000080"/>
<circle cx="162.3" cy="92.1" r=".51" fill="none" stroke="#000080" stroke-width=".13"/>
<path d="M162.3 92.1v2.6M162.3 99.8v2.5" fill="none" stroke="#000" stroke-width=".25"/>
<circle cx="162.3" cy="92.1" r=".51" fill="#000080"/>
<circle cx="162.3" cy="92.1" r=".51" fill="none" stroke="#000080" stroke-width=".13"/>
<path d="M160.3 97.7h4M160.3 96.7h4M162.3 94.7v2M162.3 97.7v2.1" fill="none" stroke="#00f" stroke-width=".25"/>
<path d="M159.8 104.8h5.1M160.6 105.6h3.5M161.3 106.4h2.1M162.1 107.1h.5M162.3 102.3v2.5" fill="none" stroke="#800000" stroke-width=".25"/>
<circle cx="175.1" cy="92.2" r=".51" fill="#000080"/>
<circle cx="175.1" cy="92.2" r=".51" fill="none" stroke="#000080" stroke-width=".13"/>
<path d="M175.1 92.2v2.5M175.1 99.8v2.5" fill="none" stroke="#000" stroke-width=".25"/>
<circle cx="175.1" cy="92.2" r=".51" fill="#000080"/>
<circle cx="175.1" cy="92.2" r=".51" fill="none" stroke="#000080" stroke-width=".13"/>
<path d="M173 97.7h4.1M173 96.7h4.1M175.1 94.7v2M175.1 97.7v2.1" fill="none" stroke="#00f" stroke-width=".25"/>
<path d="M172.5 104.9h5.1M173.3 105.6h3.5M174 106.4h2.1M174.8 107.1h.5M175.1 102.3v2.6" fill="none" stroke="#800000" stroke-width=".25"/>
<circle cx="187.8" cy="92.2" r=".51" fill="#000080"/>
<circle cx="187.8" cy="92.2" r=".51" fill="none" stroke="#000080" stroke-width=".13"/>
<path d="M187.8 92.2v2.5M187.8 99.8v2.5" fill="none" stroke="#000" stroke-width=".25"/>
<circle cx="187.8" cy="92.2" r=".51" fill="#000080"/>
<circle cx="187.8" cy="92.2" r=".51" fill="none" stroke="#000080" stroke-width=".13"/>
<path d="M185.8 97.7h4M185.8 96.7h4M187.8 94.7v2M187.8 97.7v2.1" fill="none" stroke="#00f" stroke-width=".25"/>
<path d="M185.2 104.9h5.1M186 105.6h3.5M186.7 106.4h2.1M187.5 107.1h.5M187.8 102.3v2.6" fill="none" stroke="#800000" stroke-width=".25"/>
<circle cx="200.5" cy="92.2" r=".51" fill="#000080"/>
<circle cx="200.5" cy="92.2" r=".51" fill="none" stroke="#000080" stroke-width=".13"/>
<path d="M200.5 92.2v2.5M200.5 99.8v2.5" fill="none" stroke="#000" stroke-width=".25"/>
<circle cx="200.5" cy="92.2" r=".51" fill="#000080"/>
<circle cx="200.5" cy="92.2" r=".51" fill="none" stroke="#000080" stroke-width=".13"/>
<path d="M198.5 97.7h4M198.5 96.7h4M200.5 94.7v2M200.5 97.7v2.1" fill="none" stroke="#00f" stroke-width=".25"/>
<path d="M197.9 104.9h5.1M198.7 105.6h3.5M199.5 106.4h2M200.2 107.1h.5M200.5 102.3v2.6" fill="none" stroke="#800000" stroke-width=".25"/>
<circle cx="213.2" cy="92.2" r=".51" fill="#000080"/>
<circle cx="213.2" cy="92.2" r=".51" fill="none" stroke="#000080" stroke-width=".13"/>
<path d="M213.2 92.2v2.5M213.2 99.8v2.5" fill="none" stroke="#000" stroke-width=".25"/>
<circle cx="213.2" cy="92.2" r=".51" fill="#000080"/>
<circle cx="213.2" cy="92.2" r=".51" fill="none" stroke="#000080" stroke-width=".13"/>
<path d="M211.2 97.7h4M211.2 96.7h4M213.2 94.7v2M213.2 97.7v2.1" fill="none" stroke="#00f" stroke-width=".25"/>
<path d="M210.6 104.9h5.1M211.4 105.6h3.6M212.2 106.4h2M212.9 107.1h.5M213.2 102.3v2.6" fill="none" stroke="#800000" stroke-width=".25"/>
<circle cx="96.3" cy="92.1" r=".51" fill="#000080"/>
<circle cx="96.3" cy="92.1" r=".51" fill="none" stroke="#000080" stroke-width=".13"/>
<path d="M96.3 92.1v2.6M96.3 99.8v2.5" fill="none" stroke="#000" stroke-width=".25"/>
<circle cx="96.3" cy="92.1" r=".51" fill="#000080"/>
<circle cx="96.3" cy="92.1" r=".51" fill="none" stroke="#000080" stroke-width=".13"/>
<path d="M94.3 97.7h4M94.3 96.7h4M96.3 94.7v2M96.3 97.7v2.1" fill="none" stroke="#00f" stroke-width=".25"/>
<path d="M93.7 104.8h5.1M94.5 105.6h3.5M95.2 106.4h2.1M96 107.1h.5M96.3 102.3v2.5" fill="none" stroke="#800000" stroke-width=".25"/>
<circle cx="20" cy="115" r=".51" fill="#000080"/>
<circle cx="20" cy="115" r=".51" fill="none" stroke="#000080" stroke-width=".13"/>
<path d="M20 115v2.5M20 122.6v2.6" fill="none" stroke="#000" stroke-width=".25"/>
<circle cx="20" cy="115" r=".51" fill="#000080"/>
<circle cx="20" cy="115" r=".51" fill="none" stroke="#000080" stroke-width=".13"/>
<path d="M18 119.6h4M20 117.5v2.1M18 120.6h4M20 120.6v2" fill="none" stroke="#00f" stroke-width=".25"/>
<path d="M17.5 127.7h5.1M18.2 128.5h3.6M19 129.2h2M19.8 130h.5M20 125.2v2.5" fill="none" stroke="#800000" stroke-width=".25"/>
<circle cx="58.1" cy="115" r=".51" fill="#000080"/>
<circle cx="58.1" cy="115" r=".51" fill="none" stroke="#000080" stroke-width=".13"/>
<path d="M58.1 115v2.5M58.1 122.6v2.6" fill="none" stroke="#000" stroke-width=".25"/>
<circle cx="58.1" cy="115" r=".51" fill="#000080"/>
<circle cx="58.1" cy="115" r=".51" fill="none" stroke="#000080" stroke-width=".13"/>
<path d="M56.1 119.6h4M58.1 117.5v2.1M56.1 120.6h4M58.1 120.6v2" fill="none" stroke="#00f" stroke-width=".25"/>
<path d="M55.6 127.7h5.1M56.4 128.5h3.5M57.1 129.2h2.1M57.9 130h.5M58.1 125.2v2.5" fill="none" stroke="#800000" stroke-width=".25"/>
<circle cx="70.8" cy="115" r=".51" fill="#000080"/>
<circle cx="70.8" cy="115" r=".51" fill="none" stroke="#000080" stroke-width=".13"/>
<path d="M70.8 115v2.5M70.8 122.6v2.6" fill="none" stroke="#000" stroke-width=".25"/>
<circle cx="70.8" cy="115" r=".51" fill="#000080"/>
<circle cx="70.8" cy="115" r=".51" fill="none" stroke="#000080" stroke-width=".13"/>
<path d="M68.8 119.6h4.1M70.8 117.5v2.1M68.8 120.6h4.1M70.8 120.6v2" fill="none" stroke="#00f" stroke-width=".25"/>
<path d="M68.3 127.7h5.1M69.1 128.5h3.5M69.8 129.2h2.1M70.6 130h.5M70.8 125.2v2.5" fill="none" stroke="#800000" stroke-width=".25"/>
<circle cx="83.6" cy="115" r=".51" fill="#000080"/>
<circle cx="83.6" cy="115" r=".51" fill="none" stroke="#000080" stroke-width=".13"/>
<path d="M83.6 115v2.5M83.6 122.6v2.6" fill="none" stroke="#000" stroke-width=".25"/>
<circle cx="83.6" cy="115" r=".51" fill="#000080"/>
<circle cx="83.6" cy="115" r=".51" fill="none" stroke="#000080" stroke-width=".13"/>
<path d="M81.6 119.6h4M83.6 117.5v2.1M81.6 120.6h4M83.6 120.6v2" fill="none" stroke="#00f" stroke-width=".25"/>
<path d="M81 127.7h5.1M81.8 128.5h3.5M82.5 129.2h2.1M83.3 130h.5M83.6 125.2v2.5" fill="none" stroke="#800000" stroke-width=".25"/>
<circle cx="32.7" cy="115" r=".51" fill="#000080"/>
<circle cx="32.7" cy="115" r=".51" fill="none" stroke="#000080" stroke-width=".13"/>
<path d="M32.7 115v2.5M32.7 122.6v2.6" fill="none" stroke="#000" stroke-width=".25"/>
<circle cx="32.7" cy="115" r=".51" fill="#000080"/>
<circle cx="32.7" cy="115" r=".51" fill="none" stroke="#000080" stroke-width=".13"/>
<path d="M30.7 119.6h4M32.7 117.5v2.1M30.7 120.6h4M32.7 120.6v2" fill="none" stroke="#00f" stroke-width=".25"/>
<path d="M30.2 127.7h5.1M30.9 128.5h3.6M31.7 129.2h2M32.5 130h.5M32.7 125.2v2.5" fill="none" stroke="#800000" stroke-width=".25"/>
<circle cx="45.4" cy="115" r=".51" fill="#000080"/>
<circle cx="45.4" cy="115" r=".51" fill="none" stroke="#000080" stroke-width=".13"/>
<path d="M45.4 115v2.5M45.4 122.6v2.6" fill="none" stroke="#000" stroke-width=".25"/>
<circle cx="45.4" cy="115" r=".51" fill="#000080"/>
<circle cx="45.4" cy="115" r=".51" fill="none" stroke="#000080" stroke-width=".13"/>
<path d="M160.3 69.8h4M160.3 68.8h4M162.3 66.8v2M162.3 69.8v2M43.4 119.6h4M45.4 117.5v2.1M43.4 120.6h4M45.4 120.6v2" fill="none" stroke="#00f" stroke-width=".25"/>
<path d="M159.8 76.9h5.1M160.6 77.7h3.5M161.3 78.4h2.1M162.1 79.2h.5M162.3 74.4v2.5M42.9 127.7h5.1M43.7 128.5h3.5M44.4 129.2h2.1M45.2 130h.5M45.4 125.2v2.5" fill="none" stroke="#800000" stroke-width=".25"/>
<path d="M162.3 64.2v2.6M162.3 71.8v2.6" fill="none" stroke="#000" stroke-width=".25"/>
<circle cx="20" cy="31.2" r=".51" fill="#000080"/>
<circle cx="20" cy="31.2" r=".51" fill="none" stroke="#000080" stroke-width=".13"/>
<path d="M20 31.2v2.5M20 38.8v2.6" fill="none" stroke="#000" stroke-width=".25"/>
<circle cx="20" cy="31.2" r=".51" fill="#000080"/>
<circle cx="20" cy="31.2" r=".51" fill="none" stroke="#000080" stroke-width=".13"/>
<path d="M18 36.8h4M18 35.8h4M20 33.7v2.1M20 36.8v2" fill="none" stroke="#00f" stroke-width=".25"/>
<path d="M17.5 43.9h5.1M18.2 44.7h3.6M19 45.4h2M19.8 46.2h.5M20 41.4v2.5" fill="none" stroke="#800000" stroke-width=".25"/>
<circle cx="70.8" cy="31.2" r=".51" fill="#000080"/>
<circle cx="70.8" cy="31.2" r=".51" fill="none" stroke="#000080" stroke-width=".13"/>
<path d="M70.8 31.2v2.5M70.8 38.8v2.6" fill="none" stroke="#000" stroke-width=".25"/>
<circle cx="70.8" cy="31.2" r=".51" fill="#000080"/>
<circle cx="70.8" cy="31.2" r=".51" fill="none" stroke="#000080" stroke-width=".13"/>
<path d="M68.8 36.8h4.1M68.8 35.8h4.1M70.8 33.7v2.1M70.8 36.8v2" fill="none" stroke="#00f" stroke-width=".25"/>
<path d="M68.3 43.9h5.1M69.1 44.7h3.5M69.8 45.4h2.1M70.6 46.2h.5M70.8 41.4v2.5" fill="none" stroke="#800000" stroke-width=".25"/>
<circle cx="83.6" cy="31.2" r=".51" fill="#000080"/>
<circle cx="83.6" cy="31.2" r=".51" fill="none" stroke="#000080" stroke-width=".13"/>
<path d="M83.6 31.2v2.5M83.6 38.8v2.6" fill="none" stroke="#000" stroke-width=".25"/>
<circle cx="83.6" cy="31.2" r=".51" fill="#000080"/>
<circle cx="83.6" cy="31.2" r=".51" fill="none" stroke="#000080" stroke-width=".13"/>
<path d="M81.6 36.8h4M81.6 35.8h4M83.6 33.7v2.1M83.6 36.8v2" fill="none" stroke="#00f" stroke-width=".25"/>
<path d="M81 43.9h5.1M81.8 44.7h3.5M82.5 45.4h2.1M83.3 46.2h.5M83.6 41.4v2.5" fill="none" stroke="#800000" stroke-width=".25"/>
<circle cx="96.3" cy="31.2" r=".51" fill="#000080"/>
<circle cx="96.3" cy="31.2" r=".51" fill="none" stroke="#000080" stroke-width=".13"/>
<path d="M96.3 31.2v2.5M96.3 38.8v2.6" fill="none" stroke="#000" stroke-width=".25"/>
<circle cx="96.3" cy="31.2" r=".51" fill="#000080"/>
<circle cx="96.3" cy="31.2" r=".51" fill="none" stroke="#000080" stroke-width=".13"/>
<path d="M94.3 36.8h4M94.3 35.8h4M96.3 33.7v2.1M96.3 36.8v2" fill="none" stroke="#00f" stroke-width=".25"/>
<path d="M93.7 43.9h5.1M94.5 44.7h3.5M95.2 45.4h2.1M96 46.2h.5M96.3 41.4v2.5" fill="none" stroke="#800000" stroke-width=".25"/>
<circle cx="58.1" cy="31.2" r=".51" fill="#000080"/>
<circle cx="58.1" cy="31.2" r=".51" fill="none" stroke="#000080" stroke-width=".13"/>
<path d="M58.1 31.2v2.5M58.1 38.8v2.6" fill="none" stroke="#000" stroke-width=".25"/>
<circle cx="58.1" cy="31.2" r=".51" fill="#000080"/>
<circle cx="58.1" cy="31.2" r=".51" fill="none" stroke="#000080" stroke-width=".13"/>
<path d="M56.1 36.8h4M56.1 35.8h4M58.1 33.7v2.1M58.1 36.8v2" fill="none" stroke="#00f" stroke-width=".25"/>
<path d="M55.6 43.9h5.1M56.4 44.7h3.5M57.1 45.4h2.1M57.9 46.2h.5M58.1 41.4v2.5" fill="none" stroke="#800000" stroke-width=".25"/>
<circle cx="45.4" cy="31.2" r=".51" fill="#000080"/>
<circle cx="45.4" cy="31.2" r=".51" fill="none" stroke="#000080" stroke-width=".13"/>
<path d="M45.4 31.2v2.5M45.4 38.8v2.6" fill="none" stroke="#000" stroke-width=".25"/>
<circle cx="45.4" cy="31.2" r=".51" fill="#000080"/>
<circle cx="45.4" cy="31.2" r=".51" fill="none" stroke="#000080" stroke-width=".13"/>
<path d="M43.4 36.8h4M43.4 35.8h4M45.4 33.7v2.1M45.4 36.8v2" fill="none" stroke="#00f" stroke-width=".25"/>
<path d="M42.9 43.9h5.1M43.7 44.7h3.5M44.4 45.4h2.1M45.2 46.2h.5M45.4 41.4v2.5" fill="none" stroke="#800000" stroke-width=".25"/>
<circle cx="32.7" cy="31.2" r=".51" fill="#000080"/>
<circle cx="32.7" cy="31.2" r=".51" fill="none" stroke="#000080" stroke-width=".13"/>
<path d="M32.7 31.2v2.5M32.7 38.8v2.6" fill="none" stroke="#000" stroke-width=".25"/>
<circle cx="32.7" cy="31.2" r=".51" fill="#000080"/>
<circle cx="32.7" cy="31.2" r=".51" fill="none" stroke="#000080" stroke-width=".13"/>
<path d="M30.7 36.8h4M30.7 35.8h4M32.7 33.7v2.1M32.7 36.8v2" fill="none" stroke="#00f" stroke-width=".25"/>
<path d="M30.2 43.9h5.1M30.9 44.7h3.6M31.7 45.4h2M32.5 46.2h.5M32.7 41.4v2.5" fill="none" stroke="#800000" stroke-width=".25"/>
<circle cx="20" cy="59.1" r=".51" fill="#000080"/>
<circle cx="20" cy="59.1" r=".51" fill="none" stroke="#000080" stroke-width=".13"/>
<path d="M20 59.1v2.6M20 66.8v2.5" fill="none" stroke="#000" stroke-width=".25"/>
<circle cx="20" cy="59.1" r=".51" fill="#000080"/>
<circle cx="20" cy="59.1" r=".51" fill="none" stroke="#000080" stroke-width=".13"/>
<path d="M18 64.7h4M18 63.7h4M20 61.7v2M20 64.7v2.1" fill="none" stroke="#00f" stroke-width=".25"/>
<path d="M17.5 71.8h5.1M18.2 72.6h3.6M19 73.4h2M19.8 74.1h.5M20 69.3v2.5" fill="none" stroke="#800000" stroke-width=".25"/>
<circle cx="70.8" cy="59.1" r=".51" fill="#000080"/>
<circle cx="70.8" cy="59.1" r=".51" fill="none" stroke="#000080" stroke-width=".13"/>
<path d="M70.8 59.1v2.6M70.8 66.8v2.5" fill="none" stroke="#000" stroke-width=".25"/>
<circle cx="70.8" cy="59.1" r=".51" fill="#000080"/>
<circle cx="70.8" cy="59.1" r=".51" fill="none" stroke="#000080" stroke-width=".13"/>
<path d="M68.8 64.7h4.1M68.8 63.7h4.1M70.8 61.7v2M70.8 64.7v2.1" fill="none" stroke="#00f" stroke-width=".25"/>
<path d="M68.3 71.8h5.1M69.1 72.6h3.5M69.8 73.4h2.1M70.6 74.1h.5M70.8 69.3v2.5" fill="none" stroke="#800000" stroke-width=".25"/>
<circle cx="83.6" cy="59.1" r=".51" fill="#000080"/>
<circle cx="83.6" cy="59.1" r=".51" fill="none" stroke="#000080" stroke-width=".13"/>
<path d="M83.6 59.1v2.6M83.6 66.8v2.5" fill="none" stroke="#000" stroke-width=".25"/>
<circle cx="83.6" cy="59.1" r=".51" fill="#000080"/>
<circle cx="83.6" cy="59.1" r=".51" fill="none" stroke="#000080" stroke-width=".13"/>
<path d="M81.6 64.7h4M81.6 63.7h4M83.6 61.7v2M83.6 64.7v2.1" fill="none" stroke="#00f" stroke-width=".25"/>
<path d="M81 71.8h5.1M81.8 72.6h3.5M82.5 73.4h2.1M83.3 74.1h.5M83.6 69.3v2.5" fill="none" stroke="#800000" stroke-width=".25"/>
<circle cx="96.3" cy="59.1" r=".51" fill="#000080"/>
<circle cx="96.3" cy="59.1" r=".51" fill="none" stroke="#000080" stroke-width=".13"/>
<path d="M96.3 59.1v2.6M96.3 66.8v2.5" fill="none" stroke="#000" stroke-width=".25"/>
<circle cx="96.3" cy="59.1" r=".51" fill="#000080"/>
<circle cx="96.3" cy="59.1" r=".51" fill="none" stroke="#000080" stroke-width=".13"/>
<path d="M94.3 64.7h4M94.3 63.7h4M96.3 61.7v2M96.3 64.7v2.1" fill="none" stroke="#00f" stroke-width=".25"/>
<path d="M93.7 71.8h5.1M94.5 72.6h3.5M95.2 73.4h2.1M96 74.1h.5M96.3 69.3v2.5" fill="none" stroke="#800000" stroke-width=".25"/>
<circle cx="58.1" cy="59.1" r=".51" fill="#000080"/>
<circle cx="58.1" cy="59.1" r=".51" fill="none" stroke="#000080" stroke-width=".13"/>
<path d="M58.1 59.1v2.6M58.1 66.8v2.5" fill="none" stroke="#000" stroke-width=".25"/>
<circle cx="58.1" cy="59.1" r=".51" fill="#000080"/>
<circle cx="58.1" cy="59.1" r=".51" fill="none" stroke="#000080" stroke-width=".13"/>
<path d="M56.1 64.7h4M56.1 63.7h4M58.1 61.7v2M58.1 64.7v2.1" fill="none" stroke="#00f" stroke-width=".25"/>
<path d="M55.6 71.8h5.1M56.4 72.6h3.5M57.1 73.4h2.1M57.9 74.1h.5M58.1 69.3v2.5" fill="none" stroke="#800000" stroke-width=".25"/>
<circle cx="45.4" cy="59.1" r=".51" fill="#000080"/>
<circle cx="45.4" cy="59.1" r=".51" fill="none" stroke="#000080" stroke-width=".13"/>
<path d="M45.4 59.1v2.6M45.4 66.8v2.5" fill="none" stroke="#000" stroke-width=".25"/>
<circle cx="45.4" cy="59.1" r=".51" fill="#000080"/>
<circle cx="45.4" cy="59.1" r=".51" fill="none" stroke="#000080" stroke-width=".13"/>
<path d="M43.4 64.7h4M43.4 63.7h4M45.4 61.7v2M45.4 64.7v2.1" fill="none" stroke="#00f" stroke-width=".25"/>
<path d="M42.9 71.8h5.1M43.7 72.6h3.5M44.4 73.4h2.1M45.2 74.1h.5M45.4 69.3v2.5" fill="none" stroke="#800000" stroke-width=".25"/>
<circle cx="32.7" cy="59.1" r=".51" fill="#000080"/>
<circle cx="32.7" cy="59.1" r=".51" fill="none" stroke="#000080" stroke-width=".13"/>
<path d="M32.7 59.1v2.6M32.7 66.8v2.5" fill="none" stroke="#000" stroke-width=".25"/>
<circle cx="32.7" cy="59.1" r=".51" fill="#000080"/>
<circle cx="32.7" cy="59.1" r=".51" fill="none" stroke="#000080" stroke-width=".13"/>
<path d="M30.7 64.7h4M30.7 63.7h4M32.7 61.7v2M32.7 64.7v2.1" fill="none" stroke="#00f" stroke-width=".25"/>
<path d="M30.2 71.8h5.1M30.9 72.6h3.6M31.7 73.4h2M32.5 74.1h.5M32.7 69.3v2.5" fill="none" stroke="#800000" stroke-width=".25"/>
<circle cx="187.8" cy="31.2" r=".51" fill="#000080"/>
<circle cx="187.8" cy="31.2" r=".51" fill="none" stroke="#000080" stroke-width=".13"/>
<path d="M187.8 31.2v2.5M187.8 38.8v2.6" fill="none" stroke="#000" stroke-width=".25"/>
<circle cx="187.8" cy="31.2" r=".51" fill="#000080"/>
<circle cx="187.8" cy="31.2" r=".51" fill="none" stroke="#000080" stroke-width=".13"/>
<path d="M185.8 36.8h4M185.8 35.8h4M187.8 33.7v2.1M187.8 36.8v2" fill="none" stroke="#00f" stroke-width=".25"/>
<path d="M185.2 43.9h5.1M186 44.7h3.5M186.7 45.4h2.1M187.5 46.2h.5M187.8 41.4v2.5" fill="none" stroke="#800000" stroke-width=".25"/>
<circle cx="175.1" cy="31.2" r=".51" fill="#000080"/>
<circle cx="175.1" cy="31.2" r=".51" fill="none" stroke="#000080" stroke-width=".13"/>
<path d="M175.1 31.2v2.5M175.1 38.8v2.6" fill="none" stroke="#000" stroke-width=".25"/>
<circle cx="175.1" cy="31.2" r=".51" fill="#000080"/>
<circle cx="175.1" cy="31.2" r=".51" fill="none" stroke="#000080" stroke-width=".13"/>
<path d="M173 36.8h4.1M173 35.8h4.1M175.1 33.7v2.1M175.1 36.8v2" fill="none" stroke="#00f" stroke-width=".25"/>
<path d="M172.5 43.9h5.1M173.3 44.7h3.5M174 45.4h2.1M174.8 46.2h.5M175.1 41.4v2.5" fill="none" stroke="#800000" stroke-width=".25"/>
<circle cx="162.3" cy="31.2" r=".51" fill="#000080"/>
<circle cx="162.3" cy="31.2" r=".51" fill="none" stroke="#000080" stroke-width=".13"/>
<path d="M162.3 31.2v2.5M162.3 38.8v2.6" fill="none" stroke="#000" stroke-width=".25"/>
<circle cx="162.3" cy="31.2" r=".51" fill="#000080"/>
<circle cx="162.3" cy="31.2" r=".51" fill="none" stroke="#000080" stroke-width=".13"/>
<path d="M160.3 36.8h4M160.3 35.8h4M162.3 33.7v2.1M162.3 36.8v2" fill="none" stroke="#00f" stroke-width=".25"/>
<path d="M159.8 43.9h5.1M160.6 44.7h3.5M161.3 45.4h2.1M162.1 46.2h.5M162.3 41.4v2.5" fill="none" stroke="#800000" stroke-width=".25"/>
<circle cx="200.5" cy="31.2" r=".51" fill="#000080"/>
<circle cx="200.5" cy="31.2" r=".51" fill="none" stroke="#000080" stroke-width=".13"/>
<path d="M200.5 31.2v2.5M200.5 38.8v2.6" fill="none" stroke="#000" stroke-width=".25"/>
<circle cx="200.5" cy="31.2" r=".51" fill="#000080"/>
<circle cx="200.5" cy="31.2" r=".51" fill="none" stroke="#000080" stroke-width=".13"/>
<path d="M198.5 36.8h4M198.5 35.8h4M200.5 33.7v2.1M200.5 36.8v2" fill="none" stroke="#00f" stroke-width=".25"/>
<path d="M197.9 43.9h5.1M198.7 44.7h3.5M199.5 45.4h2M200.2 46.2h.5M200.5 41.4v2.5" fill="none" stroke="#800000" stroke-width=".25"/>
<circle cx="213.2" cy="31.2" r=".51" fill="#000080"/>
<circle cx="213.2" cy="31.2" r=".51" fill="none" stroke="#000080" stroke-width=".13"/>
<path d="M213.2 31.2v2.5M213.2 38.8v2.6" fill="none" stroke="#000" stroke-width=".25"/>
<circle cx="213.2" cy="31.2" r=".51" fill="#000080"/>
<circle cx="213.2" cy="31.2" r=".51" fill="none" stroke="#000080" stroke-width=".13"/>
<path d="M211.2 36.8h4M211.2 35.8h4M213.2 33.7v2.1M213.2 36.8v2" fill="none" stroke="#00f" stroke-width=".25"/>
<path d="M210.6 43.9h5.1M211.4 44.7h3.6M212.2 45.4h2M212.9 46.2h.5M213.2 41.4v2.5" fill="none" stroke="#800000" stroke-width=".25"/>
<circle cx="225.9" cy="31.2" r=".51" fill="#000080"/>
<circle cx="225.9" cy="31.2" r=".51" fill="none" stroke="#000080" stroke-width=".13"/>
<path d="M225.9 31.2v2.5M225.9 38.8v2.6" fill="none" stroke="#000" stroke-width=".25"/>
<circle cx="225.9" cy="31.2" r=".51" fill="#000080"/>
<circle cx="225.9" cy="31.2" r=".51" fill="none" stroke="#000080" stroke-width=".13"/>
<path d="M223.9 36.8h4M223.9 35.8h4M225.9 33.7v2.1M225.9 36.8v2" fill="none" stroke="#00f" stroke-width=".25"/>
<path d="M223.3 43.9h5.1M224.1 44.7h3.6M224.9 45.4h2M225.6 46.2h.5M225.9 41.4v2.5" fill="none" stroke="#800000" stroke-width=".25"/>
<path d="M14.9 28.7v2.5h94.1v12.7" fill="none" stroke="#000080" stroke-width=".25"/>
<circle cx="109" cy="41.4" r=".51" fill="#000080"/>
<circle cx="109" cy="41.4" r=".51" fill="none" stroke="#000080" stroke-width=".13"/>
<circle cx="109" cy="38.8" r=".51" fill="#000080"/>
<circle cx="109" cy="38.8" r=".51" fill="none" stroke="#000080" stroke-width=".13"/>
<circle cx="109" cy="36.3" r=".51" fill="#000080"/>
<circle cx="109" cy="36.3" r=".51" fill="none" stroke="#000080" stroke-width=".13"/>
<circle cx="109" cy="33.7" r=".51" fill="#000080"/>
<circle cx="109" cy="33.7" r=".51" fill="none" stroke="#000080" stroke-width=".13"/>
<circle cx="109" cy="31.2" r=".51" fill="#000080"/>
<circle cx="109" cy="31.2" r=".51" fill="none" stroke="#000080" stroke-width=".13"/>
<circle cx="96.3" cy="31.2" r=".51" fill="#000080"/>
<circle cx="96.3" cy="31.2" r=".51" fill="none" stroke="#000080" stroke-width=".13"/>
<circle cx="83.6" cy="31.2" r=".51" fill="#000080"/>
<circle cx="83.6" cy="31.2" r=".51" fill="none" stroke="#000080" stroke-width=".13"/>
<circle cx="70.8" cy="31.2" r=".51" fill="#000080"/>
<circle cx="70.8" cy="31.2" r=".51" fill="none" stroke="#000080" stroke-width=".13"/>
<circle cx="58.1" cy="31.2" r=".51" fill="#000080"/>
<circle cx="58.1" cy="31.2" r=".51" fill="none" stroke="#000080" stroke-width=".13"/>
<circle cx="45.4" cy="31.2" r=".51" fill="#000080"/>
<circle cx="45.4" cy="31.2" r=".51" fill="none" stroke="#000080" stroke-width=".13"/>
<circle cx="32.7" cy="31.2" r=".51" fill="#000080"/>
<circle cx="32.7" cy="31.2" r=".51" fill="none" stroke="#000080" stroke-width=".13"/>
<circle cx="20" cy="31.2" r=".51" fill="#000080"/>
<circle cx="20" cy="31.2" r=".51" fill="none" stroke="#000080" stroke-width=".13"/>
<path d="M14.9 56.6v2.5h94.1v5.1" fill="none" stroke="#000080" stroke-width=".25"/>
<circle cx="109" cy="61.7" r=".51" fill="#000080"/>
<circle cx="109" cy="61.7" r=".51" fill="none" stroke="#000080" stroke-width=".13"/>
<circle cx="109" cy="59.1" r=".51" fill="#000080"/>
<circle cx="109" cy="59.1" r=".51" fill="none" stroke="#000080" stroke-width=".13"/>
<circle cx="96.3" cy="59.1" r=".51" fill="#000080"/>
<circle cx="96.3" cy="59.1" r=".51" fill="none" stroke="#000080" stroke-width=".13"/>
<circle cx="83.6" cy="59.1" r=".51" fill="#000080"/>
<circle cx="83.6" cy="59.1" r=".51" fill="none" stroke="#000080" stroke-width=".13"/>
<circle cx="70.8" cy="59.1" r=".51" fill="#000080"/>
<circle cx="70.8" cy="59.1" r=".51" fill="none" stroke="#000080" stroke-width=".13"/>
<circle cx="58.1" cy="59.1" r=".51" fill="#000080"/>
<circle cx="58.1" cy="59.1" r=".51" fill="none" stroke="#000080" stroke-width=".13"/>
<circle cx="45.4" cy="59.1" r=".51" fill="#000080"/>
<circle cx="45.4" cy="59.1" r=".51" fill="none" stroke="#000080" stroke-width=".13"/>
<circle cx="32.7" cy="59.1" r=".51" fill="#000080"/>
<circle cx="32.7" cy="59.1" r=".51" fill="none" stroke="#000080" stroke-width=".13"/>
<circle cx="20" cy="59.1" r=".51" fill="#000080"/>
<circle cx="20" cy="59.1" r=".51" fill="none" stroke="#000080" stroke-width=".13"/>
<path d="M231 89.6v2.6h-78.8v43.1" fill="none" stroke="#000080" stroke-width=".25"/>
<circle cx="152.2" cy="132.8" r=".51" fill="#000080"/>
<circle cx="152.2" cy="132.8" r=".51" fill="none" stroke="#000080" stroke-width=".13"/>
<circle cx="152.2" cy="130.2" r=".51" fill="#000080"/>
<circle cx="152.2" cy="130.2" r=".51" fill="none" stroke="#000080" stroke-width=".13"/>
<circle cx="152.2" cy="127.7" r=".51" fill="#000080"/>
<circle cx="152.2" cy="127.7" r=".51" fill="none" stroke="#000080" stroke-width=".13"/>
<circle cx="152.2" cy="125.2" r=".51" fill="#000080"/>
<circle cx="152.2" cy="125.2" r=".51" fill="none" stroke="#000080" stroke-width=".13"/>
<circle cx="152.2" cy="122.6" r=".51" fill="#000080"/>
<circle cx="152.2" cy="122.6" r=".51" fill="none" stroke="#000080" stroke-width=".13"/>
<circle cx="152.2" cy="120.1" r=".51" fill="#000080"/>
<circle cx="152.2" cy="120.1" r=".51" fill="none" stroke="#000080" stroke-width=".13"/>
<circle cx="152.2" cy="117.5" r=".51" fill="#000080"/>
<circle cx="152.2" cy="117.5" r=".51" fill="none" stroke="#000080" stroke-width=".13"/>
<circle cx="152.2" cy="115" r=".51" fill="#000080"/>
<circle cx="152.2" cy="115" r=".51" fill="none" stroke="#000080" stroke-width=".13"/>
<circle cx="152.2" cy="112.5" r=".51" fill="#000080"/>
<circle cx="152.2" cy="112.5" r=".51" fill="none" stroke="#000080" stroke-width=".13"/>
<circle cx="152.2" cy="109.9" r=".51" fill="#000080"/>
<circle cx="152.2" cy="109.9" r=".51" fill="none" stroke="#000080" stroke-width=".13"/>
<circle cx="152.2" cy="107.4" r=".51" fill="#000080"/>
<circle cx="152.2" cy="107.4" r=".51" fill="none" stroke="#000080" stroke-width=".13"/>
<circle cx="152.2" cy="104.8" r=".51" fill="#000080"/>
<circle cx="152.2" cy="104.8" r=".51" fill="none" stroke="#000080" stroke-width=".13"/>
<circle cx="152.2" cy="102.3" r=".51" fill="#000080"/>
<circle cx="152.2" cy="102.3" r=".51" fill="none" stroke="#000080" stroke-width=".13"/>
<circle cx="152.2" cy="99.8" r=".51" fill="#000080"/>
<circle cx="152.2" cy="99.8" r=".51" fill="none" stroke="#000080" stroke-width=".13"/>
<circle cx="152.2" cy="97.2" r=".51" fill="#000080"/>
<circle cx="152.2" cy="97.2" r=".51" fill="none" stroke="#000080" stroke-width=".13"/>
<circle cx="152.2" cy="94.7" r=".51" fill="#000080"/>
<circle cx="152.2" cy="94.7" r=".51" fill="none" stroke="#000080" stroke-width=".13"/>
<circle cx="152.2" cy="92.1" r=".51" fill="#000080"/>
<circle cx="152.2" cy="92.1" r=".51" fill="none" stroke="#000080" stroke-width=".13"/>
<circle cx="162.3" cy="92.1" r=".51" fill="#000080"/>
<circle cx="162.3" cy="92.1" r=".51" fill="none" stroke="#000080" stroke-width=".13"/>
<circle cx="175.1" cy="92.2" r=".51" fill="#000080"/>
<circle cx="175.1" cy="92.2" r=".51" fill="none" stroke="#000080" stroke-width=".13"/>
<circle cx="187.8" cy="92.2" r=".51" fill="#000080"/>
<circle cx="187.8" cy="92.2" r=".51" fill="none" stroke="#000080" stroke-width=".13"/>
<circle cx="200.5" cy="92.2" r=".51" fill="#000080"/>
<circle cx="200.5" cy="92.2" r=".51" fill="none" stroke="#000080" stroke-width=".13"/>
<circle cx="213.2" cy="92.2" r=".51" fill="#000080"/>
<circle cx="213.2" cy="92.2" r=".51" fill="none" stroke="#000080" stroke-width=".13"/>
<circle cx="225.9" cy="92.2" r=".51" fill="#000080"/>
<circle cx="225.9" cy="92.2" r=".51" fill="none" stroke="#000080" stroke-width=".13"/>
<path d="M65.8 160.7v2.6h40.6v10.1" fill="none" stroke="#000080" stroke-width=".25"/>
<circle cx="70.8" cy="163.3" r=".51" fill="#000080"/>
<circle cx="70.8" cy="163.3" r=".51" fill="none" stroke="#000080" stroke-width=".13"/>
<circle cx="83.6" cy="163.3" r=".51" fill="#000080"/>
<circle cx="83.6" cy="163.3" r=".51" fill="none" stroke="#000080" stroke-width=".13"/>
<circle cx="96.3" cy="163.3" r=".51" fill="#000080"/>
<circle cx="96.3" cy="163.3" r=".51" fill="none" stroke="#000080" stroke-width=".13"/>
<circle cx="106.4" cy="163.3" r=".51" fill="#000080"/>
<circle cx="106.4" cy="163.3" r=".51" fill="none" stroke="#000080" stroke-width=".13"/>
<circle cx="106.4" cy="165.8" r=".51" fill="#000080"/>
<circle cx="106.4" cy="165.8" r=".51" fill="none" stroke="#000080" stroke-width=".13"/>
<circle cx="106.4" cy="168.3" r=".51" fill="#000080"/>
<circle cx="106.4" cy="168.3" r=".51" fill="none" stroke="#000080" stroke-width=".13"/>
<circle cx="106.4" cy="170.9" r=".51" fill="#000080"/>
<circle cx="106.4" cy="170.9" r=".51" fill="none" stroke="#000080" stroke-width=".13"/>
<path d="M192.8 163.3v2.5h-40.6v7.6" fill="none" stroke="#000080" stroke-width=".25"/>
<circle cx="152.2" cy="170.9" r=".51" fill="#000080"/>
<circle cx="152.2" cy="170.9" r=".51" fill="none" stroke="#000080" stroke-width=".13"/>
<circle cx="152.2" cy="168.3" r=".51" fill="#000080"/>
<circle cx="152.2" cy="168.3" r=".51" fill="none" stroke="#000080" stroke-width=".13"/>
<circle cx="152.2" cy="165.8" r=".51" fill="#000080"/>
<circle cx="152.2" cy="165.8" r=".51" fill="none" stroke="#000080" stroke-width=".13"/>
<circle cx="162.3" cy="165.8" r=".51" fill="#000080"/>
<circle cx="162.3" cy="165.8" r=".51" fill="none" stroke="#000080" stroke-width=".13"/>
<circle cx="175.1" cy="165.8" r=".51" fill="#000080"/>
<circle cx="175.1" cy="165.8" r=".51" fill="none" stroke="#000080" stroke-width=".13"/>
<circle cx="187.8" cy="165.8" r=".51" fill="#000080"/>
<circle cx="187.8" cy="165.8" r=".51" fill="none" stroke="#000080" stroke-width=".13"/>
<circle cx="192.8" cy="165.8" r=".51" fill="#000080"/>
<circle cx="192.8" cy="165.8" r=".51" fill="none" stroke="#000080" stroke-width=".13"/>
<path d="M246.2 69.3v96.5" fill="none" stroke="#000080" stroke-width=".25"/>
<circle cx="246.2" cy="71.8" r=".51" fill="#000080"/>
<circle cx="246.2" cy="71.8" r=".51" fill="none" stroke="#000080" stroke-width=".13"/>
<circle cx="246.2" cy="74.4" r=".51" fill="#000080"/>
<circle cx="246.2" cy="74.4" r=".51" fill="none" stroke="#000080" stroke-width=".13"/>
<circle cx="246.2" cy="76.9" r=".51" fill="#000080"/>
<circle cx="246.2" cy="76.9" r=".51" fill="none" stroke="#000080" stroke-width=".13"/>
<circle cx="246.2" cy="79.5" r=".51" fill="#000080"/>
<circle cx="246.2" cy="79.5" r=".51" fill="none" stroke="#000080" stroke-width=".13"/>
<circle cx="246.2" cy="82" r=".51" fill="#000080"/>
<circle cx="246.2" cy="82" r=".51" fill="none" stroke="#000080" stroke-width=".13"/>
<circle cx="246.2" cy="84.5" r=".51" fill="#000080"/>
<circle cx="246.2" cy="84.5" r=".51" fill="none" stroke="#000080" stroke-width=".13"/>
<circle cx="246.2" cy="87.1" r=".51" fill="#000080"/>
<circle cx="246.2" cy="87.1" r=".51" fill="none" stroke="#000080" stroke-width=".13"/>
<circle cx="246.2" cy="89.6" r=".51" fill="#000080"/>
<circle cx="246.2" cy="89.6" r=".51" fill="none" stroke="#000080" stroke-width=".13"/>
<circle cx="246.2" cy="92.2" r=".51" fill="#000080"/>
<circle cx="246.2" cy="92.2" r=".51" fill="none" stroke="#000080" stroke-width=".13"/>
<circle cx="246.2" cy="94.7" r=".51" fill="#000080"/>
<circle cx="246.2" cy="94.7" r=".51" fill="none" stroke="#000080" stroke-width=".13"/>
<circle cx="246.2" cy="97.2" r=".51" fill="#000080"/>
<circle cx="246.2" cy="97.2" r=".51" fill="none" stroke="#000080" stroke-width=".13"/>
<circle cx="246.2" cy="99.8" r=".51" fill="#000080"/>
<circle cx="246.2" cy="99.8" r=".51" fill="none" stroke="#000080" stroke-width=".13"/>
<circle cx="246.2" cy="102.3" r=".51" fill="#000080"/>
<circle cx="246.2" cy="102.3" r=".51" fill="none" stroke="#000080" stroke-width=".13"/>
<circle cx="246.2" cy="104.9" r=".51" fill="#000080"/>
<circle cx="246.2" cy="104.9" r=".51" fill="none" stroke="#000080" stroke-width=".13"/>
<circle cx="246.2" cy="107.4" r=".51" fill="#000080"/>
<circle cx="246.2" cy="107.4" r=".51" fill="none" stroke="#000080" stroke-width=".13"/>
<circle cx="246.2" cy="109.9" r=".51" fill="#000080"/>
<circle cx="246.2" cy="109.9" r=".51" fill="none" stroke="#000080" stroke-width=".13"/>
<circle cx="246.2" cy="112.5" r=".51" fill="#000080"/>
<circle cx="246.2" cy="112.5" r=".51" fill="none" stroke="#000080" stroke-width=".13"/>
<circle cx="246.2" cy="115" r=".51" fill="#000080"/>
<circle cx="246.2" cy="115" r=".51" fill="none" stroke="#000080" stroke-width=".13"/>
<circle cx="246.2" cy="117.5" r=".51" fill="#000080"/>
<circle cx="246.2" cy="117.5" r=".51" fill="none" stroke="#000080" stroke-width=".13"/>
<circle cx="246.2" cy="120.1" r=".51" fill="#000080"/>
<circle cx="246.2" cy="120.1" r=".51" fill="none" stroke="#000080" stroke-width=".13"/>
<circle cx="246.2" cy="122.6" r=".51" fill="#000080"/>
<circle cx="246.2" cy="122.6" r=".51" fill="none" stroke="#000080" stroke-width=".13"/>
<circle cx="246.2" cy="125.2" r=".51" fill="#000080"/>
<circle cx="246.2" cy="125.2" r=".51" fill="none" stroke="#000080" stroke-width=".13"/>
<circle cx="246.2" cy="127.7" r=".51" fill="#000080"/>
<circle cx="246.2" cy="127.7" r=".51" fill="none" stroke="#000080" stroke-width=".13"/>
<circle cx="246.2" cy="130.2" r=".51" fill="#000080"/>
<circle cx="246.2" cy="130.2" r=".51" fill="none" stroke="#000080" stroke-width=".13"/>
<circle cx="246.2" cy="132.8" r=".51" fill="#000080"/>
<circle cx="246.2" cy="132.8" r=".51" fill="none" stroke="#000080" stroke-width=".13"/>
<circle cx="246.2" cy="135.3" r=".51" fill="#000080"/>
<circle cx="246.2" cy="135.3" r=".51" fill="none" stroke="#000080" stroke-width=".13"/>
<circle cx="246.2" cy="137.9" r=".51" fill="#000080"/>
<circle cx="246.2" cy="137.9" r=".51" fill="none" stroke="#000080" stroke-width=".13"/>
<circle cx="246.2" cy="140.4" r=".51" fill="#000080"/>
<circle cx="246.2" cy="140.4" r=".51" fill="none" stroke="#000080" stroke-width=".13"/>
<circle cx="246.2" cy="142.9" r=".51" fill="#000080"/>
<circle cx="246.2" cy="142.9" r=".51" fill="none" stroke="#000080" stroke-width=".13"/>
<circle cx="246.2" cy="145.5" r=".51" fill="#000080"/>
<circle cx="246.2" cy="145.5" r=".51" fill="none" stroke="#000080" stroke-width=".13"/>
<circle cx="246.2" cy="148" r=".51" fill="#000080"/>
<circle cx="246.2" cy="148" r=".51" fill="none" stroke="#000080" stroke-width=".13"/>
<circle cx="246.2" cy="150.6" r=".51" fill="#000080"/>
<circle cx="246.2" cy="150.6" r=".51" fill="none" stroke="#000080" stroke-width=".13"/>
<circle cx="246.2" cy="153.1" r=".51" fill="#000080"/>
<circle cx="246.2" cy="153.1" r=".51" fill="none" stroke="#000080" stroke-width=".13"/>
<circle cx="246.2" cy="155.6" r=".51" fill="#000080"/>
<circle cx="246.2" cy="155.6" r=".51" fill="none" stroke="#000080" stroke-width=".13"/>
<circle cx="246.2" cy="158.2" r=".51" fill="#000080"/>
<circle cx="246.2" cy="158.2" r=".51" fill="none" stroke="#000080" stroke-width=".13"/>
<circle cx="246.2" cy="160.7" r=".51" fill="#000080"/>
<circle cx="246.2" cy="160.7" r=".51" fill="none" stroke="#000080" stroke-width=".13"/>
<path d="M281.8 66.8v99" fill="none" stroke="#000080" stroke-width=".25"/>
<circle cx="281.8" cy="69.3" r=".51" fill="#000080"/>
<circle cx="281.8" cy="69.3" r=".51" fill="none" stroke="#000080" stroke-width=".13"/>
<circle cx="281.8" cy="71.8" r=".51" fill="#000080"/>
<circle cx="281.8" cy="71.8" r=".51" fill="none" stroke="#000080" stroke-width=".13"/>
<circle cx="281.8" cy="74.4" r=".51" fill="#000080"/>
<circle cx="281.8" cy="74.4" r=".51" fill="none" stroke="#000080" stroke-width=".13"/>
<circle cx="281.8" cy="76.9" r=".51" fill="#000080"/>
<circle cx="281.8" cy="76.9" r=".51" fill="none" stroke="#000080" stroke-width=".13"/>
<circle cx="281.8" cy="79.5" r=".51" fill="#000080"/>
<circle cx="281.8" cy="79.5" r=".51" fill="none" stroke="#000080" stroke-width=".13"/>
<circle cx="281.8" cy="82" r=".51" fill="#000080"/>
<circle cx="281.8" cy="82" r=".51" fill="none" stroke="#000080" stroke-width=".13"/>
<circle cx="281.8" cy="84.5" r=".51" fill="#000080"/>
<circle cx="281.8" cy="84.5" r=".51" fill="none" stroke="#000080" stroke-width=".13"/>
<circle cx="281.8" cy="87.1" r=".51" fill="#000080"/>
<circle cx="281.8" cy="87.1" r=".51" fill="none" stroke="#000080" stroke-width=".13"/>
<circle cx="281.8" cy="89.6" r=".51" fill="#000080"/>
<circle cx="281.8" cy="89.6" r=".51" fill="none" stroke="#000080" stroke-width=".13"/>
<circle cx="281.8" cy="92.2" r=".51" fill="#000080"/>
<circle cx="281.8" cy="92.2" r=".51" fill="none" stroke="#000080" stroke-width=".13"/>
<circle cx="281.8" cy="94.7" r=".51" fill="#000080"/>
<circle cx="281.8" cy="94.7" r=".51" fill="none" stroke="#000080" stroke-width=".13"/>
<circle cx="281.8" cy="97.2" r=".51" fill="#000080"/>
<circle cx="281.8" cy="97.2" r=".51" fill="none" stroke="#000080" stroke-width=".13"/>
<circle cx="281.8" cy="99.8" r=".51" fill="#000080"/>
<circle cx="281.8" cy="99.8" r=".51" fill="none" stroke="#000080" stroke-width=".13"/>
<circle cx="281.8" cy="102.3" r=".51" fill="#000080"/>
<circle cx="281.8" cy="102.3" r=".51" fill="none" stroke="#000080" stroke-width=".13"/>
<circle cx="281.8" cy="104.9" r=".51" fill="#000080"/>
<circle cx="281.8" cy="104.9" r=".51" fill="none" stroke="#000080" stroke-width=".13"/>
<circle cx="281.8" cy="107.4" r=".51" fill="#000080"/>
<circle cx="281.8" cy="107.4" r=".51" fill="none" stroke="#000080" stroke-width=".13"/>
<circle cx="281.8" cy="109.9" r=".51" fill="#000080"/>
<circle cx="281.8" cy="109.9" r=".51" fill="none" stroke="#000080" stroke-width=".13"/>
<circle cx="281.8" cy="112.5" r=".51" fill="#000080"/>
<circle cx="281.8" cy="112.5" r=".51" fill="none" stroke="#000080" stroke-width=".13"/>
<circle cx="281.8" cy="115" r=".51" fill="#000080"/>
<circle cx="281.8" cy="115" r=".51" fill="none" stroke="#000080" stroke-width=".13"/>
<circle cx="281.8" cy="117.5" r=".51" fill="#000080"/>
<circle cx="281.8" cy="117.5" r=".51" fill="none" stroke="#000080" stroke-width=".13"/>
<circle cx="281.8" cy="120.1" r=".51" fill="#000080"/>
<circle cx="281.8" cy="120.1" r=".51" fill="none" stroke="#000080" stroke-width=".13"/>
<circle cx="281.8" cy="122.6" r=".51" fill="#000080"/>
<circle cx="281.8" cy="122.6" r=".51" fill="none" stroke="#000080" stroke-width=".13"/>
<circle cx="281.8" cy="125.2" r=".51" fill="#000080"/>
<circle cx="281.8" cy="125.2" r=".51" fill="none" stroke="#000080" stroke-width=".13"/>
<circle cx="281.8" cy="127.7" r=".51" fill="#000080"/>
<circle cx="281.8" cy="127.7" r=".51" fill="none" stroke="#000080" stroke-width=".13"/>
<circle cx="281.8" cy="130.2" r=".51" fill="#000080"/>
<circle cx="281.8" cy="130.2" r=".51" fill="none" stroke="#000080" stroke-width=".13"/>
<circle cx="281.8" cy="132.8" r=".51" fill="#000080"/>
<circle cx="281.8" cy="132.8" r=".51" fill="none" stroke="#000080" stroke-width=".13"/>
<circle cx="281.8" cy="135.3" r=".51" fill="#000080"/>
<circle cx="281.8" cy="135.3" r=".51" fill="none" stroke="#000080" stroke-width=".13"/>
<circle cx="281.8" cy="137.9" r=".51" fill="#000080"/>
<circle cx="281.8" cy="137.9" r=".51" fill="none" stroke="#000080" stroke-width=".13"/>
<circle cx="281.8" cy="140.4" r=".51" fill="#000080"/>
<circle cx="281.8" cy="140.4" r=".51" fill="none" stroke="#000080" stroke-width=".13"/>
<circle cx="281.8" cy="142.9" r=".51" fill="#000080"/>
<circle cx="281.8" cy="142.9" r=".51" fill="none" stroke="#000080" stroke-width=".13"/>
<circle cx="281.8" cy="145.5" r=".51" fill="#000080"/>
<circle cx="281.8" cy="145.5" r=".51" fill="none" stroke="#000080" stroke-width=".13"/>
<circle cx="281.8" cy="148" r=".51" fill="#000080"/>
<circle cx="281.8" cy="148" r=".51" fill="none" stroke="#000080" stroke-width=".13"/>
<circle cx="281.8" cy="150.6" r=".51" fill="#000080"/>
<circle cx="281.8" cy="150.6" r=".51" fill="none" stroke="#000080" stroke-width=".13"/>
<circle cx="281.8" cy="153.1" r=".51" fill="#000080"/>
<circle cx="281.8" cy="153.1" r=".51" fill="none" stroke="#000080" stroke-width=".13"/>
<circle cx="281.8" cy="155.6" r=".51" fill="#000080"/>
<circle cx="281.8" cy="155.6" r=".51" fill="none" stroke="#000080" stroke-width=".13"/>
<circle cx="281.8" cy="158.2" r=".51" fill="#000080"/>
<circle cx="281.8" cy="158.2" r=".51" fill="none" stroke="#000080" stroke-width=".13"/>
<circle cx="281.8" cy="160.7" r=".51" fill="#000080"/>
<circle cx="281.8" cy="160.7" r=".51" fill="none" stroke="#000080" stroke-width=".13"/>
<path d="M246.2 64.2h-5.1v2.6M78.5 89.6v2.5h27.9v17.8" fill="none" stroke="#000080" stroke-width=".25"/>
<circle cx="106.4" cy="107.4" r=".51" fill="#000080"/>
<circle cx="106.4" cy="107.4" r=".51" fill="none" stroke="#000080" stroke-width=".13"/>
<circle cx="106.4" cy="104.8" r=".51" fill="#000080"/>
<circle cx="106.4" cy="104.8" r=".51" fill="none" stroke="#000080" stroke-width=".13"/>
<circle cx="96.3" cy="92.1" r=".51" fill="#000080"/>
<circle cx="96.3" cy="92.1" r=".51" fill="none" stroke="#000080" stroke-width=".13"/>
<circle cx="83.6" cy="92.1" r=".51" fill="#000080"/>
<circle cx="83.6" cy="92.1" r=".51" fill="none" stroke="#000080" stroke-width=".13"/>
<path d="M192.8 165.8h5.1M213.2 163.3v2.5h-5.1" fill="none" stroke="#000080" stroke-width=".25"/>
<circle cx="192.8" cy="165.8" r=".51" fill="#000080"/>
<circle cx="192.8" cy="165.8" r=".51" fill="none" stroke="#000080" stroke-width=".13"/>
<path d="M101.3 130.2v7.7" fill="none" stroke="#000080" stroke-width=".25"/>
<circle cx="101.3" cy="130.2" r=".51" fill="#000080"/>
<circle cx="101.3" cy="130.2" r=".51" fill="none" stroke="#000080" stroke-width=".13"/>
<path d="M101.3 115v2.5" fill="none" stroke="#000080" stroke-width=".25"/>
<circle cx="101.3" cy="115" r=".51" fill="#000080"/>
<circle cx="101.3" cy="115" r=".51" fill="none" stroke="#000080" stroke-width=".13"/>
<path d="M96.3 115v20.3h10.1" fill="none" stroke="#000080" stroke-width=".25"/>
<circle cx="96.3" cy="115" r=".51" fill="#000080"/>
<circle cx="96.3" cy="115" r=".51" fill="none" stroke="#000080" stroke-width=".13"/>
<path d="M101.3 127.7v2.5h5.1" fill="none" stroke="#000080" stroke-width=".25"/>
<circle cx="101.3" cy="130.2" r=".51" fill="#000080"/>
<circle cx="101.3" cy="130.2" r=".51" fill="none" stroke="#000080" stroke-width=".13"/>
<path d="M162.3 61.7v2.5" fill="none" stroke="#000080" stroke-width=".25"/>
<circle cx="162.3" cy="61.7" r=".51" fill="#000080"/>
<circle cx="162.3" cy="61.7" r=".51" fill="none" stroke="#000080" stroke-width=".13"/>
<path d="M109 49v10.1" fill="none" stroke="#000080" stroke-width=".25"/>
<circle cx="109" cy="59.1" r=".51" fill="#000080"/>
<circle cx="109" cy="59.1" r=".51" fill="none" stroke="#000080" stroke-width=".13"/>
<circle cx="109" cy="56.6" r=".51" fill="#000080"/>
<circle cx="109" cy="56.6" r=".51" fill="none" stroke="#000080" stroke-width=".13"/>
<circle cx="109" cy="54.1" r=".51" fill="#000080"/>
<circle cx="109" cy="54.1" r=".51" fill="none" stroke="#000080" stroke-width=".13"/>
<circle cx="109" cy="51.5" r=".51" fill="#000080"/>
<circle cx="109" cy="51.5" r=".51" fill="none" stroke="#000080" stroke-width=".13"/>
<path d="M231 28.7v2.5h-81.4v25.4" fill="none" stroke="#000080" stroke-width=".25"/>
<circle cx="149.6" cy="54.1" r=".51" fill="#000080"/>
<circle cx="149.6" cy="54.1" r=".51" fill="none" stroke="#000080" stroke-width=".13"/>
<circle cx="149.6" cy="51.5" r=".51" fill="#000080"/>
<circle cx="149.6" cy="51.5" r=".51" fill="none" stroke="#000080" stroke-width=".13"/>
<circle cx="149.6" cy="49" r=".51" fill="#000080"/>
<circle cx="149.6" cy="49" r=".51" fill="none" stroke="#000080" stroke-width=".13"/>
<circle cx="149.6" cy="46.4" r=".51" fill="#000080"/>
<circle cx="149.6" cy="46.4" r=".51" fill="none" stroke="#000080" stroke-width=".13"/>
<circle cx="149.6" cy="43.9" r=".51" fill="#000080"/>
<circle cx="149.6" cy="43.9" r=".51" fill="none" stroke="#000080" stroke-width=".13"/>
<circle cx="149.6" cy="41.4" r=".51" fill="#000080"/>
<circle cx="149.6" cy="41.4" r=".51" fill="none" stroke="#000080" stroke-width=".13"/>
<circle cx="162.3" cy="31.2" r=".51" fill="#000080"/>
<circle cx="162.3" cy="31.2" r=".51" fill="none" stroke="#000080" stroke-width=".13"/>
<circle cx="175.1" cy="31.2" r=".51" fill="#000080"/>
<circle cx="175.1" cy="31.2" r=".51" fill="none" stroke="#000080" stroke-width=".13"/>
<circle cx="187.8" cy="31.2" r=".51" fill="#000080"/>
<circle cx="187.8" cy="31.2" r=".51" fill="none" stroke="#000080" stroke-width=".13"/>
<circle cx="200.5" cy="31.2" r=".51" fill="#000080"/>
<circle cx="200.5" cy="31.2" r=".51" fill="none" stroke="#000080" stroke-width=".13"/>
<circle cx="213.2" cy="31.2" r=".51" fill="#000080"/>
<circle cx="213.2" cy="31.2" r=".51" fill="none" stroke="#000080" stroke-width=".13"/>
<circle cx="225.9" cy="31.2" r=".51" fill="#000080"/>
<circle cx="225.9" cy="31.2" r=".51" fill="none" stroke="#000080" stroke-width=".13"/>
<path d="M14.9 112.5v2.5h91.5v10.2" fill="none" stroke="#000080" stroke-width=".25"/>
<circle cx="106.4" cy="122.6" r=".51" fill="#000080"/>
<circle cx="106.4" cy="122.6" r=".51" fill="none" stroke="#000080" stroke-width=".13"/>
<circle cx="106.4" cy="120.1" r=".51" fill="#000080"/>
<circle cx="106.4" cy="120.1" r=".51" fill="none" stroke="#000080" stroke-width=".13"/>
<circle cx="106.4" cy="117.5" r=".51" fill="#000080"/>
<circle cx="106.4" cy="117.5" r=".51" fill="none" stroke="#000080" stroke-width=".13"/>
<circle cx="106.4" cy="115" r=".51" fill="#000080"/>
<circle cx="106.4" cy="115" r=".51" fill="none" stroke="#000080" stroke-width=".13"/>
<circle cx="101.3" cy="115" r=".51" fill="#000080"/>
<circle cx="101.3" cy="115" r=".51" fill="none" stroke="#000080" stroke-width=".13"/>
<circle cx="96.3" cy="115" r=".51" fill="#000080"/>
<circle cx="96.3" cy="115" r=".51" fill="none" stroke="#000080" stroke-width=".13"/>
<circle cx="83.6" cy="115" r=".51" fill="#000080"/>
<circle cx="83.6" cy="115" r=".51" fill="none" stroke="#000080" stroke-width=".13"/>
<circle cx="70.8" cy="115" r=".51" fill="#000080"/>
<circle cx="70.8" cy="115" r=".51" fill="none" stroke="#000080" stroke-width=".13"/>
<circle cx="58.1" cy="115" r=".51" fill="#000080"/>
<circle cx="58.1" cy="115" r=".51" fill="none" stroke="#000080" stroke-width=".13"/>
<circle cx="45.4" cy="115" r=".51" fill="#000080"/>
<circle cx="45.4" cy="115" r=".51" fill="none" stroke="#000080" stroke-width=".13"/>
<circle cx="32.7" cy="115" r=".51" fill="#000080"/>
<circle cx="32.7" cy="115" r=".51" fill="none" stroke="#000080" stroke-width=".13"/>
<circle cx="20" cy="115" r=".51" fill="#000080"/>
<circle cx="20" cy="115" r=".51" fill="none" stroke="#000080" stroke-width=".13"/>
<path d="M167.4 59.1v2.6h-17.8v2.5" fill="none" stroke="#000080" stroke-width=".25"/>
<circle cx="149.6" cy="61.7" r=".51" fill="#000080"/>
<circle cx="149.6" cy="61.7" r=".51" fill="none" stroke="#000080" stroke-width=".13"/>
<circle cx="162.3" cy="61.7" r=".51" fill="#000080"/>
<circle cx="162.3" cy="61.7" r=".51" fill="none" stroke="#000080" stroke-width=".13"/>
<use href="#words"/>
</svg>
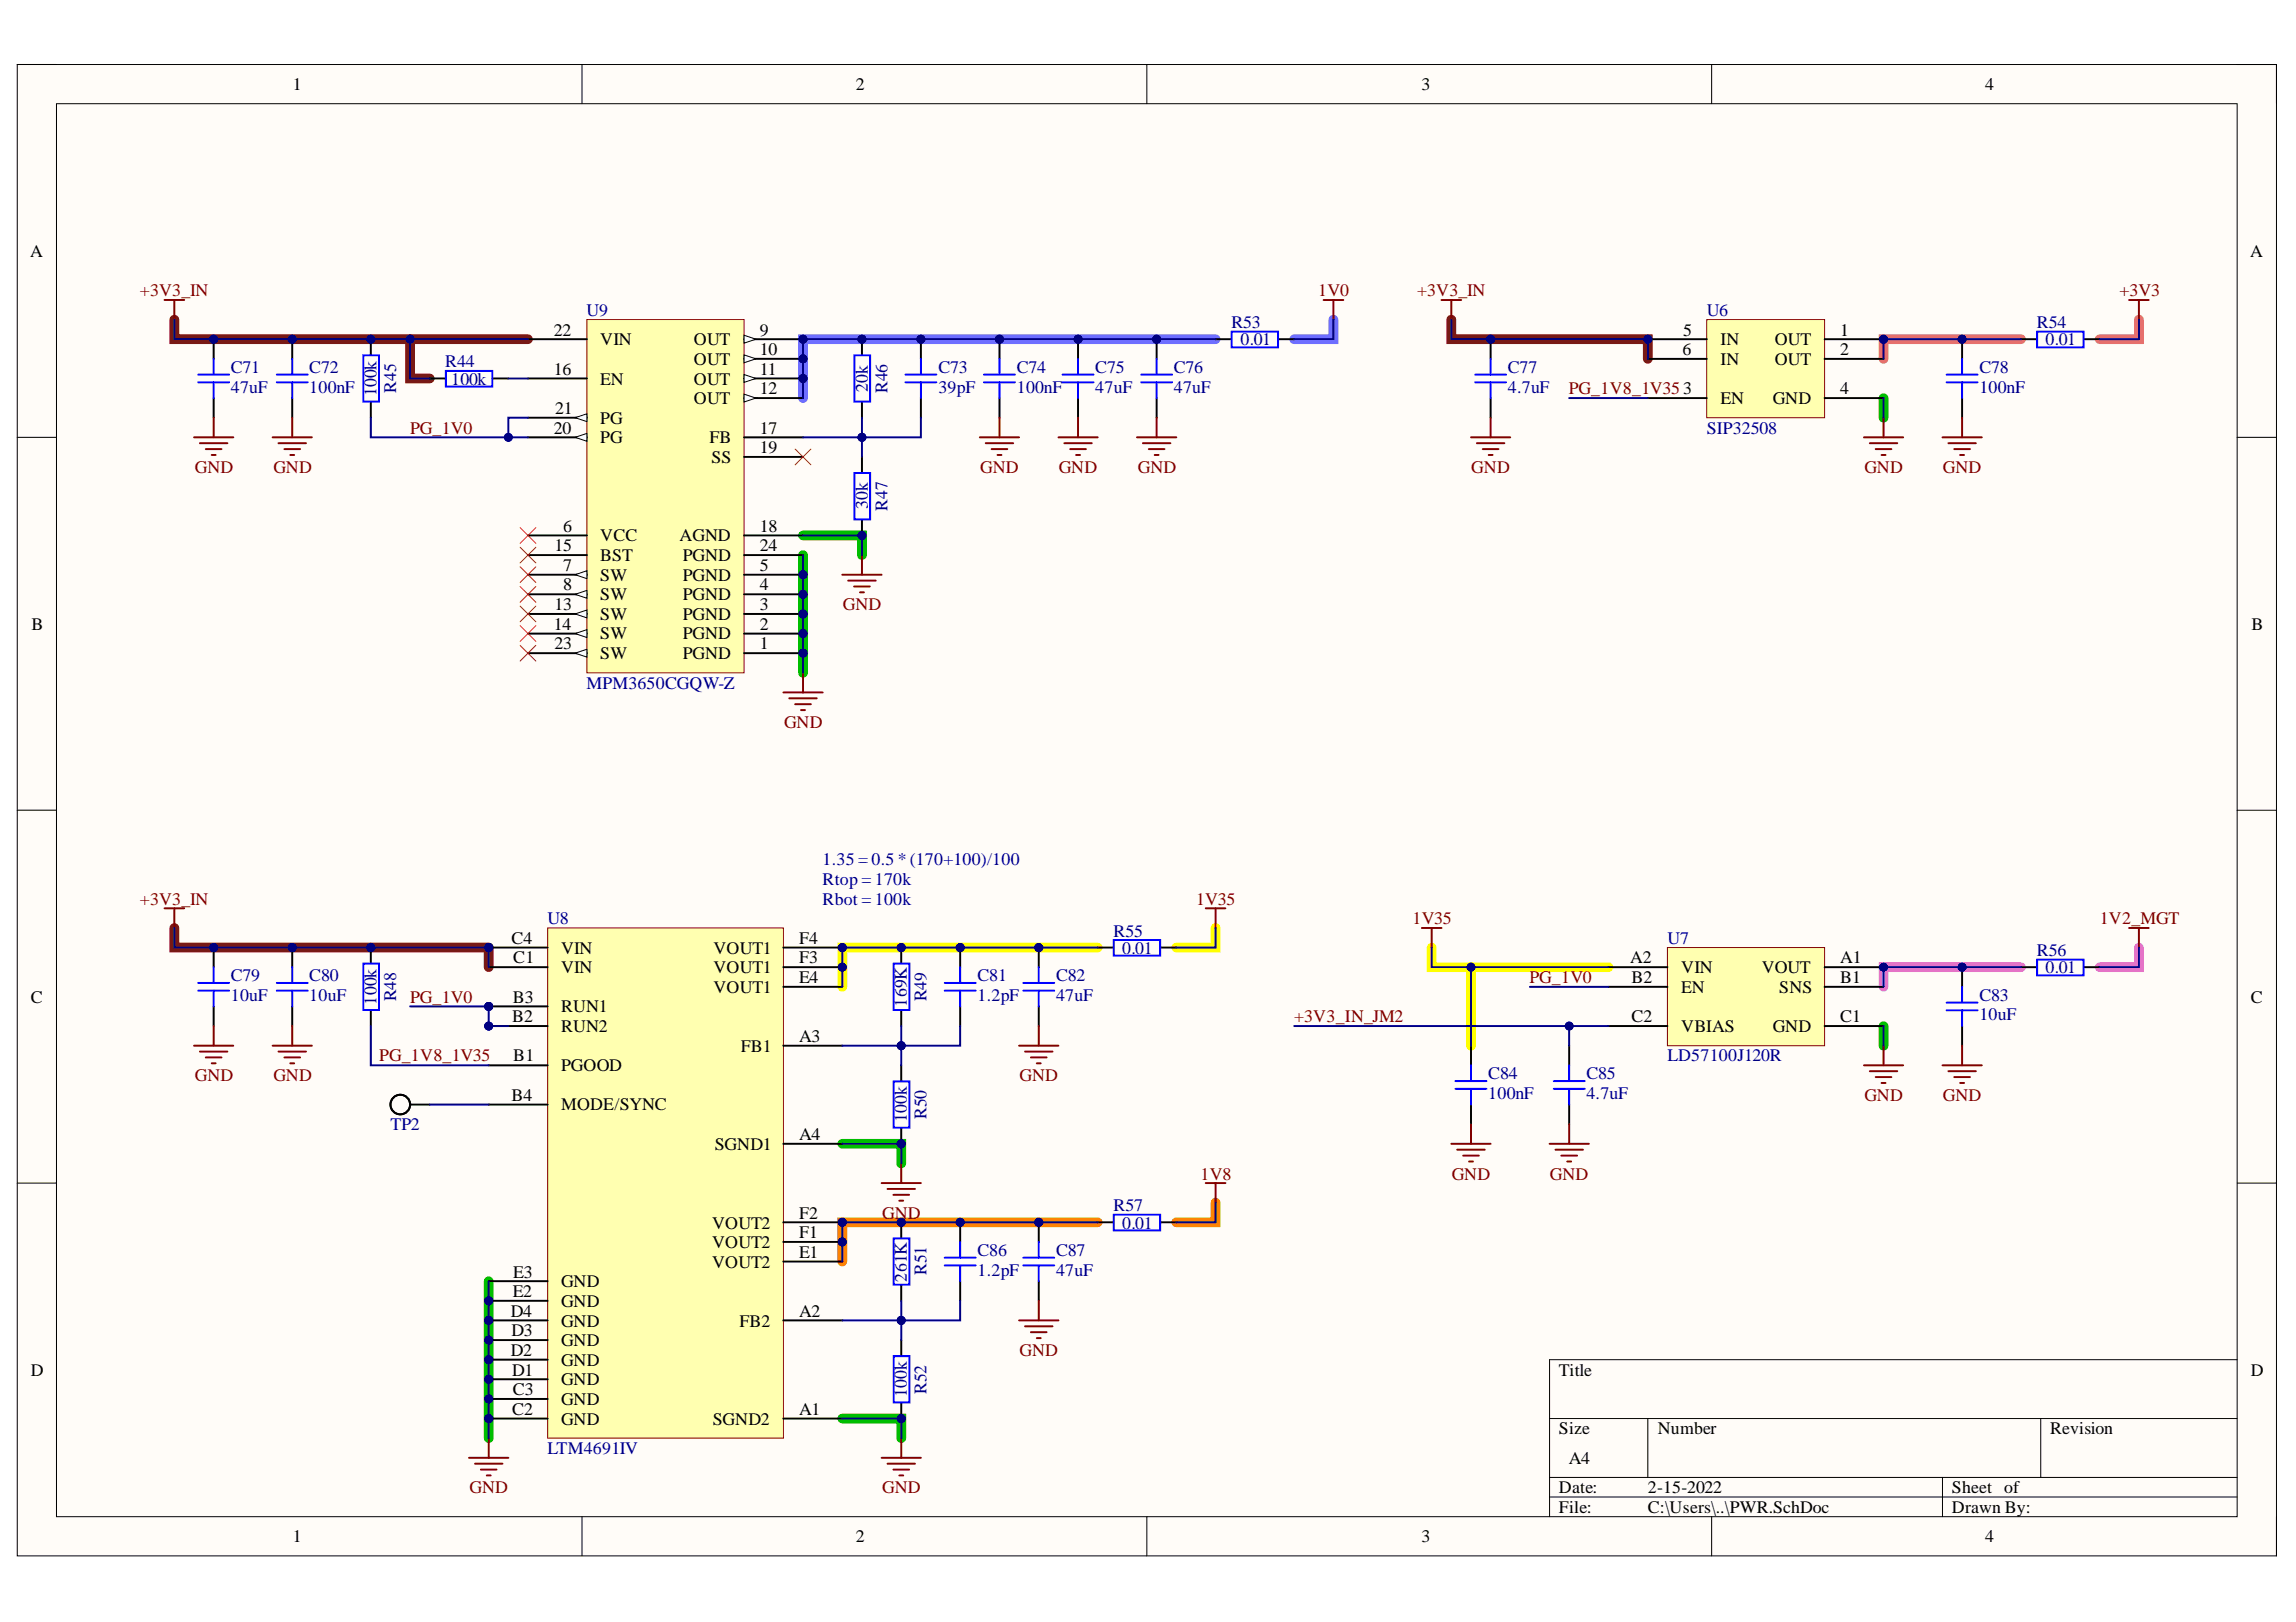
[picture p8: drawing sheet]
<svg xmlns="http://www.w3.org/2000/svg" width="297mm" height="210mm" viewBox="0 0 297 210" stroke-linecap="round" stroke-linejoin="round" font-family="sans-serif">
<defs><g id="words">
<g font-size="2.3">
<text x="37.9" y="11.7">1</text>
<text x="110.7" y="11.7">2</text>
<text x="183.9" y="11.7">3</text>
<text x="256.8" y="11.7">4</text>
<text x="3.9" y="33.3">A</text>
<text x="291.1" y="33.3">A</text>
<text x="71.7" y="43.4">22</text>
<text x="77.7" y="44.7">VIN</text>
<text x="89.8" y="44.7">OUT</text>
<text x="89.8" y="47.2">OUT</text>
<text x="98.3" y="43.4">9</text>
<text x="98.3" y="46">10</text>
<text x="217.7" y="46">6</text>
<text x="217.8" y="43.4">5</text>
<text x="222.6" y="44.7">IN</text>
<text x="222.6" y="47.2">IN</text>
<text x="229.6" y="44.7">OUT</text>
<text x="229.6" y="47.2">OUT</text>
<text x="238.1" y="43.4">1</text>
<text x="238.1" y="46">2</text>
<text x="71.7" y="48.5">16</text>
<text x="71.8" y="53.6">21</text>
<text x="77.7" y="49.8">EN</text>
<text x="89.8" y="49.8">OUT</text>
<text x="89.8" y="52.3">OUT</text>
<text x="98.3" y="48.5">11</text>
<text x="98.3" y="51">12</text>
<text x="217.8" y="51">3</text>
<text x="222.6" y="52.3">EN</text>
<text x="229.3" y="52.3">GND</text>
<text x="238.1" y="51">4</text>
<text x="71.7" y="56.1">20</text>
<text x="77.7" y="57.4">PG</text>
<text x="77.7" y="54.9">PG</text>
<text x="91.8" y="57.4">FB</text>
<text x="92" y="59.9">SS</text>
<text x="98.3" y="56.1">17</text>
<text x="98.3" y="58.7">19</text>
<text x="71.7" y="71.3">15</text>
<text x="72.8" y="68.8">6</text>
<text x="77.7" y="70.1">VCC</text>
<text x="87.9" y="70.1">AGND</text>
<text x="98.3" y="68.8">18</text>
<text x="98.3" y="71.3">24</text>
<text x="72.8" y="73.9">7</text>
<text x="72.8" y="76.4">8</text>
<text x="77.7" y="72.6">BST</text>
<text x="77.7" y="75.1">SW</text>
<text x="77.7" y="77.7">SW</text>
<text x="88.3" y="77.7">PGND</text>
<text x="88.3" y="75.1">PGND</text>
<text x="88.3" y="72.6">PGND</text>
<text x="98.3" y="76.4">4</text>
<text x="98.3" y="73.9">5</text>
<text x="4.1" y="81.5">B</text>
<text x="71.7" y="81.5">14</text>
<text x="71.7" y="78.9">13</text>
<text x="77.7" y="80.2">SW</text>
<text x="77.7" y="82.7">SW</text>
<text x="88.3" y="82.7">PGND</text>
<text x="88.3" y="80.2">PGND</text>
<text x="98.3" y="81.5">2</text>
<text x="98.3" y="78.9">3</text>
<text x="291.3" y="81.5">B</text>
<text x="71.7" y="84">23</text>
<text x="77.7" y="85.3">SW</text>
<text x="88.3" y="85.3">PGND</text>
<text x="98.3" y="84">1</text>
<text x="66.2" y="122.1">C4</text>
<text x="66.4" y="124.7">C1</text>
<text x="72.6" y="125.9">VIN</text>
<text x="72.6" y="123.4">VIN</text>
<text x="92.3" y="123.4">VOUT1</text>
<text x="92.3" y="125.9">VOUT1</text>
<text x="103.4" y="122.1">F4</text>
<text x="103.4" y="124.7">F3</text>
<text x="210.9" y="124.7">A2</text>
<text x="217.5" y="125.9">VIN</text>
<text x="227.9" y="125.9">VOUT</text>
<text x="238.1" y="124.7">A1</text>
<text x="4" y="129.7">C</text>
<text x="66.3" y="129.7">B3</text>
<text x="72.6" y="131">RUN1</text>
<text x="92.3" y="128.5">VOUT1</text>
<text x="103.4" y="127.2">E4</text>
<text x="211.1" y="127.2">B2</text>
<text x="217.5" y="128.5">EN</text>
<text x="230.2" y="128.5">SNS</text>
<text x="238.1" y="127.2">B1</text>
<text x="291.2" y="129.7">C</text>
<text x="66.2" y="132.3">B2</text>
<text x="66.4" y="137.4">B1</text>
<text x="72.6" y="133.6">RUN2</text>
<text x="95.9" y="136.1">FB1</text>
<text x="103.4" y="134.8">A3</text>
<text x="211.1" y="132.3">C2</text>
<text x="217.5" y="133.6">VBIAS</text>
<text x="229.3" y="133.6">GND</text>
<text x="238.1" y="132.3">C1</text>
<text x="66.2" y="142.4">B4</text>
<text x="72.6" y="138.6">PGOOD</text>
<text x="72.6" y="143.7">MODE/SYNC</text>
<text x="92.5" y="148.9">SGND1</text>
<text x="103.4" y="147.5">A4</text>
<text x="92.1" y="159">VOUT2</text>
<text x="92.1" y="161.5">VOUT2</text>
<text x="103.4" y="157.7">F2</text>
<text x="103.4" y="160.3">F1</text>
<text x="66.3" y="167.9">E2</text>
<text x="66.4" y="165.3">E3</text>
<text x="72.6" y="166.6">GND</text>
<text x="92.1" y="164.1">VOUT2</text>
<text x="103.4" y="162.8">E1</text>
<text x="66.1" y="170.4">D4</text>
<text x="66.2" y="172.9">D3</text>
<text x="72.6" y="171.7">GND</text>
<text x="72.6" y="169.1">GND</text>
<text x="95.7" y="171.7">FB2</text>
<text x="103.4" y="170.4">A2</text>
<text x="4" y="178">D</text>
<text x="66.1" y="175.5">D2</text>
<text x="66.2" y="178">D1</text>
<text x="72.6" y="179.3">GND</text>
<text x="72.6" y="176.7">GND</text>
<text x="72.6" y="174.2">GND</text>
<text x="201.7" y="178">Title</text>
<text x="291.2" y="178">D</text>
<text x="66.2" y="183.1">C2</text>
<text x="66.3" y="180.6">C3</text>
<text x="72.6" y="184.4">GND</text>
<text x="72.6" y="181.8">GND</text>
<text x="92.2" y="184.4">SGND2</text>
<text x="103.4" y="183.1">A1</text>
<text x="201.7" y="185.6">Size</text>
<text x="214.5" y="185.6">Number</text>
<text x="265.2" y="185.6">Revision</text>
<text x="203" y="189.4">A4</text>
<text x="201.7" y="193.2">Date:</text>
<text x="201.7" y="195.8">File:</text>
<text x="213.2" y="193.2">2-15-2022</text>
<text x="213.2" y="195.8">C:\Users\..\PWR.SchDoc</text>
<text x="252.5" y="193.2">Sheet of</text>
<text x="252.5" y="195.8">Drawn By:</text>
<text x="37.9" y="199.6">1</text>
<text x="110.7" y="199.6">2</text>
<text x="183.9" y="199.6">3</text>
<text x="256.8" y="199.6">4</text>
</g>
<g font-size="2.3" fill="#800000">
<text x="18.1" y="38.4">+3V3_IN</text>
<text x="170.6" y="38.4">1V0</text>
<text x="183.3" y="38.4">+3V3_IN</text>
<text x="274.2" y="38.4">+3V3</text>
<text x="203" y="51">PG_1V8_1V35</text>
<text x="53" y="56.1">PG_1V0</text>
<text x="25.2" y="61.2">GND</text>
<text x="35.4" y="61.2">GND</text>
<text x="126.8" y="61.2">GND</text>
<text x="137" y="61.2">GND</text>
<text x="147.2" y="61.2">GND</text>
<text x="190.3" y="61.2">GND</text>
<text x="241.2" y="61.2">GND</text>
<text x="251.3" y="61.2">GND</text>
<text x="109" y="78.9">GND</text>
<text x="101.4" y="94.2">GND</text>
<text x="18.1" y="117.1">+3V3_IN</text>
<text x="154.7" y="117.1">1V35</text>
<text x="182.7" y="119.6">1V35</text>
<text x="271.6" y="119.6">1V2_MGT</text>
<text x="53" y="129.7">PG_1V0</text>
<text x="197.9" y="127.2">PG_1V0</text>
<text x="49.1" y="137.4">PG_1V8_1V35</text>
<text x="167.4" y="132.3">+3V3_IN_JM2</text>
<text x="25.2" y="139.9">GND</text>
<text x="35.4" y="139.9">GND</text>
<text x="131.9" y="139.9">GND</text>
<text x="241.2" y="142.4">GND</text>
<text x="251.3" y="142.4">GND</text>
<text x="155.3" y="152.7">1V8</text>
<text x="187.8" y="152.7">GND</text>
<text x="200.5" y="152.7">GND</text>
<text x="114.1" y="157.7">GND</text>
<text x="131.9" y="175.5">GND</text>
<text x="60.7" y="193.2">GND</text>
<text x="114.1" y="193.2">GND</text>
</g>
<g font-size="2.3" fill="#000080">
<text x="75.9" y="40.9">U9</text>
<text x="220.8" y="40.9">U6</text>
<text x="57.6" y="47.5">R44</text>
<text x="159.3" y="42.4">R53</text>
<text x="160.5" y="44.7">0.01</text>
<text x="263.5" y="42.4">R54</text>
<text x="264.6" y="44.7">0.01</text>
<text x="29.9" y="48.3">C71</text>
<text x="29.9" y="50.8">47uF</text>
<text x="40" y="48.3">C72</text>
<text x="40" y="50.8">100nF</text>
<text x="48.7" y="51.3" transform="rotate(-90 48.7 51.3)">100k</text>
<text x="51.3" y="50.8" transform="rotate(-90 51.3 50.8)">R45</text>
<text x="58.4" y="49.8">100k</text>
<text x="112.3" y="50.7" transform="rotate(-90 112.3 50.7)">20k</text>
<text x="114.8" y="50.9" transform="rotate(-90 114.8 50.9)">R46</text>
<text x="121.4" y="48.3">C73</text>
<text x="121.4" y="50.8">39pF</text>
<text x="131.6" y="48.3">C74</text>
<text x="131.6" y="50.8">100nF</text>
<text x="141.7" y="48.3">C75</text>
<text x="141.7" y="50.8">47uF</text>
<text x="151.9" y="48.3">C76</text>
<text x="151.9" y="50.8">47uF</text>
<text x="195.1" y="48.3">C77</text>
<text x="195.1" y="50.8">4.7uF</text>
<text x="256.1" y="48.3">C78</text>
<text x="256.1" y="50.8">100nF</text>
<text x="220.8" y="56.1">SIP32508</text>
<text x="112.3" y="65.9" transform="rotate(-90 112.3 65.9)">30k</text>
<text x="114.8" y="66.1" transform="rotate(-90 114.8 66.1)">R47</text>
<text x="75.9" y="89.2">MPM3650CGQW-Z</text>
<text x="106.4" y="112">1.35 = 0.5 *(170+100)/100</text>
<text x="70.8" y="119.6">U8</text>
<text x="106.4" y="114.5">Rtop = 170k</text>
<text x="106.4" y="117.1">Rbot = 100k</text>
<text x="144.1" y="121.2">R55</text>
<text x="145.2" y="123.4">0.01</text>
<text x="215.7" y="122.1">U7</text>
<text x="263.5" y="123.7">R56</text>
<text x="264.6" y="125.9">0.01</text>
<text x="29.9" y="127">C79</text>
<text x="29.9" y="129.5">10uF</text>
<text x="40" y="127">C80</text>
<text x="40" y="129.5">10uF</text>
<text x="48.7" y="130" transform="rotate(-90 48.7 130)">100k</text>
<text x="51.3" y="129.6" transform="rotate(-90 51.3 129.6)">R48</text>
<text x="117.3" y="130.3" transform="rotate(-90 117.3 130.3)">169K</text>
<text x="119.9" y="129.6" transform="rotate(-90 119.9 129.6)">R49</text>
<text x="126.5" y="127">C81</text>
<text x="126.5" y="129.5">1.2pF</text>
<text x="136.6" y="127">C82</text>
<text x="136.6" y="129.5">47uF</text>
<text x="256.1" y="129.5">C83</text>
<text x="215.7" y="137.4">LD57100J120R</text>
<text x="256.1" y="132">10uF</text>
<text x="192.5" y="139.6">C84</text>
<text x="192.5" y="142.2">100nF</text>
<text x="205.2" y="139.6">C85</text>
<text x="205.2" y="142.2">4.7uF</text>
<text x="50.5" y="146.2">TP2</text>
<text x="117.3" y="145.2" transform="rotate(-90 117.3 145.2)">100k</text>
<text x="119.9" y="144.8" transform="rotate(-90 119.9 144.8)">R50</text>
<text x="144.1" y="156.7">R57</text>
<text x="145.2" y="159">0.01</text>
<text x="117.3" y="165.8" transform="rotate(-90 117.3 165.8)">261K</text>
<text x="119.9" y="165" transform="rotate(-90 119.9 165)">R51</text>
<text x="126.5" y="162.5">C86</text>
<text x="126.5" y="165.1">1.2pF</text>
<text x="136.6" y="162.5">C87</text>
<text x="136.6" y="165.1">47uF</text>
<text x="117.3" y="180.8" transform="rotate(-90 117.3 180.8)">100k</text>
<text x="119.9" y="180.4" transform="rotate(-90 119.9 180.4)">R52</text>
<text x="70.8" y="188.2">LTM4691IV</text>
</g>
</g></defs>
<path d="M2.2 8.3h292.3v193h-292.3z" fill-rule="evenodd" fill="#fffcf8"/>
<path d="M2.2 8.3h292.3v193h-292.3z" fill="none" stroke="#000" stroke-width=".13"/>
<path d="M7.3 13.4h282.1v182.9h-282.1z" fill-rule="evenodd" fill="#fffcf8"/>
<g fill="none" stroke="#000" stroke-width=".13">
<path d="M2.2 8.3h5.1M7.3 13.4h282.1v182.9h-282.1zM75.3 8.3v5.1M148.4 8.3v5.1M221.4 8.3v5.1M289.4 8.3h5.1v5.1M2.2 56.6h5.1M289.4 56.6h5.1M2.2 104.8h5.1M289.4 104.9h5.1M2.2 153.1h5.1M289.4 153.1h5.1"/>
<path d="M289.4 176h-88.9v20.3M75.3 196.3v5M148.4 196.3v5M200.5 183.6h88.9M200.5 191.2h88.9M200.5 193.7h88.9M213.2 183.6v7.6M221.4 196.3v5M251.3 191.2v5.1M264 183.6v7.6M294.5 196.3v5"/>
</g>
<path d="M142 122.6h-33v5.1M157.3 120.1v2.5h-5.1M185.2 122.6v2.6h22.9M190.3 125.2v10.1" fill="none" stroke="#ff0" stroke-width="1.3"/>
<path d="M22.6 41.4v2.5h45.7M53.1 43.9v5.1h2.5M187.8 41.4v2.5h25.4v2.5M22.6 120.1v2.5h40.6v2.6" fill="none" stroke="#781915" stroke-width="1.3"/>
<path d="M243.7 51.5v2.6M103.9 71.8v15.3M103.9 69.3h7.6v2.5M243.7 132.8v2.5M109 148h7.6v2.6M63.2 165.8v20.3M109 183.6h7.6v2.5" fill="none" stroke="#00be00" stroke-width="1.3"/>
<path d="M157.3 43.9h-53.4v7.6M172.5 41.4v2.5h-5.1" fill="none" stroke="#6e6eff" stroke-width="1.3"/>
<path d="M142 158.2h-33v5.1M157.3 155.6v2.6h-5.1" fill="none" stroke="#fd8300" stroke-width="1.3"/>
<path d="M261.5 125.2h-17.8v2.5M276.7 122.6v2.6h-5.1" fill="none" stroke="#ff6eff" stroke-width="1.3"/>
<path d="M261.5 43.9h-17.8v2.5M276.7 41.4v2.5h-5.1" fill="none" stroke="#ff6e6e" stroke-width="1.3"/>
<circle cx="243.7" cy="43.9" r=".51" fill="#000080"/>
<circle cx="243.7" cy="43.9" r=".51" fill="none" stroke="#000080" stroke-width=".13"/>
<circle cx="213.2" cy="43.9" r=".51" fill="#000080"/>
<circle cx="213.2" cy="43.9" r=".51" fill="none" stroke="#000080" stroke-width=".13"/>
<path d="M220.8 41.4h15.3v12.7h-15.3z" fill-rule="evenodd" fill="#ffffb0"/>
<path d="M220.8 41.4h15.3v12.7h-15.3z" fill="none" stroke="#800000" stroke-width=".13"/>
<path d="M236.1 43.9h7.6" fill="none" stroke="#000" stroke-width=".25"/>
<circle cx="243.7" cy="43.9" r=".51" fill="#000080"/>
<circle cx="243.7" cy="43.9" r=".51" fill="none" stroke="#000080" stroke-width=".13"/>
<path d="M213.2 51.5h7.6M213.2 43.9h7.6M236.1 46.4h7.6M236.1 51.5h7.6" fill="none" stroke="#000" stroke-width=".25"/>
<circle cx="213.2" cy="43.9" r=".51" fill="#000080"/>
<circle cx="213.2" cy="43.9" r=".51" fill="none" stroke="#000080" stroke-width=".13"/>
<path d="M213.2 46.4h7.6" fill="none" stroke="#000" stroke-width=".25"/>
<path d="M21.3 38.8h2.5M22.6 38.8v2.6M171.2 38.8h2.6M172.5 38.8v2.6M275.4 38.8h2.6M276.7 38.8v2.6M275.4 120.1h2.6M276.7 120.1v2.5" fill="none" stroke="#800000" stroke-width=".25"/>
<circle cx="243.7" cy="125.2" r=".51" fill="#000080"/>
<circle cx="243.7" cy="125.2" r=".51" fill="none" stroke="#000080" stroke-width=".13"/>
<path d="M215.7 122.6h20.4v12.7h-20.4z" fill-rule="evenodd" fill="#ffffb0"/>
<path d="M215.7 122.6h20.4v12.7h-20.4z" fill="none" stroke="#800000" stroke-width=".13"/>
<path d="M236.1 125.2h7.6" fill="none" stroke="#000" stroke-width=".25"/>
<circle cx="243.7" cy="125.2" r=".51" fill="#000080"/>
<circle cx="243.7" cy="125.2" r=".51" fill="none" stroke="#000080" stroke-width=".13"/>
<path d="M208.1 125.2h7.6M208.1 127.7h7.6M208.1 132.8h7.6M236.1 127.7h7.6M236.1 132.8h7.6" fill="none" stroke="#000" stroke-width=".25"/>
<circle cx="103.9" cy="43.9" r=".51" fill="#000080"/>
<circle cx="103.9" cy="43.9" r=".51" fill="none" stroke="#000080" stroke-width=".13"/>
<circle cx="103.9" cy="46.4" r=".51" fill="#000080"/>
<circle cx="103.9" cy="46.4" r=".51" fill="none" stroke="#000080" stroke-width=".13"/>
<circle cx="103.9" cy="49" r=".51" fill="#000080"/>
<circle cx="103.9" cy="49" r=".51" fill="none" stroke="#000080" stroke-width=".13"/>
<circle cx="103.9" cy="84.5" r=".51" fill="#000080"/>
<circle cx="103.9" cy="84.5" r=".51" fill="none" stroke="#000080" stroke-width=".13"/>
<circle cx="103.9" cy="82" r=".51" fill="#000080"/>
<circle cx="103.9" cy="82" r=".51" fill="none" stroke="#000080" stroke-width=".13"/>
<circle cx="103.9" cy="79.5" r=".51" fill="#000080"/>
<circle cx="103.9" cy="79.5" r=".51" fill="none" stroke="#000080" stroke-width=".13"/>
<circle cx="103.9" cy="76.9" r=".51" fill="#000080"/>
<circle cx="103.9" cy="76.9" r=".51" fill="none" stroke="#000080" stroke-width=".13"/>
<circle cx="103.9" cy="74.4" r=".51" fill="#000080"/>
<circle cx="103.9" cy="74.4" r=".51" fill="none" stroke="#000080" stroke-width=".13"/>
<path d="M75.9 41.4h20.4v45.7h-20.4z" fill-rule="evenodd" fill="#ffffb0"/>
<path d="M75.9 41.4h20.4v45.7h-20.4z" fill="none" stroke="#800000" stroke-width=".13"/>
<path d="M68.3 49h7.6M96.3 56.6h7.6M96.3 59.1h7.6M96.3 43.9h7.6M68.3 71.8h7.6" fill="none" stroke="#000" stroke-width=".25"/>
<path d="M96.3 43.4l1.5 .5-1.5 .5z" fill="#f8fcff"/>
<path d="M96.3 43.4l1.5 .5-1.5 .5z" fill="none" stroke="#000" stroke-width=".13"/>
<circle cx="103.9" cy="43.9" r=".51" fill="#000080"/>
<circle cx="103.9" cy="43.9" r=".51" fill="none" stroke="#000080" stroke-width=".13"/>
<path d="M96.3 46.4h7.6" fill="none" stroke="#000" stroke-width=".25"/>
<path d="M96.3 45.9l1.5 .5-1.5 .5z" fill="#f8fcff"/>
<path d="M96.3 45.9l1.5 .5-1.5 .5z" fill="none" stroke="#000" stroke-width=".13"/>
<circle cx="103.9" cy="46.4" r=".51" fill="#000080"/>
<circle cx="103.9" cy="46.4" r=".51" fill="none" stroke="#000080" stroke-width=".13"/>
<path d="M96.3 49h7.6" fill="none" stroke="#000" stroke-width=".25"/>
<path d="M96.3 48.5l1.5 .5-1.5 .5z" fill="#f8fcff"/>
<path d="M96.3 48.5l1.5 .5-1.5 .5z" fill="none" stroke="#000" stroke-width=".13"/>
<circle cx="103.9" cy="49" r=".51" fill="#000080"/>
<circle cx="103.9" cy="49" r=".51" fill="none" stroke="#000080" stroke-width=".13"/>
<path d="M96.3 51.5h7.6" fill="none" stroke="#000" stroke-width=".25"/>
<path d="M96.3 51l1.5 .5-1.5 .5z" fill="#f8fcff"/>
<path d="M96.3 51l1.5 .5-1.5 .5z" fill="none" stroke="#000" stroke-width=".13"/>
<path d="M68.3 56.6h7.6" fill="none" stroke="#000" stroke-width=".25"/>
<path d="M74.4 56.6l1.5-.5v1z" fill="#f8fcff"/>
<path d="M74.4 56.6l1.5-.5v1z" fill="none" stroke="#000" stroke-width=".13"/>
<path d="M68.3 54.1h7.6" fill="none" stroke="#000" stroke-width=".25"/>
<path d="M74.4 54.1l1.5-.6v1.1z" fill="#f8fcff"/>
<path d="M74.4 54.1l1.5-.6v1.1z" fill="none" stroke="#000" stroke-width=".13"/>
<path d="M68.3 74.4h7.6" fill="none" stroke="#000" stroke-width=".25"/>
<path d="M74.4 74.4l1.5-.5v1z" fill="#f8fcff"/>
<path d="M74.4 74.4l1.5-.5v1z" fill="none" stroke="#000" stroke-width=".13"/>
<path d="M68.3 76.9h7.6" fill="none" stroke="#000" stroke-width=".25"/>
<path d="M74.4 76.9l1.5-.5v1z" fill="#f8fcff"/>
<path d="M74.4 76.9l1.5-.5v1z" fill="none" stroke="#000" stroke-width=".13"/>
<path d="M68.3 79.5h7.6" fill="none" stroke="#000" stroke-width=".25"/>
<path d="M74.4 79.5l1.5-.6v1.1z" fill="#f8fcff"/>
<path d="M74.4 79.5l1.5-.6v1.1z" fill="none" stroke="#000" stroke-width=".13"/>
<path d="M68.3 82h7.6" fill="none" stroke="#000" stroke-width=".25"/>
<path d="M74.4 82l1.5-.5v1z" fill="#f8fcff"/>
<path d="M74.4 82l1.5-.5v1z" fill="none" stroke="#000" stroke-width=".13"/>
<path d="M68.3 84.5h7.6" fill="none" stroke="#000" stroke-width=".25"/>
<path d="M74.4 84.5l1.5-.5v1z" fill="#f8fcff"/>
<path d="M74.4 84.5l1.5-.5v1z" fill="none" stroke="#000" stroke-width=".13"/>
<path d="M68.3 43.9h7.6M68.3 69.3h7.6M96.3 69.3h7.6M96.3 84.5h7.6" fill="none" stroke="#000" stroke-width=".25"/>
<circle cx="103.9" cy="84.5" r=".51" fill="#000080"/>
<circle cx="103.9" cy="84.5" r=".51" fill="none" stroke="#000080" stroke-width=".13"/>
<path d="M96.3 82h7.6" fill="none" stroke="#000" stroke-width=".25"/>
<circle cx="103.9" cy="82" r=".51" fill="#000080"/>
<circle cx="103.9" cy="82" r=".51" fill="none" stroke="#000080" stroke-width=".13"/>
<path d="M96.3 79.5h7.6" fill="none" stroke="#000" stroke-width=".25"/>
<circle cx="103.9" cy="79.5" r=".51" fill="#000080"/>
<circle cx="103.9" cy="79.5" r=".51" fill="none" stroke="#000080" stroke-width=".13"/>
<path d="M96.3 76.9h7.6" fill="none" stroke="#000" stroke-width=".25"/>
<circle cx="103.9" cy="76.9" r=".51" fill="#000080"/>
<circle cx="103.9" cy="76.9" r=".51" fill="none" stroke="#000080" stroke-width=".13"/>
<path d="M96.3 74.4h7.6" fill="none" stroke="#000" stroke-width=".25"/>
<circle cx="103.9" cy="74.4" r=".51" fill="#000080"/>
<circle cx="103.9" cy="74.4" r=".51" fill="none" stroke="#000080" stroke-width=".13"/>
<path d="M55.6 49h2M63.8 49h2M96.3 71.8h7.6" fill="none" stroke="#000" stroke-width=".25"/>
<g fill="none" stroke="#800000" stroke-width=".25">
<path d="M186.5 38.8h2.5M187.8 38.8v2.6M241.1 56.6h5.1M241.9 57.4h3.6M242.7 58.1h2M243.4 58.9h.5M243.7 54.1v2.5M101.3 89.6h5.1M102.1 90.4h3.6M102.9 91.1h2M103.6 91.9h.5M103.9 87.1v2.5"/>
<path d="M184 120.1h2.5M185.2 120.1v2.5M241.1 137.9h5.1M241.9 138.6h3.6M242.7 139.4h2M243.7 135.3v2.6M243.4 140.1h.5"/>
</g>
<g fill="none" stroke="#f00" stroke-width=".13">
<path d="M102.9 58.1l2 2.1M104.9 58.1l-2 2.1M67.3 68.3l2 2M67.3 70.8l2 2M67.3 73.4l2 2M67.3 75.9l2 2M67.3 78.4l2 2.1M69.3 68.3l-2 2M69.3 70.8l-2 2M69.3 73.4l-2 2M69.3 75.9l-2 2M69.3 78.4l-2 2.1"/>
<path d="M67.3 81l2 2M67.3 83.5l2 2M69.3 81l-2 2M69.3 83.5l-2 2"/>
</g>
<path d="M57.7 48h6v2h-6z" fill="none" stroke="#00f" stroke-width=".25"/>
<circle cx="48" cy="43.9" r=".51" fill="#000080"/>
<circle cx="48" cy="43.9" r=".51" fill="none" stroke="#000080" stroke-width=".13"/>
<path d="M48 43.9v2" fill="none" stroke="#000" stroke-width=".25"/>
<circle cx="48" cy="43.9" r=".51" fill="#000080"/>
<circle cx="48" cy="43.9" r=".51" fill="none" stroke="#000080" stroke-width=".13"/>
<path d="M48 52.1v2" fill="none" stroke="#000" stroke-width=".25"/>
<path d="M47 46h2v6h-2z" fill="none" stroke="#00f" stroke-width=".25"/>
<path d="M109 74.4h5.1M109.7 75.1h3.6M110.5 75.9h2M111.3 76.7h.5M111.5 71.8v2.6" fill="none" stroke="#800000" stroke-width=".25"/>
<circle cx="27.6" cy="43.9" r=".51" fill="#000080"/>
<circle cx="27.6" cy="43.9" r=".51" fill="none" stroke="#000080" stroke-width=".13"/>
<path d="M27.6 43.9v2.5M27.6 51.5v2.6" fill="none" stroke="#000" stroke-width=".25"/>
<circle cx="27.6" cy="43.9" r=".51" fill="#000080"/>
<circle cx="27.6" cy="43.9" r=".51" fill="none" stroke="#000080" stroke-width=".13"/>
<path d="M25.6 49.5h4M25.6 48.5h4M27.6 46.4v2.1M27.6 49.5v2" fill="none" stroke="#00f" stroke-width=".25"/>
<circle cx="37.8" cy="43.9" r=".51" fill="#000080"/>
<circle cx="37.8" cy="43.9" r=".51" fill="none" stroke="#000080" stroke-width=".13"/>
<path d="M37.8 43.9v2.5M37.8 51.5v2.6" fill="none" stroke="#000" stroke-width=".25"/>
<circle cx="37.8" cy="43.9" r=".51" fill="#000080"/>
<circle cx="37.8" cy="43.9" r=".51" fill="none" stroke="#000080" stroke-width=".13"/>
<path d="M35.8 49.5h4M35.8 48.5h4M37.8 46.4v2.1M37.8 49.5v2" fill="none" stroke="#00f" stroke-width=".25"/>
<path d="M25.1 56.6h5.1M25.9 57.4h3.5M26.6 58.1h2.1M27.4 58.9h.5M27.6 54.1v2.5M35.3 56.6h5M36 57.4h3.6M36.8 58.1h2M37.6 58.9h.5M37.8 54.1v2.5" fill="none" stroke="#800000" stroke-width=".25"/>
<circle cx="139.5" cy="43.9" r=".51" fill="#000080"/>
<circle cx="139.5" cy="43.9" r=".51" fill="none" stroke="#000080" stroke-width=".13"/>
<path d="M139.5 43.9v2.5M139.5 51.5v2.6" fill="none" stroke="#000" stroke-width=".25"/>
<circle cx="139.5" cy="43.9" r=".51" fill="#000080"/>
<circle cx="139.5" cy="43.9" r=".51" fill="none" stroke="#000080" stroke-width=".13"/>
<path d="M137.5 49.5h4M137.5 48.5h4M139.5 46.4v2.1M139.5 49.5v2" fill="none" stroke="#00f" stroke-width=".25"/>
<circle cx="149.6" cy="43.9" r=".51" fill="#000080"/>
<circle cx="149.6" cy="43.9" r=".51" fill="none" stroke="#000080" stroke-width=".13"/>
<path d="M149.6 43.9v2.5M149.6 51.5v2.6" fill="none" stroke="#000" stroke-width=".25"/>
<circle cx="149.6" cy="43.9" r=".51" fill="#000080"/>
<circle cx="149.6" cy="43.9" r=".51" fill="none" stroke="#000080" stroke-width=".13"/>
<path d="M147.6 49.5h4M147.6 48.5h4M149.6 46.4v2.1M149.6 49.5v2" fill="none" stroke="#00f" stroke-width=".25"/>
<circle cx="129.3" cy="43.9" r=".51" fill="#000080"/>
<circle cx="129.3" cy="43.9" r=".51" fill="none" stroke="#000080" stroke-width=".13"/>
<path d="M129.3 43.9v2.5M129.3 51.5v2.6" fill="none" stroke="#000" stroke-width=".25"/>
<circle cx="129.3" cy="43.9" r=".51" fill="#000080"/>
<circle cx="129.3" cy="43.9" r=".51" fill="none" stroke="#000080" stroke-width=".13"/>
<path d="M127.3 49.5h4M127.3 48.5h4M129.3 46.4v2.1M129.3 49.5v2" fill="none" stroke="#00f" stroke-width=".25"/>
<g fill="none" stroke="#800000" stroke-width=".25">
<path d="M126.8 56.6h5M127.5 57.4h3.6M128.3 58.1h2M129.1 58.9h.5M129.3 54.1v2.5M136.9 56.6h5.1M137.7 57.4h3.5M138.5 58.1h2M139.2 58.9h.5M139.5 54.1v2.5M147.1 56.6h5.1M147.9 57.4h3.5"/>
<path d="M148.6 58.1h2.1M149.4 58.9h.5M149.6 54.1v2.5M21.3 117.5h2.5M22.6 117.5v2.6M156 117.5h2.5M157.3 117.5v2.6M156 153.1h2.5M157.3 153.1v2.5M60.7 188.7h5.1M61.5 189.4h3.5M62.2 190.2h2"/>
<path d="M63 190.9h.5M63.2 186.1v2.6"/>
</g>
<circle cx="48" cy="122.6" r=".51" fill="#000080"/>
<circle cx="48" cy="122.6" r=".51" fill="none" stroke="#000080" stroke-width=".13"/>
<path d="M48 122.6v2" fill="none" stroke="#000" stroke-width=".25"/>
<circle cx="48" cy="122.6" r=".51" fill="#000080"/>
<circle cx="48" cy="122.6" r=".51" fill="none" stroke="#000080" stroke-width=".13"/>
<g fill="none" stroke="#000" stroke-width=".25">
<path d="M48 130.8v2M53.1 142.9h2.5"/>
<circle cx="51.8" cy="142.9" r="1.27"/>
</g>
<path d="M47 124.7h2v6h-2z" fill="none" stroke="#00f" stroke-width=".25"/>
<path d="M114.1 153.1h5M114.8 153.9h3.6M115.6 154.6h2M116.3 155.4h.5M116.6 150.6v2.5M114.1 188.7h5M114.8 189.4h3.6M115.6 190.2h2M116.3 190.9h.6M116.6 186.1v2.6" fill="none" stroke="#800000" stroke-width=".25"/>
<circle cx="116.6" cy="148" r=".51" fill="#000080"/>
<circle cx="116.6" cy="148" r=".51" fill="none" stroke="#000080" stroke-width=".13"/>
<path d="M116.6 137.9v2M116.6 146v2" fill="none" stroke="#000" stroke-width=".25"/>
<circle cx="116.6" cy="148" r=".51" fill="#000080"/>
<circle cx="116.6" cy="148" r=".51" fill="none" stroke="#000080" stroke-width=".13"/>
<path d="M115.6 139.9h2.1v6h-2.1z" fill="none" stroke="#00f" stroke-width=".25"/>
<circle cx="116.6" cy="183.6" r=".51" fill="#000080"/>
<circle cx="116.6" cy="183.6" r=".51" fill="none" stroke="#000080" stroke-width=".13"/>
<path d="M116.6 173.4v2M116.6 181.6v2" fill="none" stroke="#000" stroke-width=".25"/>
<circle cx="116.6" cy="183.6" r=".51" fill="#000080"/>
<circle cx="116.6" cy="183.6" r=".51" fill="none" stroke="#000080" stroke-width=".13"/>
<path d="M115.6 175.5h2.1v6h-2.1z" fill="none" stroke="#00f" stroke-width=".25"/>
<circle cx="63.2" cy="132.8" r=".51" fill="#000080"/>
<circle cx="63.2" cy="132.8" r=".51" fill="none" stroke="#000080" stroke-width=".13"/>
<circle cx="63.2" cy="178.5" r=".51" fill="#000080"/>
<circle cx="63.2" cy="178.5" r=".51" fill="none" stroke="#000080" stroke-width=".13"/>
<circle cx="63.2" cy="176" r=".51" fill="#000080"/>
<circle cx="63.2" cy="176" r=".51" fill="none" stroke="#000080" stroke-width=".13"/>
<circle cx="63.2" cy="173.4" r=".51" fill="#000080"/>
<circle cx="63.2" cy="173.4" r=".51" fill="none" stroke="#000080" stroke-width=".13"/>
<circle cx="63.2" cy="170.9" r=".51" fill="#000080"/>
<circle cx="63.2" cy="170.9" r=".51" fill="none" stroke="#000080" stroke-width=".13"/>
<circle cx="63.2" cy="168.3" r=".51" fill="#000080"/>
<circle cx="63.2" cy="168.3" r=".51" fill="none" stroke="#000080" stroke-width=".13"/>
<circle cx="109" cy="122.6" r=".51" fill="#000080"/>
<circle cx="109" cy="122.6" r=".51" fill="none" stroke="#000080" stroke-width=".13"/>
<circle cx="109" cy="125.2" r=".51" fill="#000080"/>
<circle cx="109" cy="125.2" r=".51" fill="none" stroke="#000080" stroke-width=".13"/>
<circle cx="109" cy="158.2" r=".51" fill="#000080"/>
<circle cx="109" cy="158.2" r=".51" fill="none" stroke="#000080" stroke-width=".13"/>
<circle cx="109" cy="160.7" r=".51" fill="#000080"/>
<circle cx="109" cy="160.7" r=".51" fill="none" stroke="#000080" stroke-width=".13"/>
<circle cx="63.2" cy="130.2" r=".51" fill="#000080"/>
<circle cx="63.2" cy="130.2" r=".51" fill="none" stroke="#000080" stroke-width=".13"/>
<circle cx="63.2" cy="183.6" r=".51" fill="#000080"/>
<circle cx="63.2" cy="183.6" r=".51" fill="none" stroke="#000080" stroke-width=".13"/>
<circle cx="63.2" cy="181" r=".51" fill="#000080"/>
<circle cx="63.2" cy="181" r=".51" fill="none" stroke="#000080" stroke-width=".13"/>
<circle cx="63.2" cy="122.6" r=".51" fill="#000080"/>
<circle cx="63.2" cy="122.6" r=".51" fill="none" stroke="#000080" stroke-width=".13"/>
<path d="M70.9 120.1h30.5v66h-30.5z" fill-rule="evenodd" fill="#ffffb0"/>
<path d="M70.9 120.1h30.5v66h-30.5z" fill="none" stroke="#800000" stroke-width=".13"/>
<path d="M63.2 137.9h7.6M63.2 132.8h7.6M101.3 135.3h7.7M101.3 148h7.7M101.3 170.9h7.7M101.4 183.6h7.6" fill="none" stroke="#000" stroke-width=".25"/>
<circle cx="63.2" cy="132.8" r=".51" fill="#000080"/>
<circle cx="63.2" cy="132.8" r=".51" fill="none" stroke="#000080" stroke-width=".13"/>
<path d="M63.2 178.5h7.7" fill="none" stroke="#000" stroke-width=".25"/>
<circle cx="63.2" cy="178.5" r=".51" fill="#000080"/>
<circle cx="63.2" cy="178.5" r=".51" fill="none" stroke="#000080" stroke-width=".13"/>
<path d="M63.2 176h7.7" fill="none" stroke="#000" stroke-width=".25"/>
<circle cx="63.2" cy="176" r=".51" fill="#000080"/>
<circle cx="63.2" cy="176" r=".51" fill="none" stroke="#000080" stroke-width=".13"/>
<path d="M63.2 173.4h7.7" fill="none" stroke="#000" stroke-width=".25"/>
<circle cx="63.2" cy="173.4" r=".51" fill="#000080"/>
<circle cx="63.2" cy="173.4" r=".51" fill="none" stroke="#000080" stroke-width=".13"/>
<path d="M63.2 170.9h7.6" fill="none" stroke="#000" stroke-width=".25"/>
<circle cx="63.2" cy="170.9" r=".51" fill="#000080"/>
<circle cx="63.2" cy="170.9" r=".51" fill="none" stroke="#000080" stroke-width=".13"/>
<path d="M63.2 168.3h7.6M101.3 163.3h7.7" fill="none" stroke="#000" stroke-width=".25"/>
<circle cx="63.2" cy="168.3" r=".51" fill="#000080"/>
<circle cx="63.2" cy="168.3" r=".51" fill="none" stroke="#000080" stroke-width=".13"/>
<path d="M101.3 122.6h7.7" fill="none" stroke="#000" stroke-width=".25"/>
<circle cx="109" cy="122.6" r=".51" fill="#000080"/>
<circle cx="109" cy="122.6" r=".51" fill="none" stroke="#000080" stroke-width=".13"/>
<path d="M101.3 125.2h7.7" fill="none" stroke="#000" stroke-width=".25"/>
<circle cx="109" cy="125.2" r=".51" fill="#000080"/>
<circle cx="109" cy="125.2" r=".51" fill="none" stroke="#000080" stroke-width=".13"/>
<path d="M101.3 158.2h7.7" fill="none" stroke="#000" stroke-width=".25"/>
<circle cx="109" cy="158.2" r=".51" fill="#000080"/>
<circle cx="109" cy="158.2" r=".51" fill="none" stroke="#000080" stroke-width=".13"/>
<path d="M101.3 160.7h7.7" fill="none" stroke="#000" stroke-width=".25"/>
<circle cx="109" cy="160.7" r=".51" fill="#000080"/>
<circle cx="109" cy="160.7" r=".51" fill="none" stroke="#000080" stroke-width=".13"/>
<path d="M63.2 130.2h7.6M101.3 127.7h7.7M63.2 165.8h7.6" fill="none" stroke="#000" stroke-width=".25"/>
<circle cx="63.2" cy="130.2" r=".51" fill="#000080"/>
<circle cx="63.2" cy="130.2" r=".51" fill="none" stroke="#000080" stroke-width=".13"/>
<path d="M63.2 125.2h7.6M63.2 142.9h7.6M63.2 183.6h7.7" fill="none" stroke="#000" stroke-width=".25"/>
<circle cx="63.2" cy="183.6" r=".51" fill="#000080"/>
<circle cx="63.2" cy="183.6" r=".51" fill="none" stroke="#000080" stroke-width=".13"/>
<path d="M63.2 181h7.7" fill="none" stroke="#000" stroke-width=".25"/>
<circle cx="63.2" cy="181" r=".51" fill="#000080"/>
<circle cx="63.2" cy="181" r=".51" fill="none" stroke="#000080" stroke-width=".13"/>
<path d="M63.2 122.6h7.6" fill="none" stroke="#000" stroke-width=".25"/>
<circle cx="63.2" cy="122.6" r=".51" fill="#000080"/>
<circle cx="63.2" cy="122.6" r=".51" fill="none" stroke="#000080" stroke-width=".13"/>
<circle cx="192.8" cy="43.9" r=".51" fill="#000080"/>
<circle cx="192.8" cy="43.9" r=".51" fill="none" stroke="#000080" stroke-width=".13"/>
<path d="M192.8 43.9v2.5M192.8 51.5v2.6" fill="none" stroke="#000" stroke-width=".25"/>
<circle cx="192.8" cy="43.9" r=".51" fill="#000080"/>
<circle cx="192.8" cy="43.9" r=".51" fill="none" stroke="#000080" stroke-width=".13"/>
<path d="M190.8 49.5h4M190.8 48.5h4M192.8 46.4v2.1M192.8 49.5v2" fill="none" stroke="#00f" stroke-width=".25"/>
<path d="M190.3 56.6h5.1M191.1 57.4h3.5M191.8 58.1h2.1M192.6 58.9h.5M192.8 54.1v2.5" fill="none" stroke="#800000" stroke-width=".25"/>
<circle cx="253.8" cy="43.9" r=".51" fill="#000080"/>
<circle cx="253.8" cy="43.9" r=".51" fill="none" stroke="#000080" stroke-width=".13"/>
<path d="M253.8 43.9v2.5M253.8 51.5v2.6" fill="none" stroke="#000" stroke-width=".25"/>
<circle cx="253.8" cy="43.9" r=".51" fill="#000080"/>
<circle cx="253.8" cy="43.9" r=".51" fill="none" stroke="#000080" stroke-width=".13"/>
<path d="M251.8 49.5h4M251.8 48.5h4M253.8 46.4v2.1M253.8 49.5v2M201 139.9h4M203 137.9v2M201 140.9h4M203 140.9v2" fill="none" stroke="#00f" stroke-width=".25"/>
<path d="M251.3 56.6h5.1M252.1 57.4h3.5M252.8 58.1h2.1M253.6 58.9h.5M253.8 54.1v2.5M200.5 148h5.1M201.2 148.8h3.6M202 149.5h2M202.8 150.3h.5M203 145.5v2.5" fill="none" stroke="#800000" stroke-width=".25"/>
<path d="M203 135.3v2.6M203 142.9v2.6" fill="none" stroke="#000" stroke-width=".25"/>
<circle cx="253.8" cy="125.2" r=".51" fill="#000080"/>
<circle cx="253.8" cy="125.2" r=".51" fill="none" stroke="#000080" stroke-width=".13"/>
<path d="M253.8 125.2v2.5M253.8 132.8v2.5" fill="none" stroke="#000" stroke-width=".25"/>
<circle cx="253.8" cy="125.2" r=".51" fill="#000080"/>
<circle cx="253.8" cy="125.2" r=".51" fill="none" stroke="#000080" stroke-width=".13"/>
<path d="M188.3 139.9h4M190.3 137.9v2M251.8 130.7h4M251.8 129.7h4M253.8 127.7v2M253.8 130.7v2.1M188.3 140.9h4M190.3 140.9v2" fill="none" stroke="#00f" stroke-width=".25"/>
<path d="M251.3 137.9h5.1M252.1 138.6h3.5M252.8 139.4h2.1M253.8 135.3v2.6M187.8 148h5M188.5 148.8h3.6M189.3 149.5h2M190.1 150.3h.5M190.3 145.5v2.5M253.6 140.1h.5" fill="none" stroke="#800000" stroke-width=".25"/>
<path d="M190.3 135.3v2.6M190.3 142.9v2.6" fill="none" stroke="#000" stroke-width=".25"/>
<circle cx="124.2" cy="122.6" r=".51" fill="#000080"/>
<circle cx="124.2" cy="122.6" r=".51" fill="none" stroke="#000080" stroke-width=".13"/>
<path d="M124.2 122.6v2.6M124.2 130.2v2.6" fill="none" stroke="#000" stroke-width=".25"/>
<circle cx="124.2" cy="122.6" r=".51" fill="#000080"/>
<circle cx="124.2" cy="122.6" r=".51" fill="none" stroke="#000080" stroke-width=".13"/>
<path d="M122.2 128.2h4M122.2 127.2h4M124.2 125.2v2M124.2 128.2v2" fill="none" stroke="#00f" stroke-width=".25"/>
<circle cx="124.2" cy="158.2" r=".51" fill="#000080"/>
<circle cx="124.2" cy="158.2" r=".51" fill="none" stroke="#000080" stroke-width=".13"/>
<path d="M124.2 158.2v2.5M124.2 165.8v2.5" fill="none" stroke="#000" stroke-width=".25"/>
<circle cx="124.2" cy="158.2" r=".51" fill="#000080"/>
<circle cx="124.2" cy="158.2" r=".51" fill="none" stroke="#000080" stroke-width=".13"/>
<path d="M122.2 163.8h4M122.2 162.8h4M124.2 160.7v2.1M124.2 163.8v2" fill="none" stroke="#00f" stroke-width=".25"/>
<circle cx="116.6" cy="158.2" r=".51" fill="#000080"/>
<circle cx="116.6" cy="158.2" r=".51" fill="none" stroke="#000080" stroke-width=".13"/>
<path d="M116.6 158.2v2" fill="none" stroke="#000" stroke-width=".25"/>
<circle cx="116.6" cy="158.2" r=".51" fill="#000080"/>
<circle cx="116.6" cy="158.2" r=".51" fill="none" stroke="#000080" stroke-width=".13"/>
<path d="M116.6 166.3v2" fill="none" stroke="#000" stroke-width=".25"/>
<path d="M115.6 160.3h2.1v6h-2.1z" fill="none" stroke="#00f" stroke-width=".25"/>
<circle cx="116.6" cy="122.6" r=".51" fill="#000080"/>
<circle cx="116.6" cy="122.6" r=".51" fill="none" stroke="#000080" stroke-width=".13"/>
<path d="M116.6 122.6v2" fill="none" stroke="#000" stroke-width=".25"/>
<circle cx="116.6" cy="122.6" r=".51" fill="#000080"/>
<circle cx="116.6" cy="122.6" r=".51" fill="none" stroke="#000080" stroke-width=".13"/>
<path d="M116.6 130.8v2" fill="none" stroke="#000" stroke-width=".25"/>
<path d="M115.6 124.7h2.1v6h-2.1z" fill="none" stroke="#00f" stroke-width=".25"/>
<circle cx="119.1" cy="43.9" r=".51" fill="#000080"/>
<circle cx="119.1" cy="43.9" r=".51" fill="none" stroke="#000080" stroke-width=".13"/>
<path d="M119.1 43.9v2.5M119.1 51.5v2.6" fill="none" stroke="#000" stroke-width=".25"/>
<circle cx="119.1" cy="43.9" r=".51" fill="#000080"/>
<circle cx="119.1" cy="43.9" r=".51" fill="none" stroke="#000080" stroke-width=".13"/>
<path d="M117.1 49.5h4M117.1 48.5h4M119.1 46.4v2.1M119.1 49.5v2" fill="none" stroke="#00f" stroke-width=".25"/>
<circle cx="111.5" cy="43.9" r=".51" fill="#000080"/>
<circle cx="111.5" cy="43.9" r=".51" fill="none" stroke="#000080" stroke-width=".13"/>
<path d="M111.5 43.9v2" fill="none" stroke="#000" stroke-width=".25"/>
<circle cx="111.5" cy="43.9" r=".51" fill="#000080"/>
<circle cx="111.5" cy="43.9" r=".51" fill="none" stroke="#000080" stroke-width=".13"/>
<path d="M111.5 52.1v2" fill="none" stroke="#000" stroke-width=".25"/>
<path d="M110.5 46h2.1v6h-2.1z" fill="none" stroke="#00f" stroke-width=".25"/>
<circle cx="111.5" cy="69.3" r=".51" fill="#000080"/>
<circle cx="111.5" cy="69.3" r=".51" fill="none" stroke="#000080" stroke-width=".13"/>
<path d="M111.5 59.1v2M111.5 67.3v2" fill="none" stroke="#000" stroke-width=".25"/>
<circle cx="111.5" cy="69.3" r=".51" fill="#000080"/>
<circle cx="111.5" cy="69.3" r=".51" fill="none" stroke="#000080" stroke-width=".13"/>
<path d="M110.5 61.2h2.1v6h-2.1z" fill="none" stroke="#00f" stroke-width=".25"/>
<circle cx="134.4" cy="122.6" r=".51" fill="#000080"/>
<circle cx="134.4" cy="122.6" r=".51" fill="none" stroke="#000080" stroke-width=".13"/>
<path d="M134.4 122.6v2.6M134.4 130.2v2.6" fill="none" stroke="#000" stroke-width=".25"/>
<circle cx="134.4" cy="122.6" r=".51" fill="#000080"/>
<circle cx="134.4" cy="122.6" r=".51" fill="none" stroke="#000080" stroke-width=".13"/>
<path d="M132.4 128.2h4M132.4 127.2h4M134.4 125.2v2M134.4 128.2v2" fill="none" stroke="#00f" stroke-width=".25"/>
<path d="M131.8 135.3h5.1M132.6 136.1h3.6M133.4 136.8h2M134.1 137.6h.5M134.4 132.8v2.5" fill="none" stroke="#800000" stroke-width=".25"/>
<circle cx="134.4" cy="158.2" r=".51" fill="#000080"/>
<circle cx="134.4" cy="158.2" r=".51" fill="none" stroke="#000080" stroke-width=".13"/>
<path d="M134.4 158.2v2.5M134.4 165.8v2.5" fill="none" stroke="#000" stroke-width=".25"/>
<circle cx="134.4" cy="158.2" r=".51" fill="#000080"/>
<circle cx="134.4" cy="158.2" r=".51" fill="none" stroke="#000080" stroke-width=".13"/>
<path d="M132.4 163.8h4M132.4 162.8h4M134.4 160.7v2.1M134.4 163.8v2" fill="none" stroke="#00f" stroke-width=".25"/>
<path d="M131.8 170.9h5.1M132.6 171.6h3.6M133.4 172.4h2M134.1 173.2h.5M134.4 168.3v2.6" fill="none" stroke="#800000" stroke-width=".25"/>
<circle cx="27.6" cy="122.6" r=".51" fill="#000080"/>
<circle cx="27.6" cy="122.6" r=".51" fill="none" stroke="#000080" stroke-width=".13"/>
<path d="M27.6 122.6v2.6M27.6 130.2v2.6" fill="none" stroke="#000" stroke-width=".25"/>
<circle cx="27.6" cy="122.6" r=".51" fill="#000080"/>
<circle cx="27.6" cy="122.6" r=".51" fill="none" stroke="#000080" stroke-width=".13"/>
<path d="M25.6 128.2h4M25.6 127.2h4M27.6 125.2v2M27.6 128.2v2" fill="none" stroke="#00f" stroke-width=".25"/>
<circle cx="37.8" cy="122.6" r=".51" fill="#000080"/>
<circle cx="37.8" cy="122.6" r=".51" fill="none" stroke="#000080" stroke-width=".13"/>
<path d="M37.8 122.6v2.6M37.8 130.2v2.6" fill="none" stroke="#000" stroke-width=".25"/>
<circle cx="37.8" cy="122.6" r=".51" fill="#000080"/>
<circle cx="37.8" cy="122.6" r=".51" fill="none" stroke="#000080" stroke-width=".13"/>
<path d="M159.3 42.9h6v2.1h-6zM263.5 42.9h6.1v2.1h-6.1zM35.8 128.2h4M35.8 127.2h4M37.8 125.2v2M37.8 128.2v2M144.1 121.6h6v2.1h-6zM263.5 124.2h6.1v2h-6.1zM144.1 157.2h6v2h-6z" fill="none" stroke="#00f" stroke-width=".25"/>
<path d="M25.1 135.3h5.1M25.9 136.1h3.5M26.6 136.8h2.1M27.4 137.6h.5M27.6 132.8v2.5M35.3 135.3h5M36 136.1h3.6M36.8 136.8h2M37.6 137.6h.5M37.8 132.8v2.5" fill="none" stroke="#800000" stroke-width=".25"/>
<path d="M157.3 43.9h2M165.4 43.9h2M261.5 43.9h2M269.6 43.9h2M142 122.6h2M150.2 122.6h2M261.5 125.2h2M269.6 125.2h2M142 158.2h2M150.2 158.2h2" fill="none" stroke="#000" stroke-width=".25"/>
<path d="M185.2 122.6v2.6h22.9" fill="none" stroke="#000080" stroke-width=".25"/>
<circle cx="190.3" cy="125.2" r=".51" fill="#000080"/>
<circle cx="190.3" cy="125.2" r=".51" fill="none" stroke="#000080" stroke-width=".13"/>
<path d="M187.8 41.4v2.5h25.4v2.5" fill="none" stroke="#000080" stroke-width=".25"/>
<circle cx="213.2" cy="43.9" r=".51" fill="#000080"/>
<circle cx="213.2" cy="43.9" r=".51" fill="none" stroke="#000080" stroke-width=".13"/>
<circle cx="192.8" cy="43.9" r=".51" fill="#000080"/>
<circle cx="192.8" cy="43.9" r=".51" fill="none" stroke="#000080" stroke-width=".13"/>
<path d="M103.9 71.8v15.3" fill="none" stroke="#000080" stroke-width=".25"/>
<circle cx="103.9" cy="74.4" r=".51" fill="#000080"/>
<circle cx="103.9" cy="74.4" r=".51" fill="none" stroke="#000080" stroke-width=".13"/>
<circle cx="103.9" cy="76.9" r=".51" fill="#000080"/>
<circle cx="103.9" cy="76.9" r=".51" fill="none" stroke="#000080" stroke-width=".13"/>
<circle cx="103.9" cy="79.5" r=".51" fill="#000080"/>
<circle cx="103.9" cy="79.5" r=".51" fill="none" stroke="#000080" stroke-width=".13"/>
<circle cx="103.9" cy="82" r=".51" fill="#000080"/>
<circle cx="103.9" cy="82" r=".51" fill="none" stroke="#000080" stroke-width=".13"/>
<circle cx="103.9" cy="84.5" r=".51" fill="#000080"/>
<circle cx="103.9" cy="84.5" r=".51" fill="none" stroke="#000080" stroke-width=".13"/>
<path d="M53.1 43.9v5.1h2.5M65.8 49h2.5M243.7 51.5v2.6M243.7 132.8v2.5" fill="none" stroke="#000080" stroke-width=".25"/>
<circle cx="53.1" cy="43.9" r=".51" fill="#000080"/>
<circle cx="53.1" cy="43.9" r=".51" fill="none" stroke="#000080" stroke-width=".13"/>
<path d="M68.3 54.1h-2.5v2.5" fill="none" stroke="#000080" stroke-width=".25"/>
<circle cx="65.8" cy="56.6" r=".51" fill="#000080"/>
<circle cx="65.8" cy="56.6" r=".51" fill="none" stroke="#000080" stroke-width=".13"/>
<path d="M103.9 56.6h7.6v2.5" fill="none" stroke="#000080" stroke-width=".25"/>
<circle cx="111.5" cy="56.6" r=".51" fill="#000080"/>
<circle cx="111.5" cy="56.6" r=".51" fill="none" stroke="#000080" stroke-width=".13"/>
<path d="M111.5 54.1v2.5" fill="none" stroke="#000080" stroke-width=".25"/>
<circle cx="111.5" cy="56.6" r=".51" fill="#000080"/>
<circle cx="111.5" cy="56.6" r=".51" fill="none" stroke="#000080" stroke-width=".13"/>
<path d="M119.1 54.1v2.5h-7.6" fill="none" stroke="#000080" stroke-width=".25"/>
<circle cx="111.5" cy="56.6" r=".51" fill="#000080"/>
<circle cx="111.5" cy="56.6" r=".51" fill="none" stroke="#000080" stroke-width=".13"/>
<path d="M103.9 69.3h7.6v2.5" fill="none" stroke="#000080" stroke-width=".25"/>
<circle cx="111.5" cy="69.3" r=".51" fill="#000080"/>
<circle cx="111.5" cy="69.3" r=".51" fill="none" stroke="#000080" stroke-width=".13"/>
<path d="M63.2 165.8v20.3" fill="none" stroke="#000080" stroke-width=".25"/>
<circle cx="63.2" cy="168.3" r=".51" fill="#000080"/>
<circle cx="63.2" cy="168.3" r=".51" fill="none" stroke="#000080" stroke-width=".13"/>
<circle cx="63.2" cy="170.9" r=".51" fill="#000080"/>
<circle cx="63.2" cy="170.9" r=".51" fill="none" stroke="#000080" stroke-width=".13"/>
<circle cx="63.2" cy="173.4" r=".51" fill="#000080"/>
<circle cx="63.2" cy="173.4" r=".51" fill="none" stroke="#000080" stroke-width=".13"/>
<circle cx="63.2" cy="176" r=".51" fill="#000080"/>
<circle cx="63.2" cy="176" r=".51" fill="none" stroke="#000080" stroke-width=".13"/>
<circle cx="63.2" cy="178.5" r=".51" fill="#000080"/>
<circle cx="63.2" cy="178.5" r=".51" fill="none" stroke="#000080" stroke-width=".13"/>
<circle cx="63.2" cy="181" r=".51" fill="#000080"/>
<circle cx="63.2" cy="181" r=".51" fill="none" stroke="#000080" stroke-width=".13"/>
<circle cx="63.2" cy="183.6" r=".51" fill="#000080"/>
<circle cx="63.2" cy="183.6" r=".51" fill="none" stroke="#000080" stroke-width=".13"/>
<path d="M22.6 41.4v2.5h45.7" fill="none" stroke="#000080" stroke-width=".25"/>
<circle cx="27.6" cy="43.9" r=".51" fill="#000080"/>
<circle cx="27.6" cy="43.9" r=".51" fill="none" stroke="#000080" stroke-width=".13"/>
<circle cx="37.8" cy="43.9" r=".51" fill="#000080"/>
<circle cx="37.8" cy="43.9" r=".51" fill="none" stroke="#000080" stroke-width=".13"/>
<circle cx="48" cy="43.9" r=".51" fill="#000080"/>
<circle cx="48" cy="43.9" r=".51" fill="none" stroke="#000080" stroke-width=".13"/>
<circle cx="53.1" cy="43.9" r=".51" fill="#000080"/>
<circle cx="53.1" cy="43.9" r=".51" fill="none" stroke="#000080" stroke-width=".13"/>
<path d="M48 54.1v2.5h20.3" fill="none" stroke="#000080" stroke-width=".25"/>
<circle cx="65.8" cy="56.6" r=".51" fill="#000080"/>
<circle cx="65.8" cy="56.6" r=".51" fill="none" stroke="#000080" stroke-width=".13"/>
<path d="M203 51.5h10.2M48 132.8v5.1h15.2M53.1 130.2h10.1M197.9 127.7h10.2M55.6 142.9h7.6" fill="none" stroke="#000080" stroke-width=".25"/>
<circle cx="63.2" cy="130.2" r=".51" fill="#000080"/>
<circle cx="63.2" cy="130.2" r=".51" fill="none" stroke="#000080" stroke-width=".13"/>
<path d="M109 183.6h7.6v2.5" fill="none" stroke="#000080" stroke-width=".25"/>
<circle cx="116.6" cy="183.6" r=".51" fill="#000080"/>
<circle cx="116.6" cy="183.6" r=".51" fill="none" stroke="#000080" stroke-width=".13"/>
<path d="M109 148h7.6v2.6" fill="none" stroke="#000080" stroke-width=".25"/>
<circle cx="116.6" cy="148" r=".51" fill="#000080"/>
<circle cx="116.6" cy="148" r=".51" fill="none" stroke="#000080" stroke-width=".13"/>
<path d="M116.6 132.8v5.1" fill="none" stroke="#000080" stroke-width=".25"/>
<circle cx="116.6" cy="135.3" r=".51" fill="#000080"/>
<circle cx="116.6" cy="135.3" r=".51" fill="none" stroke="#000080" stroke-width=".13"/>
<path d="M109 135.3h7.6" fill="none" stroke="#000080" stroke-width=".25"/>
<circle cx="116.6" cy="135.3" r=".51" fill="#000080"/>
<circle cx="116.6" cy="135.3" r=".51" fill="none" stroke="#000080" stroke-width=".13"/>
<path d="M116.6 168.3v5.1" fill="none" stroke="#000080" stroke-width=".25"/>
<circle cx="116.6" cy="170.9" r=".51" fill="#000080"/>
<circle cx="116.6" cy="170.9" r=".51" fill="none" stroke="#000080" stroke-width=".13"/>
<path d="M109 170.9h7.6" fill="none" stroke="#000080" stroke-width=".25"/>
<circle cx="116.6" cy="170.9" r=".51" fill="#000080"/>
<circle cx="116.6" cy="170.9" r=".51" fill="none" stroke="#000080" stroke-width=".13"/>
<path d="M124.2 132.8v2.5h-7.6" fill="none" stroke="#000080" stroke-width=".25"/>
<circle cx="116.6" cy="135.3" r=".51" fill="#000080"/>
<circle cx="116.6" cy="135.3" r=".51" fill="none" stroke="#000080" stroke-width=".13"/>
<path d="M124.2 168.3v2.6h-7.6" fill="none" stroke="#000080" stroke-width=".25"/>
<circle cx="116.6" cy="170.9" r=".51" fill="#000080"/>
<circle cx="116.6" cy="170.9" r=".51" fill="none" stroke="#000080" stroke-width=".13"/>
<path d="M63.2 130.2v2.6h2.6" fill="none" stroke="#000080" stroke-width=".25"/>
<circle cx="63.2" cy="130.2" r=".51" fill="#000080"/>
<circle cx="63.2" cy="130.2" r=".51" fill="none" stroke="#000080" stroke-width=".13"/>
<circle cx="63.2" cy="132.8" r=".51" fill="#000080"/>
<circle cx="63.2" cy="132.8" r=".51" fill="none" stroke="#000080" stroke-width=".13"/>
<path d="M22.6 120.1v2.5h25.4" fill="none" stroke="#000080" stroke-width=".25"/>
<circle cx="48" cy="122.6" r=".51" fill="#000080"/>
<circle cx="48" cy="122.6" r=".51" fill="none" stroke="#000080" stroke-width=".13"/>
<circle cx="37.8" cy="122.6" r=".51" fill="#000080"/>
<circle cx="37.8" cy="122.6" r=".51" fill="none" stroke="#000080" stroke-width=".13"/>
<circle cx="27.6" cy="122.6" r=".51" fill="#000080"/>
<circle cx="27.6" cy="122.6" r=".51" fill="none" stroke="#000080" stroke-width=".13"/>
<path d="M63.2 122.6v2.6" fill="none" stroke="#000080" stroke-width=".25"/>
<circle cx="63.2" cy="122.6" r=".51" fill="#000080"/>
<circle cx="63.2" cy="122.6" r=".51" fill="none" stroke="#000080" stroke-width=".13"/>
<path d="M48 122.6h15.2" fill="none" stroke="#000080" stroke-width=".25"/>
<circle cx="48" cy="122.6" r=".51" fill="#000080"/>
<circle cx="48" cy="122.6" r=".51" fill="none" stroke="#000080" stroke-width=".13"/>
<circle cx="63.2" cy="122.6" r=".51" fill="#000080"/>
<circle cx="63.2" cy="122.6" r=".51" fill="none" stroke="#000080" stroke-width=".13"/>
<path d="M203 132.8v2.5" fill="none" stroke="#000080" stroke-width=".25"/>
<circle cx="203" cy="132.8" r=".51" fill="#000080"/>
<circle cx="203" cy="132.8" r=".51" fill="none" stroke="#000080" stroke-width=".13"/>
<path d="M167.4 132.8h40.7" fill="none" stroke="#000080" stroke-width=".25"/>
<circle cx="203" cy="132.8" r=".51" fill="#000080"/>
<circle cx="203" cy="132.8" r=".51" fill="none" stroke="#000080" stroke-width=".13"/>
<path d="M190.3 125.2v10.1" fill="none" stroke="#000080" stroke-width=".25"/>
<circle cx="190.3" cy="125.2" r=".51" fill="#000080"/>
<circle cx="190.3" cy="125.2" r=".51" fill="none" stroke="#000080" stroke-width=".13"/>
<path d="M157.3 43.9h-53.4v7.6" fill="none" stroke="#000080" stroke-width=".25"/>
<circle cx="103.9" cy="49" r=".51" fill="#000080"/>
<circle cx="103.9" cy="49" r=".51" fill="none" stroke="#000080" stroke-width=".13"/>
<circle cx="103.9" cy="46.4" r=".51" fill="#000080"/>
<circle cx="103.9" cy="46.4" r=".51" fill="none" stroke="#000080" stroke-width=".13"/>
<circle cx="103.9" cy="43.9" r=".51" fill="#000080"/>
<circle cx="103.9" cy="43.9" r=".51" fill="none" stroke="#000080" stroke-width=".13"/>
<circle cx="111.5" cy="43.9" r=".51" fill="#000080"/>
<circle cx="111.5" cy="43.9" r=".51" fill="none" stroke="#000080" stroke-width=".13"/>
<circle cx="119.1" cy="43.9" r=".51" fill="#000080"/>
<circle cx="119.1" cy="43.9" r=".51" fill="none" stroke="#000080" stroke-width=".13"/>
<circle cx="129.3" cy="43.9" r=".51" fill="#000080"/>
<circle cx="129.3" cy="43.9" r=".51" fill="none" stroke="#000080" stroke-width=".13"/>
<circle cx="139.5" cy="43.9" r=".51" fill="#000080"/>
<circle cx="139.5" cy="43.9" r=".51" fill="none" stroke="#000080" stroke-width=".13"/>
<circle cx="149.6" cy="43.9" r=".51" fill="#000080"/>
<circle cx="149.6" cy="43.9" r=".51" fill="none" stroke="#000080" stroke-width=".13"/>
<path d="M172.5 41.4v2.5h-5.1M142 122.6h-33v5.1" fill="none" stroke="#000080" stroke-width=".25"/>
<circle cx="109" cy="125.2" r=".51" fill="#000080"/>
<circle cx="109" cy="125.2" r=".51" fill="none" stroke="#000080" stroke-width=".13"/>
<circle cx="109" cy="122.6" r=".51" fill="#000080"/>
<circle cx="109" cy="122.6" r=".51" fill="none" stroke="#000080" stroke-width=".13"/>
<circle cx="116.6" cy="122.6" r=".51" fill="#000080"/>
<circle cx="116.6" cy="122.6" r=".51" fill="none" stroke="#000080" stroke-width=".13"/>
<circle cx="124.2" cy="122.6" r=".51" fill="#000080"/>
<circle cx="124.2" cy="122.6" r=".51" fill="none" stroke="#000080" stroke-width=".13"/>
<circle cx="134.4" cy="122.6" r=".51" fill="#000080"/>
<circle cx="134.4" cy="122.6" r=".51" fill="none" stroke="#000080" stroke-width=".13"/>
<path d="M157.3 120.1v2.5h-5.1M142 158.2h-33v5.1" fill="none" stroke="#000080" stroke-width=".25"/>
<circle cx="109" cy="160.7" r=".51" fill="#000080"/>
<circle cx="109" cy="160.7" r=".51" fill="none" stroke="#000080" stroke-width=".13"/>
<circle cx="109" cy="158.2" r=".51" fill="#000080"/>
<circle cx="109" cy="158.2" r=".51" fill="none" stroke="#000080" stroke-width=".13"/>
<circle cx="116.6" cy="158.2" r=".51" fill="#000080"/>
<circle cx="116.6" cy="158.2" r=".51" fill="none" stroke="#000080" stroke-width=".13"/>
<circle cx="124.2" cy="158.2" r=".51" fill="#000080"/>
<circle cx="124.2" cy="158.2" r=".51" fill="none" stroke="#000080" stroke-width=".13"/>
<circle cx="134.4" cy="158.2" r=".51" fill="#000080"/>
<circle cx="134.4" cy="158.2" r=".51" fill="none" stroke="#000080" stroke-width=".13"/>
<path d="M261.5 125.2h-17.8v2.5M157.3 155.6v2.6h-5.1" fill="none" stroke="#000080" stroke-width=".25"/>
<circle cx="243.7" cy="125.2" r=".51" fill="#000080"/>
<circle cx="243.7" cy="125.2" r=".51" fill="none" stroke="#000080" stroke-width=".13"/>
<circle cx="253.8" cy="125.2" r=".51" fill="#000080"/>
<circle cx="253.8" cy="125.2" r=".51" fill="none" stroke="#000080" stroke-width=".13"/>
<path d="M261.5 43.9h-17.8v2.5M276.7 122.6v2.6h-5.1" fill="none" stroke="#000080" stroke-width=".25"/>
<circle cx="243.7" cy="43.9" r=".51" fill="#000080"/>
<circle cx="243.7" cy="43.9" r=".51" fill="none" stroke="#000080" stroke-width=".13"/>
<circle cx="253.8" cy="43.9" r=".51" fill="#000080"/>
<circle cx="253.8" cy="43.9" r=".51" fill="none" stroke="#000080" stroke-width=".13"/>
<path d="M276.7 41.4v2.5h-5.1" fill="none" stroke="#000080" stroke-width=".25"/>
<use href="#words"/>
</svg>
